VERSION 5.8 ;
BUSBITCHARS "[]" ;
DIVIDERCHAR "/" ;
UNITS
    DATABASE MICRONS 1000 ;
END UNITS

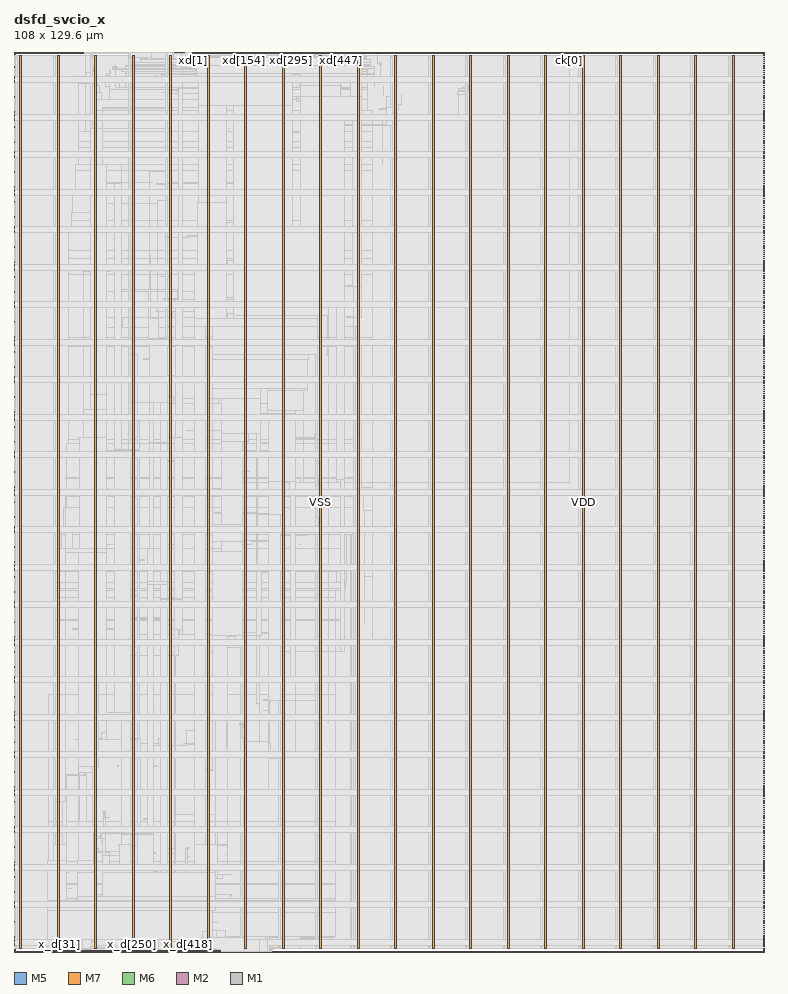
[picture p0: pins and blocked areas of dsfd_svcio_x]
MACRO dsfd_svcio_x
  FOREIGN dsfd_svcio_x 0 0 ;
  CLASS BLOCK ;
  SIZE 108 BY 129.6 ;
  PIN ck[0]
    DIRECTION INPUT ;
    USE SIGNAL ;
    PORT
      LAYER M5 ;
        RECT  79.968 129.408 79.992 129.6 ;
    END
  END ck[0]
  PIN rst[0]
    DIRECTION INPUT ;
    USE SIGNAL ;
    PORT
      LAYER M5 ;
        RECT  81.888 129.408 81.912 129.6 ;
    END
  END rst[0]
  PIN x_d[0]
    DIRECTION INPUT ;
    USE SIGNAL ;
    PORT
      LAYER M5 ;
        RECT  4.992 0 5.016 0.192 ;
    END
  END x_d[0]
  PIN x_d[100]
    DIRECTION INPUT ;
    USE SIGNAL ;
    PORT
      LAYER M5 ;
        RECT  9.792 0 9.816 0.192 ;
    END
  END x_d[100]
  PIN x_d[101]
    DIRECTION INPUT ;
    USE SIGNAL ;
    PORT
      LAYER M5 ;
        RECT  9.84 0 9.864 0.192 ;
    END
  END x_d[101]
  PIN x_d[102]
    DIRECTION INPUT ;
    USE SIGNAL ;
    PORT
      LAYER M5 ;
        RECT  9.888 0 9.912 0.192 ;
    END
  END x_d[102]
  PIN x_d[103]
    DIRECTION INPUT ;
    USE SIGNAL ;
    PORT
      LAYER M5 ;
        RECT  9.936 0 9.96 0.192 ;
    END
  END x_d[103]
  PIN x_d[104]
    DIRECTION INPUT ;
    USE SIGNAL ;
    PORT
      LAYER M5 ;
        RECT  9.984 0 10.008 0.192 ;
    END
  END x_d[104]
  PIN x_d[105]
    DIRECTION INPUT ;
    USE SIGNAL ;
    PORT
      LAYER M5 ;
        RECT  10.032 0 10.056 0.192 ;
    END
  END x_d[105]
  PIN x_d[106]
    DIRECTION INPUT ;
    USE SIGNAL ;
    PORT
      LAYER M5 ;
        RECT  10.08 0 10.104 0.192 ;
    END
  END x_d[106]
  PIN x_d[107]
    DIRECTION INPUT ;
    USE SIGNAL ;
    PORT
      LAYER M5 ;
        RECT  10.128 0 10.152 0.192 ;
    END
  END x_d[107]
  PIN x_d[108]
    DIRECTION INPUT ;
    USE SIGNAL ;
    PORT
      LAYER M5 ;
        RECT  10.176 0 10.2 0.192 ;
    END
  END x_d[108]
  PIN x_d[109]
    DIRECTION INPUT ;
    USE SIGNAL ;
    PORT
      LAYER M5 ;
        RECT  10.224 0 10.248 0.192 ;
    END
  END x_d[109]
  PIN x_d[10]
    DIRECTION INPUT ;
    USE SIGNAL ;
    PORT
      LAYER M5 ;
        RECT  5.472 0 5.496 0.192 ;
    END
  END x_d[10]
  PIN x_d[110]
    DIRECTION INPUT ;
    USE SIGNAL ;
    PORT
      LAYER M5 ;
        RECT  10.272 0 10.296 0.192 ;
    END
  END x_d[110]
  PIN x_d[111]
    DIRECTION INPUT ;
    USE SIGNAL ;
    PORT
      LAYER M5 ;
        RECT  10.32 0 10.344 0.192 ;
    END
  END x_d[111]
  PIN x_d[112]
    DIRECTION INPUT ;
    USE SIGNAL ;
    PORT
      LAYER M5 ;
        RECT  10.368 0 10.392 0.192 ;
    END
  END x_d[112]
  PIN x_d[113]
    DIRECTION INPUT ;
    USE SIGNAL ;
    PORT
      LAYER M5 ;
        RECT  10.416 0 10.44 0.192 ;
    END
  END x_d[113]
  PIN x_d[114]
    DIRECTION INPUT ;
    USE SIGNAL ;
    PORT
      LAYER M5 ;
        RECT  10.464 0 10.488 0.192 ;
    END
  END x_d[114]
  PIN x_d[115]
    DIRECTION INPUT ;
    USE SIGNAL ;
    PORT
      LAYER M5 ;
        RECT  10.512 0 10.536 0.192 ;
    END
  END x_d[115]
  PIN x_d[116]
    DIRECTION INPUT ;
    USE SIGNAL ;
    PORT
      LAYER M5 ;
        RECT  10.56 0 10.584 0.192 ;
    END
  END x_d[116]
  PIN x_d[117]
    DIRECTION INPUT ;
    USE SIGNAL ;
    PORT
      LAYER M5 ;
        RECT  10.608 0 10.632 0.192 ;
    END
  END x_d[117]
  PIN x_d[118]
    DIRECTION INPUT ;
    USE SIGNAL ;
    PORT
      LAYER M5 ;
        RECT  10.656 0 10.68 0.192 ;
    END
  END x_d[118]
  PIN x_d[119]
    DIRECTION INPUT ;
    USE SIGNAL ;
    PORT
      LAYER M5 ;
        RECT  10.704 0 10.728 0.192 ;
    END
  END x_d[119]
  PIN x_d[11]
    DIRECTION INPUT ;
    USE SIGNAL ;
    PORT
      LAYER M5 ;
        RECT  5.52 0 5.544 0.192 ;
    END
  END x_d[11]
  PIN x_d[120]
    DIRECTION INPUT ;
    USE SIGNAL ;
    PORT
      LAYER M5 ;
        RECT  10.752 0 10.776 0.192 ;
    END
  END x_d[120]
  PIN x_d[121]
    DIRECTION INPUT ;
    USE SIGNAL ;
    PORT
      LAYER M5 ;
        RECT  10.8 0 10.824 0.192 ;
    END
  END x_d[121]
  PIN x_d[122]
    DIRECTION INPUT ;
    USE SIGNAL ;
    PORT
      LAYER M5 ;
        RECT  10.848 0 10.872 0.192 ;
    END
  END x_d[122]
  PIN x_d[123]
    DIRECTION INPUT ;
    USE SIGNAL ;
    PORT
      LAYER M5 ;
        RECT  10.896 0 10.92 0.192 ;
    END
  END x_d[123]
  PIN x_d[124]
    DIRECTION INPUT ;
    USE SIGNAL ;
    PORT
      LAYER M5 ;
        RECT  10.944 0 10.968 0.192 ;
    END
  END x_d[124]
  PIN x_d[125]
    DIRECTION INPUT ;
    USE SIGNAL ;
    PORT
      LAYER M5 ;
        RECT  10.992 0 11.016 0.192 ;
    END
  END x_d[125]
  PIN x_d[126]
    DIRECTION INPUT ;
    USE SIGNAL ;
    PORT
      LAYER M5 ;
        RECT  11.04 0 11.064 0.192 ;
    END
  END x_d[126]
  PIN x_d[127]
    DIRECTION INPUT ;
    USE SIGNAL ;
    PORT
      LAYER M5 ;
        RECT  11.088 0 11.112 0.192 ;
    END
  END x_d[127]
  PIN x_d[128]
    DIRECTION INPUT ;
    USE SIGNAL ;
    PORT
      LAYER M5 ;
        RECT  11.136 0 11.16 0.192 ;
    END
  END x_d[128]
  PIN x_d[129]
    DIRECTION INPUT ;
    USE SIGNAL ;
    PORT
      LAYER M5 ;
        RECT  11.184 0 11.208 0.192 ;
    END
  END x_d[129]
  PIN x_d[12]
    DIRECTION INPUT ;
    USE SIGNAL ;
    PORT
      LAYER M5 ;
        RECT  5.568 0 5.592 0.192 ;
    END
  END x_d[12]
  PIN x_d[130]
    DIRECTION INPUT ;
    USE SIGNAL ;
    PORT
      LAYER M5 ;
        RECT  11.232 0 11.256 0.192 ;
    END
  END x_d[130]
  PIN x_d[131]
    DIRECTION INPUT ;
    USE SIGNAL ;
    PORT
      LAYER M5 ;
        RECT  11.28 0 11.304 0.192 ;
    END
  END x_d[131]
  PIN x_d[132]
    DIRECTION INPUT ;
    USE SIGNAL ;
    PORT
      LAYER M5 ;
        RECT  11.328 0 11.352 0.192 ;
    END
  END x_d[132]
  PIN x_d[133]
    DIRECTION INPUT ;
    USE SIGNAL ;
    PORT
      LAYER M5 ;
        RECT  11.376 0 11.4 0.192 ;
    END
  END x_d[133]
  PIN x_d[134]
    DIRECTION INPUT ;
    USE SIGNAL ;
    PORT
      LAYER M5 ;
        RECT  11.424 0 11.448 0.192 ;
    END
  END x_d[134]
  PIN x_d[135]
    DIRECTION INPUT ;
    USE SIGNAL ;
    PORT
      LAYER M5 ;
        RECT  11.472 0 11.496 0.192 ;
    END
  END x_d[135]
  PIN x_d[136]
    DIRECTION INPUT ;
    USE SIGNAL ;
    PORT
      LAYER M5 ;
        RECT  11.52 0 11.544 0.192 ;
    END
  END x_d[136]
  PIN x_d[137]
    DIRECTION INPUT ;
    USE SIGNAL ;
    PORT
      LAYER M5 ;
        RECT  11.568 0 11.592 0.192 ;
    END
  END x_d[137]
  PIN x_d[138]
    DIRECTION INPUT ;
    USE SIGNAL ;
    PORT
      LAYER M5 ;
        RECT  11.616 0 11.64 0.192 ;
    END
  END x_d[138]
  PIN x_d[139]
    DIRECTION INPUT ;
    USE SIGNAL ;
    PORT
      LAYER M5 ;
        RECT  11.664 0 11.688 0.192 ;
    END
  END x_d[139]
  PIN x_d[13]
    DIRECTION INPUT ;
    USE SIGNAL ;
    PORT
      LAYER M5 ;
        RECT  5.616 0 5.64 0.192 ;
    END
  END x_d[13]
  PIN x_d[140]
    DIRECTION INPUT ;
    USE SIGNAL ;
    PORT
      LAYER M5 ;
        RECT  11.712 0 11.736 0.192 ;
    END
  END x_d[140]
  PIN x_d[141]
    DIRECTION INPUT ;
    USE SIGNAL ;
    PORT
      LAYER M5 ;
        RECT  11.76 0 11.784 0.192 ;
    END
  END x_d[141]
  PIN x_d[142]
    DIRECTION INPUT ;
    USE SIGNAL ;
    PORT
      LAYER M5 ;
        RECT  11.808 0 11.832 0.192 ;
    END
  END x_d[142]
  PIN x_d[143]
    DIRECTION INPUT ;
    USE SIGNAL ;
    PORT
      LAYER M5 ;
        RECT  11.856 0 11.88 0.192 ;
    END
  END x_d[143]
  PIN x_d[144]
    DIRECTION INPUT ;
    USE SIGNAL ;
    PORT
      LAYER M5 ;
        RECT  11.904 0 11.928 0.192 ;
    END
  END x_d[144]
  PIN x_d[145]
    DIRECTION INPUT ;
    USE SIGNAL ;
    PORT
      LAYER M5 ;
        RECT  11.952 0 11.976 0.192 ;
    END
  END x_d[145]
  PIN x_d[146]
    DIRECTION INPUT ;
    USE SIGNAL ;
    PORT
      LAYER M5 ;
        RECT  12 0 12.024 0.192 ;
    END
  END x_d[146]
  PIN x_d[147]
    DIRECTION INPUT ;
    USE SIGNAL ;
    PORT
      LAYER M5 ;
        RECT  12.048 0 12.072 0.192 ;
    END
  END x_d[147]
  PIN x_d[148]
    DIRECTION INPUT ;
    USE SIGNAL ;
    PORT
      LAYER M5 ;
        RECT  12.096 0 12.12 0.192 ;
    END
  END x_d[148]
  PIN x_d[149]
    DIRECTION INPUT ;
    USE SIGNAL ;
    PORT
      LAYER M5 ;
        RECT  12.144 0 12.168 0.192 ;
    END
  END x_d[149]
  PIN x_d[14]
    DIRECTION INPUT ;
    USE SIGNAL ;
    PORT
      LAYER M5 ;
        RECT  5.664 0 5.688 0.192 ;
    END
  END x_d[14]
  PIN x_d[150]
    DIRECTION INPUT ;
    USE SIGNAL ;
    PORT
      LAYER M5 ;
        RECT  12.192 0 12.216 0.192 ;
    END
  END x_d[150]
  PIN x_d[151]
    DIRECTION INPUT ;
    USE SIGNAL ;
    PORT
      LAYER M5 ;
        RECT  12.24 0 12.264 0.192 ;
    END
  END x_d[151]
  PIN x_d[152]
    DIRECTION INPUT ;
    USE SIGNAL ;
    PORT
      LAYER M5 ;
        RECT  12.288 0 12.312 0.192 ;
    END
  END x_d[152]
  PIN x_d[153]
    DIRECTION INPUT ;
    USE SIGNAL ;
    PORT
      LAYER M5 ;
        RECT  12.336 0 12.36 0.192 ;
    END
  END x_d[153]
  PIN x_d[154]
    DIRECTION INPUT ;
    USE SIGNAL ;
    PORT
      LAYER M5 ;
        RECT  12.384 0 12.408 0.192 ;
    END
  END x_d[154]
  PIN x_d[155]
    DIRECTION INPUT ;
    USE SIGNAL ;
    PORT
      LAYER M5 ;
        RECT  12.432 0 12.456 0.192 ;
    END
  END x_d[155]
  PIN x_d[156]
    DIRECTION INPUT ;
    USE SIGNAL ;
    PORT
      LAYER M5 ;
        RECT  12.48 0 12.504 0.192 ;
    END
  END x_d[156]
  PIN x_d[157]
    DIRECTION INPUT ;
    USE SIGNAL ;
    PORT
      LAYER M5 ;
        RECT  12.528 0 12.552 0.192 ;
    END
  END x_d[157]
  PIN x_d[158]
    DIRECTION INPUT ;
    USE SIGNAL ;
    PORT
      LAYER M5 ;
        RECT  12.576 0 12.6 0.192 ;
    END
  END x_d[158]
  PIN x_d[159]
    DIRECTION INPUT ;
    USE SIGNAL ;
    PORT
      LAYER M5 ;
        RECT  12.624 0 12.648 0.192 ;
    END
  END x_d[159]
  PIN x_d[15]
    DIRECTION INPUT ;
    USE SIGNAL ;
    PORT
      LAYER M5 ;
        RECT  5.712 0 5.736 0.192 ;
    END
  END x_d[15]
  PIN x_d[160]
    DIRECTION INPUT ;
    USE SIGNAL ;
    PORT
      LAYER M5 ;
        RECT  12.672 0 12.696 0.192 ;
    END
  END x_d[160]
  PIN x_d[161]
    DIRECTION INPUT ;
    USE SIGNAL ;
    PORT
      LAYER M5 ;
        RECT  12.72 0 12.744 0.192 ;
    END
  END x_d[161]
  PIN x_d[162]
    DIRECTION INPUT ;
    USE SIGNAL ;
    PORT
      LAYER M5 ;
        RECT  12.768 0 12.792 0.192 ;
    END
  END x_d[162]
  PIN x_d[163]
    DIRECTION INPUT ;
    USE SIGNAL ;
    PORT
      LAYER M5 ;
        RECT  12.816 0 12.84 0.192 ;
    END
  END x_d[163]
  PIN x_d[164]
    DIRECTION INPUT ;
    USE SIGNAL ;
    PORT
      LAYER M5 ;
        RECT  12.864 0 12.888 0.192 ;
    END
  END x_d[164]
  PIN x_d[165]
    DIRECTION INPUT ;
    USE SIGNAL ;
    PORT
      LAYER M5 ;
        RECT  12.912 0 12.936 0.192 ;
    END
  END x_d[165]
  PIN x_d[166]
    DIRECTION INPUT ;
    USE SIGNAL ;
    PORT
      LAYER M5 ;
        RECT  12.96 0 12.984 0.192 ;
    END
  END x_d[166]
  PIN x_d[167]
    DIRECTION INPUT ;
    USE SIGNAL ;
    PORT
      LAYER M5 ;
        RECT  13.008 0 13.032 0.192 ;
    END
  END x_d[167]
  PIN x_d[168]
    DIRECTION INPUT ;
    USE SIGNAL ;
    PORT
      LAYER M5 ;
        RECT  13.056 0 13.08 0.192 ;
    END
  END x_d[168]
  PIN x_d[169]
    DIRECTION INPUT ;
    USE SIGNAL ;
    PORT
      LAYER M5 ;
        RECT  13.104 0 13.128 0.192 ;
    END
  END x_d[169]
  PIN x_d[16]
    DIRECTION INPUT ;
    USE SIGNAL ;
    PORT
      LAYER M5 ;
        RECT  5.76 0 5.784 0.192 ;
    END
  END x_d[16]
  PIN x_d[170]
    DIRECTION INPUT ;
    USE SIGNAL ;
    PORT
      LAYER M5 ;
        RECT  13.152 0 13.176 0.192 ;
    END
  END x_d[170]
  PIN x_d[171]
    DIRECTION INPUT ;
    USE SIGNAL ;
    PORT
      LAYER M5 ;
        RECT  13.2 0 13.224 0.192 ;
    END
  END x_d[171]
  PIN x_d[172]
    DIRECTION INPUT ;
    USE SIGNAL ;
    PORT
      LAYER M5 ;
        RECT  13.248 0 13.272 0.192 ;
    END
  END x_d[172]
  PIN x_d[173]
    DIRECTION INPUT ;
    USE SIGNAL ;
    PORT
      LAYER M5 ;
        RECT  13.296 0 13.32 0.192 ;
    END
  END x_d[173]
  PIN x_d[174]
    DIRECTION INPUT ;
    USE SIGNAL ;
    PORT
      LAYER M5 ;
        RECT  13.344 0 13.368 0.192 ;
    END
  END x_d[174]
  PIN x_d[175]
    DIRECTION INPUT ;
    USE SIGNAL ;
    PORT
      LAYER M5 ;
        RECT  13.392 0 13.416 0.192 ;
    END
  END x_d[175]
  PIN x_d[176]
    DIRECTION INPUT ;
    USE SIGNAL ;
    PORT
      LAYER M5 ;
        RECT  13.44 0 13.464 0.192 ;
    END
  END x_d[176]
  PIN x_d[177]
    DIRECTION INPUT ;
    USE SIGNAL ;
    PORT
      LAYER M5 ;
        RECT  13.488 0 13.512 0.192 ;
    END
  END x_d[177]
  PIN x_d[178]
    DIRECTION INPUT ;
    USE SIGNAL ;
    PORT
      LAYER M5 ;
        RECT  13.536 0 13.56 0.192 ;
    END
  END x_d[178]
  PIN x_d[179]
    DIRECTION INPUT ;
    USE SIGNAL ;
    PORT
      LAYER M5 ;
        RECT  13.584 0 13.608 0.192 ;
    END
  END x_d[179]
  PIN x_d[17]
    DIRECTION INPUT ;
    USE SIGNAL ;
    PORT
      LAYER M5 ;
        RECT  5.808 0 5.832 0.192 ;
    END
  END x_d[17]
  PIN x_d[180]
    DIRECTION INPUT ;
    USE SIGNAL ;
    PORT
      LAYER M5 ;
        RECT  13.632 0 13.656 0.192 ;
    END
  END x_d[180]
  PIN x_d[181]
    DIRECTION INPUT ;
    USE SIGNAL ;
    PORT
      LAYER M5 ;
        RECT  13.68 0 13.704 0.192 ;
    END
  END x_d[181]
  PIN x_d[182]
    DIRECTION INPUT ;
    USE SIGNAL ;
    PORT
      LAYER M5 ;
        RECT  13.728 0 13.752 0.192 ;
    END
  END x_d[182]
  PIN x_d[183]
    DIRECTION INPUT ;
    USE SIGNAL ;
    PORT
      LAYER M5 ;
        RECT  13.776 0 13.8 0.192 ;
    END
  END x_d[183]
  PIN x_d[184]
    DIRECTION INPUT ;
    USE SIGNAL ;
    PORT
      LAYER M5 ;
        RECT  13.824 0 13.848 0.192 ;
    END
  END x_d[184]
  PIN x_d[185]
    DIRECTION INPUT ;
    USE SIGNAL ;
    PORT
      LAYER M5 ;
        RECT  13.872 0 13.896 0.192 ;
    END
  END x_d[185]
  PIN x_d[186]
    DIRECTION INPUT ;
    USE SIGNAL ;
    PORT
      LAYER M5 ;
        RECT  13.92 0 13.944 0.192 ;
    END
  END x_d[186]
  PIN x_d[187]
    DIRECTION INPUT ;
    USE SIGNAL ;
    PORT
      LAYER M5 ;
        RECT  13.968 0 13.992 0.192 ;
    END
  END x_d[187]
  PIN x_d[188]
    DIRECTION INPUT ;
    USE SIGNAL ;
    PORT
      LAYER M5 ;
        RECT  14.016 0 14.04 0.192 ;
    END
  END x_d[188]
  PIN x_d[189]
    DIRECTION INPUT ;
    USE SIGNAL ;
    PORT
      LAYER M5 ;
        RECT  14.064 0 14.088 0.192 ;
    END
  END x_d[189]
  PIN x_d[18]
    DIRECTION INPUT ;
    USE SIGNAL ;
    PORT
      LAYER M5 ;
        RECT  5.856 0 5.88 0.192 ;
    END
  END x_d[18]
  PIN x_d[190]
    DIRECTION INPUT ;
    USE SIGNAL ;
    PORT
      LAYER M5 ;
        RECT  14.112 0 14.136 0.192 ;
    END
  END x_d[190]
  PIN x_d[191]
    DIRECTION INPUT ;
    USE SIGNAL ;
    PORT
      LAYER M5 ;
        RECT  14.16 0 14.184 0.192 ;
    END
  END x_d[191]
  PIN x_d[192]
    DIRECTION INPUT ;
    USE SIGNAL ;
    PORT
      LAYER M5 ;
        RECT  14.208 0 14.232 0.192 ;
    END
  END x_d[192]
  PIN x_d[193]
    DIRECTION INPUT ;
    USE SIGNAL ;
    PORT
      LAYER M5 ;
        RECT  14.256 0 14.28 0.192 ;
    END
  END x_d[193]
  PIN x_d[194]
    DIRECTION INPUT ;
    USE SIGNAL ;
    PORT
      LAYER M5 ;
        RECT  14.304 0 14.328 0.192 ;
    END
  END x_d[194]
  PIN x_d[195]
    DIRECTION INPUT ;
    USE SIGNAL ;
    PORT
      LAYER M5 ;
        RECT  14.352 0 14.376 0.192 ;
    END
  END x_d[195]
  PIN x_d[196]
    DIRECTION INPUT ;
    USE SIGNAL ;
    PORT
      LAYER M5 ;
        RECT  14.4 0 14.424 0.192 ;
    END
  END x_d[196]
  PIN x_d[197]
    DIRECTION INPUT ;
    USE SIGNAL ;
    PORT
      LAYER M5 ;
        RECT  14.448 0 14.472 0.192 ;
    END
  END x_d[197]
  PIN x_d[198]
    DIRECTION INPUT ;
    USE SIGNAL ;
    PORT
      LAYER M5 ;
        RECT  14.496 0 14.52 0.192 ;
    END
  END x_d[198]
  PIN x_d[199]
    DIRECTION INPUT ;
    USE SIGNAL ;
    PORT
      LAYER M5 ;
        RECT  14.544 0 14.568 0.192 ;
    END
  END x_d[199]
  PIN x_d[19]
    DIRECTION INPUT ;
    USE SIGNAL ;
    PORT
      LAYER M5 ;
        RECT  5.904 0 5.928 0.192 ;
    END
  END x_d[19]
  PIN x_d[1]
    DIRECTION INPUT ;
    USE SIGNAL ;
    PORT
      LAYER M5 ;
        RECT  5.04 0 5.064 0.192 ;
    END
  END x_d[1]
  PIN x_d[200]
    DIRECTION INPUT ;
    USE SIGNAL ;
    PORT
      LAYER M5 ;
        RECT  14.592 0 14.616 0.192 ;
    END
  END x_d[200]
  PIN x_d[201]
    DIRECTION INPUT ;
    USE SIGNAL ;
    PORT
      LAYER M5 ;
        RECT  14.64 0 14.664 0.192 ;
    END
  END x_d[201]
  PIN x_d[202]
    DIRECTION INPUT ;
    USE SIGNAL ;
    PORT
      LAYER M5 ;
        RECT  14.688 0 14.712 0.192 ;
    END
  END x_d[202]
  PIN x_d[203]
    DIRECTION INPUT ;
    USE SIGNAL ;
    PORT
      LAYER M5 ;
        RECT  14.736 0 14.76 0.192 ;
    END
  END x_d[203]
  PIN x_d[204]
    DIRECTION INPUT ;
    USE SIGNAL ;
    PORT
      LAYER M5 ;
        RECT  14.784 0 14.808 0.192 ;
    END
  END x_d[204]
  PIN x_d[205]
    DIRECTION INPUT ;
    USE SIGNAL ;
    PORT
      LAYER M5 ;
        RECT  14.832 0 14.856 0.192 ;
    END
  END x_d[205]
  PIN x_d[206]
    DIRECTION INPUT ;
    USE SIGNAL ;
    PORT
      LAYER M5 ;
        RECT  14.88 0 14.904 0.192 ;
    END
  END x_d[206]
  PIN x_d[207]
    DIRECTION INPUT ;
    USE SIGNAL ;
    PORT
      LAYER M5 ;
        RECT  14.928 0 14.952 0.192 ;
    END
  END x_d[207]
  PIN x_d[208]
    DIRECTION INPUT ;
    USE SIGNAL ;
    PORT
      LAYER M5 ;
        RECT  14.976 0 15 0.192 ;
    END
  END x_d[208]
  PIN x_d[209]
    DIRECTION INPUT ;
    USE SIGNAL ;
    PORT
      LAYER M5 ;
        RECT  15.024 0 15.048 0.192 ;
    END
  END x_d[209]
  PIN x_d[20]
    DIRECTION INPUT ;
    USE SIGNAL ;
    PORT
      LAYER M5 ;
        RECT  5.952 0 5.976 0.192 ;
    END
  END x_d[20]
  PIN x_d[210]
    DIRECTION INPUT ;
    USE SIGNAL ;
    PORT
      LAYER M5 ;
        RECT  15.072 0 15.096 0.192 ;
    END
  END x_d[210]
  PIN x_d[211]
    DIRECTION INPUT ;
    USE SIGNAL ;
    PORT
      LAYER M5 ;
        RECT  15.12 0 15.144 0.192 ;
    END
  END x_d[211]
  PIN x_d[212]
    DIRECTION INPUT ;
    USE SIGNAL ;
    PORT
      LAYER M5 ;
        RECT  15.168 0 15.192 0.192 ;
    END
  END x_d[212]
  PIN x_d[213]
    DIRECTION INPUT ;
    USE SIGNAL ;
    PORT
      LAYER M5 ;
        RECT  15.216 0 15.24 0.192 ;
    END
  END x_d[213]
  PIN x_d[214]
    DIRECTION INPUT ;
    USE SIGNAL ;
    PORT
      LAYER M5 ;
        RECT  15.264 0 15.288 0.192 ;
    END
  END x_d[214]
  PIN x_d[215]
    DIRECTION INPUT ;
    USE SIGNAL ;
    PORT
      LAYER M5 ;
        RECT  15.312 0 15.336 0.192 ;
    END
  END x_d[215]
  PIN x_d[216]
    DIRECTION INPUT ;
    USE SIGNAL ;
    PORT
      LAYER M5 ;
        RECT  15.36 0 15.384 0.192 ;
    END
  END x_d[216]
  PIN x_d[217]
    DIRECTION INPUT ;
    USE SIGNAL ;
    PORT
      LAYER M5 ;
        RECT  15.408 0 15.432 0.192 ;
    END
  END x_d[217]
  PIN x_d[218]
    DIRECTION INPUT ;
    USE SIGNAL ;
    PORT
      LAYER M5 ;
        RECT  15.456 0 15.48 0.192 ;
    END
  END x_d[218]
  PIN x_d[219]
    DIRECTION INPUT ;
    USE SIGNAL ;
    PORT
      LAYER M5 ;
        RECT  15.504 0 15.528 0.192 ;
    END
  END x_d[219]
  PIN x_d[21]
    DIRECTION INPUT ;
    USE SIGNAL ;
    PORT
      LAYER M5 ;
        RECT  6 0 6.024 0.192 ;
    END
  END x_d[21]
  PIN x_d[220]
    DIRECTION INPUT ;
    USE SIGNAL ;
    PORT
      LAYER M5 ;
        RECT  15.552 0 15.576 0.192 ;
    END
  END x_d[220]
  PIN x_d[221]
    DIRECTION INPUT ;
    USE SIGNAL ;
    PORT
      LAYER M5 ;
        RECT  15.6 0 15.624 0.192 ;
    END
  END x_d[221]
  PIN x_d[222]
    DIRECTION INPUT ;
    USE SIGNAL ;
    PORT
      LAYER M5 ;
        RECT  15.648 0 15.672 0.192 ;
    END
  END x_d[222]
  PIN x_d[223]
    DIRECTION INPUT ;
    USE SIGNAL ;
    PORT
      LAYER M5 ;
        RECT  15.696 0 15.72 0.192 ;
    END
  END x_d[223]
  PIN x_d[224]
    DIRECTION INPUT ;
    USE SIGNAL ;
    PORT
      LAYER M5 ;
        RECT  15.744 0 15.768 0.192 ;
    END
  END x_d[224]
  PIN x_d[225]
    DIRECTION INPUT ;
    USE SIGNAL ;
    PORT
      LAYER M5 ;
        RECT  15.792 0 15.816 0.192 ;
    END
  END x_d[225]
  PIN x_d[226]
    DIRECTION INPUT ;
    USE SIGNAL ;
    PORT
      LAYER M5 ;
        RECT  15.84 0 15.864 0.192 ;
    END
  END x_d[226]
  PIN x_d[227]
    DIRECTION INPUT ;
    USE SIGNAL ;
    PORT
      LAYER M5 ;
        RECT  15.888 0 15.912 0.192 ;
    END
  END x_d[227]
  PIN x_d[228]
    DIRECTION INPUT ;
    USE SIGNAL ;
    PORT
      LAYER M5 ;
        RECT  15.936 0 15.96 0.192 ;
    END
  END x_d[228]
  PIN x_d[229]
    DIRECTION INPUT ;
    USE SIGNAL ;
    PORT
      LAYER M5 ;
        RECT  15.984 0 16.008 0.192 ;
    END
  END x_d[229]
  PIN x_d[22]
    DIRECTION INPUT ;
    USE SIGNAL ;
    PORT
      LAYER M5 ;
        RECT  6.048 0 6.072 0.192 ;
    END
  END x_d[22]
  PIN x_d[230]
    DIRECTION INPUT ;
    USE SIGNAL ;
    PORT
      LAYER M5 ;
        RECT  16.032 0 16.056 0.192 ;
    END
  END x_d[230]
  PIN x_d[231]
    DIRECTION INPUT ;
    USE SIGNAL ;
    PORT
      LAYER M5 ;
        RECT  16.08 0 16.104 0.192 ;
    END
  END x_d[231]
  PIN x_d[232]
    DIRECTION INPUT ;
    USE SIGNAL ;
    PORT
      LAYER M5 ;
        RECT  16.128 0 16.152 0.192 ;
    END
  END x_d[232]
  PIN x_d[233]
    DIRECTION INPUT ;
    USE SIGNAL ;
    PORT
      LAYER M5 ;
        RECT  16.176 0 16.2 0.192 ;
    END
  END x_d[233]
  PIN x_d[234]
    DIRECTION INPUT ;
    USE SIGNAL ;
    PORT
      LAYER M5 ;
        RECT  16.224 0 16.248 0.192 ;
    END
  END x_d[234]
  PIN x_d[235]
    DIRECTION INPUT ;
    USE SIGNAL ;
    PORT
      LAYER M5 ;
        RECT  16.272 0 16.296 0.192 ;
    END
  END x_d[235]
  PIN x_d[236]
    DIRECTION INPUT ;
    USE SIGNAL ;
    PORT
      LAYER M5 ;
        RECT  16.32 0 16.344 0.192 ;
    END
  END x_d[236]
  PIN x_d[237]
    DIRECTION INPUT ;
    USE SIGNAL ;
    PORT
      LAYER M5 ;
        RECT  16.368 0 16.392 0.192 ;
    END
  END x_d[237]
  PIN x_d[238]
    DIRECTION INPUT ;
    USE SIGNAL ;
    PORT
      LAYER M5 ;
        RECT  16.416 0 16.44 0.192 ;
    END
  END x_d[238]
  PIN x_d[239]
    DIRECTION INPUT ;
    USE SIGNAL ;
    PORT
      LAYER M5 ;
        RECT  16.464 0 16.488 0.192 ;
    END
  END x_d[239]
  PIN x_d[23]
    DIRECTION INPUT ;
    USE SIGNAL ;
    PORT
      LAYER M5 ;
        RECT  6.096 0 6.12 0.192 ;
    END
  END x_d[23]
  PIN x_d[240]
    DIRECTION INPUT ;
    USE SIGNAL ;
    PORT
      LAYER M5 ;
        RECT  16.512 0 16.536 0.192 ;
    END
  END x_d[240]
  PIN x_d[241]
    DIRECTION INPUT ;
    USE SIGNAL ;
    PORT
      LAYER M5 ;
        RECT  16.56 0 16.584 0.192 ;
    END
  END x_d[241]
  PIN x_d[242]
    DIRECTION INPUT ;
    USE SIGNAL ;
    PORT
      LAYER M5 ;
        RECT  16.608 0 16.632 0.192 ;
    END
  END x_d[242]
  PIN x_d[243]
    DIRECTION INPUT ;
    USE SIGNAL ;
    PORT
      LAYER M5 ;
        RECT  16.656 0 16.68 0.192 ;
    END
  END x_d[243]
  PIN x_d[244]
    DIRECTION INPUT ;
    USE SIGNAL ;
    PORT
      LAYER M5 ;
        RECT  16.704 0 16.728 0.192 ;
    END
  END x_d[244]
  PIN x_d[245]
    DIRECTION INPUT ;
    USE SIGNAL ;
    PORT
      LAYER M5 ;
        RECT  16.752 0 16.776 0.192 ;
    END
  END x_d[245]
  PIN x_d[246]
    DIRECTION INPUT ;
    USE SIGNAL ;
    PORT
      LAYER M5 ;
        RECT  16.8 0 16.824 0.192 ;
    END
  END x_d[246]
  PIN x_d[247]
    DIRECTION INPUT ;
    USE SIGNAL ;
    PORT
      LAYER M5 ;
        RECT  16.848 0 16.872 0.192 ;
    END
  END x_d[247]
  PIN x_d[248]
    DIRECTION INPUT ;
    USE SIGNAL ;
    PORT
      LAYER M5 ;
        RECT  16.896 0 16.92 0.192 ;
    END
  END x_d[248]
  PIN x_d[249]
    DIRECTION INPUT ;
    USE SIGNAL ;
    PORT
      LAYER M5 ;
        RECT  16.944 0 16.968 0.192 ;
    END
  END x_d[249]
  PIN x_d[24]
    DIRECTION INPUT ;
    USE SIGNAL ;
    PORT
      LAYER M5 ;
        RECT  6.144 0 6.168 0.192 ;
    END
  END x_d[24]
  PIN x_d[250]
    DIRECTION INPUT ;
    USE SIGNAL ;
    PORT
      LAYER M5 ;
        RECT  16.992 0 17.016 0.192 ;
    END
  END x_d[250]
  PIN x_d[251]
    DIRECTION INPUT ;
    USE SIGNAL ;
    PORT
      LAYER M5 ;
        RECT  17.04 0 17.064 0.192 ;
    END
  END x_d[251]
  PIN x_d[252]
    DIRECTION INPUT ;
    USE SIGNAL ;
    PORT
      LAYER M5 ;
        RECT  17.088 0 17.112 0.192 ;
    END
  END x_d[252]
  PIN x_d[253]
    DIRECTION INPUT ;
    USE SIGNAL ;
    PORT
      LAYER M5 ;
        RECT  17.136 0 17.16 0.192 ;
    END
  END x_d[253]
  PIN x_d[254]
    DIRECTION INPUT ;
    USE SIGNAL ;
    PORT
      LAYER M5 ;
        RECT  17.184 0 17.208 0.192 ;
    END
  END x_d[254]
  PIN x_d[255]
    DIRECTION INPUT ;
    USE SIGNAL ;
    PORT
      LAYER M5 ;
        RECT  17.232 0 17.256 0.192 ;
    END
  END x_d[255]
  PIN x_d[256]
    DIRECTION INPUT ;
    USE SIGNAL ;
    PORT
      LAYER M5 ;
        RECT  17.28 0 17.304 0.192 ;
    END
  END x_d[256]
  PIN x_d[257]
    DIRECTION INPUT ;
    USE SIGNAL ;
    PORT
      LAYER M5 ;
        RECT  17.328 0 17.352 0.192 ;
    END
  END x_d[257]
  PIN x_d[258]
    DIRECTION INPUT ;
    USE SIGNAL ;
    PORT
      LAYER M5 ;
        RECT  17.376 0 17.4 0.192 ;
    END
  END x_d[258]
  PIN x_d[259]
    DIRECTION INPUT ;
    USE SIGNAL ;
    PORT
      LAYER M5 ;
        RECT  17.424 0 17.448 0.192 ;
    END
  END x_d[259]
  PIN x_d[25]
    DIRECTION INPUT ;
    USE SIGNAL ;
    PORT
      LAYER M5 ;
        RECT  6.192 0 6.216 0.192 ;
    END
  END x_d[25]
  PIN x_d[260]
    DIRECTION INPUT ;
    USE SIGNAL ;
    PORT
      LAYER M5 ;
        RECT  17.472 0 17.496 0.192 ;
    END
  END x_d[260]
  PIN x_d[261]
    DIRECTION INPUT ;
    USE SIGNAL ;
    PORT
      LAYER M5 ;
        RECT  17.52 0 17.544 0.192 ;
    END
  END x_d[261]
  PIN x_d[262]
    DIRECTION INPUT ;
    USE SIGNAL ;
    PORT
      LAYER M5 ;
        RECT  17.568 0 17.592 0.192 ;
    END
  END x_d[262]
  PIN x_d[263]
    DIRECTION INPUT ;
    USE SIGNAL ;
    PORT
      LAYER M5 ;
        RECT  17.616 0 17.64 0.192 ;
    END
  END x_d[263]
  PIN x_d[264]
    DIRECTION INPUT ;
    USE SIGNAL ;
    PORT
      LAYER M5 ;
        RECT  17.664 0 17.688 0.192 ;
    END
  END x_d[264]
  PIN x_d[265]
    DIRECTION INPUT ;
    USE SIGNAL ;
    PORT
      LAYER M5 ;
        RECT  17.712 0 17.736 0.192 ;
    END
  END x_d[265]
  PIN x_d[266]
    DIRECTION INPUT ;
    USE SIGNAL ;
    PORT
      LAYER M5 ;
        RECT  17.76 0 17.784 0.192 ;
    END
  END x_d[266]
  PIN x_d[267]
    DIRECTION INPUT ;
    USE SIGNAL ;
    PORT
      LAYER M5 ;
        RECT  17.808 0 17.832 0.192 ;
    END
  END x_d[267]
  PIN x_d[268]
    DIRECTION INPUT ;
    USE SIGNAL ;
    PORT
      LAYER M5 ;
        RECT  17.856 0 17.88 0.192 ;
    END
  END x_d[268]
  PIN x_d[269]
    DIRECTION INPUT ;
    USE SIGNAL ;
    PORT
      LAYER M5 ;
        RECT  17.904 0 17.928 0.192 ;
    END
  END x_d[269]
  PIN x_d[26]
    DIRECTION INPUT ;
    USE SIGNAL ;
    PORT
      LAYER M5 ;
        RECT  6.24 0 6.264 0.192 ;
    END
  END x_d[26]
  PIN x_d[270]
    DIRECTION INPUT ;
    USE SIGNAL ;
    PORT
      LAYER M5 ;
        RECT  17.952 0 17.976 0.192 ;
    END
  END x_d[270]
  PIN x_d[271]
    DIRECTION INPUT ;
    USE SIGNAL ;
    PORT
      LAYER M5 ;
        RECT  18 0 18.024 0.192 ;
    END
  END x_d[271]
  PIN x_d[272]
    DIRECTION INPUT ;
    USE SIGNAL ;
    PORT
      LAYER M5 ;
        RECT  18.048 0 18.072 0.192 ;
    END
  END x_d[272]
  PIN x_d[273]
    DIRECTION INPUT ;
    USE SIGNAL ;
    PORT
      LAYER M5 ;
        RECT  18.096 0 18.12 0.192 ;
    END
  END x_d[273]
  PIN x_d[274]
    DIRECTION INPUT ;
    USE SIGNAL ;
    PORT
      LAYER M5 ;
        RECT  18.144 0 18.168 0.192 ;
    END
  END x_d[274]
  PIN x_d[275]
    DIRECTION INPUT ;
    USE SIGNAL ;
    PORT
      LAYER M5 ;
        RECT  18.192 0 18.216 0.192 ;
    END
  END x_d[275]
  PIN x_d[276]
    DIRECTION INPUT ;
    USE SIGNAL ;
    PORT
      LAYER M5 ;
        RECT  18.24 0 18.264 0.192 ;
    END
  END x_d[276]
  PIN x_d[277]
    DIRECTION INPUT ;
    USE SIGNAL ;
    PORT
      LAYER M5 ;
        RECT  18.288 0 18.312 0.192 ;
    END
  END x_d[277]
  PIN x_d[278]
    DIRECTION INPUT ;
    USE SIGNAL ;
    PORT
      LAYER M5 ;
        RECT  18.336 0 18.36 0.192 ;
    END
  END x_d[278]
  PIN x_d[279]
    DIRECTION INPUT ;
    USE SIGNAL ;
    PORT
      LAYER M5 ;
        RECT  18.384 0 18.408 0.192 ;
    END
  END x_d[279]
  PIN x_d[27]
    DIRECTION INPUT ;
    USE SIGNAL ;
    PORT
      LAYER M5 ;
        RECT  6.288 0 6.312 0.192 ;
    END
  END x_d[27]
  PIN x_d[280]
    DIRECTION INPUT ;
    USE SIGNAL ;
    PORT
      LAYER M5 ;
        RECT  18.432 0 18.456 0.192 ;
    END
  END x_d[280]
  PIN x_d[281]
    DIRECTION INPUT ;
    USE SIGNAL ;
    PORT
      LAYER M5 ;
        RECT  18.48 0 18.504 0.192 ;
    END
  END x_d[281]
  PIN x_d[282]
    DIRECTION INPUT ;
    USE SIGNAL ;
    PORT
      LAYER M5 ;
        RECT  18.528 0 18.552 0.192 ;
    END
  END x_d[282]
  PIN x_d[283]
    DIRECTION INPUT ;
    USE SIGNAL ;
    PORT
      LAYER M5 ;
        RECT  18.576 0 18.6 0.192 ;
    END
  END x_d[283]
  PIN x_d[284]
    DIRECTION INPUT ;
    USE SIGNAL ;
    PORT
      LAYER M5 ;
        RECT  18.624 0 18.648 0.192 ;
    END
  END x_d[284]
  PIN x_d[285]
    DIRECTION INPUT ;
    USE SIGNAL ;
    PORT
      LAYER M5 ;
        RECT  18.672 0 18.696 0.192 ;
    END
  END x_d[285]
  PIN x_d[286]
    DIRECTION INPUT ;
    USE SIGNAL ;
    PORT
      LAYER M5 ;
        RECT  18.72 0 18.744 0.192 ;
    END
  END x_d[286]
  PIN x_d[287]
    DIRECTION INPUT ;
    USE SIGNAL ;
    PORT
      LAYER M5 ;
        RECT  18.768 0 18.792 0.192 ;
    END
  END x_d[287]
  PIN x_d[288]
    DIRECTION INPUT ;
    USE SIGNAL ;
    PORT
      LAYER M5 ;
        RECT  18.816 0 18.84 0.192 ;
    END
  END x_d[288]
  PIN x_d[289]
    DIRECTION INPUT ;
    USE SIGNAL ;
    PORT
      LAYER M5 ;
        RECT  18.864 0 18.888 0.192 ;
    END
  END x_d[289]
  PIN x_d[28]
    DIRECTION INPUT ;
    USE SIGNAL ;
    PORT
      LAYER M5 ;
        RECT  6.336 0 6.36 0.192 ;
    END
  END x_d[28]
  PIN x_d[290]
    DIRECTION INPUT ;
    USE SIGNAL ;
    PORT
      LAYER M5 ;
        RECT  18.912 0 18.936 0.192 ;
    END
  END x_d[290]
  PIN x_d[291]
    DIRECTION INPUT ;
    USE SIGNAL ;
    PORT
      LAYER M5 ;
        RECT  18.96 0 18.984 0.192 ;
    END
  END x_d[291]
  PIN x_d[292]
    DIRECTION INPUT ;
    USE SIGNAL ;
    PORT
      LAYER M5 ;
        RECT  19.008 0 19.032 0.192 ;
    END
  END x_d[292]
  PIN x_d[293]
    DIRECTION INPUT ;
    USE SIGNAL ;
    PORT
      LAYER M5 ;
        RECT  19.056 0 19.08 0.192 ;
    END
  END x_d[293]
  PIN x_d[294]
    DIRECTION INPUT ;
    USE SIGNAL ;
    PORT
      LAYER M5 ;
        RECT  19.104 0 19.128 0.192 ;
    END
  END x_d[294]
  PIN x_d[295]
    DIRECTION INPUT ;
    USE SIGNAL ;
    PORT
      LAYER M5 ;
        RECT  19.152 0 19.176 0.192 ;
    END
  END x_d[295]
  PIN x_d[296]
    DIRECTION INPUT ;
    USE SIGNAL ;
    PORT
      LAYER M5 ;
        RECT  19.2 0 19.224 0.192 ;
    END
  END x_d[296]
  PIN x_d[297]
    DIRECTION INPUT ;
    USE SIGNAL ;
    PORT
      LAYER M5 ;
        RECT  19.248 0 19.272 0.192 ;
    END
  END x_d[297]
  PIN x_d[298]
    DIRECTION INPUT ;
    USE SIGNAL ;
    PORT
      LAYER M5 ;
        RECT  19.296 0 19.32 0.192 ;
    END
  END x_d[298]
  PIN x_d[299]
    DIRECTION INPUT ;
    USE SIGNAL ;
    PORT
      LAYER M5 ;
        RECT  19.344 0 19.368 0.192 ;
    END
  END x_d[299]
  PIN x_d[29]
    DIRECTION INPUT ;
    USE SIGNAL ;
    PORT
      LAYER M5 ;
        RECT  6.384 0 6.408 0.192 ;
    END
  END x_d[29]
  PIN x_d[2]
    DIRECTION INPUT ;
    USE SIGNAL ;
    PORT
      LAYER M5 ;
        RECT  5.088 0 5.112 0.192 ;
    END
  END x_d[2]
  PIN x_d[300]
    DIRECTION INPUT ;
    USE SIGNAL ;
    PORT
      LAYER M5 ;
        RECT  19.392 0 19.416 0.192 ;
    END
  END x_d[300]
  PIN x_d[301]
    DIRECTION INPUT ;
    USE SIGNAL ;
    PORT
      LAYER M5 ;
        RECT  19.44 0 19.464 0.192 ;
    END
  END x_d[301]
  PIN x_d[302]
    DIRECTION INPUT ;
    USE SIGNAL ;
    PORT
      LAYER M5 ;
        RECT  19.488 0 19.512 0.192 ;
    END
  END x_d[302]
  PIN x_d[303]
    DIRECTION INPUT ;
    USE SIGNAL ;
    PORT
      LAYER M5 ;
        RECT  19.536 0 19.56 0.192 ;
    END
  END x_d[303]
  PIN x_d[304]
    DIRECTION INPUT ;
    USE SIGNAL ;
    PORT
      LAYER M5 ;
        RECT  19.584 0 19.608 0.192 ;
    END
  END x_d[304]
  PIN x_d[305]
    DIRECTION INPUT ;
    USE SIGNAL ;
    PORT
      LAYER M5 ;
        RECT  19.632 0 19.656 0.192 ;
    END
  END x_d[305]
  PIN x_d[306]
    DIRECTION INPUT ;
    USE SIGNAL ;
    PORT
      LAYER M5 ;
        RECT  19.68 0 19.704 0.192 ;
    END
  END x_d[306]
  PIN x_d[307]
    DIRECTION INPUT ;
    USE SIGNAL ;
    PORT
      LAYER M5 ;
        RECT  19.728 0 19.752 0.192 ;
    END
  END x_d[307]
  PIN x_d[308]
    DIRECTION INPUT ;
    USE SIGNAL ;
    PORT
      LAYER M5 ;
        RECT  19.776 0 19.8 0.192 ;
    END
  END x_d[308]
  PIN x_d[309]
    DIRECTION INPUT ;
    USE SIGNAL ;
    PORT
      LAYER M5 ;
        RECT  19.824 0 19.848 0.192 ;
    END
  END x_d[309]
  PIN x_d[30]
    DIRECTION INPUT ;
    USE SIGNAL ;
    PORT
      LAYER M5 ;
        RECT  6.432 0 6.456 0.192 ;
    END
  END x_d[30]
  PIN x_d[310]
    DIRECTION INPUT ;
    USE SIGNAL ;
    PORT
      LAYER M5 ;
        RECT  19.872 0 19.896 0.192 ;
    END
  END x_d[310]
  PIN x_d[311]
    DIRECTION INPUT ;
    USE SIGNAL ;
    PORT
      LAYER M5 ;
        RECT  19.92 0 19.944 0.192 ;
    END
  END x_d[311]
  PIN x_d[312]
    DIRECTION INPUT ;
    USE SIGNAL ;
    PORT
      LAYER M5 ;
        RECT  19.968 0 19.992 0.192 ;
    END
  END x_d[312]
  PIN x_d[313]
    DIRECTION INPUT ;
    USE SIGNAL ;
    PORT
      LAYER M5 ;
        RECT  20.016 0 20.04 0.192 ;
    END
  END x_d[313]
  PIN x_d[314]
    DIRECTION INPUT ;
    USE SIGNAL ;
    PORT
      LAYER M5 ;
        RECT  20.064 0 20.088 0.192 ;
    END
  END x_d[314]
  PIN x_d[315]
    DIRECTION INPUT ;
    USE SIGNAL ;
    PORT
      LAYER M5 ;
        RECT  20.112 0 20.136 0.192 ;
    END
  END x_d[315]
  PIN x_d[316]
    DIRECTION INPUT ;
    USE SIGNAL ;
    PORT
      LAYER M5 ;
        RECT  20.16 0 20.184 0.192 ;
    END
  END x_d[316]
  PIN x_d[317]
    DIRECTION INPUT ;
    USE SIGNAL ;
    PORT
      LAYER M5 ;
        RECT  20.208 0 20.232 0.192 ;
    END
  END x_d[317]
  PIN x_d[318]
    DIRECTION INPUT ;
    USE SIGNAL ;
    PORT
      LAYER M5 ;
        RECT  20.256 0 20.28 0.192 ;
    END
  END x_d[318]
  PIN x_d[319]
    DIRECTION INPUT ;
    USE SIGNAL ;
    PORT
      LAYER M5 ;
        RECT  20.304 0 20.328 0.192 ;
    END
  END x_d[319]
  PIN x_d[31]
    DIRECTION INPUT ;
    USE SIGNAL ;
    PORT
      LAYER M5 ;
        RECT  6.48 0 6.504 0.192 ;
    END
  END x_d[31]
  PIN x_d[320]
    DIRECTION INPUT ;
    USE SIGNAL ;
    PORT
      LAYER M5 ;
        RECT  20.352 0 20.376 0.192 ;
    END
  END x_d[320]
  PIN x_d[321]
    DIRECTION INPUT ;
    USE SIGNAL ;
    PORT
      LAYER M5 ;
        RECT  20.4 0 20.424 0.192 ;
    END
  END x_d[321]
  PIN x_d[322]
    DIRECTION INPUT ;
    USE SIGNAL ;
    PORT
      LAYER M5 ;
        RECT  20.448 0 20.472 0.192 ;
    END
  END x_d[322]
  PIN x_d[323]
    DIRECTION INPUT ;
    USE SIGNAL ;
    PORT
      LAYER M5 ;
        RECT  20.496 0 20.52 0.192 ;
    END
  END x_d[323]
  PIN x_d[324]
    DIRECTION INPUT ;
    USE SIGNAL ;
    PORT
      LAYER M5 ;
        RECT  20.544 0 20.568 0.192 ;
    END
  END x_d[324]
  PIN x_d[325]
    DIRECTION INPUT ;
    USE SIGNAL ;
    PORT
      LAYER M5 ;
        RECT  20.592 0 20.616 0.192 ;
    END
  END x_d[325]
  PIN x_d[326]
    DIRECTION INPUT ;
    USE SIGNAL ;
    PORT
      LAYER M5 ;
        RECT  20.64 0 20.664 0.192 ;
    END
  END x_d[326]
  PIN x_d[327]
    DIRECTION INPUT ;
    USE SIGNAL ;
    PORT
      LAYER M5 ;
        RECT  20.688 0 20.712 0.192 ;
    END
  END x_d[327]
  PIN x_d[328]
    DIRECTION INPUT ;
    USE SIGNAL ;
    PORT
      LAYER M5 ;
        RECT  20.736 0 20.76 0.192 ;
    END
  END x_d[328]
  PIN x_d[329]
    DIRECTION INPUT ;
    USE SIGNAL ;
    PORT
      LAYER M5 ;
        RECT  20.784 0 20.808 0.192 ;
    END
  END x_d[329]
  PIN x_d[32]
    DIRECTION INPUT ;
    USE SIGNAL ;
    PORT
      LAYER M5 ;
        RECT  6.528 0 6.552 0.192 ;
    END
  END x_d[32]
  PIN x_d[330]
    DIRECTION INPUT ;
    USE SIGNAL ;
    PORT
      LAYER M5 ;
        RECT  20.832 0 20.856 0.192 ;
    END
  END x_d[330]
  PIN x_d[331]
    DIRECTION INPUT ;
    USE SIGNAL ;
    PORT
      LAYER M5 ;
        RECT  20.88 0 20.904 0.192 ;
    END
  END x_d[331]
  PIN x_d[332]
    DIRECTION INPUT ;
    USE SIGNAL ;
    PORT
      LAYER M5 ;
        RECT  20.928 0 20.952 0.192 ;
    END
  END x_d[332]
  PIN x_d[333]
    DIRECTION INPUT ;
    USE SIGNAL ;
    PORT
      LAYER M5 ;
        RECT  20.976 0 21 0.192 ;
    END
  END x_d[333]
  PIN x_d[334]
    DIRECTION INPUT ;
    USE SIGNAL ;
    PORT
      LAYER M5 ;
        RECT  21.024 0 21.048 0.192 ;
    END
  END x_d[334]
  PIN x_d[335]
    DIRECTION INPUT ;
    USE SIGNAL ;
    PORT
      LAYER M5 ;
        RECT  21.072 0 21.096 0.192 ;
    END
  END x_d[335]
  PIN x_d[336]
    DIRECTION INPUT ;
    USE SIGNAL ;
    PORT
      LAYER M5 ;
        RECT  21.12 0 21.144 0.192 ;
    END
  END x_d[336]
  PIN x_d[337]
    DIRECTION INPUT ;
    USE SIGNAL ;
    PORT
      LAYER M5 ;
        RECT  21.168 0 21.192 0.192 ;
    END
  END x_d[337]
  PIN x_d[338]
    DIRECTION INPUT ;
    USE SIGNAL ;
    PORT
      LAYER M5 ;
        RECT  21.216 0 21.24 0.192 ;
    END
  END x_d[338]
  PIN x_d[339]
    DIRECTION INPUT ;
    USE SIGNAL ;
    PORT
      LAYER M5 ;
        RECT  21.264 0 21.288 0.192 ;
    END
  END x_d[339]
  PIN x_d[33]
    DIRECTION INPUT ;
    USE SIGNAL ;
    PORT
      LAYER M5 ;
        RECT  6.576 0 6.6 0.192 ;
    END
  END x_d[33]
  PIN x_d[340]
    DIRECTION INPUT ;
    USE SIGNAL ;
    PORT
      LAYER M5 ;
        RECT  21.312 0 21.336 0.192 ;
    END
  END x_d[340]
  PIN x_d[341]
    DIRECTION INPUT ;
    USE SIGNAL ;
    PORT
      LAYER M5 ;
        RECT  21.36 0 21.384 0.192 ;
    END
  END x_d[341]
  PIN x_d[342]
    DIRECTION INPUT ;
    USE SIGNAL ;
    PORT
      LAYER M5 ;
        RECT  21.408 0 21.432 0.192 ;
    END
  END x_d[342]
  PIN x_d[343]
    DIRECTION INPUT ;
    USE SIGNAL ;
    PORT
      LAYER M5 ;
        RECT  21.456 0 21.48 0.192 ;
    END
  END x_d[343]
  PIN x_d[344]
    DIRECTION INPUT ;
    USE SIGNAL ;
    PORT
      LAYER M5 ;
        RECT  21.504 0 21.528 0.192 ;
    END
  END x_d[344]
  PIN x_d[345]
    DIRECTION INPUT ;
    USE SIGNAL ;
    PORT
      LAYER M5 ;
        RECT  21.552 0 21.576 0.192 ;
    END
  END x_d[345]
  PIN x_d[346]
    DIRECTION INPUT ;
    USE SIGNAL ;
    PORT
      LAYER M5 ;
        RECT  21.6 0 21.624 0.192 ;
    END
  END x_d[346]
  PIN x_d[347]
    DIRECTION INPUT ;
    USE SIGNAL ;
    PORT
      LAYER M5 ;
        RECT  21.648 0 21.672 0.192 ;
    END
  END x_d[347]
  PIN x_d[348]
    DIRECTION INPUT ;
    USE SIGNAL ;
    PORT
      LAYER M5 ;
        RECT  21.696 0 21.72 0.192 ;
    END
  END x_d[348]
  PIN x_d[349]
    DIRECTION INPUT ;
    USE SIGNAL ;
    PORT
      LAYER M5 ;
        RECT  21.744 0 21.768 0.192 ;
    END
  END x_d[349]
  PIN x_d[34]
    DIRECTION INPUT ;
    USE SIGNAL ;
    PORT
      LAYER M5 ;
        RECT  6.624 0 6.648 0.192 ;
    END
  END x_d[34]
  PIN x_d[350]
    DIRECTION INPUT ;
    USE SIGNAL ;
    PORT
      LAYER M5 ;
        RECT  21.792 0 21.816 0.192 ;
    END
  END x_d[350]
  PIN x_d[351]
    DIRECTION INPUT ;
    USE SIGNAL ;
    PORT
      LAYER M5 ;
        RECT  21.84 0 21.864 0.192 ;
    END
  END x_d[351]
  PIN x_d[352]
    DIRECTION INPUT ;
    USE SIGNAL ;
    PORT
      LAYER M5 ;
        RECT  21.888 0 21.912 0.192 ;
    END
  END x_d[352]
  PIN x_d[353]
    DIRECTION INPUT ;
    USE SIGNAL ;
    PORT
      LAYER M5 ;
        RECT  21.936 0 21.96 0.192 ;
    END
  END x_d[353]
  PIN x_d[354]
    DIRECTION INPUT ;
    USE SIGNAL ;
    PORT
      LAYER M5 ;
        RECT  21.984 0 22.008 0.192 ;
    END
  END x_d[354]
  PIN x_d[355]
    DIRECTION INPUT ;
    USE SIGNAL ;
    PORT
      LAYER M5 ;
        RECT  22.032 0 22.056 0.192 ;
    END
  END x_d[355]
  PIN x_d[356]
    DIRECTION INPUT ;
    USE SIGNAL ;
    PORT
      LAYER M5 ;
        RECT  22.08 0 22.104 0.192 ;
    END
  END x_d[356]
  PIN x_d[357]
    DIRECTION INPUT ;
    USE SIGNAL ;
    PORT
      LAYER M5 ;
        RECT  22.128 0 22.152 0.192 ;
    END
  END x_d[357]
  PIN x_d[358]
    DIRECTION INPUT ;
    USE SIGNAL ;
    PORT
      LAYER M5 ;
        RECT  22.176 0 22.2 0.192 ;
    END
  END x_d[358]
  PIN x_d[359]
    DIRECTION INPUT ;
    USE SIGNAL ;
    PORT
      LAYER M5 ;
        RECT  22.224 0 22.248 0.192 ;
    END
  END x_d[359]
  PIN x_d[35]
    DIRECTION INPUT ;
    USE SIGNAL ;
    PORT
      LAYER M5 ;
        RECT  6.672 0 6.696 0.192 ;
    END
  END x_d[35]
  PIN x_d[360]
    DIRECTION INPUT ;
    USE SIGNAL ;
    PORT
      LAYER M5 ;
        RECT  22.272 0 22.296 0.192 ;
    END
  END x_d[360]
  PIN x_d[361]
    DIRECTION INPUT ;
    USE SIGNAL ;
    PORT
      LAYER M5 ;
        RECT  22.32 0 22.344 0.192 ;
    END
  END x_d[361]
  PIN x_d[362]
    DIRECTION INPUT ;
    USE SIGNAL ;
    PORT
      LAYER M5 ;
        RECT  22.368 0 22.392 0.192 ;
    END
  END x_d[362]
  PIN x_d[363]
    DIRECTION INPUT ;
    USE SIGNAL ;
    PORT
      LAYER M5 ;
        RECT  22.416 0 22.44 0.192 ;
    END
  END x_d[363]
  PIN x_d[364]
    DIRECTION INPUT ;
    USE SIGNAL ;
    PORT
      LAYER M5 ;
        RECT  22.464 0 22.488 0.192 ;
    END
  END x_d[364]
  PIN x_d[365]
    DIRECTION INPUT ;
    USE SIGNAL ;
    PORT
      LAYER M5 ;
        RECT  22.512 0 22.536 0.192 ;
    END
  END x_d[365]
  PIN x_d[366]
    DIRECTION INPUT ;
    USE SIGNAL ;
    PORT
      LAYER M5 ;
        RECT  22.56 0 22.584 0.192 ;
    END
  END x_d[366]
  PIN x_d[367]
    DIRECTION INPUT ;
    USE SIGNAL ;
    PORT
      LAYER M5 ;
        RECT  22.608 0 22.632 0.192 ;
    END
  END x_d[367]
  PIN x_d[368]
    DIRECTION INPUT ;
    USE SIGNAL ;
    PORT
      LAYER M5 ;
        RECT  22.656 0 22.68 0.192 ;
    END
  END x_d[368]
  PIN x_d[369]
    DIRECTION INPUT ;
    USE SIGNAL ;
    PORT
      LAYER M5 ;
        RECT  22.704 0 22.728 0.192 ;
    END
  END x_d[369]
  PIN x_d[36]
    DIRECTION INPUT ;
    USE SIGNAL ;
    PORT
      LAYER M5 ;
        RECT  6.72 0 6.744 0.192 ;
    END
  END x_d[36]
  PIN x_d[370]
    DIRECTION INPUT ;
    USE SIGNAL ;
    PORT
      LAYER M5 ;
        RECT  22.752 0 22.776 0.192 ;
    END
  END x_d[370]
  PIN x_d[371]
    DIRECTION INPUT ;
    USE SIGNAL ;
    PORT
      LAYER M5 ;
        RECT  22.8 0 22.824 0.192 ;
    END
  END x_d[371]
  PIN x_d[372]
    DIRECTION INPUT ;
    USE SIGNAL ;
    PORT
      LAYER M5 ;
        RECT  22.848 0 22.872 0.192 ;
    END
  END x_d[372]
  PIN x_d[373]
    DIRECTION INPUT ;
    USE SIGNAL ;
    PORT
      LAYER M5 ;
        RECT  22.896 0 22.92 0.192 ;
    END
  END x_d[373]
  PIN x_d[374]
    DIRECTION INPUT ;
    USE SIGNAL ;
    PORT
      LAYER M5 ;
        RECT  22.944 0 22.968 0.192 ;
    END
  END x_d[374]
  PIN x_d[375]
    DIRECTION INPUT ;
    USE SIGNAL ;
    PORT
      LAYER M5 ;
        RECT  22.992 0 23.016 0.192 ;
    END
  END x_d[375]
  PIN x_d[376]
    DIRECTION INPUT ;
    USE SIGNAL ;
    PORT
      LAYER M5 ;
        RECT  23.04 0 23.064 0.192 ;
    END
  END x_d[376]
  PIN x_d[377]
    DIRECTION INPUT ;
    USE SIGNAL ;
    PORT
      LAYER M5 ;
        RECT  23.088 0 23.112 0.192 ;
    END
  END x_d[377]
  PIN x_d[378]
    DIRECTION INPUT ;
    USE SIGNAL ;
    PORT
      LAYER M5 ;
        RECT  23.136 0 23.16 0.192 ;
    END
  END x_d[378]
  PIN x_d[379]
    DIRECTION INPUT ;
    USE SIGNAL ;
    PORT
      LAYER M5 ;
        RECT  23.184 0 23.208 0.192 ;
    END
  END x_d[379]
  PIN x_d[37]
    DIRECTION INPUT ;
    USE SIGNAL ;
    PORT
      LAYER M5 ;
        RECT  6.768 0 6.792 0.192 ;
    END
  END x_d[37]
  PIN x_d[380]
    DIRECTION INPUT ;
    USE SIGNAL ;
    PORT
      LAYER M5 ;
        RECT  23.232 0 23.256 0.192 ;
    END
  END x_d[380]
  PIN x_d[381]
    DIRECTION INPUT ;
    USE SIGNAL ;
    PORT
      LAYER M5 ;
        RECT  23.28 0 23.304 0.192 ;
    END
  END x_d[381]
  PIN x_d[382]
    DIRECTION INPUT ;
    USE SIGNAL ;
    PORT
      LAYER M5 ;
        RECT  23.328 0 23.352 0.192 ;
    END
  END x_d[382]
  PIN x_d[383]
    DIRECTION INPUT ;
    USE SIGNAL ;
    PORT
      LAYER M5 ;
        RECT  23.376 0 23.4 0.192 ;
    END
  END x_d[383]
  PIN x_d[384]
    DIRECTION INPUT ;
    USE SIGNAL ;
    PORT
      LAYER M5 ;
        RECT  23.424 0 23.448 0.192 ;
    END
  END x_d[384]
  PIN x_d[385]
    DIRECTION INPUT ;
    USE SIGNAL ;
    PORT
      LAYER M5 ;
        RECT  23.472 0 23.496 0.192 ;
    END
  END x_d[385]
  PIN x_d[386]
    DIRECTION INPUT ;
    USE SIGNAL ;
    PORT
      LAYER M5 ;
        RECT  23.52 0 23.544 0.192 ;
    END
  END x_d[386]
  PIN x_d[387]
    DIRECTION INPUT ;
    USE SIGNAL ;
    PORT
      LAYER M5 ;
        RECT  23.568 0 23.592 0.192 ;
    END
  END x_d[387]
  PIN x_d[388]
    DIRECTION INPUT ;
    USE SIGNAL ;
    PORT
      LAYER M5 ;
        RECT  23.616 0 23.64 0.192 ;
    END
  END x_d[388]
  PIN x_d[389]
    DIRECTION INPUT ;
    USE SIGNAL ;
    PORT
      LAYER M5 ;
        RECT  23.664 0 23.688 0.192 ;
    END
  END x_d[389]
  PIN x_d[38]
    DIRECTION INPUT ;
    USE SIGNAL ;
    PORT
      LAYER M5 ;
        RECT  6.816 0 6.84 0.192 ;
    END
  END x_d[38]
  PIN x_d[390]
    DIRECTION INPUT ;
    USE SIGNAL ;
    PORT
      LAYER M5 ;
        RECT  23.712 0 23.736 0.192 ;
    END
  END x_d[390]
  PIN x_d[391]
    DIRECTION INPUT ;
    USE SIGNAL ;
    PORT
      LAYER M5 ;
        RECT  23.76 0 23.784 0.192 ;
    END
  END x_d[391]
  PIN x_d[392]
    DIRECTION INPUT ;
    USE SIGNAL ;
    PORT
      LAYER M5 ;
        RECT  23.808 0 23.832 0.192 ;
    END
  END x_d[392]
  PIN x_d[393]
    DIRECTION INPUT ;
    USE SIGNAL ;
    PORT
      LAYER M5 ;
        RECT  23.856 0 23.88 0.192 ;
    END
  END x_d[393]
  PIN x_d[394]
    DIRECTION INPUT ;
    USE SIGNAL ;
    PORT
      LAYER M5 ;
        RECT  23.904 0 23.928 0.192 ;
    END
  END x_d[394]
  PIN x_d[395]
    DIRECTION INPUT ;
    USE SIGNAL ;
    PORT
      LAYER M5 ;
        RECT  23.952 0 23.976 0.192 ;
    END
  END x_d[395]
  PIN x_d[396]
    DIRECTION INPUT ;
    USE SIGNAL ;
    PORT
      LAYER M5 ;
        RECT  24 0 24.024 0.192 ;
    END
  END x_d[396]
  PIN x_d[397]
    DIRECTION INPUT ;
    USE SIGNAL ;
    PORT
      LAYER M5 ;
        RECT  24.048 0 24.072 0.192 ;
    END
  END x_d[397]
  PIN x_d[398]
    DIRECTION INPUT ;
    USE SIGNAL ;
    PORT
      LAYER M5 ;
        RECT  24.096 0 24.12 0.192 ;
    END
  END x_d[398]
  PIN x_d[399]
    DIRECTION INPUT ;
    USE SIGNAL ;
    PORT
      LAYER M5 ;
        RECT  24.144 0 24.168 0.192 ;
    END
  END x_d[399]
  PIN x_d[39]
    DIRECTION INPUT ;
    USE SIGNAL ;
    PORT
      LAYER M5 ;
        RECT  6.864 0 6.888 0.192 ;
    END
  END x_d[39]
  PIN x_d[3]
    DIRECTION INPUT ;
    USE SIGNAL ;
    PORT
      LAYER M5 ;
        RECT  5.136 0 5.16 0.192 ;
    END
  END x_d[3]
  PIN x_d[400]
    DIRECTION INPUT ;
    USE SIGNAL ;
    PORT
      LAYER M5 ;
        RECT  24.192 0 24.216 0.192 ;
    END
  END x_d[400]
  PIN x_d[401]
    DIRECTION INPUT ;
    USE SIGNAL ;
    PORT
      LAYER M5 ;
        RECT  24.24 0 24.264 0.192 ;
    END
  END x_d[401]
  PIN x_d[402]
    DIRECTION INPUT ;
    USE SIGNAL ;
    PORT
      LAYER M5 ;
        RECT  24.288 0 24.312 0.192 ;
    END
  END x_d[402]
  PIN x_d[403]
    DIRECTION INPUT ;
    USE SIGNAL ;
    PORT
      LAYER M5 ;
        RECT  24.336 0 24.36 0.192 ;
    END
  END x_d[403]
  PIN x_d[404]
    DIRECTION INPUT ;
    USE SIGNAL ;
    PORT
      LAYER M5 ;
        RECT  24.384 0 24.408 0.192 ;
    END
  END x_d[404]
  PIN x_d[405]
    DIRECTION INPUT ;
    USE SIGNAL ;
    PORT
      LAYER M5 ;
        RECT  24.432 0 24.456 0.192 ;
    END
  END x_d[405]
  PIN x_d[406]
    DIRECTION INPUT ;
    USE SIGNAL ;
    PORT
      LAYER M5 ;
        RECT  24.48 0 24.504 0.192 ;
    END
  END x_d[406]
  PIN x_d[407]
    DIRECTION INPUT ;
    USE SIGNAL ;
    PORT
      LAYER M5 ;
        RECT  24.528 0 24.552 0.192 ;
    END
  END x_d[407]
  PIN x_d[408]
    DIRECTION INPUT ;
    USE SIGNAL ;
    PORT
      LAYER M5 ;
        RECT  24.576 0 24.6 0.192 ;
    END
  END x_d[408]
  PIN x_d[409]
    DIRECTION INPUT ;
    USE SIGNAL ;
    PORT
      LAYER M5 ;
        RECT  24.624 0 24.648 0.192 ;
    END
  END x_d[409]
  PIN x_d[40]
    DIRECTION INPUT ;
    USE SIGNAL ;
    PORT
      LAYER M5 ;
        RECT  6.912 0 6.936 0.192 ;
    END
  END x_d[40]
  PIN x_d[410]
    DIRECTION INPUT ;
    USE SIGNAL ;
    PORT
      LAYER M5 ;
        RECT  24.672 0 24.696 0.192 ;
    END
  END x_d[410]
  PIN x_d[411]
    DIRECTION INPUT ;
    USE SIGNAL ;
    PORT
      LAYER M5 ;
        RECT  24.72 0 24.744 0.192 ;
    END
  END x_d[411]
  PIN x_d[412]
    DIRECTION INPUT ;
    USE SIGNAL ;
    PORT
      LAYER M5 ;
        RECT  24.768 0 24.792 0.192 ;
    END
  END x_d[412]
  PIN x_d[413]
    DIRECTION INPUT ;
    USE SIGNAL ;
    PORT
      LAYER M5 ;
        RECT  24.816 0 24.84 0.192 ;
    END
  END x_d[413]
  PIN x_d[414]
    DIRECTION INPUT ;
    USE SIGNAL ;
    PORT
      LAYER M5 ;
        RECT  24.864 0 24.888 0.192 ;
    END
  END x_d[414]
  PIN x_d[415]
    DIRECTION INPUT ;
    USE SIGNAL ;
    PORT
      LAYER M5 ;
        RECT  24.912 0 24.936 0.192 ;
    END
  END x_d[415]
  PIN x_d[416]
    DIRECTION INPUT ;
    USE SIGNAL ;
    PORT
      LAYER M5 ;
        RECT  24.96 0 24.984 0.192 ;
    END
  END x_d[416]
  PIN x_d[417]
    DIRECTION INPUT ;
    USE SIGNAL ;
    PORT
      LAYER M5 ;
        RECT  25.008 0 25.032 0.192 ;
    END
  END x_d[417]
  PIN x_d[418]
    DIRECTION INPUT ;
    USE SIGNAL ;
    PORT
      LAYER M5 ;
        RECT  25.056 0 25.08 0.192 ;
    END
  END x_d[418]
  PIN x_d[419]
    DIRECTION INPUT ;
    USE SIGNAL ;
    PORT
      LAYER M5 ;
        RECT  25.104 0 25.128 0.192 ;
    END
  END x_d[419]
  PIN x_d[41]
    DIRECTION INPUT ;
    USE SIGNAL ;
    PORT
      LAYER M5 ;
        RECT  6.96 0 6.984 0.192 ;
    END
  END x_d[41]
  PIN x_d[420]
    DIRECTION INPUT ;
    USE SIGNAL ;
    PORT
      LAYER M5 ;
        RECT  25.152 0 25.176 0.192 ;
    END
  END x_d[420]
  PIN x_d[421]
    DIRECTION INPUT ;
    USE SIGNAL ;
    PORT
      LAYER M5 ;
        RECT  25.2 0 25.224 0.192 ;
    END
  END x_d[421]
  PIN x_d[422]
    DIRECTION INPUT ;
    USE SIGNAL ;
    PORT
      LAYER M5 ;
        RECT  25.248 0 25.272 0.192 ;
    END
  END x_d[422]
  PIN x_d[423]
    DIRECTION INPUT ;
    USE SIGNAL ;
    PORT
      LAYER M5 ;
        RECT  25.296 0 25.32 0.192 ;
    END
  END x_d[423]
  PIN x_d[424]
    DIRECTION INPUT ;
    USE SIGNAL ;
    PORT
      LAYER M5 ;
        RECT  25.344 0 25.368 0.192 ;
    END
  END x_d[424]
  PIN x_d[425]
    DIRECTION INPUT ;
    USE SIGNAL ;
    PORT
      LAYER M5 ;
        RECT  25.392 0 25.416 0.192 ;
    END
  END x_d[425]
  PIN x_d[426]
    DIRECTION INPUT ;
    USE SIGNAL ;
    PORT
      LAYER M5 ;
        RECT  25.44 0 25.464 0.192 ;
    END
  END x_d[426]
  PIN x_d[427]
    DIRECTION INPUT ;
    USE SIGNAL ;
    PORT
      LAYER M5 ;
        RECT  25.488 0 25.512 0.192 ;
    END
  END x_d[427]
  PIN x_d[428]
    DIRECTION INPUT ;
    USE SIGNAL ;
    PORT
      LAYER M5 ;
        RECT  25.536 0 25.56 0.192 ;
    END
  END x_d[428]
  PIN x_d[429]
    DIRECTION INPUT ;
    USE SIGNAL ;
    PORT
      LAYER M5 ;
        RECT  25.584 0 25.608 0.192 ;
    END
  END x_d[429]
  PIN x_d[42]
    DIRECTION INPUT ;
    USE SIGNAL ;
    PORT
      LAYER M5 ;
        RECT  7.008 0 7.032 0.192 ;
    END
  END x_d[42]
  PIN x_d[430]
    DIRECTION INPUT ;
    USE SIGNAL ;
    PORT
      LAYER M5 ;
        RECT  25.632 0 25.656 0.192 ;
    END
  END x_d[430]
  PIN x_d[431]
    DIRECTION INPUT ;
    USE SIGNAL ;
    PORT
      LAYER M5 ;
        RECT  25.68 0 25.704 0.192 ;
    END
  END x_d[431]
  PIN x_d[432]
    DIRECTION INPUT ;
    USE SIGNAL ;
    PORT
      LAYER M5 ;
        RECT  25.728 0 25.752 0.192 ;
    END
  END x_d[432]
  PIN x_d[433]
    DIRECTION INPUT ;
    USE SIGNAL ;
    PORT
      LAYER M5 ;
        RECT  25.776 0 25.8 0.192 ;
    END
  END x_d[433]
  PIN x_d[434]
    DIRECTION INPUT ;
    USE SIGNAL ;
    PORT
      LAYER M5 ;
        RECT  25.824 0 25.848 0.192 ;
    END
  END x_d[434]
  PIN x_d[435]
    DIRECTION INPUT ;
    USE SIGNAL ;
    PORT
      LAYER M5 ;
        RECT  25.872 0 25.896 0.192 ;
    END
  END x_d[435]
  PIN x_d[436]
    DIRECTION INPUT ;
    USE SIGNAL ;
    PORT
      LAYER M5 ;
        RECT  25.92 0 25.944 0.192 ;
    END
  END x_d[436]
  PIN x_d[437]
    DIRECTION INPUT ;
    USE SIGNAL ;
    PORT
      LAYER M5 ;
        RECT  25.968 0 25.992 0.192 ;
    END
  END x_d[437]
  PIN x_d[438]
    DIRECTION INPUT ;
    USE SIGNAL ;
    PORT
      LAYER M5 ;
        RECT  26.016 0 26.04 0.192 ;
    END
  END x_d[438]
  PIN x_d[439]
    DIRECTION INPUT ;
    USE SIGNAL ;
    PORT
      LAYER M5 ;
        RECT  26.064 0 26.088 0.192 ;
    END
  END x_d[439]
  PIN x_d[43]
    DIRECTION INPUT ;
    USE SIGNAL ;
    PORT
      LAYER M5 ;
        RECT  7.056 0 7.08 0.192 ;
    END
  END x_d[43]
  PIN x_d[440]
    DIRECTION INPUT ;
    USE SIGNAL ;
    PORT
      LAYER M5 ;
        RECT  26.112 0 26.136 0.192 ;
    END
  END x_d[440]
  PIN x_d[441]
    DIRECTION INPUT ;
    USE SIGNAL ;
    PORT
      LAYER M5 ;
        RECT  26.16 0 26.184 0.192 ;
    END
  END x_d[441]
  PIN x_d[442]
    DIRECTION INPUT ;
    USE SIGNAL ;
    PORT
      LAYER M5 ;
        RECT  26.208 0 26.232 0.192 ;
    END
  END x_d[442]
  PIN x_d[443]
    DIRECTION INPUT ;
    USE SIGNAL ;
    PORT
      LAYER M5 ;
        RECT  26.256 0 26.28 0.192 ;
    END
  END x_d[443]
  PIN x_d[444]
    DIRECTION INPUT ;
    USE SIGNAL ;
    PORT
      LAYER M5 ;
        RECT  26.304 0 26.328 0.192 ;
    END
  END x_d[444]
  PIN x_d[445]
    DIRECTION INPUT ;
    USE SIGNAL ;
    PORT
      LAYER M5 ;
        RECT  26.352 0 26.376 0.192 ;
    END
  END x_d[445]
  PIN x_d[446]
    DIRECTION INPUT ;
    USE SIGNAL ;
    PORT
      LAYER M5 ;
        RECT  26.4 0 26.424 0.192 ;
    END
  END x_d[446]
  PIN x_d[447]
    DIRECTION INPUT ;
    USE SIGNAL ;
    PORT
      LAYER M5 ;
        RECT  26.448 0 26.472 0.192 ;
    END
  END x_d[447]
  PIN x_d[448]
    DIRECTION INPUT ;
    USE SIGNAL ;
    PORT
      LAYER M5 ;
        RECT  26.496 0 26.52 0.192 ;
    END
  END x_d[448]
  PIN x_d[449]
    DIRECTION INPUT ;
    USE SIGNAL ;
    PORT
      LAYER M5 ;
        RECT  26.544 0 26.568 0.192 ;
    END
  END x_d[449]
  PIN x_d[44]
    DIRECTION INPUT ;
    USE SIGNAL ;
    PORT
      LAYER M5 ;
        RECT  7.104 0 7.128 0.192 ;
    END
  END x_d[44]
  PIN x_d[450]
    DIRECTION INPUT ;
    USE SIGNAL ;
    PORT
      LAYER M5 ;
        RECT  26.592 0 26.616 0.192 ;
    END
  END x_d[450]
  PIN x_d[451]
    DIRECTION INPUT ;
    USE SIGNAL ;
    PORT
      LAYER M5 ;
        RECT  26.64 0 26.664 0.192 ;
    END
  END x_d[451]
  PIN x_d[452]
    DIRECTION INPUT ;
    USE SIGNAL ;
    PORT
      LAYER M5 ;
        RECT  26.688 0 26.712 0.192 ;
    END
  END x_d[452]
  PIN x_d[453]
    DIRECTION INPUT ;
    USE SIGNAL ;
    PORT
      LAYER M5 ;
        RECT  26.736 0 26.76 0.192 ;
    END
  END x_d[453]
  PIN x_d[454]
    DIRECTION INPUT ;
    USE SIGNAL ;
    PORT
      LAYER M5 ;
        RECT  26.784 0 26.808 0.192 ;
    END
  END x_d[454]
  PIN x_d[455]
    DIRECTION INPUT ;
    USE SIGNAL ;
    PORT
      LAYER M5 ;
        RECT  26.832 0 26.856 0.192 ;
    END
  END x_d[455]
  PIN x_d[456]
    DIRECTION INPUT ;
    USE SIGNAL ;
    PORT
      LAYER M5 ;
        RECT  26.88 0 26.904 0.192 ;
    END
  END x_d[456]
  PIN x_d[457]
    DIRECTION INPUT ;
    USE SIGNAL ;
    PORT
      LAYER M5 ;
        RECT  26.928 0 26.952 0.192 ;
    END
  END x_d[457]
  PIN x_d[458]
    DIRECTION INPUT ;
    USE SIGNAL ;
    PORT
      LAYER M5 ;
        RECT  26.976 0 27 0.192 ;
    END
  END x_d[458]
  PIN x_d[459]
    DIRECTION INPUT ;
    USE SIGNAL ;
    PORT
      LAYER M5 ;
        RECT  27.024 0 27.048 0.192 ;
    END
  END x_d[459]
  PIN x_d[45]
    DIRECTION INPUT ;
    USE SIGNAL ;
    PORT
      LAYER M5 ;
        RECT  7.152 0 7.176 0.192 ;
    END
  END x_d[45]
  PIN x_d[460]
    DIRECTION INPUT ;
    USE SIGNAL ;
    PORT
      LAYER M5 ;
        RECT  27.072 0 27.096 0.192 ;
    END
  END x_d[460]
  PIN x_d[461]
    DIRECTION INPUT ;
    USE SIGNAL ;
    PORT
      LAYER M5 ;
        RECT  27.12 0 27.144 0.192 ;
    END
  END x_d[461]
  PIN x_d[462]
    DIRECTION INPUT ;
    USE SIGNAL ;
    PORT
      LAYER M5 ;
        RECT  27.168 0 27.192 0.192 ;
    END
  END x_d[462]
  PIN x_d[463]
    DIRECTION INPUT ;
    USE SIGNAL ;
    PORT
      LAYER M5 ;
        RECT  27.216 0 27.24 0.192 ;
    END
  END x_d[463]
  PIN x_d[464]
    DIRECTION INPUT ;
    USE SIGNAL ;
    PORT
      LAYER M5 ;
        RECT  27.264 0 27.288 0.192 ;
    END
  END x_d[464]
  PIN x_d[465]
    DIRECTION INPUT ;
    USE SIGNAL ;
    PORT
      LAYER M5 ;
        RECT  27.312 0 27.336 0.192 ;
    END
  END x_d[465]
  PIN x_d[466]
    DIRECTION INPUT ;
    USE SIGNAL ;
    PORT
      LAYER M5 ;
        RECT  27.36 0 27.384 0.192 ;
    END
  END x_d[466]
  PIN x_d[467]
    DIRECTION INPUT ;
    USE SIGNAL ;
    PORT
      LAYER M5 ;
        RECT  27.408 0 27.432 0.192 ;
    END
  END x_d[467]
  PIN x_d[468]
    DIRECTION INPUT ;
    USE SIGNAL ;
    PORT
      LAYER M5 ;
        RECT  27.456 0 27.48 0.192 ;
    END
  END x_d[468]
  PIN x_d[469]
    DIRECTION INPUT ;
    USE SIGNAL ;
    PORT
      LAYER M5 ;
        RECT  27.504 0 27.528 0.192 ;
    END
  END x_d[469]
  PIN x_d[46]
    DIRECTION INPUT ;
    USE SIGNAL ;
    PORT
      LAYER M5 ;
        RECT  7.2 0 7.224 0.192 ;
    END
  END x_d[46]
  PIN x_d[470]
    DIRECTION INPUT ;
    USE SIGNAL ;
    PORT
      LAYER M5 ;
        RECT  27.552 0 27.576 0.192 ;
    END
  END x_d[470]
  PIN x_d[471]
    DIRECTION INPUT ;
    USE SIGNAL ;
    PORT
      LAYER M5 ;
        RECT  27.6 0 27.624 0.192 ;
    END
  END x_d[471]
  PIN x_d[472]
    DIRECTION INPUT ;
    USE SIGNAL ;
    PORT
      LAYER M5 ;
        RECT  27.648 0 27.672 0.192 ;
    END
  END x_d[472]
  PIN x_d[473]
    DIRECTION INPUT ;
    USE SIGNAL ;
    PORT
      LAYER M5 ;
        RECT  27.696 0 27.72 0.192 ;
    END
  END x_d[473]
  PIN x_d[474]
    DIRECTION INPUT ;
    USE SIGNAL ;
    PORT
      LAYER M5 ;
        RECT  27.744 0 27.768 0.192 ;
    END
  END x_d[474]
  PIN x_d[475]
    DIRECTION INPUT ;
    USE SIGNAL ;
    PORT
      LAYER M5 ;
        RECT  27.792 0 27.816 0.192 ;
    END
  END x_d[475]
  PIN x_d[476]
    DIRECTION INPUT ;
    USE SIGNAL ;
    PORT
      LAYER M5 ;
        RECT  27.84 0 27.864 0.192 ;
    END
  END x_d[476]
  PIN x_d[477]
    DIRECTION INPUT ;
    USE SIGNAL ;
    PORT
      LAYER M5 ;
        RECT  27.888 0 27.912 0.192 ;
    END
  END x_d[477]
  PIN x_d[478]
    DIRECTION INPUT ;
    USE SIGNAL ;
    PORT
      LAYER M5 ;
        RECT  27.936 0 27.96 0.192 ;
    END
  END x_d[478]
  PIN x_d[479]
    DIRECTION INPUT ;
    USE SIGNAL ;
    PORT
      LAYER M5 ;
        RECT  27.984 0 28.008 0.192 ;
    END
  END x_d[479]
  PIN x_d[47]
    DIRECTION INPUT ;
    USE SIGNAL ;
    PORT
      LAYER M5 ;
        RECT  7.248 0 7.272 0.192 ;
    END
  END x_d[47]
  PIN x_d[480]
    DIRECTION INPUT ;
    USE SIGNAL ;
    PORT
      LAYER M5 ;
        RECT  28.032 0 28.056 0.192 ;
    END
  END x_d[480]
  PIN x_d[481]
    DIRECTION INPUT ;
    USE SIGNAL ;
    PORT
      LAYER M5 ;
        RECT  28.08 0 28.104 0.192 ;
    END
  END x_d[481]
  PIN x_d[482]
    DIRECTION INPUT ;
    USE SIGNAL ;
    PORT
      LAYER M5 ;
        RECT  28.128 0 28.152 0.192 ;
    END
  END x_d[482]
  PIN x_d[483]
    DIRECTION INPUT ;
    USE SIGNAL ;
    PORT
      LAYER M5 ;
        RECT  28.176 0 28.2 0.192 ;
    END
  END x_d[483]
  PIN x_d[484]
    DIRECTION INPUT ;
    USE SIGNAL ;
    PORT
      LAYER M5 ;
        RECT  28.224 0 28.248 0.192 ;
    END
  END x_d[484]
  PIN x_d[485]
    DIRECTION INPUT ;
    USE SIGNAL ;
    PORT
      LAYER M5 ;
        RECT  28.272 0 28.296 0.192 ;
    END
  END x_d[485]
  PIN x_d[486]
    DIRECTION INPUT ;
    USE SIGNAL ;
    PORT
      LAYER M5 ;
        RECT  28.32 0 28.344 0.192 ;
    END
  END x_d[486]
  PIN x_d[487]
    DIRECTION INPUT ;
    USE SIGNAL ;
    PORT
      LAYER M5 ;
        RECT  28.368 0 28.392 0.192 ;
    END
  END x_d[487]
  PIN x_d[488]
    DIRECTION INPUT ;
    USE SIGNAL ;
    PORT
      LAYER M5 ;
        RECT  28.416 0 28.44 0.192 ;
    END
  END x_d[488]
  PIN x_d[489]
    DIRECTION INPUT ;
    USE SIGNAL ;
    PORT
      LAYER M5 ;
        RECT  28.464 0 28.488 0.192 ;
    END
  END x_d[489]
  PIN x_d[48]
    DIRECTION INPUT ;
    USE SIGNAL ;
    PORT
      LAYER M5 ;
        RECT  7.296 0 7.32 0.192 ;
    END
  END x_d[48]
  PIN x_d[490]
    DIRECTION INPUT ;
    USE SIGNAL ;
    PORT
      LAYER M5 ;
        RECT  28.512 0 28.536 0.192 ;
    END
  END x_d[490]
  PIN x_d[491]
    DIRECTION INPUT ;
    USE SIGNAL ;
    PORT
      LAYER M5 ;
        RECT  28.56 0 28.584 0.192 ;
    END
  END x_d[491]
  PIN x_d[492]
    DIRECTION INPUT ;
    USE SIGNAL ;
    PORT
      LAYER M5 ;
        RECT  28.608 0 28.632 0.192 ;
    END
  END x_d[492]
  PIN x_d[493]
    DIRECTION INPUT ;
    USE SIGNAL ;
    PORT
      LAYER M5 ;
        RECT  28.656 0 28.68 0.192 ;
    END
  END x_d[493]
  PIN x_d[494]
    DIRECTION INPUT ;
    USE SIGNAL ;
    PORT
      LAYER M5 ;
        RECT  28.704 0 28.728 0.192 ;
    END
  END x_d[494]
  PIN x_d[495]
    DIRECTION INPUT ;
    USE SIGNAL ;
    PORT
      LAYER M5 ;
        RECT  28.752 0 28.776 0.192 ;
    END
  END x_d[495]
  PIN x_d[496]
    DIRECTION INPUT ;
    USE SIGNAL ;
    PORT
      LAYER M5 ;
        RECT  28.8 0 28.824 0.192 ;
    END
  END x_d[496]
  PIN x_d[497]
    DIRECTION INPUT ;
    USE SIGNAL ;
    PORT
      LAYER M5 ;
        RECT  28.848 0 28.872 0.192 ;
    END
  END x_d[497]
  PIN x_d[498]
    DIRECTION INPUT ;
    USE SIGNAL ;
    PORT
      LAYER M5 ;
        RECT  28.896 0 28.92 0.192 ;
    END
  END x_d[498]
  PIN x_d[499]
    DIRECTION INPUT ;
    USE SIGNAL ;
    PORT
      LAYER M5 ;
        RECT  28.944 0 28.968 0.192 ;
    END
  END x_d[499]
  PIN x_d[49]
    DIRECTION INPUT ;
    USE SIGNAL ;
    PORT
      LAYER M5 ;
        RECT  7.344 0 7.368 0.192 ;
    END
  END x_d[49]
  PIN x_d[4]
    DIRECTION INPUT ;
    USE SIGNAL ;
    PORT
      LAYER M5 ;
        RECT  5.184 0 5.208 0.192 ;
    END
  END x_d[4]
  PIN x_d[500]
    DIRECTION INPUT ;
    USE SIGNAL ;
    PORT
      LAYER M5 ;
        RECT  28.992 0 29.016 0.192 ;
    END
  END x_d[500]
  PIN x_d[501]
    DIRECTION INPUT ;
    USE SIGNAL ;
    PORT
      LAYER M5 ;
        RECT  29.04 0 29.064 0.192 ;
    END
  END x_d[501]
  PIN x_d[502]
    DIRECTION INPUT ;
    USE SIGNAL ;
    PORT
      LAYER M5 ;
        RECT  29.088 0 29.112 0.192 ;
    END
  END x_d[502]
  PIN x_d[503]
    DIRECTION INPUT ;
    USE SIGNAL ;
    PORT
      LAYER M5 ;
        RECT  29.136 0 29.16 0.192 ;
    END
  END x_d[503]
  PIN x_d[504]
    DIRECTION INPUT ;
    USE SIGNAL ;
    PORT
      LAYER M5 ;
        RECT  29.184 0 29.208 0.192 ;
    END
  END x_d[504]
  PIN x_d[505]
    DIRECTION INPUT ;
    USE SIGNAL ;
    PORT
      LAYER M5 ;
        RECT  29.232 0 29.256 0.192 ;
    END
  END x_d[505]
  PIN x_d[506]
    DIRECTION INPUT ;
    USE SIGNAL ;
    PORT
      LAYER M5 ;
        RECT  29.28 0 29.304 0.192 ;
    END
  END x_d[506]
  PIN x_d[507]
    DIRECTION INPUT ;
    USE SIGNAL ;
    PORT
      LAYER M5 ;
        RECT  29.328 0 29.352 0.192 ;
    END
  END x_d[507]
  PIN x_d[508]
    DIRECTION INPUT ;
    USE SIGNAL ;
    PORT
      LAYER M5 ;
        RECT  29.376 0 29.4 0.192 ;
    END
  END x_d[508]
  PIN x_d[509]
    DIRECTION INPUT ;
    USE SIGNAL ;
    PORT
      LAYER M5 ;
        RECT  29.424 0 29.448 0.192 ;
    END
  END x_d[509]
  PIN x_d[50]
    DIRECTION INPUT ;
    USE SIGNAL ;
    PORT
      LAYER M5 ;
        RECT  7.392 0 7.416 0.192 ;
    END
  END x_d[50]
  PIN x_d[510]
    DIRECTION INPUT ;
    USE SIGNAL ;
    PORT
      LAYER M5 ;
        RECT  29.472 0 29.496 0.192 ;
    END
  END x_d[510]
  PIN x_d[511]
    DIRECTION INPUT ;
    USE SIGNAL ;
    PORT
      LAYER M5 ;
        RECT  29.52 0 29.544 0.192 ;
    END
  END x_d[511]
  PIN x_d[51]
    DIRECTION INPUT ;
    USE SIGNAL ;
    PORT
      LAYER M5 ;
        RECT  7.44 0 7.464 0.192 ;
    END
  END x_d[51]
  PIN x_d[52]
    DIRECTION INPUT ;
    USE SIGNAL ;
    PORT
      LAYER M5 ;
        RECT  7.488 0 7.512 0.192 ;
    END
  END x_d[52]
  PIN x_d[53]
    DIRECTION INPUT ;
    USE SIGNAL ;
    PORT
      LAYER M5 ;
        RECT  7.536 0 7.56 0.192 ;
    END
  END x_d[53]
  PIN x_d[54]
    DIRECTION INPUT ;
    USE SIGNAL ;
    PORT
      LAYER M5 ;
        RECT  7.584 0 7.608 0.192 ;
    END
  END x_d[54]
  PIN x_d[55]
    DIRECTION INPUT ;
    USE SIGNAL ;
    PORT
      LAYER M5 ;
        RECT  7.632 0 7.656 0.192 ;
    END
  END x_d[55]
  PIN x_d[56]
    DIRECTION INPUT ;
    USE SIGNAL ;
    PORT
      LAYER M5 ;
        RECT  7.68 0 7.704 0.192 ;
    END
  END x_d[56]
  PIN x_d[57]
    DIRECTION INPUT ;
    USE SIGNAL ;
    PORT
      LAYER M5 ;
        RECT  7.728 0 7.752 0.192 ;
    END
  END x_d[57]
  PIN x_d[58]
    DIRECTION INPUT ;
    USE SIGNAL ;
    PORT
      LAYER M5 ;
        RECT  7.776 0 7.8 0.192 ;
    END
  END x_d[58]
  PIN x_d[59]
    DIRECTION INPUT ;
    USE SIGNAL ;
    PORT
      LAYER M5 ;
        RECT  7.824 0 7.848 0.192 ;
    END
  END x_d[59]
  PIN x_d[5]
    DIRECTION INPUT ;
    USE SIGNAL ;
    PORT
      LAYER M5 ;
        RECT  5.232 0 5.256 0.192 ;
    END
  END x_d[5]
  PIN x_d[60]
    DIRECTION INPUT ;
    USE SIGNAL ;
    PORT
      LAYER M5 ;
        RECT  7.872 0 7.896 0.192 ;
    END
  END x_d[60]
  PIN x_d[61]
    DIRECTION INPUT ;
    USE SIGNAL ;
    PORT
      LAYER M5 ;
        RECT  7.92 0 7.944 0.192 ;
    END
  END x_d[61]
  PIN x_d[62]
    DIRECTION INPUT ;
    USE SIGNAL ;
    PORT
      LAYER M5 ;
        RECT  7.968 0 7.992 0.192 ;
    END
  END x_d[62]
  PIN x_d[63]
    DIRECTION INPUT ;
    USE SIGNAL ;
    PORT
      LAYER M5 ;
        RECT  8.016 0 8.04 0.192 ;
    END
  END x_d[63]
  PIN x_d[64]
    DIRECTION INPUT ;
    USE SIGNAL ;
    PORT
      LAYER M5 ;
        RECT  8.064 0 8.088 0.192 ;
    END
  END x_d[64]
  PIN x_d[65]
    DIRECTION INPUT ;
    USE SIGNAL ;
    PORT
      LAYER M5 ;
        RECT  8.112 0 8.136 0.192 ;
    END
  END x_d[65]
  PIN x_d[66]
    DIRECTION INPUT ;
    USE SIGNAL ;
    PORT
      LAYER M5 ;
        RECT  8.16 0 8.184 0.192 ;
    END
  END x_d[66]
  PIN x_d[67]
    DIRECTION INPUT ;
    USE SIGNAL ;
    PORT
      LAYER M5 ;
        RECT  8.208 0 8.232 0.192 ;
    END
  END x_d[67]
  PIN x_d[68]
    DIRECTION INPUT ;
    USE SIGNAL ;
    PORT
      LAYER M5 ;
        RECT  8.256 0 8.28 0.192 ;
    END
  END x_d[68]
  PIN x_d[69]
    DIRECTION INPUT ;
    USE SIGNAL ;
    PORT
      LAYER M5 ;
        RECT  8.304 0 8.328 0.192 ;
    END
  END x_d[69]
  PIN x_d[6]
    DIRECTION INPUT ;
    USE SIGNAL ;
    PORT
      LAYER M5 ;
        RECT  5.28 0 5.304 0.192 ;
    END
  END x_d[6]
  PIN x_d[70]
    DIRECTION INPUT ;
    USE SIGNAL ;
    PORT
      LAYER M5 ;
        RECT  8.352 0 8.376 0.192 ;
    END
  END x_d[70]
  PIN x_d[71]
    DIRECTION INPUT ;
    USE SIGNAL ;
    PORT
      LAYER M5 ;
        RECT  8.4 0 8.424 0.192 ;
    END
  END x_d[71]
  PIN x_d[72]
    DIRECTION INPUT ;
    USE SIGNAL ;
    PORT
      LAYER M5 ;
        RECT  8.448 0 8.472 0.192 ;
    END
  END x_d[72]
  PIN x_d[73]
    DIRECTION INPUT ;
    USE SIGNAL ;
    PORT
      LAYER M5 ;
        RECT  8.496 0 8.52 0.192 ;
    END
  END x_d[73]
  PIN x_d[74]
    DIRECTION INPUT ;
    USE SIGNAL ;
    PORT
      LAYER M5 ;
        RECT  8.544 0 8.568 0.192 ;
    END
  END x_d[74]
  PIN x_d[75]
    DIRECTION INPUT ;
    USE SIGNAL ;
    PORT
      LAYER M5 ;
        RECT  8.592 0 8.616 0.192 ;
    END
  END x_d[75]
  PIN x_d[76]
    DIRECTION INPUT ;
    USE SIGNAL ;
    PORT
      LAYER M5 ;
        RECT  8.64 0 8.664 0.192 ;
    END
  END x_d[76]
  PIN x_d[77]
    DIRECTION INPUT ;
    USE SIGNAL ;
    PORT
      LAYER M5 ;
        RECT  8.688 0 8.712 0.192 ;
    END
  END x_d[77]
  PIN x_d[78]
    DIRECTION INPUT ;
    USE SIGNAL ;
    PORT
      LAYER M5 ;
        RECT  8.736 0 8.76 0.192 ;
    END
  END x_d[78]
  PIN x_d[79]
    DIRECTION INPUT ;
    USE SIGNAL ;
    PORT
      LAYER M5 ;
        RECT  8.784 0 8.808 0.192 ;
    END
  END x_d[79]
  PIN x_d[7]
    DIRECTION INPUT ;
    USE SIGNAL ;
    PORT
      LAYER M5 ;
        RECT  5.328 0 5.352 0.192 ;
    END
  END x_d[7]
  PIN x_d[80]
    DIRECTION INPUT ;
    USE SIGNAL ;
    PORT
      LAYER M5 ;
        RECT  8.832 0 8.856 0.192 ;
    END
  END x_d[80]
  PIN x_d[81]
    DIRECTION INPUT ;
    USE SIGNAL ;
    PORT
      LAYER M5 ;
        RECT  8.88 0 8.904 0.192 ;
    END
  END x_d[81]
  PIN x_d[82]
    DIRECTION INPUT ;
    USE SIGNAL ;
    PORT
      LAYER M5 ;
        RECT  8.928 0 8.952 0.192 ;
    END
  END x_d[82]
  PIN x_d[83]
    DIRECTION INPUT ;
    USE SIGNAL ;
    PORT
      LAYER M5 ;
        RECT  8.976 0 9 0.192 ;
    END
  END x_d[83]
  PIN x_d[84]
    DIRECTION INPUT ;
    USE SIGNAL ;
    PORT
      LAYER M5 ;
        RECT  9.024 0 9.048 0.192 ;
    END
  END x_d[84]
  PIN x_d[85]
    DIRECTION INPUT ;
    USE SIGNAL ;
    PORT
      LAYER M5 ;
        RECT  9.072 0 9.096 0.192 ;
    END
  END x_d[85]
  PIN x_d[86]
    DIRECTION INPUT ;
    USE SIGNAL ;
    PORT
      LAYER M5 ;
        RECT  9.12 0 9.144 0.192 ;
    END
  END x_d[86]
  PIN x_d[87]
    DIRECTION INPUT ;
    USE SIGNAL ;
    PORT
      LAYER M5 ;
        RECT  9.168 0 9.192 0.192 ;
    END
  END x_d[87]
  PIN x_d[88]
    DIRECTION INPUT ;
    USE SIGNAL ;
    PORT
      LAYER M5 ;
        RECT  9.216 0 9.24 0.192 ;
    END
  END x_d[88]
  PIN x_d[89]
    DIRECTION INPUT ;
    USE SIGNAL ;
    PORT
      LAYER M5 ;
        RECT  9.264 0 9.288 0.192 ;
    END
  END x_d[89]
  PIN x_d[8]
    DIRECTION INPUT ;
    USE SIGNAL ;
    PORT
      LAYER M5 ;
        RECT  5.376 0 5.4 0.192 ;
    END
  END x_d[8]
  PIN x_d[90]
    DIRECTION INPUT ;
    USE SIGNAL ;
    PORT
      LAYER M5 ;
        RECT  9.312 0 9.336 0.192 ;
    END
  END x_d[90]
  PIN x_d[91]
    DIRECTION INPUT ;
    USE SIGNAL ;
    PORT
      LAYER M5 ;
        RECT  9.36 0 9.384 0.192 ;
    END
  END x_d[91]
  PIN x_d[92]
    DIRECTION INPUT ;
    USE SIGNAL ;
    PORT
      LAYER M5 ;
        RECT  9.408 0 9.432 0.192 ;
    END
  END x_d[92]
  PIN x_d[93]
    DIRECTION INPUT ;
    USE SIGNAL ;
    PORT
      LAYER M5 ;
        RECT  9.456 0 9.48 0.192 ;
    END
  END x_d[93]
  PIN x_d[94]
    DIRECTION INPUT ;
    USE SIGNAL ;
    PORT
      LAYER M5 ;
        RECT  9.504 0 9.528 0.192 ;
    END
  END x_d[94]
  PIN x_d[95]
    DIRECTION INPUT ;
    USE SIGNAL ;
    PORT
      LAYER M5 ;
        RECT  9.552 0 9.576 0.192 ;
    END
  END x_d[95]
  PIN x_d[96]
    DIRECTION INPUT ;
    USE SIGNAL ;
    PORT
      LAYER M5 ;
        RECT  9.6 0 9.624 0.192 ;
    END
  END x_d[96]
  PIN x_d[97]
    DIRECTION INPUT ;
    USE SIGNAL ;
    PORT
      LAYER M5 ;
        RECT  9.648 0 9.672 0.192 ;
    END
  END x_d[97]
  PIN x_d[98]
    DIRECTION INPUT ;
    USE SIGNAL ;
    PORT
      LAYER M5 ;
        RECT  9.696 0 9.72 0.192 ;
    END
  END x_d[98]
  PIN x_d[99]
    DIRECTION INPUT ;
    USE SIGNAL ;
    PORT
      LAYER M5 ;
        RECT  9.744 0 9.768 0.192 ;
    END
  END x_d[99]
  PIN x_d[9]
    DIRECTION INPUT ;
    USE SIGNAL ;
    PORT
      LAYER M5 ;
        RECT  5.424 0 5.448 0.192 ;
    END
  END x_d[9]
  PIN x_r[0]
    DIRECTION OUTPUT ;
    USE SIGNAL ;
    PORT
      LAYER M5 ;
        RECT  29.664 0 29.688 0.192 ;
    END
  END x_r[0]
  PIN x_v[0]
    DIRECTION INPUT ;
    USE SIGNAL ;
    PORT
      LAYER M5 ;
        RECT  4.8 0 4.824 0.192 ;
    END
  END x_v[0]
  PIN xd[0]
    DIRECTION OUTPUT ;
    USE SIGNAL ;
    PORT
      LAYER M5 ;
        RECT  25.68 129.408 25.704 129.6 ;
    END
  END xd[0]
  PIN xd[100]
    DIRECTION OUTPUT ;
    USE SIGNAL ;
    PORT
      LAYER M5 ;
        RECT  30.48 129.408 30.504 129.6 ;
    END
  END xd[100]
  PIN xd[101]
    DIRECTION OUTPUT ;
    USE SIGNAL ;
    PORT
      LAYER M5 ;
        RECT  30.528 129.408 30.552 129.6 ;
    END
  END xd[101]
  PIN xd[102]
    DIRECTION OUTPUT ;
    USE SIGNAL ;
    PORT
      LAYER M5 ;
        RECT  30.576 129.408 30.6 129.6 ;
    END
  END xd[102]
  PIN xd[103]
    DIRECTION OUTPUT ;
    USE SIGNAL ;
    PORT
      LAYER M5 ;
        RECT  30.624 129.408 30.648 129.6 ;
    END
  END xd[103]
  PIN xd[104]
    DIRECTION OUTPUT ;
    USE SIGNAL ;
    PORT
      LAYER M5 ;
        RECT  30.672 129.408 30.696 129.6 ;
    END
  END xd[104]
  PIN xd[105]
    DIRECTION OUTPUT ;
    USE SIGNAL ;
    PORT
      LAYER M5 ;
        RECT  30.72 129.408 30.744 129.6 ;
    END
  END xd[105]
  PIN xd[106]
    DIRECTION OUTPUT ;
    USE SIGNAL ;
    PORT
      LAYER M5 ;
        RECT  30.768 129.408 30.792 129.6 ;
    END
  END xd[106]
  PIN xd[107]
    DIRECTION OUTPUT ;
    USE SIGNAL ;
    PORT
      LAYER M5 ;
        RECT  30.816 129.408 30.84 129.6 ;
    END
  END xd[107]
  PIN xd[108]
    DIRECTION OUTPUT ;
    USE SIGNAL ;
    PORT
      LAYER M5 ;
        RECT  30.864 129.408 30.888 129.6 ;
    END
  END xd[108]
  PIN xd[109]
    DIRECTION OUTPUT ;
    USE SIGNAL ;
    PORT
      LAYER M5 ;
        RECT  30.912 129.408 30.936 129.6 ;
    END
  END xd[109]
  PIN xd[10]
    DIRECTION OUTPUT ;
    USE SIGNAL ;
    PORT
      LAYER M5 ;
        RECT  26.16 129.408 26.184 129.6 ;
    END
  END xd[10]
  PIN xd[110]
    DIRECTION OUTPUT ;
    USE SIGNAL ;
    PORT
      LAYER M5 ;
        RECT  30.96 129.408 30.984 129.6 ;
    END
  END xd[110]
  PIN xd[111]
    DIRECTION OUTPUT ;
    USE SIGNAL ;
    PORT
      LAYER M5 ;
        RECT  31.008 129.408 31.032 129.6 ;
    END
  END xd[111]
  PIN xd[112]
    DIRECTION OUTPUT ;
    USE SIGNAL ;
    PORT
      LAYER M5 ;
        RECT  31.056 129.408 31.08 129.6 ;
    END
  END xd[112]
  PIN xd[113]
    DIRECTION OUTPUT ;
    USE SIGNAL ;
    PORT
      LAYER M5 ;
        RECT  31.104 129.408 31.128 129.6 ;
    END
  END xd[113]
  PIN xd[114]
    DIRECTION OUTPUT ;
    USE SIGNAL ;
    PORT
      LAYER M5 ;
        RECT  31.152 129.408 31.176 129.6 ;
    END
  END xd[114]
  PIN xd[115]
    DIRECTION OUTPUT ;
    USE SIGNAL ;
    PORT
      LAYER M5 ;
        RECT  31.2 129.408 31.224 129.6 ;
    END
  END xd[115]
  PIN xd[116]
    DIRECTION OUTPUT ;
    USE SIGNAL ;
    PORT
      LAYER M5 ;
        RECT  31.248 129.408 31.272 129.6 ;
    END
  END xd[116]
  PIN xd[117]
    DIRECTION OUTPUT ;
    USE SIGNAL ;
    PORT
      LAYER M5 ;
        RECT  31.296 129.408 31.32 129.6 ;
    END
  END xd[117]
  PIN xd[118]
    DIRECTION OUTPUT ;
    USE SIGNAL ;
    PORT
      LAYER M5 ;
        RECT  31.344 129.408 31.368 129.6 ;
    END
  END xd[118]
  PIN xd[119]
    DIRECTION OUTPUT ;
    USE SIGNAL ;
    PORT
      LAYER M5 ;
        RECT  31.392 129.408 31.416 129.6 ;
    END
  END xd[119]
  PIN xd[11]
    DIRECTION OUTPUT ;
    USE SIGNAL ;
    PORT
      LAYER M5 ;
        RECT  26.208 129.408 26.232 129.6 ;
    END
  END xd[11]
  PIN xd[120]
    DIRECTION OUTPUT ;
    USE SIGNAL ;
    PORT
      LAYER M5 ;
        RECT  31.44 129.408 31.464 129.6 ;
    END
  END xd[120]
  PIN xd[121]
    DIRECTION OUTPUT ;
    USE SIGNAL ;
    PORT
      LAYER M5 ;
        RECT  31.488 129.408 31.512 129.6 ;
    END
  END xd[121]
  PIN xd[122]
    DIRECTION OUTPUT ;
    USE SIGNAL ;
    PORT
      LAYER M5 ;
        RECT  31.536 129.408 31.56 129.6 ;
    END
  END xd[122]
  PIN xd[123]
    DIRECTION OUTPUT ;
    USE SIGNAL ;
    PORT
      LAYER M5 ;
        RECT  31.584 129.408 31.608 129.6 ;
    END
  END xd[123]
  PIN xd[124]
    DIRECTION OUTPUT ;
    USE SIGNAL ;
    PORT
      LAYER M5 ;
        RECT  31.632 129.408 31.656 129.6 ;
    END
  END xd[124]
  PIN xd[125]
    DIRECTION OUTPUT ;
    USE SIGNAL ;
    PORT
      LAYER M5 ;
        RECT  31.68 129.408 31.704 129.6 ;
    END
  END xd[125]
  PIN xd[126]
    DIRECTION OUTPUT ;
    USE SIGNAL ;
    PORT
      LAYER M5 ;
        RECT  31.728 129.408 31.752 129.6 ;
    END
  END xd[126]
  PIN xd[127]
    DIRECTION OUTPUT ;
    USE SIGNAL ;
    PORT
      LAYER M5 ;
        RECT  31.776 129.408 31.8 129.6 ;
    END
  END xd[127]
  PIN xd[128]
    DIRECTION OUTPUT ;
    USE SIGNAL ;
    PORT
      LAYER M5 ;
        RECT  31.824 129.408 31.848 129.6 ;
    END
  END xd[128]
  PIN xd[129]
    DIRECTION OUTPUT ;
    USE SIGNAL ;
    PORT
      LAYER M5 ;
        RECT  31.872 129.408 31.896 129.6 ;
    END
  END xd[129]
  PIN xd[12]
    DIRECTION OUTPUT ;
    USE SIGNAL ;
    PORT
      LAYER M5 ;
        RECT  26.256 129.408 26.28 129.6 ;
    END
  END xd[12]
  PIN xd[130]
    DIRECTION OUTPUT ;
    USE SIGNAL ;
    PORT
      LAYER M5 ;
        RECT  31.92 129.408 31.944 129.6 ;
    END
  END xd[130]
  PIN xd[131]
    DIRECTION OUTPUT ;
    USE SIGNAL ;
    PORT
      LAYER M5 ;
        RECT  31.968 129.408 31.992 129.6 ;
    END
  END xd[131]
  PIN xd[132]
    DIRECTION OUTPUT ;
    USE SIGNAL ;
    PORT
      LAYER M5 ;
        RECT  32.016 129.408 32.04 129.6 ;
    END
  END xd[132]
  PIN xd[133]
    DIRECTION OUTPUT ;
    USE SIGNAL ;
    PORT
      LAYER M5 ;
        RECT  32.064 129.408 32.088 129.6 ;
    END
  END xd[133]
  PIN xd[134]
    DIRECTION OUTPUT ;
    USE SIGNAL ;
    PORT
      LAYER M5 ;
        RECT  32.112 129.408 32.136 129.6 ;
    END
  END xd[134]
  PIN xd[135]
    DIRECTION OUTPUT ;
    USE SIGNAL ;
    PORT
      LAYER M5 ;
        RECT  32.16 129.408 32.184 129.6 ;
    END
  END xd[135]
  PIN xd[136]
    DIRECTION OUTPUT ;
    USE SIGNAL ;
    PORT
      LAYER M5 ;
        RECT  32.208 129.408 32.232 129.6 ;
    END
  END xd[136]
  PIN xd[137]
    DIRECTION OUTPUT ;
    USE SIGNAL ;
    PORT
      LAYER M5 ;
        RECT  32.256 129.408 32.28 129.6 ;
    END
  END xd[137]
  PIN xd[138]
    DIRECTION OUTPUT ;
    USE SIGNAL ;
    PORT
      LAYER M5 ;
        RECT  32.304 129.408 32.328 129.6 ;
    END
  END xd[138]
  PIN xd[139]
    DIRECTION OUTPUT ;
    USE SIGNAL ;
    PORT
      LAYER M5 ;
        RECT  32.352 129.408 32.376 129.6 ;
    END
  END xd[139]
  PIN xd[13]
    DIRECTION OUTPUT ;
    USE SIGNAL ;
    PORT
      LAYER M5 ;
        RECT  26.304 129.408 26.328 129.6 ;
    END
  END xd[13]
  PIN xd[140]
    DIRECTION OUTPUT ;
    USE SIGNAL ;
    PORT
      LAYER M5 ;
        RECT  32.4 129.408 32.424 129.6 ;
    END
  END xd[140]
  PIN xd[141]
    DIRECTION OUTPUT ;
    USE SIGNAL ;
    PORT
      LAYER M5 ;
        RECT  32.448 129.408 32.472 129.6 ;
    END
  END xd[141]
  PIN xd[142]
    DIRECTION OUTPUT ;
    USE SIGNAL ;
    PORT
      LAYER M5 ;
        RECT  32.496 129.408 32.52 129.6 ;
    END
  END xd[142]
  PIN xd[143]
    DIRECTION OUTPUT ;
    USE SIGNAL ;
    PORT
      LAYER M5 ;
        RECT  32.544 129.408 32.568 129.6 ;
    END
  END xd[143]
  PIN xd[144]
    DIRECTION OUTPUT ;
    USE SIGNAL ;
    PORT
      LAYER M5 ;
        RECT  32.592 129.408 32.616 129.6 ;
    END
  END xd[144]
  PIN xd[145]
    DIRECTION OUTPUT ;
    USE SIGNAL ;
    PORT
      LAYER M5 ;
        RECT  32.64 129.408 32.664 129.6 ;
    END
  END xd[145]
  PIN xd[146]
    DIRECTION OUTPUT ;
    USE SIGNAL ;
    PORT
      LAYER M5 ;
        RECT  32.688 129.408 32.712 129.6 ;
    END
  END xd[146]
  PIN xd[147]
    DIRECTION OUTPUT ;
    USE SIGNAL ;
    PORT
      LAYER M5 ;
        RECT  32.736 129.408 32.76 129.6 ;
    END
  END xd[147]
  PIN xd[148]
    DIRECTION OUTPUT ;
    USE SIGNAL ;
    PORT
      LAYER M5 ;
        RECT  32.784 129.408 32.808 129.6 ;
    END
  END xd[148]
  PIN xd[149]
    DIRECTION OUTPUT ;
    USE SIGNAL ;
    PORT
      LAYER M5 ;
        RECT  32.832 129.408 32.856 129.6 ;
    END
  END xd[149]
  PIN xd[14]
    DIRECTION OUTPUT ;
    USE SIGNAL ;
    PORT
      LAYER M5 ;
        RECT  26.352 129.408 26.376 129.6 ;
    END
  END xd[14]
  PIN xd[150]
    DIRECTION OUTPUT ;
    USE SIGNAL ;
    PORT
      LAYER M5 ;
        RECT  32.88 129.408 32.904 129.6 ;
    END
  END xd[150]
  PIN xd[151]
    DIRECTION OUTPUT ;
    USE SIGNAL ;
    PORT
      LAYER M5 ;
        RECT  32.928 129.408 32.952 129.6 ;
    END
  END xd[151]
  PIN xd[152]
    DIRECTION OUTPUT ;
    USE SIGNAL ;
    PORT
      LAYER M5 ;
        RECT  32.976 129.408 33 129.6 ;
    END
  END xd[152]
  PIN xd[153]
    DIRECTION OUTPUT ;
    USE SIGNAL ;
    PORT
      LAYER M5 ;
        RECT  33.024 129.408 33.048 129.6 ;
    END
  END xd[153]
  PIN xd[154]
    DIRECTION OUTPUT ;
    USE SIGNAL ;
    PORT
      LAYER M5 ;
        RECT  33.072 129.408 33.096 129.6 ;
    END
  END xd[154]
  PIN xd[155]
    DIRECTION OUTPUT ;
    USE SIGNAL ;
    PORT
      LAYER M5 ;
        RECT  33.12 129.408 33.144 129.6 ;
    END
  END xd[155]
  PIN xd[156]
    DIRECTION OUTPUT ;
    USE SIGNAL ;
    PORT
      LAYER M5 ;
        RECT  33.168 129.408 33.192 129.6 ;
    END
  END xd[156]
  PIN xd[157]
    DIRECTION OUTPUT ;
    USE SIGNAL ;
    PORT
      LAYER M5 ;
        RECT  33.216 129.408 33.24 129.6 ;
    END
  END xd[157]
  PIN xd[158]
    DIRECTION OUTPUT ;
    USE SIGNAL ;
    PORT
      LAYER M5 ;
        RECT  33.264 129.408 33.288 129.6 ;
    END
  END xd[158]
  PIN xd[159]
    DIRECTION OUTPUT ;
    USE SIGNAL ;
    PORT
      LAYER M5 ;
        RECT  33.312 129.408 33.336 129.6 ;
    END
  END xd[159]
  PIN xd[15]
    DIRECTION OUTPUT ;
    USE SIGNAL ;
    PORT
      LAYER M5 ;
        RECT  26.4 129.408 26.424 129.6 ;
    END
  END xd[15]
  PIN xd[160]
    DIRECTION OUTPUT ;
    USE SIGNAL ;
    PORT
      LAYER M5 ;
        RECT  33.36 129.408 33.384 129.6 ;
    END
  END xd[160]
  PIN xd[161]
    DIRECTION OUTPUT ;
    USE SIGNAL ;
    PORT
      LAYER M5 ;
        RECT  33.408 129.408 33.432 129.6 ;
    END
  END xd[161]
  PIN xd[162]
    DIRECTION OUTPUT ;
    USE SIGNAL ;
    PORT
      LAYER M5 ;
        RECT  33.456 129.408 33.48 129.6 ;
    END
  END xd[162]
  PIN xd[163]
    DIRECTION OUTPUT ;
    USE SIGNAL ;
    PORT
      LAYER M5 ;
        RECT  33.504 129.408 33.528 129.6 ;
    END
  END xd[163]
  PIN xd[164]
    DIRECTION OUTPUT ;
    USE SIGNAL ;
    PORT
      LAYER M5 ;
        RECT  33.552 129.408 33.576 129.6 ;
    END
  END xd[164]
  PIN xd[165]
    DIRECTION OUTPUT ;
    USE SIGNAL ;
    PORT
      LAYER M5 ;
        RECT  33.6 129.408 33.624 129.6 ;
    END
  END xd[165]
  PIN xd[166]
    DIRECTION OUTPUT ;
    USE SIGNAL ;
    PORT
      LAYER M5 ;
        RECT  33.648 129.408 33.672 129.6 ;
    END
  END xd[166]
  PIN xd[167]
    DIRECTION OUTPUT ;
    USE SIGNAL ;
    PORT
      LAYER M5 ;
        RECT  33.696 129.408 33.72 129.6 ;
    END
  END xd[167]
  PIN xd[168]
    DIRECTION OUTPUT ;
    USE SIGNAL ;
    PORT
      LAYER M5 ;
        RECT  33.744 129.408 33.768 129.6 ;
    END
  END xd[168]
  PIN xd[169]
    DIRECTION OUTPUT ;
    USE SIGNAL ;
    PORT
      LAYER M5 ;
        RECT  33.792 129.408 33.816 129.6 ;
    END
  END xd[169]
  PIN xd[16]
    DIRECTION OUTPUT ;
    USE SIGNAL ;
    PORT
      LAYER M5 ;
        RECT  26.448 129.408 26.472 129.6 ;
    END
  END xd[16]
  PIN xd[170]
    DIRECTION OUTPUT ;
    USE SIGNAL ;
    PORT
      LAYER M5 ;
        RECT  33.84 129.408 33.864 129.6 ;
    END
  END xd[170]
  PIN xd[171]
    DIRECTION OUTPUT ;
    USE SIGNAL ;
    PORT
      LAYER M5 ;
        RECT  33.888 129.408 33.912 129.6 ;
    END
  END xd[171]
  PIN xd[172]
    DIRECTION OUTPUT ;
    USE SIGNAL ;
    PORT
      LAYER M5 ;
        RECT  33.936 129.408 33.96 129.6 ;
    END
  END xd[172]
  PIN xd[173]
    DIRECTION OUTPUT ;
    USE SIGNAL ;
    PORT
      LAYER M5 ;
        RECT  33.984 129.408 34.008 129.6 ;
    END
  END xd[173]
  PIN xd[174]
    DIRECTION OUTPUT ;
    USE SIGNAL ;
    PORT
      LAYER M5 ;
        RECT  34.032 129.408 34.056 129.6 ;
    END
  END xd[174]
  PIN xd[175]
    DIRECTION OUTPUT ;
    USE SIGNAL ;
    PORT
      LAYER M5 ;
        RECT  34.08 129.408 34.104 129.6 ;
    END
  END xd[175]
  PIN xd[176]
    DIRECTION OUTPUT ;
    USE SIGNAL ;
    PORT
      LAYER M5 ;
        RECT  34.128 129.408 34.152 129.6 ;
    END
  END xd[176]
  PIN xd[177]
    DIRECTION OUTPUT ;
    USE SIGNAL ;
    PORT
      LAYER M5 ;
        RECT  34.176 129.408 34.2 129.6 ;
    END
  END xd[177]
  PIN xd[178]
    DIRECTION OUTPUT ;
    USE SIGNAL ;
    PORT
      LAYER M5 ;
        RECT  34.224 129.408 34.248 129.6 ;
    END
  END xd[178]
  PIN xd[179]
    DIRECTION OUTPUT ;
    USE SIGNAL ;
    PORT
      LAYER M5 ;
        RECT  34.272 129.408 34.296 129.6 ;
    END
  END xd[179]
  PIN xd[17]
    DIRECTION OUTPUT ;
    USE SIGNAL ;
    PORT
      LAYER M5 ;
        RECT  26.496 129.408 26.52 129.6 ;
    END
  END xd[17]
  PIN xd[180]
    DIRECTION OUTPUT ;
    USE SIGNAL ;
    PORT
      LAYER M5 ;
        RECT  34.32 129.408 34.344 129.6 ;
    END
  END xd[180]
  PIN xd[181]
    DIRECTION OUTPUT ;
    USE SIGNAL ;
    PORT
      LAYER M5 ;
        RECT  34.368 129.408 34.392 129.6 ;
    END
  END xd[181]
  PIN xd[182]
    DIRECTION OUTPUT ;
    USE SIGNAL ;
    PORT
      LAYER M5 ;
        RECT  34.416 129.408 34.44 129.6 ;
    END
  END xd[182]
  PIN xd[183]
    DIRECTION OUTPUT ;
    USE SIGNAL ;
    PORT
      LAYER M5 ;
        RECT  34.464 129.408 34.488 129.6 ;
    END
  END xd[183]
  PIN xd[184]
    DIRECTION OUTPUT ;
    USE SIGNAL ;
    PORT
      LAYER M5 ;
        RECT  34.512 129.408 34.536 129.6 ;
    END
  END xd[184]
  PIN xd[185]
    DIRECTION OUTPUT ;
    USE SIGNAL ;
    PORT
      LAYER M5 ;
        RECT  34.56 129.408 34.584 129.6 ;
    END
  END xd[185]
  PIN xd[186]
    DIRECTION OUTPUT ;
    USE SIGNAL ;
    PORT
      LAYER M5 ;
        RECT  34.608 129.408 34.632 129.6 ;
    END
  END xd[186]
  PIN xd[187]
    DIRECTION OUTPUT ;
    USE SIGNAL ;
    PORT
      LAYER M5 ;
        RECT  34.656 129.408 34.68 129.6 ;
    END
  END xd[187]
  PIN xd[188]
    DIRECTION OUTPUT ;
    USE SIGNAL ;
    PORT
      LAYER M5 ;
        RECT  34.704 129.408 34.728 129.6 ;
    END
  END xd[188]
  PIN xd[189]
    DIRECTION OUTPUT ;
    USE SIGNAL ;
    PORT
      LAYER M5 ;
        RECT  34.752 129.408 34.776 129.6 ;
    END
  END xd[189]
  PIN xd[18]
    DIRECTION OUTPUT ;
    USE SIGNAL ;
    PORT
      LAYER M5 ;
        RECT  26.544 129.408 26.568 129.6 ;
    END
  END xd[18]
  PIN xd[190]
    DIRECTION OUTPUT ;
    USE SIGNAL ;
    PORT
      LAYER M5 ;
        RECT  34.8 129.408 34.824 129.6 ;
    END
  END xd[190]
  PIN xd[191]
    DIRECTION OUTPUT ;
    USE SIGNAL ;
    PORT
      LAYER M5 ;
        RECT  34.848 129.408 34.872 129.6 ;
    END
  END xd[191]
  PIN xd[192]
    DIRECTION OUTPUT ;
    USE SIGNAL ;
    PORT
      LAYER M5 ;
        RECT  34.896 129.408 34.92 129.6 ;
    END
  END xd[192]
  PIN xd[193]
    DIRECTION OUTPUT ;
    USE SIGNAL ;
    PORT
      LAYER M5 ;
        RECT  34.944 129.408 34.968 129.6 ;
    END
  END xd[193]
  PIN xd[194]
    DIRECTION OUTPUT ;
    USE SIGNAL ;
    PORT
      LAYER M5 ;
        RECT  34.992 129.408 35.016 129.6 ;
    END
  END xd[194]
  PIN xd[195]
    DIRECTION OUTPUT ;
    USE SIGNAL ;
    PORT
      LAYER M5 ;
        RECT  35.04 129.408 35.064 129.6 ;
    END
  END xd[195]
  PIN xd[196]
    DIRECTION OUTPUT ;
    USE SIGNAL ;
    PORT
      LAYER M5 ;
        RECT  35.088 129.408 35.112 129.6 ;
    END
  END xd[196]
  PIN xd[197]
    DIRECTION OUTPUT ;
    USE SIGNAL ;
    PORT
      LAYER M5 ;
        RECT  35.136 129.408 35.16 129.6 ;
    END
  END xd[197]
  PIN xd[198]
    DIRECTION OUTPUT ;
    USE SIGNAL ;
    PORT
      LAYER M5 ;
        RECT  35.184 129.408 35.208 129.6 ;
    END
  END xd[198]
  PIN xd[199]
    DIRECTION OUTPUT ;
    USE SIGNAL ;
    PORT
      LAYER M5 ;
        RECT  35.232 129.408 35.256 129.6 ;
    END
  END xd[199]
  PIN xd[19]
    DIRECTION OUTPUT ;
    USE SIGNAL ;
    PORT
      LAYER M5 ;
        RECT  26.592 129.408 26.616 129.6 ;
    END
  END xd[19]
  PIN xd[1]
    DIRECTION OUTPUT ;
    USE SIGNAL ;
    PORT
      LAYER M5 ;
        RECT  25.728 129.408 25.752 129.6 ;
    END
  END xd[1]
  PIN xd[200]
    DIRECTION OUTPUT ;
    USE SIGNAL ;
    PORT
      LAYER M5 ;
        RECT  35.28 129.408 35.304 129.6 ;
    END
  END xd[200]
  PIN xd[201]
    DIRECTION OUTPUT ;
    USE SIGNAL ;
    PORT
      LAYER M5 ;
        RECT  35.328 129.408 35.352 129.6 ;
    END
  END xd[201]
  PIN xd[202]
    DIRECTION OUTPUT ;
    USE SIGNAL ;
    PORT
      LAYER M5 ;
        RECT  35.376 129.408 35.4 129.6 ;
    END
  END xd[202]
  PIN xd[203]
    DIRECTION OUTPUT ;
    USE SIGNAL ;
    PORT
      LAYER M5 ;
        RECT  35.424 129.408 35.448 129.6 ;
    END
  END xd[203]
  PIN xd[204]
    DIRECTION OUTPUT ;
    USE SIGNAL ;
    PORT
      LAYER M5 ;
        RECT  35.472 129.408 35.496 129.6 ;
    END
  END xd[204]
  PIN xd[205]
    DIRECTION OUTPUT ;
    USE SIGNAL ;
    PORT
      LAYER M5 ;
        RECT  35.52 129.408 35.544 129.6 ;
    END
  END xd[205]
  PIN xd[206]
    DIRECTION OUTPUT ;
    USE SIGNAL ;
    PORT
      LAYER M5 ;
        RECT  35.568 129.408 35.592 129.6 ;
    END
  END xd[206]
  PIN xd[207]
    DIRECTION OUTPUT ;
    USE SIGNAL ;
    PORT
      LAYER M5 ;
        RECT  35.616 129.408 35.64 129.6 ;
    END
  END xd[207]
  PIN xd[208]
    DIRECTION OUTPUT ;
    USE SIGNAL ;
    PORT
      LAYER M5 ;
        RECT  35.664 129.408 35.688 129.6 ;
    END
  END xd[208]
  PIN xd[209]
    DIRECTION OUTPUT ;
    USE SIGNAL ;
    PORT
      LAYER M5 ;
        RECT  35.712 129.408 35.736 129.6 ;
    END
  END xd[209]
  PIN xd[20]
    DIRECTION OUTPUT ;
    USE SIGNAL ;
    PORT
      LAYER M5 ;
        RECT  26.64 129.408 26.664 129.6 ;
    END
  END xd[20]
  PIN xd[210]
    DIRECTION OUTPUT ;
    USE SIGNAL ;
    PORT
      LAYER M5 ;
        RECT  35.76 129.408 35.784 129.6 ;
    END
  END xd[210]
  PIN xd[211]
    DIRECTION OUTPUT ;
    USE SIGNAL ;
    PORT
      LAYER M5 ;
        RECT  35.808 129.408 35.832 129.6 ;
    END
  END xd[211]
  PIN xd[212]
    DIRECTION OUTPUT ;
    USE SIGNAL ;
    PORT
      LAYER M5 ;
        RECT  35.856 129.408 35.88 129.6 ;
    END
  END xd[212]
  PIN xd[213]
    DIRECTION OUTPUT ;
    USE SIGNAL ;
    PORT
      LAYER M5 ;
        RECT  35.904 129.408 35.928 129.6 ;
    END
  END xd[213]
  PIN xd[214]
    DIRECTION OUTPUT ;
    USE SIGNAL ;
    PORT
      LAYER M5 ;
        RECT  35.952 129.408 35.976 129.6 ;
    END
  END xd[214]
  PIN xd[215]
    DIRECTION OUTPUT ;
    USE SIGNAL ;
    PORT
      LAYER M5 ;
        RECT  36 129.408 36.024 129.6 ;
    END
  END xd[215]
  PIN xd[216]
    DIRECTION OUTPUT ;
    USE SIGNAL ;
    PORT
      LAYER M5 ;
        RECT  36.048 129.408 36.072 129.6 ;
    END
  END xd[216]
  PIN xd[217]
    DIRECTION OUTPUT ;
    USE SIGNAL ;
    PORT
      LAYER M5 ;
        RECT  36.096 129.408 36.12 129.6 ;
    END
  END xd[217]
  PIN xd[218]
    DIRECTION OUTPUT ;
    USE SIGNAL ;
    PORT
      LAYER M5 ;
        RECT  36.144 129.408 36.168 129.6 ;
    END
  END xd[218]
  PIN xd[219]
    DIRECTION OUTPUT ;
    USE SIGNAL ;
    PORT
      LAYER M5 ;
        RECT  36.192 129.408 36.216 129.6 ;
    END
  END xd[219]
  PIN xd[21]
    DIRECTION OUTPUT ;
    USE SIGNAL ;
    PORT
      LAYER M5 ;
        RECT  26.688 129.408 26.712 129.6 ;
    END
  END xd[21]
  PIN xd[220]
    DIRECTION OUTPUT ;
    USE SIGNAL ;
    PORT
      LAYER M5 ;
        RECT  36.24 129.408 36.264 129.6 ;
    END
  END xd[220]
  PIN xd[221]
    DIRECTION OUTPUT ;
    USE SIGNAL ;
    PORT
      LAYER M5 ;
        RECT  36.288 129.408 36.312 129.6 ;
    END
  END xd[221]
  PIN xd[222]
    DIRECTION OUTPUT ;
    USE SIGNAL ;
    PORT
      LAYER M5 ;
        RECT  36.336 129.408 36.36 129.6 ;
    END
  END xd[222]
  PIN xd[223]
    DIRECTION OUTPUT ;
    USE SIGNAL ;
    PORT
      LAYER M5 ;
        RECT  36.384 129.408 36.408 129.6 ;
    END
  END xd[223]
  PIN xd[224]
    DIRECTION OUTPUT ;
    USE SIGNAL ;
    PORT
      LAYER M5 ;
        RECT  36.432 129.408 36.456 129.6 ;
    END
  END xd[224]
  PIN xd[225]
    DIRECTION OUTPUT ;
    USE SIGNAL ;
    PORT
      LAYER M5 ;
        RECT  36.48 129.408 36.504 129.6 ;
    END
  END xd[225]
  PIN xd[226]
    DIRECTION OUTPUT ;
    USE SIGNAL ;
    PORT
      LAYER M5 ;
        RECT  36.528 129.408 36.552 129.6 ;
    END
  END xd[226]
  PIN xd[227]
    DIRECTION OUTPUT ;
    USE SIGNAL ;
    PORT
      LAYER M5 ;
        RECT  36.576 129.408 36.6 129.6 ;
    END
  END xd[227]
  PIN xd[228]
    DIRECTION OUTPUT ;
    USE SIGNAL ;
    PORT
      LAYER M5 ;
        RECT  36.624 129.408 36.648 129.6 ;
    END
  END xd[228]
  PIN xd[229]
    DIRECTION OUTPUT ;
    USE SIGNAL ;
    PORT
      LAYER M5 ;
        RECT  36.672 129.408 36.696 129.6 ;
    END
  END xd[229]
  PIN xd[22]
    DIRECTION OUTPUT ;
    USE SIGNAL ;
    PORT
      LAYER M5 ;
        RECT  26.736 129.408 26.76 129.6 ;
    END
  END xd[22]
  PIN xd[230]
    DIRECTION OUTPUT ;
    USE SIGNAL ;
    PORT
      LAYER M5 ;
        RECT  36.72 129.408 36.744 129.6 ;
    END
  END xd[230]
  PIN xd[231]
    DIRECTION OUTPUT ;
    USE SIGNAL ;
    PORT
      LAYER M5 ;
        RECT  36.768 129.408 36.792 129.6 ;
    END
  END xd[231]
  PIN xd[232]
    DIRECTION OUTPUT ;
    USE SIGNAL ;
    PORT
      LAYER M5 ;
        RECT  36.816 129.408 36.84 129.6 ;
    END
  END xd[232]
  PIN xd[233]
    DIRECTION OUTPUT ;
    USE SIGNAL ;
    PORT
      LAYER M5 ;
        RECT  36.864 129.408 36.888 129.6 ;
    END
  END xd[233]
  PIN xd[234]
    DIRECTION OUTPUT ;
    USE SIGNAL ;
    PORT
      LAYER M5 ;
        RECT  36.912 129.408 36.936 129.6 ;
    END
  END xd[234]
  PIN xd[235]
    DIRECTION OUTPUT ;
    USE SIGNAL ;
    PORT
      LAYER M5 ;
        RECT  36.96 129.408 36.984 129.6 ;
    END
  END xd[235]
  PIN xd[236]
    DIRECTION OUTPUT ;
    USE SIGNAL ;
    PORT
      LAYER M5 ;
        RECT  37.008 129.408 37.032 129.6 ;
    END
  END xd[236]
  PIN xd[237]
    DIRECTION OUTPUT ;
    USE SIGNAL ;
    PORT
      LAYER M5 ;
        RECT  37.056 129.408 37.08 129.6 ;
    END
  END xd[237]
  PIN xd[238]
    DIRECTION OUTPUT ;
    USE SIGNAL ;
    PORT
      LAYER M5 ;
        RECT  37.104 129.408 37.128 129.6 ;
    END
  END xd[238]
  PIN xd[239]
    DIRECTION OUTPUT ;
    USE SIGNAL ;
    PORT
      LAYER M5 ;
        RECT  37.152 129.408 37.176 129.6 ;
    END
  END xd[239]
  PIN xd[23]
    DIRECTION OUTPUT ;
    USE SIGNAL ;
    PORT
      LAYER M5 ;
        RECT  26.784 129.408 26.808 129.6 ;
    END
  END xd[23]
  PIN xd[240]
    DIRECTION OUTPUT ;
    USE SIGNAL ;
    PORT
      LAYER M5 ;
        RECT  37.2 129.408 37.224 129.6 ;
    END
  END xd[240]
  PIN xd[241]
    DIRECTION OUTPUT ;
    USE SIGNAL ;
    PORT
      LAYER M5 ;
        RECT  37.248 129.408 37.272 129.6 ;
    END
  END xd[241]
  PIN xd[242]
    DIRECTION OUTPUT ;
    USE SIGNAL ;
    PORT
      LAYER M5 ;
        RECT  37.296 129.408 37.32 129.6 ;
    END
  END xd[242]
  PIN xd[243]
    DIRECTION OUTPUT ;
    USE SIGNAL ;
    PORT
      LAYER M5 ;
        RECT  37.344 129.408 37.368 129.6 ;
    END
  END xd[243]
  PIN xd[244]
    DIRECTION OUTPUT ;
    USE SIGNAL ;
    PORT
      LAYER M5 ;
        RECT  37.392 129.408 37.416 129.6 ;
    END
  END xd[244]
  PIN xd[245]
    DIRECTION OUTPUT ;
    USE SIGNAL ;
    PORT
      LAYER M5 ;
        RECT  37.44 129.408 37.464 129.6 ;
    END
  END xd[245]
  PIN xd[246]
    DIRECTION OUTPUT ;
    USE SIGNAL ;
    PORT
      LAYER M5 ;
        RECT  37.488 129.408 37.512 129.6 ;
    END
  END xd[246]
  PIN xd[247]
    DIRECTION OUTPUT ;
    USE SIGNAL ;
    PORT
      LAYER M5 ;
        RECT  37.536 129.408 37.56 129.6 ;
    END
  END xd[247]
  PIN xd[248]
    DIRECTION OUTPUT ;
    USE SIGNAL ;
    PORT
      LAYER M5 ;
        RECT  37.584 129.408 37.608 129.6 ;
    END
  END xd[248]
  PIN xd[249]
    DIRECTION OUTPUT ;
    USE SIGNAL ;
    PORT
      LAYER M5 ;
        RECT  37.632 129.408 37.656 129.6 ;
    END
  END xd[249]
  PIN xd[24]
    DIRECTION OUTPUT ;
    USE SIGNAL ;
    PORT
      LAYER M5 ;
        RECT  26.832 129.408 26.856 129.6 ;
    END
  END xd[24]
  PIN xd[250]
    DIRECTION OUTPUT ;
    USE SIGNAL ;
    PORT
      LAYER M5 ;
        RECT  37.68 129.408 37.704 129.6 ;
    END
  END xd[250]
  PIN xd[251]
    DIRECTION OUTPUT ;
    USE SIGNAL ;
    PORT
      LAYER M5 ;
        RECT  37.728 129.408 37.752 129.6 ;
    END
  END xd[251]
  PIN xd[252]
    DIRECTION OUTPUT ;
    USE SIGNAL ;
    PORT
      LAYER M5 ;
        RECT  37.776 129.408 37.8 129.6 ;
    END
  END xd[252]
  PIN xd[253]
    DIRECTION OUTPUT ;
    USE SIGNAL ;
    PORT
      LAYER M5 ;
        RECT  37.824 129.408 37.848 129.6 ;
    END
  END xd[253]
  PIN xd[254]
    DIRECTION OUTPUT ;
    USE SIGNAL ;
    PORT
      LAYER M5 ;
        RECT  37.872 129.408 37.896 129.6 ;
    END
  END xd[254]
  PIN xd[255]
    DIRECTION OUTPUT ;
    USE SIGNAL ;
    PORT
      LAYER M5 ;
        RECT  37.92 129.408 37.944 129.6 ;
    END
  END xd[255]
  PIN xd[256]
    DIRECTION OUTPUT ;
    USE SIGNAL ;
    PORT
      LAYER M5 ;
        RECT  37.968 129.408 37.992 129.6 ;
    END
  END xd[256]
  PIN xd[257]
    DIRECTION OUTPUT ;
    USE SIGNAL ;
    PORT
      LAYER M5 ;
        RECT  38.016 129.408 38.04 129.6 ;
    END
  END xd[257]
  PIN xd[258]
    DIRECTION OUTPUT ;
    USE SIGNAL ;
    PORT
      LAYER M5 ;
        RECT  38.064 129.408 38.088 129.6 ;
    END
  END xd[258]
  PIN xd[259]
    DIRECTION OUTPUT ;
    USE SIGNAL ;
    PORT
      LAYER M5 ;
        RECT  38.112 129.408 38.136 129.6 ;
    END
  END xd[259]
  PIN xd[25]
    DIRECTION OUTPUT ;
    USE SIGNAL ;
    PORT
      LAYER M5 ;
        RECT  26.88 129.408 26.904 129.6 ;
    END
  END xd[25]
  PIN xd[260]
    DIRECTION OUTPUT ;
    USE SIGNAL ;
    PORT
      LAYER M5 ;
        RECT  38.16 129.408 38.184 129.6 ;
    END
  END xd[260]
  PIN xd[261]
    DIRECTION OUTPUT ;
    USE SIGNAL ;
    PORT
      LAYER M5 ;
        RECT  38.208 129.408 38.232 129.6 ;
    END
  END xd[261]
  PIN xd[262]
    DIRECTION OUTPUT ;
    USE SIGNAL ;
    PORT
      LAYER M5 ;
        RECT  38.256 129.408 38.28 129.6 ;
    END
  END xd[262]
  PIN xd[263]
    DIRECTION OUTPUT ;
    USE SIGNAL ;
    PORT
      LAYER M5 ;
        RECT  38.304 129.408 38.328 129.6 ;
    END
  END xd[263]
  PIN xd[264]
    DIRECTION OUTPUT ;
    USE SIGNAL ;
    PORT
      LAYER M5 ;
        RECT  38.352 129.408 38.376 129.6 ;
    END
  END xd[264]
  PIN xd[265]
    DIRECTION OUTPUT ;
    USE SIGNAL ;
    PORT
      LAYER M5 ;
        RECT  38.4 129.408 38.424 129.6 ;
    END
  END xd[265]
  PIN xd[266]
    DIRECTION OUTPUT ;
    USE SIGNAL ;
    PORT
      LAYER M5 ;
        RECT  38.448 129.408 38.472 129.6 ;
    END
  END xd[266]
  PIN xd[267]
    DIRECTION OUTPUT ;
    USE SIGNAL ;
    PORT
      LAYER M5 ;
        RECT  38.496 129.408 38.52 129.6 ;
    END
  END xd[267]
  PIN xd[268]
    DIRECTION OUTPUT ;
    USE SIGNAL ;
    PORT
      LAYER M5 ;
        RECT  38.544 129.408 38.568 129.6 ;
    END
  END xd[268]
  PIN xd[269]
    DIRECTION OUTPUT ;
    USE SIGNAL ;
    PORT
      LAYER M5 ;
        RECT  38.592 129.408 38.616 129.6 ;
    END
  END xd[269]
  PIN xd[26]
    DIRECTION OUTPUT ;
    USE SIGNAL ;
    PORT
      LAYER M5 ;
        RECT  26.928 129.408 26.952 129.6 ;
    END
  END xd[26]
  PIN xd[270]
    DIRECTION OUTPUT ;
    USE SIGNAL ;
    PORT
      LAYER M5 ;
        RECT  38.64 129.408 38.664 129.6 ;
    END
  END xd[270]
  PIN xd[271]
    DIRECTION OUTPUT ;
    USE SIGNAL ;
    PORT
      LAYER M5 ;
        RECT  38.688 129.408 38.712 129.6 ;
    END
  END xd[271]
  PIN xd[272]
    DIRECTION OUTPUT ;
    USE SIGNAL ;
    PORT
      LAYER M5 ;
        RECT  38.736 129.408 38.76 129.6 ;
    END
  END xd[272]
  PIN xd[273]
    DIRECTION OUTPUT ;
    USE SIGNAL ;
    PORT
      LAYER M5 ;
        RECT  38.784 129.408 38.808 129.6 ;
    END
  END xd[273]
  PIN xd[274]
    DIRECTION OUTPUT ;
    USE SIGNAL ;
    PORT
      LAYER M5 ;
        RECT  38.832 129.408 38.856 129.6 ;
    END
  END xd[274]
  PIN xd[275]
    DIRECTION OUTPUT ;
    USE SIGNAL ;
    PORT
      LAYER M5 ;
        RECT  38.88 129.408 38.904 129.6 ;
    END
  END xd[275]
  PIN xd[276]
    DIRECTION OUTPUT ;
    USE SIGNAL ;
    PORT
      LAYER M5 ;
        RECT  38.928 129.408 38.952 129.6 ;
    END
  END xd[276]
  PIN xd[277]
    DIRECTION OUTPUT ;
    USE SIGNAL ;
    PORT
      LAYER M5 ;
        RECT  38.976 129.408 39 129.6 ;
    END
  END xd[277]
  PIN xd[278]
    DIRECTION OUTPUT ;
    USE SIGNAL ;
    PORT
      LAYER M5 ;
        RECT  39.024 129.408 39.048 129.6 ;
    END
  END xd[278]
  PIN xd[279]
    DIRECTION OUTPUT ;
    USE SIGNAL ;
    PORT
      LAYER M5 ;
        RECT  39.072 129.408 39.096 129.6 ;
    END
  END xd[279]
  PIN xd[27]
    DIRECTION OUTPUT ;
    USE SIGNAL ;
    PORT
      LAYER M5 ;
        RECT  26.976 129.408 27 129.6 ;
    END
  END xd[27]
  PIN xd[280]
    DIRECTION OUTPUT ;
    USE SIGNAL ;
    PORT
      LAYER M5 ;
        RECT  39.12 129.408 39.144 129.6 ;
    END
  END xd[280]
  PIN xd[281]
    DIRECTION OUTPUT ;
    USE SIGNAL ;
    PORT
      LAYER M5 ;
        RECT  39.168 129.408 39.192 129.6 ;
    END
  END xd[281]
  PIN xd[282]
    DIRECTION OUTPUT ;
    USE SIGNAL ;
    PORT
      LAYER M5 ;
        RECT  39.216 129.408 39.24 129.6 ;
    END
  END xd[282]
  PIN xd[283]
    DIRECTION OUTPUT ;
    USE SIGNAL ;
    PORT
      LAYER M5 ;
        RECT  39.264 129.408 39.288 129.6 ;
    END
  END xd[283]
  PIN xd[284]
    DIRECTION OUTPUT ;
    USE SIGNAL ;
    PORT
      LAYER M5 ;
        RECT  39.312 129.408 39.336 129.6 ;
    END
  END xd[284]
  PIN xd[285]
    DIRECTION OUTPUT ;
    USE SIGNAL ;
    PORT
      LAYER M5 ;
        RECT  39.36 129.408 39.384 129.6 ;
    END
  END xd[285]
  PIN xd[286]
    DIRECTION OUTPUT ;
    USE SIGNAL ;
    PORT
      LAYER M5 ;
        RECT  39.408 129.408 39.432 129.6 ;
    END
  END xd[286]
  PIN xd[287]
    DIRECTION OUTPUT ;
    USE SIGNAL ;
    PORT
      LAYER M5 ;
        RECT  39.456 129.408 39.48 129.6 ;
    END
  END xd[287]
  PIN xd[288]
    DIRECTION OUTPUT ;
    USE SIGNAL ;
    PORT
      LAYER M5 ;
        RECT  39.504 129.408 39.528 129.6 ;
    END
  END xd[288]
  PIN xd[289]
    DIRECTION OUTPUT ;
    USE SIGNAL ;
    PORT
      LAYER M5 ;
        RECT  39.552 129.408 39.576 129.6 ;
    END
  END xd[289]
  PIN xd[28]
    DIRECTION OUTPUT ;
    USE SIGNAL ;
    PORT
      LAYER M5 ;
        RECT  27.024 129.408 27.048 129.6 ;
    END
  END xd[28]
  PIN xd[290]
    DIRECTION OUTPUT ;
    USE SIGNAL ;
    PORT
      LAYER M5 ;
        RECT  39.6 129.408 39.624 129.6 ;
    END
  END xd[290]
  PIN xd[291]
    DIRECTION OUTPUT ;
    USE SIGNAL ;
    PORT
      LAYER M5 ;
        RECT  39.648 129.408 39.672 129.6 ;
    END
  END xd[291]
  PIN xd[292]
    DIRECTION OUTPUT ;
    USE SIGNAL ;
    PORT
      LAYER M5 ;
        RECT  39.696 129.408 39.72 129.6 ;
    END
  END xd[292]
  PIN xd[293]
    DIRECTION OUTPUT ;
    USE SIGNAL ;
    PORT
      LAYER M5 ;
        RECT  39.744 129.408 39.768 129.6 ;
    END
  END xd[293]
  PIN xd[294]
    DIRECTION OUTPUT ;
    USE SIGNAL ;
    PORT
      LAYER M5 ;
        RECT  39.792 129.408 39.816 129.6 ;
    END
  END xd[294]
  PIN xd[295]
    DIRECTION OUTPUT ;
    USE SIGNAL ;
    PORT
      LAYER M5 ;
        RECT  39.84 129.408 39.864 129.6 ;
    END
  END xd[295]
  PIN xd[296]
    DIRECTION OUTPUT ;
    USE SIGNAL ;
    PORT
      LAYER M5 ;
        RECT  39.888 129.408 39.912 129.6 ;
    END
  END xd[296]
  PIN xd[297]
    DIRECTION OUTPUT ;
    USE SIGNAL ;
    PORT
      LAYER M5 ;
        RECT  39.936 129.408 39.96 129.6 ;
    END
  END xd[297]
  PIN xd[298]
    DIRECTION OUTPUT ;
    USE SIGNAL ;
    PORT
      LAYER M5 ;
        RECT  39.984 129.408 40.008 129.6 ;
    END
  END xd[298]
  PIN xd[299]
    DIRECTION OUTPUT ;
    USE SIGNAL ;
    PORT
      LAYER M5 ;
        RECT  40.032 129.408 40.056 129.6 ;
    END
  END xd[299]
  PIN xd[29]
    DIRECTION OUTPUT ;
    USE SIGNAL ;
    PORT
      LAYER M5 ;
        RECT  27.072 129.408 27.096 129.6 ;
    END
  END xd[29]
  PIN xd[2]
    DIRECTION OUTPUT ;
    USE SIGNAL ;
    PORT
      LAYER M5 ;
        RECT  25.776 129.408 25.8 129.6 ;
    END
  END xd[2]
  PIN xd[300]
    DIRECTION OUTPUT ;
    USE SIGNAL ;
    PORT
      LAYER M5 ;
        RECT  40.08 129.408 40.104 129.6 ;
    END
  END xd[300]
  PIN xd[301]
    DIRECTION OUTPUT ;
    USE SIGNAL ;
    PORT
      LAYER M5 ;
        RECT  40.128 129.408 40.152 129.6 ;
    END
  END xd[301]
  PIN xd[302]
    DIRECTION OUTPUT ;
    USE SIGNAL ;
    PORT
      LAYER M5 ;
        RECT  40.176 129.408 40.2 129.6 ;
    END
  END xd[302]
  PIN xd[303]
    DIRECTION OUTPUT ;
    USE SIGNAL ;
    PORT
      LAYER M5 ;
        RECT  40.224 129.408 40.248 129.6 ;
    END
  END xd[303]
  PIN xd[304]
    DIRECTION OUTPUT ;
    USE SIGNAL ;
    PORT
      LAYER M5 ;
        RECT  40.272 129.408 40.296 129.6 ;
    END
  END xd[304]
  PIN xd[305]
    DIRECTION OUTPUT ;
    USE SIGNAL ;
    PORT
      LAYER M5 ;
        RECT  40.32 129.408 40.344 129.6 ;
    END
  END xd[305]
  PIN xd[306]
    DIRECTION OUTPUT ;
    USE SIGNAL ;
    PORT
      LAYER M5 ;
        RECT  40.368 129.408 40.392 129.6 ;
    END
  END xd[306]
  PIN xd[307]
    DIRECTION OUTPUT ;
    USE SIGNAL ;
    PORT
      LAYER M5 ;
        RECT  40.416 129.408 40.44 129.6 ;
    END
  END xd[307]
  PIN xd[308]
    DIRECTION OUTPUT ;
    USE SIGNAL ;
    PORT
      LAYER M5 ;
        RECT  40.464 129.408 40.488 129.6 ;
    END
  END xd[308]
  PIN xd[309]
    DIRECTION OUTPUT ;
    USE SIGNAL ;
    PORT
      LAYER M5 ;
        RECT  40.512 129.408 40.536 129.6 ;
    END
  END xd[309]
  PIN xd[30]
    DIRECTION OUTPUT ;
    USE SIGNAL ;
    PORT
      LAYER M5 ;
        RECT  27.12 129.408 27.144 129.6 ;
    END
  END xd[30]
  PIN xd[310]
    DIRECTION OUTPUT ;
    USE SIGNAL ;
    PORT
      LAYER M5 ;
        RECT  40.56 129.408 40.584 129.6 ;
    END
  END xd[310]
  PIN xd[311]
    DIRECTION OUTPUT ;
    USE SIGNAL ;
    PORT
      LAYER M5 ;
        RECT  40.608 129.408 40.632 129.6 ;
    END
  END xd[311]
  PIN xd[312]
    DIRECTION OUTPUT ;
    USE SIGNAL ;
    PORT
      LAYER M5 ;
        RECT  40.656 129.408 40.68 129.6 ;
    END
  END xd[312]
  PIN xd[313]
    DIRECTION OUTPUT ;
    USE SIGNAL ;
    PORT
      LAYER M5 ;
        RECT  40.704 129.408 40.728 129.6 ;
    END
  END xd[313]
  PIN xd[314]
    DIRECTION OUTPUT ;
    USE SIGNAL ;
    PORT
      LAYER M5 ;
        RECT  40.752 129.408 40.776 129.6 ;
    END
  END xd[314]
  PIN xd[315]
    DIRECTION OUTPUT ;
    USE SIGNAL ;
    PORT
      LAYER M5 ;
        RECT  40.8 129.408 40.824 129.6 ;
    END
  END xd[315]
  PIN xd[316]
    DIRECTION OUTPUT ;
    USE SIGNAL ;
    PORT
      LAYER M5 ;
        RECT  40.848 129.408 40.872 129.6 ;
    END
  END xd[316]
  PIN xd[317]
    DIRECTION OUTPUT ;
    USE SIGNAL ;
    PORT
      LAYER M5 ;
        RECT  40.896 129.408 40.92 129.6 ;
    END
  END xd[317]
  PIN xd[318]
    DIRECTION OUTPUT ;
    USE SIGNAL ;
    PORT
      LAYER M5 ;
        RECT  40.944 129.408 40.968 129.6 ;
    END
  END xd[318]
  PIN xd[319]
    DIRECTION OUTPUT ;
    USE SIGNAL ;
    PORT
      LAYER M5 ;
        RECT  40.992 129.408 41.016 129.6 ;
    END
  END xd[319]
  PIN xd[31]
    DIRECTION OUTPUT ;
    USE SIGNAL ;
    PORT
      LAYER M5 ;
        RECT  27.168 129.408 27.192 129.6 ;
    END
  END xd[31]
  PIN xd[320]
    DIRECTION OUTPUT ;
    USE SIGNAL ;
    PORT
      LAYER M5 ;
        RECT  41.04 129.408 41.064 129.6 ;
    END
  END xd[320]
  PIN xd[321]
    DIRECTION OUTPUT ;
    USE SIGNAL ;
    PORT
      LAYER M5 ;
        RECT  41.088 129.408 41.112 129.6 ;
    END
  END xd[321]
  PIN xd[322]
    DIRECTION OUTPUT ;
    USE SIGNAL ;
    PORT
      LAYER M5 ;
        RECT  41.136 129.408 41.16 129.6 ;
    END
  END xd[322]
  PIN xd[323]
    DIRECTION OUTPUT ;
    USE SIGNAL ;
    PORT
      LAYER M5 ;
        RECT  41.184 129.408 41.208 129.6 ;
    END
  END xd[323]
  PIN xd[324]
    DIRECTION OUTPUT ;
    USE SIGNAL ;
    PORT
      LAYER M5 ;
        RECT  41.232 129.408 41.256 129.6 ;
    END
  END xd[324]
  PIN xd[325]
    DIRECTION OUTPUT ;
    USE SIGNAL ;
    PORT
      LAYER M5 ;
        RECT  41.28 129.408 41.304 129.6 ;
    END
  END xd[325]
  PIN xd[326]
    DIRECTION OUTPUT ;
    USE SIGNAL ;
    PORT
      LAYER M5 ;
        RECT  41.328 129.408 41.352 129.6 ;
    END
  END xd[326]
  PIN xd[327]
    DIRECTION OUTPUT ;
    USE SIGNAL ;
    PORT
      LAYER M5 ;
        RECT  41.376 129.408 41.4 129.6 ;
    END
  END xd[327]
  PIN xd[328]
    DIRECTION OUTPUT ;
    USE SIGNAL ;
    PORT
      LAYER M5 ;
        RECT  41.424 129.408 41.448 129.6 ;
    END
  END xd[328]
  PIN xd[329]
    DIRECTION OUTPUT ;
    USE SIGNAL ;
    PORT
      LAYER M5 ;
        RECT  41.472 129.408 41.496 129.6 ;
    END
  END xd[329]
  PIN xd[32]
    DIRECTION OUTPUT ;
    USE SIGNAL ;
    PORT
      LAYER M5 ;
        RECT  27.216 129.408 27.24 129.6 ;
    END
  END xd[32]
  PIN xd[330]
    DIRECTION OUTPUT ;
    USE SIGNAL ;
    PORT
      LAYER M5 ;
        RECT  41.52 129.408 41.544 129.6 ;
    END
  END xd[330]
  PIN xd[331]
    DIRECTION OUTPUT ;
    USE SIGNAL ;
    PORT
      LAYER M5 ;
        RECT  41.568 129.408 41.592 129.6 ;
    END
  END xd[331]
  PIN xd[332]
    DIRECTION OUTPUT ;
    USE SIGNAL ;
    PORT
      LAYER M5 ;
        RECT  41.616 129.408 41.64 129.6 ;
    END
  END xd[332]
  PIN xd[333]
    DIRECTION OUTPUT ;
    USE SIGNAL ;
    PORT
      LAYER M5 ;
        RECT  41.664 129.408 41.688 129.6 ;
    END
  END xd[333]
  PIN xd[334]
    DIRECTION OUTPUT ;
    USE SIGNAL ;
    PORT
      LAYER M5 ;
        RECT  41.712 129.408 41.736 129.6 ;
    END
  END xd[334]
  PIN xd[335]
    DIRECTION OUTPUT ;
    USE SIGNAL ;
    PORT
      LAYER M5 ;
        RECT  41.76 129.408 41.784 129.6 ;
    END
  END xd[335]
  PIN xd[336]
    DIRECTION OUTPUT ;
    USE SIGNAL ;
    PORT
      LAYER M5 ;
        RECT  41.808 129.408 41.832 129.6 ;
    END
  END xd[336]
  PIN xd[337]
    DIRECTION OUTPUT ;
    USE SIGNAL ;
    PORT
      LAYER M5 ;
        RECT  41.856 129.408 41.88 129.6 ;
    END
  END xd[337]
  PIN xd[338]
    DIRECTION OUTPUT ;
    USE SIGNAL ;
    PORT
      LAYER M5 ;
        RECT  41.904 129.408 41.928 129.6 ;
    END
  END xd[338]
  PIN xd[339]
    DIRECTION OUTPUT ;
    USE SIGNAL ;
    PORT
      LAYER M5 ;
        RECT  41.952 129.408 41.976 129.6 ;
    END
  END xd[339]
  PIN xd[33]
    DIRECTION OUTPUT ;
    USE SIGNAL ;
    PORT
      LAYER M5 ;
        RECT  27.264 129.408 27.288 129.6 ;
    END
  END xd[33]
  PIN xd[340]
    DIRECTION OUTPUT ;
    USE SIGNAL ;
    PORT
      LAYER M5 ;
        RECT  42 129.408 42.024 129.6 ;
    END
  END xd[340]
  PIN xd[341]
    DIRECTION OUTPUT ;
    USE SIGNAL ;
    PORT
      LAYER M5 ;
        RECT  42.048 129.408 42.072 129.6 ;
    END
  END xd[341]
  PIN xd[342]
    DIRECTION OUTPUT ;
    USE SIGNAL ;
    PORT
      LAYER M5 ;
        RECT  42.096 129.408 42.12 129.6 ;
    END
  END xd[342]
  PIN xd[343]
    DIRECTION OUTPUT ;
    USE SIGNAL ;
    PORT
      LAYER M5 ;
        RECT  42.144 129.408 42.168 129.6 ;
    END
  END xd[343]
  PIN xd[344]
    DIRECTION OUTPUT ;
    USE SIGNAL ;
    PORT
      LAYER M5 ;
        RECT  42.192 129.408 42.216 129.6 ;
    END
  END xd[344]
  PIN xd[345]
    DIRECTION OUTPUT ;
    USE SIGNAL ;
    PORT
      LAYER M5 ;
        RECT  42.24 129.408 42.264 129.6 ;
    END
  END xd[345]
  PIN xd[346]
    DIRECTION OUTPUT ;
    USE SIGNAL ;
    PORT
      LAYER M5 ;
        RECT  42.288 129.408 42.312 129.6 ;
    END
  END xd[346]
  PIN xd[347]
    DIRECTION OUTPUT ;
    USE SIGNAL ;
    PORT
      LAYER M5 ;
        RECT  42.336 129.408 42.36 129.6 ;
    END
  END xd[347]
  PIN xd[348]
    DIRECTION OUTPUT ;
    USE SIGNAL ;
    PORT
      LAYER M5 ;
        RECT  42.384 129.408 42.408 129.6 ;
    END
  END xd[348]
  PIN xd[349]
    DIRECTION OUTPUT ;
    USE SIGNAL ;
    PORT
      LAYER M5 ;
        RECT  42.432 129.408 42.456 129.6 ;
    END
  END xd[349]
  PIN xd[34]
    DIRECTION OUTPUT ;
    USE SIGNAL ;
    PORT
      LAYER M5 ;
        RECT  27.312 129.408 27.336 129.6 ;
    END
  END xd[34]
  PIN xd[350]
    DIRECTION OUTPUT ;
    USE SIGNAL ;
    PORT
      LAYER M5 ;
        RECT  42.48 129.408 42.504 129.6 ;
    END
  END xd[350]
  PIN xd[351]
    DIRECTION OUTPUT ;
    USE SIGNAL ;
    PORT
      LAYER M5 ;
        RECT  42.528 129.408 42.552 129.6 ;
    END
  END xd[351]
  PIN xd[352]
    DIRECTION OUTPUT ;
    USE SIGNAL ;
    PORT
      LAYER M5 ;
        RECT  42.576 129.408 42.6 129.6 ;
    END
  END xd[352]
  PIN xd[353]
    DIRECTION OUTPUT ;
    USE SIGNAL ;
    PORT
      LAYER M5 ;
        RECT  42.624 129.408 42.648 129.6 ;
    END
  END xd[353]
  PIN xd[354]
    DIRECTION OUTPUT ;
    USE SIGNAL ;
    PORT
      LAYER M5 ;
        RECT  42.672 129.408 42.696 129.6 ;
    END
  END xd[354]
  PIN xd[355]
    DIRECTION OUTPUT ;
    USE SIGNAL ;
    PORT
      LAYER M5 ;
        RECT  42.72 129.408 42.744 129.6 ;
    END
  END xd[355]
  PIN xd[356]
    DIRECTION OUTPUT ;
    USE SIGNAL ;
    PORT
      LAYER M5 ;
        RECT  42.768 129.408 42.792 129.6 ;
    END
  END xd[356]
  PIN xd[357]
    DIRECTION OUTPUT ;
    USE SIGNAL ;
    PORT
      LAYER M5 ;
        RECT  42.816 129.408 42.84 129.6 ;
    END
  END xd[357]
  PIN xd[358]
    DIRECTION OUTPUT ;
    USE SIGNAL ;
    PORT
      LAYER M5 ;
        RECT  42.864 129.408 42.888 129.6 ;
    END
  END xd[358]
  PIN xd[359]
    DIRECTION OUTPUT ;
    USE SIGNAL ;
    PORT
      LAYER M5 ;
        RECT  42.912 129.408 42.936 129.6 ;
    END
  END xd[359]
  PIN xd[35]
    DIRECTION OUTPUT ;
    USE SIGNAL ;
    PORT
      LAYER M5 ;
        RECT  27.36 129.408 27.384 129.6 ;
    END
  END xd[35]
  PIN xd[360]
    DIRECTION OUTPUT ;
    USE SIGNAL ;
    PORT
      LAYER M5 ;
        RECT  42.96 129.408 42.984 129.6 ;
    END
  END xd[360]
  PIN xd[361]
    DIRECTION OUTPUT ;
    USE SIGNAL ;
    PORT
      LAYER M5 ;
        RECT  43.008 129.408 43.032 129.6 ;
    END
  END xd[361]
  PIN xd[362]
    DIRECTION OUTPUT ;
    USE SIGNAL ;
    PORT
      LAYER M5 ;
        RECT  43.056 129.408 43.08 129.6 ;
    END
  END xd[362]
  PIN xd[363]
    DIRECTION OUTPUT ;
    USE SIGNAL ;
    PORT
      LAYER M5 ;
        RECT  43.104 129.408 43.128 129.6 ;
    END
  END xd[363]
  PIN xd[364]
    DIRECTION OUTPUT ;
    USE SIGNAL ;
    PORT
      LAYER M5 ;
        RECT  43.152 129.408 43.176 129.6 ;
    END
  END xd[364]
  PIN xd[365]
    DIRECTION OUTPUT ;
    USE SIGNAL ;
    PORT
      LAYER M5 ;
        RECT  43.2 129.408 43.224 129.6 ;
    END
  END xd[365]
  PIN xd[366]
    DIRECTION OUTPUT ;
    USE SIGNAL ;
    PORT
      LAYER M5 ;
        RECT  43.248 129.408 43.272 129.6 ;
    END
  END xd[366]
  PIN xd[367]
    DIRECTION OUTPUT ;
    USE SIGNAL ;
    PORT
      LAYER M5 ;
        RECT  43.296 129.408 43.32 129.6 ;
    END
  END xd[367]
  PIN xd[368]
    DIRECTION OUTPUT ;
    USE SIGNAL ;
    PORT
      LAYER M5 ;
        RECT  43.344 129.408 43.368 129.6 ;
    END
  END xd[368]
  PIN xd[369]
    DIRECTION OUTPUT ;
    USE SIGNAL ;
    PORT
      LAYER M5 ;
        RECT  43.392 129.408 43.416 129.6 ;
    END
  END xd[369]
  PIN xd[36]
    DIRECTION OUTPUT ;
    USE SIGNAL ;
    PORT
      LAYER M5 ;
        RECT  27.408 129.408 27.432 129.6 ;
    END
  END xd[36]
  PIN xd[370]
    DIRECTION OUTPUT ;
    USE SIGNAL ;
    PORT
      LAYER M5 ;
        RECT  43.44 129.408 43.464 129.6 ;
    END
  END xd[370]
  PIN xd[371]
    DIRECTION OUTPUT ;
    USE SIGNAL ;
    PORT
      LAYER M5 ;
        RECT  43.488 129.408 43.512 129.6 ;
    END
  END xd[371]
  PIN xd[372]
    DIRECTION OUTPUT ;
    USE SIGNAL ;
    PORT
      LAYER M5 ;
        RECT  43.536 129.408 43.56 129.6 ;
    END
  END xd[372]
  PIN xd[373]
    DIRECTION OUTPUT ;
    USE SIGNAL ;
    PORT
      LAYER M5 ;
        RECT  43.584 129.408 43.608 129.6 ;
    END
  END xd[373]
  PIN xd[374]
    DIRECTION OUTPUT ;
    USE SIGNAL ;
    PORT
      LAYER M5 ;
        RECT  43.632 129.408 43.656 129.6 ;
    END
  END xd[374]
  PIN xd[375]
    DIRECTION OUTPUT ;
    USE SIGNAL ;
    PORT
      LAYER M5 ;
        RECT  43.68 129.408 43.704 129.6 ;
    END
  END xd[375]
  PIN xd[376]
    DIRECTION OUTPUT ;
    USE SIGNAL ;
    PORT
      LAYER M5 ;
        RECT  43.728 129.408 43.752 129.6 ;
    END
  END xd[376]
  PIN xd[377]
    DIRECTION OUTPUT ;
    USE SIGNAL ;
    PORT
      LAYER M5 ;
        RECT  43.776 129.408 43.8 129.6 ;
    END
  END xd[377]
  PIN xd[378]
    DIRECTION OUTPUT ;
    USE SIGNAL ;
    PORT
      LAYER M5 ;
        RECT  43.824 129.408 43.848 129.6 ;
    END
  END xd[378]
  PIN xd[379]
    DIRECTION OUTPUT ;
    USE SIGNAL ;
    PORT
      LAYER M5 ;
        RECT  43.872 129.408 43.896 129.6 ;
    END
  END xd[379]
  PIN xd[37]
    DIRECTION OUTPUT ;
    USE SIGNAL ;
    PORT
      LAYER M5 ;
        RECT  27.456 129.408 27.48 129.6 ;
    END
  END xd[37]
  PIN xd[380]
    DIRECTION OUTPUT ;
    USE SIGNAL ;
    PORT
      LAYER M5 ;
        RECT  43.92 129.408 43.944 129.6 ;
    END
  END xd[380]
  PIN xd[381]
    DIRECTION OUTPUT ;
    USE SIGNAL ;
    PORT
      LAYER M5 ;
        RECT  43.968 129.408 43.992 129.6 ;
    END
  END xd[381]
  PIN xd[382]
    DIRECTION OUTPUT ;
    USE SIGNAL ;
    PORT
      LAYER M5 ;
        RECT  44.016 129.408 44.04 129.6 ;
    END
  END xd[382]
  PIN xd[383]
    DIRECTION OUTPUT ;
    USE SIGNAL ;
    PORT
      LAYER M5 ;
        RECT  44.064 129.408 44.088 129.6 ;
    END
  END xd[383]
  PIN xd[384]
    DIRECTION OUTPUT ;
    USE SIGNAL ;
    PORT
      LAYER M5 ;
        RECT  44.112 129.408 44.136 129.6 ;
    END
  END xd[384]
  PIN xd[385]
    DIRECTION OUTPUT ;
    USE SIGNAL ;
    PORT
      LAYER M5 ;
        RECT  44.16 129.408 44.184 129.6 ;
    END
  END xd[385]
  PIN xd[386]
    DIRECTION OUTPUT ;
    USE SIGNAL ;
    PORT
      LAYER M5 ;
        RECT  44.208 129.408 44.232 129.6 ;
    END
  END xd[386]
  PIN xd[387]
    DIRECTION OUTPUT ;
    USE SIGNAL ;
    PORT
      LAYER M5 ;
        RECT  44.256 129.408 44.28 129.6 ;
    END
  END xd[387]
  PIN xd[388]
    DIRECTION OUTPUT ;
    USE SIGNAL ;
    PORT
      LAYER M5 ;
        RECT  44.304 129.408 44.328 129.6 ;
    END
  END xd[388]
  PIN xd[389]
    DIRECTION OUTPUT ;
    USE SIGNAL ;
    PORT
      LAYER M5 ;
        RECT  44.352 129.408 44.376 129.6 ;
    END
  END xd[389]
  PIN xd[38]
    DIRECTION OUTPUT ;
    USE SIGNAL ;
    PORT
      LAYER M5 ;
        RECT  27.504 129.408 27.528 129.6 ;
    END
  END xd[38]
  PIN xd[390]
    DIRECTION OUTPUT ;
    USE SIGNAL ;
    PORT
      LAYER M5 ;
        RECT  44.4 129.408 44.424 129.6 ;
    END
  END xd[390]
  PIN xd[391]
    DIRECTION OUTPUT ;
    USE SIGNAL ;
    PORT
      LAYER M5 ;
        RECT  44.448 129.408 44.472 129.6 ;
    END
  END xd[391]
  PIN xd[392]
    DIRECTION OUTPUT ;
    USE SIGNAL ;
    PORT
      LAYER M5 ;
        RECT  44.496 129.408 44.52 129.6 ;
    END
  END xd[392]
  PIN xd[393]
    DIRECTION OUTPUT ;
    USE SIGNAL ;
    PORT
      LAYER M5 ;
        RECT  44.544 129.408 44.568 129.6 ;
    END
  END xd[393]
  PIN xd[394]
    DIRECTION OUTPUT ;
    USE SIGNAL ;
    PORT
      LAYER M5 ;
        RECT  44.592 129.408 44.616 129.6 ;
    END
  END xd[394]
  PIN xd[395]
    DIRECTION OUTPUT ;
    USE SIGNAL ;
    PORT
      LAYER M5 ;
        RECT  44.64 129.408 44.664 129.6 ;
    END
  END xd[395]
  PIN xd[396]
    DIRECTION OUTPUT ;
    USE SIGNAL ;
    PORT
      LAYER M5 ;
        RECT  44.688 129.408 44.712 129.6 ;
    END
  END xd[396]
  PIN xd[397]
    DIRECTION OUTPUT ;
    USE SIGNAL ;
    PORT
      LAYER M5 ;
        RECT  44.736 129.408 44.76 129.6 ;
    END
  END xd[397]
  PIN xd[398]
    DIRECTION OUTPUT ;
    USE SIGNAL ;
    PORT
      LAYER M5 ;
        RECT  44.784 129.408 44.808 129.6 ;
    END
  END xd[398]
  PIN xd[399]
    DIRECTION OUTPUT ;
    USE SIGNAL ;
    PORT
      LAYER M5 ;
        RECT  44.832 129.408 44.856 129.6 ;
    END
  END xd[399]
  PIN xd[39]
    DIRECTION OUTPUT ;
    USE SIGNAL ;
    PORT
      LAYER M5 ;
        RECT  27.552 129.408 27.576 129.6 ;
    END
  END xd[39]
  PIN xd[3]
    DIRECTION OUTPUT ;
    USE SIGNAL ;
    PORT
      LAYER M5 ;
        RECT  25.824 129.408 25.848 129.6 ;
    END
  END xd[3]
  PIN xd[400]
    DIRECTION OUTPUT ;
    USE SIGNAL ;
    PORT
      LAYER M5 ;
        RECT  44.88 129.408 44.904 129.6 ;
    END
  END xd[400]
  PIN xd[401]
    DIRECTION OUTPUT ;
    USE SIGNAL ;
    PORT
      LAYER M5 ;
        RECT  44.928 129.408 44.952 129.6 ;
    END
  END xd[401]
  PIN xd[402]
    DIRECTION OUTPUT ;
    USE SIGNAL ;
    PORT
      LAYER M5 ;
        RECT  44.976 129.408 45 129.6 ;
    END
  END xd[402]
  PIN xd[403]
    DIRECTION OUTPUT ;
    USE SIGNAL ;
    PORT
      LAYER M5 ;
        RECT  45.024 129.408 45.048 129.6 ;
    END
  END xd[403]
  PIN xd[404]
    DIRECTION OUTPUT ;
    USE SIGNAL ;
    PORT
      LAYER M5 ;
        RECT  45.072 129.408 45.096 129.6 ;
    END
  END xd[404]
  PIN xd[405]
    DIRECTION OUTPUT ;
    USE SIGNAL ;
    PORT
      LAYER M5 ;
        RECT  45.12 129.408 45.144 129.6 ;
    END
  END xd[405]
  PIN xd[406]
    DIRECTION OUTPUT ;
    USE SIGNAL ;
    PORT
      LAYER M5 ;
        RECT  45.168 129.408 45.192 129.6 ;
    END
  END xd[406]
  PIN xd[407]
    DIRECTION OUTPUT ;
    USE SIGNAL ;
    PORT
      LAYER M5 ;
        RECT  45.216 129.408 45.24 129.6 ;
    END
  END xd[407]
  PIN xd[408]
    DIRECTION OUTPUT ;
    USE SIGNAL ;
    PORT
      LAYER M5 ;
        RECT  45.264 129.408 45.288 129.6 ;
    END
  END xd[408]
  PIN xd[409]
    DIRECTION OUTPUT ;
    USE SIGNAL ;
    PORT
      LAYER M5 ;
        RECT  45.312 129.408 45.336 129.6 ;
    END
  END xd[409]
  PIN xd[40]
    DIRECTION OUTPUT ;
    USE SIGNAL ;
    PORT
      LAYER M5 ;
        RECT  27.6 129.408 27.624 129.6 ;
    END
  END xd[40]
  PIN xd[410]
    DIRECTION OUTPUT ;
    USE SIGNAL ;
    PORT
      LAYER M5 ;
        RECT  45.36 129.408 45.384 129.6 ;
    END
  END xd[410]
  PIN xd[411]
    DIRECTION OUTPUT ;
    USE SIGNAL ;
    PORT
      LAYER M5 ;
        RECT  45.408 129.408 45.432 129.6 ;
    END
  END xd[411]
  PIN xd[412]
    DIRECTION OUTPUT ;
    USE SIGNAL ;
    PORT
      LAYER M5 ;
        RECT  45.456 129.408 45.48 129.6 ;
    END
  END xd[412]
  PIN xd[413]
    DIRECTION OUTPUT ;
    USE SIGNAL ;
    PORT
      LAYER M5 ;
        RECT  45.504 129.408 45.528 129.6 ;
    END
  END xd[413]
  PIN xd[414]
    DIRECTION OUTPUT ;
    USE SIGNAL ;
    PORT
      LAYER M5 ;
        RECT  45.552 129.408 45.576 129.6 ;
    END
  END xd[414]
  PIN xd[415]
    DIRECTION OUTPUT ;
    USE SIGNAL ;
    PORT
      LAYER M5 ;
        RECT  45.6 129.408 45.624 129.6 ;
    END
  END xd[415]
  PIN xd[416]
    DIRECTION OUTPUT ;
    USE SIGNAL ;
    PORT
      LAYER M5 ;
        RECT  45.648 129.408 45.672 129.6 ;
    END
  END xd[416]
  PIN xd[417]
    DIRECTION OUTPUT ;
    USE SIGNAL ;
    PORT
      LAYER M5 ;
        RECT  45.696 129.408 45.72 129.6 ;
    END
  END xd[417]
  PIN xd[418]
    DIRECTION OUTPUT ;
    USE SIGNAL ;
    PORT
      LAYER M5 ;
        RECT  45.744 129.408 45.768 129.6 ;
    END
  END xd[418]
  PIN xd[419]
    DIRECTION OUTPUT ;
    USE SIGNAL ;
    PORT
      LAYER M5 ;
        RECT  45.792 129.408 45.816 129.6 ;
    END
  END xd[419]
  PIN xd[41]
    DIRECTION OUTPUT ;
    USE SIGNAL ;
    PORT
      LAYER M5 ;
        RECT  27.648 129.408 27.672 129.6 ;
    END
  END xd[41]
  PIN xd[420]
    DIRECTION OUTPUT ;
    USE SIGNAL ;
    PORT
      LAYER M5 ;
        RECT  45.84 129.408 45.864 129.6 ;
    END
  END xd[420]
  PIN xd[421]
    DIRECTION OUTPUT ;
    USE SIGNAL ;
    PORT
      LAYER M5 ;
        RECT  45.888 129.408 45.912 129.6 ;
    END
  END xd[421]
  PIN xd[422]
    DIRECTION OUTPUT ;
    USE SIGNAL ;
    PORT
      LAYER M5 ;
        RECT  45.936 129.408 45.96 129.6 ;
    END
  END xd[422]
  PIN xd[423]
    DIRECTION OUTPUT ;
    USE SIGNAL ;
    PORT
      LAYER M5 ;
        RECT  45.984 129.408 46.008 129.6 ;
    END
  END xd[423]
  PIN xd[424]
    DIRECTION OUTPUT ;
    USE SIGNAL ;
    PORT
      LAYER M5 ;
        RECT  46.032 129.408 46.056 129.6 ;
    END
  END xd[424]
  PIN xd[425]
    DIRECTION OUTPUT ;
    USE SIGNAL ;
    PORT
      LAYER M5 ;
        RECT  46.08 129.408 46.104 129.6 ;
    END
  END xd[425]
  PIN xd[426]
    DIRECTION OUTPUT ;
    USE SIGNAL ;
    PORT
      LAYER M5 ;
        RECT  46.128 129.408 46.152 129.6 ;
    END
  END xd[426]
  PIN xd[427]
    DIRECTION OUTPUT ;
    USE SIGNAL ;
    PORT
      LAYER M5 ;
        RECT  46.176 129.408 46.2 129.6 ;
    END
  END xd[427]
  PIN xd[428]
    DIRECTION OUTPUT ;
    USE SIGNAL ;
    PORT
      LAYER M5 ;
        RECT  46.224 129.408 46.248 129.6 ;
    END
  END xd[428]
  PIN xd[429]
    DIRECTION OUTPUT ;
    USE SIGNAL ;
    PORT
      LAYER M5 ;
        RECT  46.272 129.408 46.296 129.6 ;
    END
  END xd[429]
  PIN xd[42]
    DIRECTION OUTPUT ;
    USE SIGNAL ;
    PORT
      LAYER M5 ;
        RECT  27.696 129.408 27.72 129.6 ;
    END
  END xd[42]
  PIN xd[430]
    DIRECTION OUTPUT ;
    USE SIGNAL ;
    PORT
      LAYER M5 ;
        RECT  46.32 129.408 46.344 129.6 ;
    END
  END xd[430]
  PIN xd[431]
    DIRECTION OUTPUT ;
    USE SIGNAL ;
    PORT
      LAYER M5 ;
        RECT  46.368 129.408 46.392 129.6 ;
    END
  END xd[431]
  PIN xd[432]
    DIRECTION OUTPUT ;
    USE SIGNAL ;
    PORT
      LAYER M5 ;
        RECT  46.416 129.408 46.44 129.6 ;
    END
  END xd[432]
  PIN xd[433]
    DIRECTION OUTPUT ;
    USE SIGNAL ;
    PORT
      LAYER M5 ;
        RECT  46.464 129.408 46.488 129.6 ;
    END
  END xd[433]
  PIN xd[434]
    DIRECTION OUTPUT ;
    USE SIGNAL ;
    PORT
      LAYER M5 ;
        RECT  46.512 129.408 46.536 129.6 ;
    END
  END xd[434]
  PIN xd[435]
    DIRECTION OUTPUT ;
    USE SIGNAL ;
    PORT
      LAYER M5 ;
        RECT  46.56 129.408 46.584 129.6 ;
    END
  END xd[435]
  PIN xd[436]
    DIRECTION OUTPUT ;
    USE SIGNAL ;
    PORT
      LAYER M5 ;
        RECT  46.608 129.408 46.632 129.6 ;
    END
  END xd[436]
  PIN xd[437]
    DIRECTION OUTPUT ;
    USE SIGNAL ;
    PORT
      LAYER M5 ;
        RECT  46.656 129.408 46.68 129.6 ;
    END
  END xd[437]
  PIN xd[438]
    DIRECTION OUTPUT ;
    USE SIGNAL ;
    PORT
      LAYER M5 ;
        RECT  46.704 129.408 46.728 129.6 ;
    END
  END xd[438]
  PIN xd[439]
    DIRECTION OUTPUT ;
    USE SIGNAL ;
    PORT
      LAYER M5 ;
        RECT  46.752 129.408 46.776 129.6 ;
    END
  END xd[439]
  PIN xd[43]
    DIRECTION OUTPUT ;
    USE SIGNAL ;
    PORT
      LAYER M5 ;
        RECT  27.744 129.408 27.768 129.6 ;
    END
  END xd[43]
  PIN xd[440]
    DIRECTION OUTPUT ;
    USE SIGNAL ;
    PORT
      LAYER M5 ;
        RECT  46.8 129.408 46.824 129.6 ;
    END
  END xd[440]
  PIN xd[441]
    DIRECTION OUTPUT ;
    USE SIGNAL ;
    PORT
      LAYER M5 ;
        RECT  46.848 129.408 46.872 129.6 ;
    END
  END xd[441]
  PIN xd[442]
    DIRECTION OUTPUT ;
    USE SIGNAL ;
    PORT
      LAYER M5 ;
        RECT  46.896 129.408 46.92 129.6 ;
    END
  END xd[442]
  PIN xd[443]
    DIRECTION OUTPUT ;
    USE SIGNAL ;
    PORT
      LAYER M5 ;
        RECT  46.944 129.408 46.968 129.6 ;
    END
  END xd[443]
  PIN xd[444]
    DIRECTION OUTPUT ;
    USE SIGNAL ;
    PORT
      LAYER M5 ;
        RECT  46.992 129.408 47.016 129.6 ;
    END
  END xd[444]
  PIN xd[445]
    DIRECTION OUTPUT ;
    USE SIGNAL ;
    PORT
      LAYER M5 ;
        RECT  47.04 129.408 47.064 129.6 ;
    END
  END xd[445]
  PIN xd[446]
    DIRECTION OUTPUT ;
    USE SIGNAL ;
    PORT
      LAYER M5 ;
        RECT  47.088 129.408 47.112 129.6 ;
    END
  END xd[446]
  PIN xd[447]
    DIRECTION OUTPUT ;
    USE SIGNAL ;
    PORT
      LAYER M5 ;
        RECT  47.136 129.408 47.16 129.6 ;
    END
  END xd[447]
  PIN xd[448]
    DIRECTION OUTPUT ;
    USE SIGNAL ;
    PORT
      LAYER M5 ;
        RECT  47.184 129.408 47.208 129.6 ;
    END
  END xd[448]
  PIN xd[449]
    DIRECTION OUTPUT ;
    USE SIGNAL ;
    PORT
      LAYER M5 ;
        RECT  47.232 129.408 47.256 129.6 ;
    END
  END xd[449]
  PIN xd[44]
    DIRECTION OUTPUT ;
    USE SIGNAL ;
    PORT
      LAYER M5 ;
        RECT  27.792 129.408 27.816 129.6 ;
    END
  END xd[44]
  PIN xd[450]
    DIRECTION OUTPUT ;
    USE SIGNAL ;
    PORT
      LAYER M5 ;
        RECT  47.28 129.408 47.304 129.6 ;
    END
  END xd[450]
  PIN xd[451]
    DIRECTION OUTPUT ;
    USE SIGNAL ;
    PORT
      LAYER M5 ;
        RECT  47.328 129.408 47.352 129.6 ;
    END
  END xd[451]
  PIN xd[452]
    DIRECTION OUTPUT ;
    USE SIGNAL ;
    PORT
      LAYER M5 ;
        RECT  47.376 129.408 47.4 129.6 ;
    END
  END xd[452]
  PIN xd[453]
    DIRECTION OUTPUT ;
    USE SIGNAL ;
    PORT
      LAYER M5 ;
        RECT  47.424 129.408 47.448 129.6 ;
    END
  END xd[453]
  PIN xd[454]
    DIRECTION OUTPUT ;
    USE SIGNAL ;
    PORT
      LAYER M5 ;
        RECT  47.472 129.408 47.496 129.6 ;
    END
  END xd[454]
  PIN xd[455]
    DIRECTION OUTPUT ;
    USE SIGNAL ;
    PORT
      LAYER M5 ;
        RECT  47.52 129.408 47.544 129.6 ;
    END
  END xd[455]
  PIN xd[456]
    DIRECTION OUTPUT ;
    USE SIGNAL ;
    PORT
      LAYER M5 ;
        RECT  47.568 129.408 47.592 129.6 ;
    END
  END xd[456]
  PIN xd[457]
    DIRECTION OUTPUT ;
    USE SIGNAL ;
    PORT
      LAYER M5 ;
        RECT  47.616 129.408 47.64 129.6 ;
    END
  END xd[457]
  PIN xd[458]
    DIRECTION OUTPUT ;
    USE SIGNAL ;
    PORT
      LAYER M5 ;
        RECT  47.664 129.408 47.688 129.6 ;
    END
  END xd[458]
  PIN xd[459]
    DIRECTION OUTPUT ;
    USE SIGNAL ;
    PORT
      LAYER M5 ;
        RECT  47.712 129.408 47.736 129.6 ;
    END
  END xd[459]
  PIN xd[45]
    DIRECTION OUTPUT ;
    USE SIGNAL ;
    PORT
      LAYER M5 ;
        RECT  27.84 129.408 27.864 129.6 ;
    END
  END xd[45]
  PIN xd[460]
    DIRECTION OUTPUT ;
    USE SIGNAL ;
    PORT
      LAYER M5 ;
        RECT  47.76 129.408 47.784 129.6 ;
    END
  END xd[460]
  PIN xd[461]
    DIRECTION OUTPUT ;
    USE SIGNAL ;
    PORT
      LAYER M5 ;
        RECT  47.808 129.408 47.832 129.6 ;
    END
  END xd[461]
  PIN xd[462]
    DIRECTION OUTPUT ;
    USE SIGNAL ;
    PORT
      LAYER M5 ;
        RECT  47.856 129.408 47.88 129.6 ;
    END
  END xd[462]
  PIN xd[463]
    DIRECTION OUTPUT ;
    USE SIGNAL ;
    PORT
      LAYER M5 ;
        RECT  47.904 129.408 47.928 129.6 ;
    END
  END xd[463]
  PIN xd[464]
    DIRECTION OUTPUT ;
    USE SIGNAL ;
    PORT
      LAYER M5 ;
        RECT  47.952 129.408 47.976 129.6 ;
    END
  END xd[464]
  PIN xd[465]
    DIRECTION OUTPUT ;
    USE SIGNAL ;
    PORT
      LAYER M5 ;
        RECT  48 129.408 48.024 129.6 ;
    END
  END xd[465]
  PIN xd[466]
    DIRECTION OUTPUT ;
    USE SIGNAL ;
    PORT
      LAYER M5 ;
        RECT  48.048 129.408 48.072 129.6 ;
    END
  END xd[466]
  PIN xd[467]
    DIRECTION OUTPUT ;
    USE SIGNAL ;
    PORT
      LAYER M5 ;
        RECT  48.096 129.408 48.12 129.6 ;
    END
  END xd[467]
  PIN xd[468]
    DIRECTION OUTPUT ;
    USE SIGNAL ;
    PORT
      LAYER M5 ;
        RECT  48.144 129.408 48.168 129.6 ;
    END
  END xd[468]
  PIN xd[469]
    DIRECTION OUTPUT ;
    USE SIGNAL ;
    PORT
      LAYER M5 ;
        RECT  48.192 129.408 48.216 129.6 ;
    END
  END xd[469]
  PIN xd[46]
    DIRECTION OUTPUT ;
    USE SIGNAL ;
    PORT
      LAYER M5 ;
        RECT  27.888 129.408 27.912 129.6 ;
    END
  END xd[46]
  PIN xd[470]
    DIRECTION OUTPUT ;
    USE SIGNAL ;
    PORT
      LAYER M5 ;
        RECT  48.24 129.408 48.264 129.6 ;
    END
  END xd[470]
  PIN xd[471]
    DIRECTION OUTPUT ;
    USE SIGNAL ;
    PORT
      LAYER M5 ;
        RECT  48.288 129.408 48.312 129.6 ;
    END
  END xd[471]
  PIN xd[472]
    DIRECTION OUTPUT ;
    USE SIGNAL ;
    PORT
      LAYER M5 ;
        RECT  48.336 129.408 48.36 129.6 ;
    END
  END xd[472]
  PIN xd[473]
    DIRECTION OUTPUT ;
    USE SIGNAL ;
    PORT
      LAYER M5 ;
        RECT  48.384 129.408 48.408 129.6 ;
    END
  END xd[473]
  PIN xd[474]
    DIRECTION OUTPUT ;
    USE SIGNAL ;
    PORT
      LAYER M5 ;
        RECT  48.432 129.408 48.456 129.6 ;
    END
  END xd[474]
  PIN xd[475]
    DIRECTION OUTPUT ;
    USE SIGNAL ;
    PORT
      LAYER M5 ;
        RECT  48.48 129.408 48.504 129.6 ;
    END
  END xd[475]
  PIN xd[476]
    DIRECTION OUTPUT ;
    USE SIGNAL ;
    PORT
      LAYER M5 ;
        RECT  48.528 129.408 48.552 129.6 ;
    END
  END xd[476]
  PIN xd[477]
    DIRECTION OUTPUT ;
    USE SIGNAL ;
    PORT
      LAYER M5 ;
        RECT  48.576 129.408 48.6 129.6 ;
    END
  END xd[477]
  PIN xd[478]
    DIRECTION OUTPUT ;
    USE SIGNAL ;
    PORT
      LAYER M5 ;
        RECT  48.624 129.408 48.648 129.6 ;
    END
  END xd[478]
  PIN xd[479]
    DIRECTION OUTPUT ;
    USE SIGNAL ;
    PORT
      LAYER M5 ;
        RECT  48.672 129.408 48.696 129.6 ;
    END
  END xd[479]
  PIN xd[47]
    DIRECTION OUTPUT ;
    USE SIGNAL ;
    PORT
      LAYER M5 ;
        RECT  27.936 129.408 27.96 129.6 ;
    END
  END xd[47]
  PIN xd[480]
    DIRECTION OUTPUT ;
    USE SIGNAL ;
    PORT
      LAYER M5 ;
        RECT  48.72 129.408 48.744 129.6 ;
    END
  END xd[480]
  PIN xd[481]
    DIRECTION OUTPUT ;
    USE SIGNAL ;
    PORT
      LAYER M5 ;
        RECT  48.768 129.408 48.792 129.6 ;
    END
  END xd[481]
  PIN xd[482]
    DIRECTION OUTPUT ;
    USE SIGNAL ;
    PORT
      LAYER M5 ;
        RECT  48.816 129.408 48.84 129.6 ;
    END
  END xd[482]
  PIN xd[483]
    DIRECTION OUTPUT ;
    USE SIGNAL ;
    PORT
      LAYER M5 ;
        RECT  48.864 129.408 48.888 129.6 ;
    END
  END xd[483]
  PIN xd[484]
    DIRECTION OUTPUT ;
    USE SIGNAL ;
    PORT
      LAYER M5 ;
        RECT  48.912 129.408 48.936 129.6 ;
    END
  END xd[484]
  PIN xd[485]
    DIRECTION OUTPUT ;
    USE SIGNAL ;
    PORT
      LAYER M5 ;
        RECT  48.96 129.408 48.984 129.6 ;
    END
  END xd[485]
  PIN xd[486]
    DIRECTION OUTPUT ;
    USE SIGNAL ;
    PORT
      LAYER M5 ;
        RECT  49.008 129.408 49.032 129.6 ;
    END
  END xd[486]
  PIN xd[487]
    DIRECTION OUTPUT ;
    USE SIGNAL ;
    PORT
      LAYER M5 ;
        RECT  49.056 129.408 49.08 129.6 ;
    END
  END xd[487]
  PIN xd[488]
    DIRECTION OUTPUT ;
    USE SIGNAL ;
    PORT
      LAYER M5 ;
        RECT  49.104 129.408 49.128 129.6 ;
    END
  END xd[488]
  PIN xd[489]
    DIRECTION OUTPUT ;
    USE SIGNAL ;
    PORT
      LAYER M5 ;
        RECT  49.152 129.408 49.176 129.6 ;
    END
  END xd[489]
  PIN xd[48]
    DIRECTION OUTPUT ;
    USE SIGNAL ;
    PORT
      LAYER M5 ;
        RECT  27.984 129.408 28.008 129.6 ;
    END
  END xd[48]
  PIN xd[490]
    DIRECTION OUTPUT ;
    USE SIGNAL ;
    PORT
      LAYER M5 ;
        RECT  49.2 129.408 49.224 129.6 ;
    END
  END xd[490]
  PIN xd[491]
    DIRECTION OUTPUT ;
    USE SIGNAL ;
    PORT
      LAYER M5 ;
        RECT  49.248 129.408 49.272 129.6 ;
    END
  END xd[491]
  PIN xd[492]
    DIRECTION OUTPUT ;
    USE SIGNAL ;
    PORT
      LAYER M5 ;
        RECT  49.296 129.408 49.32 129.6 ;
    END
  END xd[492]
  PIN xd[493]
    DIRECTION OUTPUT ;
    USE SIGNAL ;
    PORT
      LAYER M5 ;
        RECT  49.344 129.408 49.368 129.6 ;
    END
  END xd[493]
  PIN xd[494]
    DIRECTION OUTPUT ;
    USE SIGNAL ;
    PORT
      LAYER M5 ;
        RECT  49.392 129.408 49.416 129.6 ;
    END
  END xd[494]
  PIN xd[495]
    DIRECTION OUTPUT ;
    USE SIGNAL ;
    PORT
      LAYER M5 ;
        RECT  49.44 129.408 49.464 129.6 ;
    END
  END xd[495]
  PIN xd[496]
    DIRECTION OUTPUT ;
    USE SIGNAL ;
    PORT
      LAYER M5 ;
        RECT  49.488 129.408 49.512 129.6 ;
    END
  END xd[496]
  PIN xd[497]
    DIRECTION OUTPUT ;
    USE SIGNAL ;
    PORT
      LAYER M5 ;
        RECT  49.536 129.408 49.56 129.6 ;
    END
  END xd[497]
  PIN xd[498]
    DIRECTION OUTPUT ;
    USE SIGNAL ;
    PORT
      LAYER M5 ;
        RECT  49.584 129.408 49.608 129.6 ;
    END
  END xd[498]
  PIN xd[499]
    DIRECTION OUTPUT ;
    USE SIGNAL ;
    PORT
      LAYER M5 ;
        RECT  49.632 129.408 49.656 129.6 ;
    END
  END xd[499]
  PIN xd[49]
    DIRECTION OUTPUT ;
    USE SIGNAL ;
    PORT
      LAYER M5 ;
        RECT  28.032 129.408 28.056 129.6 ;
    END
  END xd[49]
  PIN xd[4]
    DIRECTION OUTPUT ;
    USE SIGNAL ;
    PORT
      LAYER M5 ;
        RECT  25.872 129.408 25.896 129.6 ;
    END
  END xd[4]
  PIN xd[500]
    DIRECTION OUTPUT ;
    USE SIGNAL ;
    PORT
      LAYER M5 ;
        RECT  49.68 129.408 49.704 129.6 ;
    END
  END xd[500]
  PIN xd[501]
    DIRECTION OUTPUT ;
    USE SIGNAL ;
    PORT
      LAYER M5 ;
        RECT  49.728 129.408 49.752 129.6 ;
    END
  END xd[501]
  PIN xd[502]
    DIRECTION OUTPUT ;
    USE SIGNAL ;
    PORT
      LAYER M5 ;
        RECT  49.776 129.408 49.8 129.6 ;
    END
  END xd[502]
  PIN xd[503]
    DIRECTION OUTPUT ;
    USE SIGNAL ;
    PORT
      LAYER M5 ;
        RECT  49.824 129.408 49.848 129.6 ;
    END
  END xd[503]
  PIN xd[504]
    DIRECTION OUTPUT ;
    USE SIGNAL ;
    PORT
      LAYER M5 ;
        RECT  49.872 129.408 49.896 129.6 ;
    END
  END xd[504]
  PIN xd[505]
    DIRECTION OUTPUT ;
    USE SIGNAL ;
    PORT
      LAYER M5 ;
        RECT  49.92 129.408 49.944 129.6 ;
    END
  END xd[505]
  PIN xd[506]
    DIRECTION OUTPUT ;
    USE SIGNAL ;
    PORT
      LAYER M5 ;
        RECT  49.968 129.408 49.992 129.6 ;
    END
  END xd[506]
  PIN xd[507]
    DIRECTION OUTPUT ;
    USE SIGNAL ;
    PORT
      LAYER M5 ;
        RECT  50.016 129.408 50.04 129.6 ;
    END
  END xd[507]
  PIN xd[508]
    DIRECTION OUTPUT ;
    USE SIGNAL ;
    PORT
      LAYER M5 ;
        RECT  50.064 129.408 50.088 129.6 ;
    END
  END xd[508]
  PIN xd[509]
    DIRECTION OUTPUT ;
    USE SIGNAL ;
    PORT
      LAYER M5 ;
        RECT  50.112 129.408 50.136 129.6 ;
    END
  END xd[509]
  PIN xd[50]
    DIRECTION OUTPUT ;
    USE SIGNAL ;
    PORT
      LAYER M5 ;
        RECT  28.08 129.408 28.104 129.6 ;
    END
  END xd[50]
  PIN xd[510]
    DIRECTION OUTPUT ;
    USE SIGNAL ;
    PORT
      LAYER M5 ;
        RECT  50.16 129.408 50.184 129.6 ;
    END
  END xd[510]
  PIN xd[511]
    DIRECTION OUTPUT ;
    USE SIGNAL ;
    PORT
      LAYER M5 ;
        RECT  50.208 129.408 50.232 129.6 ;
    END
  END xd[511]
  PIN xd[512]
    DIRECTION OUTPUT ;
    USE SIGNAL ;
    PORT
      LAYER M5 ;
        RECT  50.256 129.408 50.28 129.6 ;
    END
  END xd[512]
  PIN xd[513]
    DIRECTION OUTPUT ;
    USE SIGNAL ;
    PORT
      LAYER M5 ;
        RECT  50.304 129.408 50.328 129.6 ;
    END
  END xd[513]
  PIN xd[51]
    DIRECTION OUTPUT ;
    USE SIGNAL ;
    PORT
      LAYER M5 ;
        RECT  28.128 129.408 28.152 129.6 ;
    END
  END xd[51]
  PIN xd[52]
    DIRECTION OUTPUT ;
    USE SIGNAL ;
    PORT
      LAYER M5 ;
        RECT  28.176 129.408 28.2 129.6 ;
    END
  END xd[52]
  PIN xd[53]
    DIRECTION OUTPUT ;
    USE SIGNAL ;
    PORT
      LAYER M5 ;
        RECT  28.224 129.408 28.248 129.6 ;
    END
  END xd[53]
  PIN xd[54]
    DIRECTION OUTPUT ;
    USE SIGNAL ;
    PORT
      LAYER M5 ;
        RECT  28.272 129.408 28.296 129.6 ;
    END
  END xd[54]
  PIN xd[55]
    DIRECTION OUTPUT ;
    USE SIGNAL ;
    PORT
      LAYER M5 ;
        RECT  28.32 129.408 28.344 129.6 ;
    END
  END xd[55]
  PIN xd[56]
    DIRECTION OUTPUT ;
    USE SIGNAL ;
    PORT
      LAYER M5 ;
        RECT  28.368 129.408 28.392 129.6 ;
    END
  END xd[56]
  PIN xd[57]
    DIRECTION OUTPUT ;
    USE SIGNAL ;
    PORT
      LAYER M5 ;
        RECT  28.416 129.408 28.44 129.6 ;
    END
  END xd[57]
  PIN xd[58]
    DIRECTION OUTPUT ;
    USE SIGNAL ;
    PORT
      LAYER M5 ;
        RECT  28.464 129.408 28.488 129.6 ;
    END
  END xd[58]
  PIN xd[59]
    DIRECTION OUTPUT ;
    USE SIGNAL ;
    PORT
      LAYER M5 ;
        RECT  28.512 129.408 28.536 129.6 ;
    END
  END xd[59]
  PIN xd[5]
    DIRECTION OUTPUT ;
    USE SIGNAL ;
    PORT
      LAYER M5 ;
        RECT  25.92 129.408 25.944 129.6 ;
    END
  END xd[5]
  PIN xd[60]
    DIRECTION OUTPUT ;
    USE SIGNAL ;
    PORT
      LAYER M5 ;
        RECT  28.56 129.408 28.584 129.6 ;
    END
  END xd[60]
  PIN xd[61]
    DIRECTION OUTPUT ;
    USE SIGNAL ;
    PORT
      LAYER M5 ;
        RECT  28.608 129.408 28.632 129.6 ;
    END
  END xd[61]
  PIN xd[62]
    DIRECTION OUTPUT ;
    USE SIGNAL ;
    PORT
      LAYER M5 ;
        RECT  28.656 129.408 28.68 129.6 ;
    END
  END xd[62]
  PIN xd[63]
    DIRECTION OUTPUT ;
    USE SIGNAL ;
    PORT
      LAYER M5 ;
        RECT  28.704 129.408 28.728 129.6 ;
    END
  END xd[63]
  PIN xd[64]
    DIRECTION OUTPUT ;
    USE SIGNAL ;
    PORT
      LAYER M5 ;
        RECT  28.752 129.408 28.776 129.6 ;
    END
  END xd[64]
  PIN xd[65]
    DIRECTION OUTPUT ;
    USE SIGNAL ;
    PORT
      LAYER M5 ;
        RECT  28.8 129.408 28.824 129.6 ;
    END
  END xd[65]
  PIN xd[66]
    DIRECTION OUTPUT ;
    USE SIGNAL ;
    PORT
      LAYER M5 ;
        RECT  28.848 129.408 28.872 129.6 ;
    END
  END xd[66]
  PIN xd[67]
    DIRECTION OUTPUT ;
    USE SIGNAL ;
    PORT
      LAYER M5 ;
        RECT  28.896 129.408 28.92 129.6 ;
    END
  END xd[67]
  PIN xd[68]
    DIRECTION OUTPUT ;
    USE SIGNAL ;
    PORT
      LAYER M5 ;
        RECT  28.944 129.408 28.968 129.6 ;
    END
  END xd[68]
  PIN xd[69]
    DIRECTION OUTPUT ;
    USE SIGNAL ;
    PORT
      LAYER M5 ;
        RECT  28.992 129.408 29.016 129.6 ;
    END
  END xd[69]
  PIN xd[6]
    DIRECTION OUTPUT ;
    USE SIGNAL ;
    PORT
      LAYER M5 ;
        RECT  25.968 129.408 25.992 129.6 ;
    END
  END xd[6]
  PIN xd[70]
    DIRECTION OUTPUT ;
    USE SIGNAL ;
    PORT
      LAYER M5 ;
        RECT  29.04 129.408 29.064 129.6 ;
    END
  END xd[70]
  PIN xd[71]
    DIRECTION OUTPUT ;
    USE SIGNAL ;
    PORT
      LAYER M5 ;
        RECT  29.088 129.408 29.112 129.6 ;
    END
  END xd[71]
  PIN xd[72]
    DIRECTION OUTPUT ;
    USE SIGNAL ;
    PORT
      LAYER M5 ;
        RECT  29.136 129.408 29.16 129.6 ;
    END
  END xd[72]
  PIN xd[73]
    DIRECTION OUTPUT ;
    USE SIGNAL ;
    PORT
      LAYER M5 ;
        RECT  29.184 129.408 29.208 129.6 ;
    END
  END xd[73]
  PIN xd[74]
    DIRECTION OUTPUT ;
    USE SIGNAL ;
    PORT
      LAYER M5 ;
        RECT  29.232 129.408 29.256 129.6 ;
    END
  END xd[74]
  PIN xd[75]
    DIRECTION OUTPUT ;
    USE SIGNAL ;
    PORT
      LAYER M5 ;
        RECT  29.28 129.408 29.304 129.6 ;
    END
  END xd[75]
  PIN xd[76]
    DIRECTION OUTPUT ;
    USE SIGNAL ;
    PORT
      LAYER M5 ;
        RECT  29.328 129.408 29.352 129.6 ;
    END
  END xd[76]
  PIN xd[77]
    DIRECTION OUTPUT ;
    USE SIGNAL ;
    PORT
      LAYER M5 ;
        RECT  29.376 129.408 29.4 129.6 ;
    END
  END xd[77]
  PIN xd[78]
    DIRECTION OUTPUT ;
    USE SIGNAL ;
    PORT
      LAYER M5 ;
        RECT  29.424 129.408 29.448 129.6 ;
    END
  END xd[78]
  PIN xd[79]
    DIRECTION OUTPUT ;
    USE SIGNAL ;
    PORT
      LAYER M5 ;
        RECT  29.472 129.408 29.496 129.6 ;
    END
  END xd[79]
  PIN xd[7]
    DIRECTION OUTPUT ;
    USE SIGNAL ;
    PORT
      LAYER M5 ;
        RECT  26.016 129.408 26.04 129.6 ;
    END
  END xd[7]
  PIN xd[80]
    DIRECTION OUTPUT ;
    USE SIGNAL ;
    PORT
      LAYER M5 ;
        RECT  29.52 129.408 29.544 129.6 ;
    END
  END xd[80]
  PIN xd[81]
    DIRECTION OUTPUT ;
    USE SIGNAL ;
    PORT
      LAYER M5 ;
        RECT  29.568 129.408 29.592 129.6 ;
    END
  END xd[81]
  PIN xd[82]
    DIRECTION OUTPUT ;
    USE SIGNAL ;
    PORT
      LAYER M5 ;
        RECT  29.616 129.408 29.64 129.6 ;
    END
  END xd[82]
  PIN xd[83]
    DIRECTION OUTPUT ;
    USE SIGNAL ;
    PORT
      LAYER M5 ;
        RECT  29.664 129.408 29.688 129.6 ;
    END
  END xd[83]
  PIN xd[84]
    DIRECTION OUTPUT ;
    USE SIGNAL ;
    PORT
      LAYER M5 ;
        RECT  29.712 129.408 29.736 129.6 ;
    END
  END xd[84]
  PIN xd[85]
    DIRECTION OUTPUT ;
    USE SIGNAL ;
    PORT
      LAYER M5 ;
        RECT  29.76 129.408 29.784 129.6 ;
    END
  END xd[85]
  PIN xd[86]
    DIRECTION OUTPUT ;
    USE SIGNAL ;
    PORT
      LAYER M5 ;
        RECT  29.808 129.408 29.832 129.6 ;
    END
  END xd[86]
  PIN xd[87]
    DIRECTION OUTPUT ;
    USE SIGNAL ;
    PORT
      LAYER M5 ;
        RECT  29.856 129.408 29.88 129.6 ;
    END
  END xd[87]
  PIN xd[88]
    DIRECTION OUTPUT ;
    USE SIGNAL ;
    PORT
      LAYER M5 ;
        RECT  29.904 129.408 29.928 129.6 ;
    END
  END xd[88]
  PIN xd[89]
    DIRECTION OUTPUT ;
    USE SIGNAL ;
    PORT
      LAYER M5 ;
        RECT  29.952 129.408 29.976 129.6 ;
    END
  END xd[89]
  PIN xd[8]
    DIRECTION OUTPUT ;
    USE SIGNAL ;
    PORT
      LAYER M5 ;
        RECT  26.064 129.408 26.088 129.6 ;
    END
  END xd[8]
  PIN xd[90]
    DIRECTION OUTPUT ;
    USE SIGNAL ;
    PORT
      LAYER M5 ;
        RECT  30 129.408 30.024 129.6 ;
    END
  END xd[90]
  PIN xd[91]
    DIRECTION OUTPUT ;
    USE SIGNAL ;
    PORT
      LAYER M5 ;
        RECT  30.048 129.408 30.072 129.6 ;
    END
  END xd[91]
  PIN xd[92]
    DIRECTION OUTPUT ;
    USE SIGNAL ;
    PORT
      LAYER M5 ;
        RECT  30.096 129.408 30.12 129.6 ;
    END
  END xd[92]
  PIN xd[93]
    DIRECTION OUTPUT ;
    USE SIGNAL ;
    PORT
      LAYER M5 ;
        RECT  30.144 129.408 30.168 129.6 ;
    END
  END xd[93]
  PIN xd[94]
    DIRECTION OUTPUT ;
    USE SIGNAL ;
    PORT
      LAYER M5 ;
        RECT  30.192 129.408 30.216 129.6 ;
    END
  END xd[94]
  PIN xd[95]
    DIRECTION OUTPUT ;
    USE SIGNAL ;
    PORT
      LAYER M5 ;
        RECT  30.24 129.408 30.264 129.6 ;
    END
  END xd[95]
  PIN xd[96]
    DIRECTION OUTPUT ;
    USE SIGNAL ;
    PORT
      LAYER M5 ;
        RECT  30.288 129.408 30.312 129.6 ;
    END
  END xd[96]
  PIN xd[97]
    DIRECTION OUTPUT ;
    USE SIGNAL ;
    PORT
      LAYER M5 ;
        RECT  30.336 129.408 30.36 129.6 ;
    END
  END xd[97]
  PIN xd[98]
    DIRECTION OUTPUT ;
    USE SIGNAL ;
    PORT
      LAYER M5 ;
        RECT  30.384 129.408 30.408 129.6 ;
    END
  END xd[98]
  PIN xd[99]
    DIRECTION OUTPUT ;
    USE SIGNAL ;
    PORT
      LAYER M5 ;
        RECT  30.432 129.408 30.456 129.6 ;
    END
  END xd[99]
  PIN xd[9]
    DIRECTION OUTPUT ;
    USE SIGNAL ;
    PORT
      LAYER M5 ;
        RECT  26.112 129.408 26.136 129.6 ;
    END
  END xd[9]
  PIN xf[0]
    DIRECTION OUTPUT ;
    USE SIGNAL ;
    PORT
      LAYER M5 ;
        RECT  52.368 129.408 52.392 129.6 ;
    END
  END xf[0]
  PIN VDD
    DIRECTION INOUT ;
    USE POWER ;
    PORT
      LAYER M7 ;
        RECT  103.456 0.531 103.744 129.069 ;
        RECT  92.656 0.531 92.944 129.069 ;
        RECT  81.856 0.531 82.144 129.069 ;
        RECT  71.056 0.531 71.344 129.069 ;
        RECT  60.256 0.531 60.544 129.069 ;
        RECT  49.456 0.531 49.744 129.069 ;
        RECT  38.656 0.531 38.944 129.069 ;
        RECT  27.856 0.531 28.144 129.069 ;
        RECT  17.056 0.531 17.344 129.069 ;
        RECT  6.256 0.531 6.544 129.069 ;
      LAYER M6 ;
        RECT  107.968 125.772 108 126.06 ;
        RECT  0 125.772 0.032 126.06 ;
        RECT  107.968 120.372 108 120.66 ;
        RECT  0 120.372 0.032 120.66 ;
        RECT  107.968 114.972 108 115.26 ;
        RECT  0 114.972 0.032 115.26 ;
        RECT  107.968 109.572 108 109.86 ;
        RECT  0 109.572 0.032 109.86 ;
        RECT  107.968 104.172 108 104.46 ;
        RECT  0 104.172 0.032 104.46 ;
        RECT  107.968 98.772 108 99.06 ;
        RECT  0 98.772 0.032 99.06 ;
        RECT  107.968 93.372 108 93.66 ;
        RECT  0 93.372 0.032 93.66 ;
        RECT  107.968 87.972 108 88.26 ;
        RECT  0 87.972 0.032 88.26 ;
        RECT  107.968 82.572 108 82.86 ;
        RECT  0 82.572 0.032 82.86 ;
        RECT  107.968 77.172 108 77.46 ;
        RECT  0 77.172 0.032 77.46 ;
        RECT  107.968 71.772 108 72.06 ;
        RECT  0 71.772 0.032 72.06 ;
        RECT  107.968 66.372 108 66.66 ;
        RECT  0 66.372 0.032 66.66 ;
        RECT  107.968 60.972 108 61.26 ;
        RECT  0 60.972 0.032 61.26 ;
        RECT  107.968 55.572 108 55.86 ;
        RECT  0 55.572 0.032 55.86 ;
        RECT  107.968 50.172 108 50.46 ;
        RECT  0 50.172 0.032 50.46 ;
        RECT  107.968 44.772 108 45.06 ;
        RECT  0 44.772 0.032 45.06 ;
        RECT  107.968 39.372 108 39.66 ;
        RECT  0 39.372 0.032 39.66 ;
        RECT  107.968 33.972 108 34.26 ;
        RECT  0 33.972 0.032 34.26 ;
        RECT  107.968 28.572 108 28.86 ;
        RECT  0 28.572 0.032 28.86 ;
        RECT  107.968 23.172 108 23.46 ;
        RECT  0 23.172 0.032 23.46 ;
        RECT  107.968 17.772 108 18.06 ;
        RECT  0 17.772 0.032 18.06 ;
        RECT  107.968 12.372 108 12.66 ;
        RECT  0 12.372 0.032 12.66 ;
        RECT  107.968 6.972 108 7.26 ;
        RECT  0 6.972 0.032 7.26 ;
        RECT  107.968 1.572 108 1.86 ;
        RECT  0 1.572 0.032 1.86 ;
      LAYER M2 ;
        RECT  107.982 128.781 108 128.799 ;
        RECT  0 128.781 0.018 128.799 ;
        RECT  107.982 128.241 108 128.259 ;
        RECT  0 128.241 0.018 128.259 ;
        RECT  107.982 127.701 108 127.719 ;
        RECT  0 127.701 0.018 127.719 ;
        RECT  107.982 127.161 108 127.179 ;
        RECT  0 127.161 0.018 127.179 ;
        RECT  107.982 126.621 108 126.639 ;
        RECT  0 126.621 0.018 126.639 ;
        RECT  107.982 126.081 108 126.099 ;
        RECT  0 126.081 0.018 126.099 ;
        RECT  107.982 125.541 108 125.559 ;
        RECT  0 125.541 0.018 125.559 ;
        RECT  107.982 125.001 108 125.019 ;
        RECT  0 125.001 0.018 125.019 ;
        RECT  107.982 124.461 108 124.479 ;
        RECT  0 124.461 0.018 124.479 ;
        RECT  107.982 123.921 108 123.939 ;
        RECT  0 123.921 0.018 123.939 ;
        RECT  107.982 123.381 108 123.399 ;
        RECT  0 123.381 0.018 123.399 ;
        RECT  107.982 122.841 108 122.859 ;
        RECT  0 122.841 0.018 122.859 ;
        RECT  107.982 122.301 108 122.319 ;
        RECT  0 122.301 0.018 122.319 ;
        RECT  107.982 121.761 108 121.779 ;
        RECT  0 121.761 0.018 121.779 ;
        RECT  107.982 121.221 108 121.239 ;
        RECT  0 121.221 0.018 121.239 ;
        RECT  107.982 120.681 108 120.699 ;
        RECT  0 120.681 0.018 120.699 ;
        RECT  107.982 120.141 108 120.159 ;
        RECT  0 120.141 0.018 120.159 ;
        RECT  107.982 119.601 108 119.619 ;
        RECT  0 119.601 0.018 119.619 ;
        RECT  107.982 119.061 108 119.079 ;
        RECT  0 119.061 0.018 119.079 ;
        RECT  107.982 118.521 108 118.539 ;
        RECT  0 118.521 0.018 118.539 ;
        RECT  107.982 117.981 108 117.999 ;
        RECT  0 117.981 0.018 117.999 ;
        RECT  107.982 117.441 108 117.459 ;
        RECT  0 117.441 0.018 117.459 ;
        RECT  107.982 116.901 108 116.919 ;
        RECT  0 116.901 0.018 116.919 ;
        RECT  107.982 116.361 108 116.379 ;
        RECT  0 116.361 0.018 116.379 ;
        RECT  107.982 115.821 108 115.839 ;
        RECT  0 115.821 0.018 115.839 ;
        RECT  107.982 115.281 108 115.299 ;
        RECT  0 115.281 0.018 115.299 ;
        RECT  107.982 114.741 108 114.759 ;
        RECT  0 114.741 0.018 114.759 ;
        RECT  107.982 114.201 108 114.219 ;
        RECT  0 114.201 0.018 114.219 ;
        RECT  107.982 113.661 108 113.679 ;
        RECT  0 113.661 0.018 113.679 ;
        RECT  107.982 113.121 108 113.139 ;
        RECT  0 113.121 0.018 113.139 ;
        RECT  107.982 112.581 108 112.599 ;
        RECT  0 112.581 0.018 112.599 ;
        RECT  107.982 112.041 108 112.059 ;
        RECT  0 112.041 0.018 112.059 ;
        RECT  107.982 111.501 108 111.519 ;
        RECT  0 111.501 0.018 111.519 ;
        RECT  107.982 110.961 108 110.979 ;
        RECT  0 110.961 0.018 110.979 ;
        RECT  107.982 110.421 108 110.439 ;
        RECT  0 110.421 0.018 110.439 ;
        RECT  107.982 109.881 108 109.899 ;
        RECT  0 109.881 0.018 109.899 ;
        RECT  107.982 109.341 108 109.359 ;
        RECT  0 109.341 0.018 109.359 ;
        RECT  107.982 108.801 108 108.819 ;
        RECT  0 108.801 0.018 108.819 ;
        RECT  107.982 108.261 108 108.279 ;
        RECT  0 108.261 0.018 108.279 ;
        RECT  107.982 107.721 108 107.739 ;
        RECT  0 107.721 0.018 107.739 ;
        RECT  107.982 107.181 108 107.199 ;
        RECT  0 107.181 0.018 107.199 ;
        RECT  107.982 106.641 108 106.659 ;
        RECT  0 106.641 0.018 106.659 ;
        RECT  107.982 106.101 108 106.119 ;
        RECT  0 106.101 0.018 106.119 ;
        RECT  107.982 105.561 108 105.579 ;
        RECT  0 105.561 0.018 105.579 ;
        RECT  107.982 105.021 108 105.039 ;
        RECT  0 105.021 0.018 105.039 ;
        RECT  107.982 104.481 108 104.499 ;
        RECT  0 104.481 0.018 104.499 ;
        RECT  107.982 103.941 108 103.959 ;
        RECT  0 103.941 0.018 103.959 ;
        RECT  107.982 103.401 108 103.419 ;
        RECT  0 103.401 0.018 103.419 ;
        RECT  107.982 102.861 108 102.879 ;
        RECT  0 102.861 0.018 102.879 ;
        RECT  107.982 102.321 108 102.339 ;
        RECT  0 102.321 0.018 102.339 ;
        RECT  107.982 101.781 108 101.799 ;
        RECT  0 101.781 0.018 101.799 ;
        RECT  107.982 101.241 108 101.259 ;
        RECT  0 101.241 0.018 101.259 ;
        RECT  107.982 100.701 108 100.719 ;
        RECT  0 100.701 0.018 100.719 ;
        RECT  107.982 100.161 108 100.179 ;
        RECT  0 100.161 0.018 100.179 ;
        RECT  107.982 99.621 108 99.639 ;
        RECT  0 99.621 0.018 99.639 ;
        RECT  107.982 99.081 108 99.099 ;
        RECT  0 99.081 0.018 99.099 ;
        RECT  107.982 98.541 108 98.559 ;
        RECT  0 98.541 0.018 98.559 ;
        RECT  107.982 98.001 108 98.019 ;
        RECT  0 98.001 0.018 98.019 ;
        RECT  107.982 97.461 108 97.479 ;
        RECT  0 97.461 0.018 97.479 ;
        RECT  107.982 96.921 108 96.939 ;
        RECT  0 96.921 0.018 96.939 ;
        RECT  107.982 96.381 108 96.399 ;
        RECT  0 96.381 0.018 96.399 ;
        RECT  107.982 95.841 108 95.859 ;
        RECT  0 95.841 0.018 95.859 ;
        RECT  107.982 95.301 108 95.319 ;
        RECT  0 95.301 0.018 95.319 ;
        RECT  107.982 94.761 108 94.779 ;
        RECT  0 94.761 0.018 94.779 ;
        RECT  107.982 94.221 108 94.239 ;
        RECT  0 94.221 0.018 94.239 ;
        RECT  107.982 93.681 108 93.699 ;
        RECT  0 93.681 0.018 93.699 ;
        RECT  107.982 93.141 108 93.159 ;
        RECT  0 93.141 0.018 93.159 ;
        RECT  107.982 92.601 108 92.619 ;
        RECT  0 92.601 0.018 92.619 ;
        RECT  107.982 92.061 108 92.079 ;
        RECT  0 92.061 0.018 92.079 ;
        RECT  107.982 91.521 108 91.539 ;
        RECT  0 91.521 0.018 91.539 ;
        RECT  107.982 90.981 108 90.999 ;
        RECT  0 90.981 0.018 90.999 ;
        RECT  107.982 90.441 108 90.459 ;
        RECT  0 90.441 0.018 90.459 ;
        RECT  107.982 89.901 108 89.919 ;
        RECT  0 89.901 0.018 89.919 ;
        RECT  107.982 89.361 108 89.379 ;
        RECT  0 89.361 0.018 89.379 ;
        RECT  107.982 88.821 108 88.839 ;
        RECT  0 88.821 0.018 88.839 ;
        RECT  107.982 88.281 108 88.299 ;
        RECT  0 88.281 0.018 88.299 ;
        RECT  107.982 87.741 108 87.759 ;
        RECT  0 87.741 0.018 87.759 ;
        RECT  107.982 87.201 108 87.219 ;
        RECT  0 87.201 0.018 87.219 ;
        RECT  107.982 86.661 108 86.679 ;
        RECT  0 86.661 0.018 86.679 ;
        RECT  107.982 86.121 108 86.139 ;
        RECT  0 86.121 0.018 86.139 ;
        RECT  107.982 85.581 108 85.599 ;
        RECT  0 85.581 0.018 85.599 ;
        RECT  107.982 85.041 108 85.059 ;
        RECT  0 85.041 0.018 85.059 ;
        RECT  107.982 84.501 108 84.519 ;
        RECT  0 84.501 0.018 84.519 ;
        RECT  107.982 83.961 108 83.979 ;
        RECT  0 83.961 0.018 83.979 ;
        RECT  107.982 83.421 108 83.439 ;
        RECT  0 83.421 0.018 83.439 ;
        RECT  107.982 82.881 108 82.899 ;
        RECT  0 82.881 0.018 82.899 ;
        RECT  107.982 82.341 108 82.359 ;
        RECT  0 82.341 0.018 82.359 ;
        RECT  107.982 81.801 108 81.819 ;
        RECT  0 81.801 0.018 81.819 ;
        RECT  107.982 81.261 108 81.279 ;
        RECT  0 81.261 0.018 81.279 ;
        RECT  107.982 80.721 108 80.739 ;
        RECT  0 80.721 0.018 80.739 ;
        RECT  107.982 80.181 108 80.199 ;
        RECT  0 80.181 0.018 80.199 ;
        RECT  107.982 79.641 108 79.659 ;
        RECT  0 79.641 0.018 79.659 ;
        RECT  107.982 79.101 108 79.119 ;
        RECT  0 79.101 0.018 79.119 ;
        RECT  107.982 78.561 108 78.579 ;
        RECT  0 78.561 0.018 78.579 ;
        RECT  107.982 78.021 108 78.039 ;
        RECT  0 78.021 0.018 78.039 ;
        RECT  107.982 77.481 108 77.499 ;
        RECT  0 77.481 0.018 77.499 ;
        RECT  107.982 76.941 108 76.959 ;
        RECT  0 76.941 0.018 76.959 ;
        RECT  107.982 76.401 108 76.419 ;
        RECT  0 76.401 0.018 76.419 ;
        RECT  107.982 75.861 108 75.879 ;
        RECT  0 75.861 0.018 75.879 ;
        RECT  107.982 75.321 108 75.339 ;
        RECT  0 75.321 0.018 75.339 ;
        RECT  107.982 74.781 108 74.799 ;
        RECT  0 74.781 0.018 74.799 ;
        RECT  107.982 74.241 108 74.259 ;
        RECT  0 74.241 0.018 74.259 ;
        RECT  107.982 73.701 108 73.719 ;
        RECT  0 73.701 0.018 73.719 ;
        RECT  107.982 73.161 108 73.179 ;
        RECT  0 73.161 0.018 73.179 ;
        RECT  107.982 72.621 108 72.639 ;
        RECT  0 72.621 0.018 72.639 ;
        RECT  107.982 72.081 108 72.099 ;
        RECT  0 72.081 0.018 72.099 ;
        RECT  107.982 71.541 108 71.559 ;
        RECT  0 71.541 0.018 71.559 ;
        RECT  107.982 71.001 108 71.019 ;
        RECT  0 71.001 0.018 71.019 ;
        RECT  107.982 70.461 108 70.479 ;
        RECT  0 70.461 0.018 70.479 ;
        RECT  107.982 69.921 108 69.939 ;
        RECT  0 69.921 0.018 69.939 ;
        RECT  107.982 69.381 108 69.399 ;
        RECT  0 69.381 0.018 69.399 ;
        RECT  107.982 68.841 108 68.859 ;
        RECT  0 68.841 0.018 68.859 ;
        RECT  107.982 68.301 108 68.319 ;
        RECT  0 68.301 0.018 68.319 ;
        RECT  107.982 67.761 108 67.779 ;
        RECT  0 67.761 0.018 67.779 ;
        RECT  107.982 67.221 108 67.239 ;
        RECT  0 67.221 0.018 67.239 ;
        RECT  107.982 66.681 108 66.699 ;
        RECT  0 66.681 0.018 66.699 ;
        RECT  107.982 66.141 108 66.159 ;
        RECT  0 66.141 0.018 66.159 ;
        RECT  107.982 65.601 108 65.619 ;
        RECT  0 65.601 0.018 65.619 ;
        RECT  107.982 65.061 108 65.079 ;
        RECT  0 65.061 0.018 65.079 ;
        RECT  107.982 64.521 108 64.539 ;
        RECT  0 64.521 0.018 64.539 ;
        RECT  107.982 63.981 108 63.999 ;
        RECT  0 63.981 0.018 63.999 ;
        RECT  107.982 63.441 108 63.459 ;
        RECT  0 63.441 0.018 63.459 ;
        RECT  107.982 62.901 108 62.919 ;
        RECT  0 62.901 0.018 62.919 ;
        RECT  107.982 62.361 108 62.379 ;
        RECT  0 62.361 0.018 62.379 ;
        RECT  107.982 61.821 108 61.839 ;
        RECT  0 61.821 0.018 61.839 ;
        RECT  107.982 61.281 108 61.299 ;
        RECT  0 61.281 0.018 61.299 ;
        RECT  107.982 60.741 108 60.759 ;
        RECT  0 60.741 0.018 60.759 ;
        RECT  107.982 60.201 108 60.219 ;
        RECT  0 60.201 0.018 60.219 ;
        RECT  107.982 59.661 108 59.679 ;
        RECT  0 59.661 0.018 59.679 ;
        RECT  107.982 59.121 108 59.139 ;
        RECT  0 59.121 0.018 59.139 ;
        RECT  107.982 58.581 108 58.599 ;
        RECT  0 58.581 0.018 58.599 ;
        RECT  107.982 58.041 108 58.059 ;
        RECT  0 58.041 0.018 58.059 ;
        RECT  107.982 57.501 108 57.519 ;
        RECT  0 57.501 0.018 57.519 ;
        RECT  107.982 56.961 108 56.979 ;
        RECT  0 56.961 0.018 56.979 ;
        RECT  107.982 56.421 108 56.439 ;
        RECT  0 56.421 0.018 56.439 ;
        RECT  107.982 55.881 108 55.899 ;
        RECT  0 55.881 0.018 55.899 ;
        RECT  107.982 55.341 108 55.359 ;
        RECT  0 55.341 0.018 55.359 ;
        RECT  107.982 54.801 108 54.819 ;
        RECT  0 54.801 0.018 54.819 ;
        RECT  107.982 54.261 108 54.279 ;
        RECT  0 54.261 0.018 54.279 ;
        RECT  107.982 53.721 108 53.739 ;
        RECT  0 53.721 0.018 53.739 ;
        RECT  107.982 53.181 108 53.199 ;
        RECT  0 53.181 0.018 53.199 ;
        RECT  107.982 52.641 108 52.659 ;
        RECT  0 52.641 0.018 52.659 ;
        RECT  107.982 52.101 108 52.119 ;
        RECT  0 52.101 0.018 52.119 ;
        RECT  107.982 51.561 108 51.579 ;
        RECT  0 51.561 0.018 51.579 ;
        RECT  107.982 51.021 108 51.039 ;
        RECT  0 51.021 0.018 51.039 ;
        RECT  107.982 50.481 108 50.499 ;
        RECT  0 50.481 0.018 50.499 ;
        RECT  107.982 49.941 108 49.959 ;
        RECT  0 49.941 0.018 49.959 ;
        RECT  107.982 49.401 108 49.419 ;
        RECT  0 49.401 0.018 49.419 ;
        RECT  107.982 48.861 108 48.879 ;
        RECT  0 48.861 0.018 48.879 ;
        RECT  107.982 48.321 108 48.339 ;
        RECT  0 48.321 0.018 48.339 ;
        RECT  107.982 47.781 108 47.799 ;
        RECT  0 47.781 0.018 47.799 ;
        RECT  107.982 47.241 108 47.259 ;
        RECT  0 47.241 0.018 47.259 ;
        RECT  107.982 46.701 108 46.719 ;
        RECT  0 46.701 0.018 46.719 ;
        RECT  107.982 46.161 108 46.179 ;
        RECT  0 46.161 0.018 46.179 ;
        RECT  107.982 45.621 108 45.639 ;
        RECT  0 45.621 0.018 45.639 ;
        RECT  107.982 45.081 108 45.099 ;
        RECT  0 45.081 0.018 45.099 ;
        RECT  107.982 44.541 108 44.559 ;
        RECT  0 44.541 0.018 44.559 ;
        RECT  107.982 44.001 108 44.019 ;
        RECT  0 44.001 0.018 44.019 ;
        RECT  107.982 43.461 108 43.479 ;
        RECT  0 43.461 0.018 43.479 ;
        RECT  107.982 42.921 108 42.939 ;
        RECT  0 42.921 0.018 42.939 ;
        RECT  107.982 42.381 108 42.399 ;
        RECT  0 42.381 0.018 42.399 ;
        RECT  107.982 41.841 108 41.859 ;
        RECT  0 41.841 0.018 41.859 ;
        RECT  107.982 41.301 108 41.319 ;
        RECT  0 41.301 0.018 41.319 ;
        RECT  107.982 40.761 108 40.779 ;
        RECT  0 40.761 0.018 40.779 ;
        RECT  107.982 40.221 108 40.239 ;
        RECT  0 40.221 0.018 40.239 ;
        RECT  107.982 39.681 108 39.699 ;
        RECT  0 39.681 0.018 39.699 ;
        RECT  107.982 39.141 108 39.159 ;
        RECT  0 39.141 0.018 39.159 ;
        RECT  107.982 38.601 108 38.619 ;
        RECT  0 38.601 0.018 38.619 ;
        RECT  107.982 38.061 108 38.079 ;
        RECT  0 38.061 0.018 38.079 ;
        RECT  107.982 37.521 108 37.539 ;
        RECT  0 37.521 0.018 37.539 ;
        RECT  107.982 36.981 108 36.999 ;
        RECT  0 36.981 0.018 36.999 ;
        RECT  107.982 36.441 108 36.459 ;
        RECT  0 36.441 0.018 36.459 ;
        RECT  107.982 35.901 108 35.919 ;
        RECT  0 35.901 0.018 35.919 ;
        RECT  107.982 35.361 108 35.379 ;
        RECT  0 35.361 0.018 35.379 ;
        RECT  107.982 34.821 108 34.839 ;
        RECT  0 34.821 0.018 34.839 ;
        RECT  107.982 34.281 108 34.299 ;
        RECT  0 34.281 0.018 34.299 ;
        RECT  107.982 33.741 108 33.759 ;
        RECT  0 33.741 0.018 33.759 ;
        RECT  107.982 33.201 108 33.219 ;
        RECT  0 33.201 0.018 33.219 ;
        RECT  107.982 32.661 108 32.679 ;
        RECT  0 32.661 0.018 32.679 ;
        RECT  107.982 32.121 108 32.139 ;
        RECT  0 32.121 0.018 32.139 ;
        RECT  107.982 31.581 108 31.599 ;
        RECT  0 31.581 0.018 31.599 ;
        RECT  107.982 31.041 108 31.059 ;
        RECT  0 31.041 0.018 31.059 ;
        RECT  107.982 30.501 108 30.519 ;
        RECT  0 30.501 0.018 30.519 ;
        RECT  107.982 29.961 108 29.979 ;
        RECT  0 29.961 0.018 29.979 ;
        RECT  107.982 29.421 108 29.439 ;
        RECT  0 29.421 0.018 29.439 ;
        RECT  107.982 28.881 108 28.899 ;
        RECT  0 28.881 0.018 28.899 ;
        RECT  107.982 28.341 108 28.359 ;
        RECT  0 28.341 0.018 28.359 ;
        RECT  107.982 27.801 108 27.819 ;
        RECT  0 27.801 0.018 27.819 ;
        RECT  107.982 27.261 108 27.279 ;
        RECT  0 27.261 0.018 27.279 ;
        RECT  107.982 26.721 108 26.739 ;
        RECT  0 26.721 0.018 26.739 ;
        RECT  107.982 26.181 108 26.199 ;
        RECT  0 26.181 0.018 26.199 ;
        RECT  107.982 25.641 108 25.659 ;
        RECT  0 25.641 0.018 25.659 ;
        RECT  107.982 25.101 108 25.119 ;
        RECT  0 25.101 0.018 25.119 ;
        RECT  107.982 24.561 108 24.579 ;
        RECT  0 24.561 0.018 24.579 ;
        RECT  107.982 24.021 108 24.039 ;
        RECT  0 24.021 0.018 24.039 ;
        RECT  107.982 23.481 108 23.499 ;
        RECT  0 23.481 0.018 23.499 ;
        RECT  107.982 22.941 108 22.959 ;
        RECT  0 22.941 0.018 22.959 ;
        RECT  107.982 22.401 108 22.419 ;
        RECT  0 22.401 0.018 22.419 ;
        RECT  107.982 21.861 108 21.879 ;
        RECT  0 21.861 0.018 21.879 ;
        RECT  107.982 21.321 108 21.339 ;
        RECT  0 21.321 0.018 21.339 ;
        RECT  107.982 20.781 108 20.799 ;
        RECT  0 20.781 0.018 20.799 ;
        RECT  107.982 20.241 108 20.259 ;
        RECT  0 20.241 0.018 20.259 ;
        RECT  107.982 19.701 108 19.719 ;
        RECT  0 19.701 0.018 19.719 ;
        RECT  107.982 19.161 108 19.179 ;
        RECT  0 19.161 0.018 19.179 ;
        RECT  107.982 18.621 108 18.639 ;
        RECT  0 18.621 0.018 18.639 ;
        RECT  107.982 18.081 108 18.099 ;
        RECT  0 18.081 0.018 18.099 ;
        RECT  107.982 17.541 108 17.559 ;
        RECT  0 17.541 0.018 17.559 ;
        RECT  107.982 17.001 108 17.019 ;
        RECT  0 17.001 0.018 17.019 ;
        RECT  107.982 16.461 108 16.479 ;
        RECT  0 16.461 0.018 16.479 ;
        RECT  107.982 15.921 108 15.939 ;
        RECT  0 15.921 0.018 15.939 ;
        RECT  107.982 15.381 108 15.399 ;
        RECT  0 15.381 0.018 15.399 ;
        RECT  107.982 14.841 108 14.859 ;
        RECT  0 14.841 0.018 14.859 ;
        RECT  107.982 14.301 108 14.319 ;
        RECT  0 14.301 0.018 14.319 ;
        RECT  107.982 13.761 108 13.779 ;
        RECT  0 13.761 0.018 13.779 ;
        RECT  107.982 13.221 108 13.239 ;
        RECT  0 13.221 0.018 13.239 ;
        RECT  107.982 12.681 108 12.699 ;
        RECT  0 12.681 0.018 12.699 ;
        RECT  107.982 12.141 108 12.159 ;
        RECT  0 12.141 0.018 12.159 ;
        RECT  107.982 11.601 108 11.619 ;
        RECT  0 11.601 0.018 11.619 ;
        RECT  107.982 11.061 108 11.079 ;
        RECT  0 11.061 0.018 11.079 ;
        RECT  107.982 10.521 108 10.539 ;
        RECT  0 10.521 0.018 10.539 ;
        RECT  107.982 9.981 108 9.999 ;
        RECT  0 9.981 0.018 9.999 ;
        RECT  107.982 9.441 108 9.459 ;
        RECT  0 9.441 0.018 9.459 ;
        RECT  107.982 8.901 108 8.919 ;
        RECT  0 8.901 0.018 8.919 ;
        RECT  107.982 8.361 108 8.379 ;
        RECT  0 8.361 0.018 8.379 ;
        RECT  107.982 7.821 108 7.839 ;
        RECT  0 7.821 0.018 7.839 ;
        RECT  107.982 7.281 108 7.299 ;
        RECT  0 7.281 0.018 7.299 ;
        RECT  107.982 6.741 108 6.759 ;
        RECT  0 6.741 0.018 6.759 ;
        RECT  107.982 6.201 108 6.219 ;
        RECT  0 6.201 0.018 6.219 ;
        RECT  107.982 5.661 108 5.679 ;
        RECT  0 5.661 0.018 5.679 ;
        RECT  107.982 5.121 108 5.139 ;
        RECT  0 5.121 0.018 5.139 ;
        RECT  107.982 4.581 108 4.599 ;
        RECT  0 4.581 0.018 4.599 ;
        RECT  107.982 4.041 108 4.059 ;
        RECT  0 4.041 0.018 4.059 ;
        RECT  107.982 3.501 108 3.519 ;
        RECT  0 3.501 0.018 3.519 ;
        RECT  107.982 2.961 108 2.979 ;
        RECT  0 2.961 0.018 2.979 ;
        RECT  107.982 2.421 108 2.439 ;
        RECT  0 2.421 0.018 2.439 ;
        RECT  107.982 1.881 108 1.899 ;
        RECT  0 1.881 0.018 1.899 ;
        RECT  107.982 1.341 108 1.359 ;
        RECT  0 1.341 0.018 1.359 ;
        RECT  107.982 0.801 108 0.819 ;
        RECT  0 0.801 0.018 0.819 ;
      LAYER M1 ;
        RECT  107.982 128.781 108 128.799 ;
        RECT  0 128.781 0.018 128.799 ;
        RECT  107.982 128.241 108 128.259 ;
        RECT  0 128.241 0.018 128.259 ;
        RECT  107.982 127.701 108 127.719 ;
        RECT  0 127.701 0.018 127.719 ;
        RECT  107.982 127.161 108 127.179 ;
        RECT  0 127.161 0.018 127.179 ;
        RECT  107.982 126.621 108 126.639 ;
        RECT  0 126.621 0.018 126.639 ;
        RECT  107.982 126.081 108 126.099 ;
        RECT  0 126.081 0.018 126.099 ;
        RECT  107.982 125.541 108 125.559 ;
        RECT  0 125.541 0.018 125.559 ;
        RECT  107.982 125.001 108 125.019 ;
        RECT  0 125.001 0.018 125.019 ;
        RECT  107.982 124.461 108 124.479 ;
        RECT  0 124.461 0.018 124.479 ;
        RECT  107.982 123.921 108 123.939 ;
        RECT  0 123.921 0.018 123.939 ;
        RECT  107.982 123.381 108 123.399 ;
        RECT  0 123.381 0.018 123.399 ;
        RECT  107.982 122.841 108 122.859 ;
        RECT  0 122.841 0.018 122.859 ;
        RECT  107.982 122.301 108 122.319 ;
        RECT  0 122.301 0.018 122.319 ;
        RECT  107.982 121.761 108 121.779 ;
        RECT  0 121.761 0.018 121.779 ;
        RECT  107.982 121.221 108 121.239 ;
        RECT  0 121.221 0.018 121.239 ;
        RECT  107.982 120.681 108 120.699 ;
        RECT  0 120.681 0.018 120.699 ;
        RECT  107.982 120.141 108 120.159 ;
        RECT  0 120.141 0.018 120.159 ;
        RECT  107.982 119.601 108 119.619 ;
        RECT  0 119.601 0.018 119.619 ;
        RECT  107.982 119.061 108 119.079 ;
        RECT  0 119.061 0.018 119.079 ;
        RECT  107.982 118.521 108 118.539 ;
        RECT  0 118.521 0.018 118.539 ;
        RECT  107.982 117.981 108 117.999 ;
        RECT  0 117.981 0.018 117.999 ;
        RECT  107.982 117.441 108 117.459 ;
        RECT  0 117.441 0.018 117.459 ;
        RECT  107.982 116.901 108 116.919 ;
        RECT  0 116.901 0.018 116.919 ;
        RECT  107.982 116.361 108 116.379 ;
        RECT  0 116.361 0.018 116.379 ;
        RECT  107.982 115.821 108 115.839 ;
        RECT  0 115.821 0.018 115.839 ;
        RECT  107.982 115.281 108 115.299 ;
        RECT  0 115.281 0.018 115.299 ;
        RECT  107.982 114.741 108 114.759 ;
        RECT  0 114.741 0.018 114.759 ;
        RECT  107.982 114.201 108 114.219 ;
        RECT  0 114.201 0.018 114.219 ;
        RECT  107.982 113.661 108 113.679 ;
        RECT  0 113.661 0.018 113.679 ;
        RECT  107.982 113.121 108 113.139 ;
        RECT  0 113.121 0.018 113.139 ;
        RECT  107.982 112.581 108 112.599 ;
        RECT  0 112.581 0.018 112.599 ;
        RECT  107.982 112.041 108 112.059 ;
        RECT  0 112.041 0.018 112.059 ;
        RECT  107.982 111.501 108 111.519 ;
        RECT  0 111.501 0.018 111.519 ;
        RECT  107.982 110.961 108 110.979 ;
        RECT  0 110.961 0.018 110.979 ;
        RECT  107.982 110.421 108 110.439 ;
        RECT  0 110.421 0.018 110.439 ;
        RECT  107.982 109.881 108 109.899 ;
        RECT  0 109.881 0.018 109.899 ;
        RECT  107.982 109.341 108 109.359 ;
        RECT  0 109.341 0.018 109.359 ;
        RECT  107.982 108.801 108 108.819 ;
        RECT  0 108.801 0.018 108.819 ;
        RECT  107.982 108.261 108 108.279 ;
        RECT  0 108.261 0.018 108.279 ;
        RECT  107.982 107.721 108 107.739 ;
        RECT  0 107.721 0.018 107.739 ;
        RECT  107.982 107.181 108 107.199 ;
        RECT  0 107.181 0.018 107.199 ;
        RECT  107.982 106.641 108 106.659 ;
        RECT  0 106.641 0.018 106.659 ;
        RECT  107.982 106.101 108 106.119 ;
        RECT  0 106.101 0.018 106.119 ;
        RECT  107.982 105.561 108 105.579 ;
        RECT  0 105.561 0.018 105.579 ;
        RECT  107.982 105.021 108 105.039 ;
        RECT  0 105.021 0.018 105.039 ;
        RECT  107.982 104.481 108 104.499 ;
        RECT  0 104.481 0.018 104.499 ;
        RECT  107.982 103.941 108 103.959 ;
        RECT  0 103.941 0.018 103.959 ;
        RECT  107.982 103.401 108 103.419 ;
        RECT  0 103.401 0.018 103.419 ;
        RECT  107.982 102.861 108 102.879 ;
        RECT  0 102.861 0.018 102.879 ;
        RECT  107.982 102.321 108 102.339 ;
        RECT  0 102.321 0.018 102.339 ;
        RECT  107.982 101.781 108 101.799 ;
        RECT  0 101.781 0.018 101.799 ;
        RECT  107.982 101.241 108 101.259 ;
        RECT  0 101.241 0.018 101.259 ;
        RECT  107.982 100.701 108 100.719 ;
        RECT  0 100.701 0.018 100.719 ;
        RECT  107.982 100.161 108 100.179 ;
        RECT  0 100.161 0.018 100.179 ;
        RECT  107.982 99.621 108 99.639 ;
        RECT  0 99.621 0.018 99.639 ;
        RECT  107.982 99.081 108 99.099 ;
        RECT  0 99.081 0.018 99.099 ;
        RECT  107.982 98.541 108 98.559 ;
        RECT  0 98.541 0.018 98.559 ;
        RECT  107.982 98.001 108 98.019 ;
        RECT  0 98.001 0.018 98.019 ;
        RECT  107.982 97.461 108 97.479 ;
        RECT  0 97.461 0.018 97.479 ;
        RECT  107.982 96.921 108 96.939 ;
        RECT  0 96.921 0.018 96.939 ;
        RECT  107.982 96.381 108 96.399 ;
        RECT  0 96.381 0.018 96.399 ;
        RECT  107.982 95.841 108 95.859 ;
        RECT  0 95.841 0.018 95.859 ;
        RECT  107.982 95.301 108 95.319 ;
        RECT  0 95.301 0.018 95.319 ;
        RECT  107.982 94.761 108 94.779 ;
        RECT  0 94.761 0.018 94.779 ;
        RECT  107.982 94.221 108 94.239 ;
        RECT  0 94.221 0.018 94.239 ;
        RECT  107.982 93.681 108 93.699 ;
        RECT  0 93.681 0.018 93.699 ;
        RECT  107.982 93.141 108 93.159 ;
        RECT  0 93.141 0.018 93.159 ;
        RECT  107.982 92.601 108 92.619 ;
        RECT  0 92.601 0.018 92.619 ;
        RECT  107.982 92.061 108 92.079 ;
        RECT  0 92.061 0.018 92.079 ;
        RECT  107.982 91.521 108 91.539 ;
        RECT  0 91.521 0.018 91.539 ;
        RECT  107.982 90.981 108 90.999 ;
        RECT  0 90.981 0.018 90.999 ;
        RECT  107.982 90.441 108 90.459 ;
        RECT  0 90.441 0.018 90.459 ;
        RECT  107.982 89.901 108 89.919 ;
        RECT  0 89.901 0.018 89.919 ;
        RECT  107.982 89.361 108 89.379 ;
        RECT  0 89.361 0.018 89.379 ;
        RECT  107.982 88.821 108 88.839 ;
        RECT  0 88.821 0.018 88.839 ;
        RECT  107.982 88.281 108 88.299 ;
        RECT  0 88.281 0.018 88.299 ;
        RECT  107.982 87.741 108 87.759 ;
        RECT  0 87.741 0.018 87.759 ;
        RECT  107.982 87.201 108 87.219 ;
        RECT  0 87.201 0.018 87.219 ;
        RECT  107.982 86.661 108 86.679 ;
        RECT  0 86.661 0.018 86.679 ;
        RECT  107.982 86.121 108 86.139 ;
        RECT  0 86.121 0.018 86.139 ;
        RECT  107.982 85.581 108 85.599 ;
        RECT  0 85.581 0.018 85.599 ;
        RECT  107.982 85.041 108 85.059 ;
        RECT  0 85.041 0.018 85.059 ;
        RECT  107.982 84.501 108 84.519 ;
        RECT  0 84.501 0.018 84.519 ;
        RECT  107.982 83.961 108 83.979 ;
        RECT  0 83.961 0.018 83.979 ;
        RECT  107.982 83.421 108 83.439 ;
        RECT  0 83.421 0.018 83.439 ;
        RECT  107.982 82.881 108 82.899 ;
        RECT  0 82.881 0.018 82.899 ;
        RECT  107.982 82.341 108 82.359 ;
        RECT  0 82.341 0.018 82.359 ;
        RECT  107.982 81.801 108 81.819 ;
        RECT  0 81.801 0.018 81.819 ;
        RECT  107.982 81.261 108 81.279 ;
        RECT  0 81.261 0.018 81.279 ;
        RECT  107.982 80.721 108 80.739 ;
        RECT  0 80.721 0.018 80.739 ;
        RECT  107.982 80.181 108 80.199 ;
        RECT  0 80.181 0.018 80.199 ;
        RECT  107.982 79.641 108 79.659 ;
        RECT  0 79.641 0.018 79.659 ;
        RECT  107.982 79.101 108 79.119 ;
        RECT  0 79.101 0.018 79.119 ;
        RECT  107.982 78.561 108 78.579 ;
        RECT  0 78.561 0.018 78.579 ;
        RECT  107.982 78.021 108 78.039 ;
        RECT  0 78.021 0.018 78.039 ;
        RECT  107.982 77.481 108 77.499 ;
        RECT  0 77.481 0.018 77.499 ;
        RECT  107.982 76.941 108 76.959 ;
        RECT  0 76.941 0.018 76.959 ;
        RECT  107.982 76.401 108 76.419 ;
        RECT  0 76.401 0.018 76.419 ;
        RECT  107.982 75.861 108 75.879 ;
        RECT  0 75.861 0.018 75.879 ;
        RECT  107.982 75.321 108 75.339 ;
        RECT  0 75.321 0.018 75.339 ;
        RECT  107.982 74.781 108 74.799 ;
        RECT  0 74.781 0.018 74.799 ;
        RECT  107.982 74.241 108 74.259 ;
        RECT  0 74.241 0.018 74.259 ;
        RECT  107.982 73.701 108 73.719 ;
        RECT  0 73.701 0.018 73.719 ;
        RECT  107.982 73.161 108 73.179 ;
        RECT  0 73.161 0.018 73.179 ;
        RECT  107.982 72.621 108 72.639 ;
        RECT  0 72.621 0.018 72.639 ;
        RECT  107.982 72.081 108 72.099 ;
        RECT  0 72.081 0.018 72.099 ;
        RECT  107.982 71.541 108 71.559 ;
        RECT  0 71.541 0.018 71.559 ;
        RECT  107.982 71.001 108 71.019 ;
        RECT  0 71.001 0.018 71.019 ;
        RECT  107.982 70.461 108 70.479 ;
        RECT  0 70.461 0.018 70.479 ;
        RECT  107.982 69.921 108 69.939 ;
        RECT  0 69.921 0.018 69.939 ;
        RECT  107.982 69.381 108 69.399 ;
        RECT  0 69.381 0.018 69.399 ;
        RECT  107.982 68.841 108 68.859 ;
        RECT  0 68.841 0.018 68.859 ;
        RECT  107.982 68.301 108 68.319 ;
        RECT  0 68.301 0.018 68.319 ;
        RECT  107.982 67.761 108 67.779 ;
        RECT  0 67.761 0.018 67.779 ;
        RECT  107.982 67.221 108 67.239 ;
        RECT  0 67.221 0.018 67.239 ;
        RECT  107.982 66.681 108 66.699 ;
        RECT  0 66.681 0.018 66.699 ;
        RECT  107.982 66.141 108 66.159 ;
        RECT  0 66.141 0.018 66.159 ;
        RECT  107.982 65.601 108 65.619 ;
        RECT  0 65.601 0.018 65.619 ;
        RECT  107.982 65.061 108 65.079 ;
        RECT  0 65.061 0.018 65.079 ;
        RECT  107.982 64.521 108 64.539 ;
        RECT  0 64.521 0.018 64.539 ;
        RECT  107.982 63.981 108 63.999 ;
        RECT  0 63.981 0.018 63.999 ;
        RECT  107.982 63.441 108 63.459 ;
        RECT  0 63.441 0.018 63.459 ;
        RECT  107.982 62.901 108 62.919 ;
        RECT  0 62.901 0.018 62.919 ;
        RECT  107.982 62.361 108 62.379 ;
        RECT  0 62.361 0.018 62.379 ;
        RECT  107.982 61.821 108 61.839 ;
        RECT  0 61.821 0.018 61.839 ;
        RECT  107.982 61.281 108 61.299 ;
        RECT  0 61.281 0.018 61.299 ;
        RECT  107.982 60.741 108 60.759 ;
        RECT  0 60.741 0.018 60.759 ;
        RECT  107.982 60.201 108 60.219 ;
        RECT  0 60.201 0.018 60.219 ;
        RECT  107.982 59.661 108 59.679 ;
        RECT  0 59.661 0.018 59.679 ;
        RECT  107.982 59.121 108 59.139 ;
        RECT  0 59.121 0.018 59.139 ;
        RECT  107.982 58.581 108 58.599 ;
        RECT  0 58.581 0.018 58.599 ;
        RECT  107.982 58.041 108 58.059 ;
        RECT  0 58.041 0.018 58.059 ;
        RECT  107.982 57.501 108 57.519 ;
        RECT  0 57.501 0.018 57.519 ;
        RECT  107.982 56.961 108 56.979 ;
        RECT  0 56.961 0.018 56.979 ;
        RECT  107.982 56.421 108 56.439 ;
        RECT  0 56.421 0.018 56.439 ;
        RECT  107.982 55.881 108 55.899 ;
        RECT  0 55.881 0.018 55.899 ;
        RECT  107.982 55.341 108 55.359 ;
        RECT  0 55.341 0.018 55.359 ;
        RECT  107.982 54.801 108 54.819 ;
        RECT  0 54.801 0.018 54.819 ;
        RECT  107.982 54.261 108 54.279 ;
        RECT  0 54.261 0.018 54.279 ;
        RECT  107.982 53.721 108 53.739 ;
        RECT  0 53.721 0.018 53.739 ;
        RECT  107.982 53.181 108 53.199 ;
        RECT  0 53.181 0.018 53.199 ;
        RECT  107.982 52.641 108 52.659 ;
        RECT  0 52.641 0.018 52.659 ;
        RECT  107.982 52.101 108 52.119 ;
        RECT  0 52.101 0.018 52.119 ;
        RECT  107.982 51.561 108 51.579 ;
        RECT  0 51.561 0.018 51.579 ;
        RECT  107.982 51.021 108 51.039 ;
        RECT  0 51.021 0.018 51.039 ;
        RECT  107.982 50.481 108 50.499 ;
        RECT  0 50.481 0.018 50.499 ;
        RECT  107.982 49.941 108 49.959 ;
        RECT  0 49.941 0.018 49.959 ;
        RECT  107.982 49.401 108 49.419 ;
        RECT  0 49.401 0.018 49.419 ;
        RECT  107.982 48.861 108 48.879 ;
        RECT  0 48.861 0.018 48.879 ;
        RECT  107.982 48.321 108 48.339 ;
        RECT  0 48.321 0.018 48.339 ;
        RECT  107.982 47.781 108 47.799 ;
        RECT  0 47.781 0.018 47.799 ;
        RECT  107.982 47.241 108 47.259 ;
        RECT  0 47.241 0.018 47.259 ;
        RECT  107.982 46.701 108 46.719 ;
        RECT  0 46.701 0.018 46.719 ;
        RECT  107.982 46.161 108 46.179 ;
        RECT  0 46.161 0.018 46.179 ;
        RECT  107.982 45.621 108 45.639 ;
        RECT  0 45.621 0.018 45.639 ;
        RECT  107.982 45.081 108 45.099 ;
        RECT  0 45.081 0.018 45.099 ;
        RECT  107.982 44.541 108 44.559 ;
        RECT  0 44.541 0.018 44.559 ;
        RECT  107.982 44.001 108 44.019 ;
        RECT  0 44.001 0.018 44.019 ;
        RECT  107.982 43.461 108 43.479 ;
        RECT  0 43.461 0.018 43.479 ;
        RECT  107.982 42.921 108 42.939 ;
        RECT  0 42.921 0.018 42.939 ;
        RECT  107.982 42.381 108 42.399 ;
        RECT  0 42.381 0.018 42.399 ;
        RECT  107.982 41.841 108 41.859 ;
        RECT  0 41.841 0.018 41.859 ;
        RECT  107.982 41.301 108 41.319 ;
        RECT  0 41.301 0.018 41.319 ;
        RECT  107.982 40.761 108 40.779 ;
        RECT  0 40.761 0.018 40.779 ;
        RECT  107.982 40.221 108 40.239 ;
        RECT  0 40.221 0.018 40.239 ;
        RECT  107.982 39.681 108 39.699 ;
        RECT  0 39.681 0.018 39.699 ;
        RECT  107.982 39.141 108 39.159 ;
        RECT  0 39.141 0.018 39.159 ;
        RECT  107.982 38.601 108 38.619 ;
        RECT  0 38.601 0.018 38.619 ;
        RECT  107.982 38.061 108 38.079 ;
        RECT  0 38.061 0.018 38.079 ;
        RECT  107.982 37.521 108 37.539 ;
        RECT  0 37.521 0.018 37.539 ;
        RECT  107.982 36.981 108 36.999 ;
        RECT  0 36.981 0.018 36.999 ;
        RECT  107.982 36.441 108 36.459 ;
        RECT  0 36.441 0.018 36.459 ;
        RECT  107.982 35.901 108 35.919 ;
        RECT  0 35.901 0.018 35.919 ;
        RECT  107.982 35.361 108 35.379 ;
        RECT  0 35.361 0.018 35.379 ;
        RECT  107.982 34.821 108 34.839 ;
        RECT  0 34.821 0.018 34.839 ;
        RECT  107.982 34.281 108 34.299 ;
        RECT  0 34.281 0.018 34.299 ;
        RECT  107.982 33.741 108 33.759 ;
        RECT  0 33.741 0.018 33.759 ;
        RECT  107.982 33.201 108 33.219 ;
        RECT  0 33.201 0.018 33.219 ;
        RECT  107.982 32.661 108 32.679 ;
        RECT  0 32.661 0.018 32.679 ;
        RECT  107.982 32.121 108 32.139 ;
        RECT  0 32.121 0.018 32.139 ;
        RECT  107.982 31.581 108 31.599 ;
        RECT  0 31.581 0.018 31.599 ;
        RECT  107.982 31.041 108 31.059 ;
        RECT  0 31.041 0.018 31.059 ;
        RECT  107.982 30.501 108 30.519 ;
        RECT  0 30.501 0.018 30.519 ;
        RECT  107.982 29.961 108 29.979 ;
        RECT  0 29.961 0.018 29.979 ;
        RECT  107.982 29.421 108 29.439 ;
        RECT  0 29.421 0.018 29.439 ;
        RECT  107.982 28.881 108 28.899 ;
        RECT  0 28.881 0.018 28.899 ;
        RECT  107.982 28.341 108 28.359 ;
        RECT  0 28.341 0.018 28.359 ;
        RECT  107.982 27.801 108 27.819 ;
        RECT  0 27.801 0.018 27.819 ;
        RECT  107.982 27.261 108 27.279 ;
        RECT  0 27.261 0.018 27.279 ;
        RECT  107.982 26.721 108 26.739 ;
        RECT  0 26.721 0.018 26.739 ;
        RECT  107.982 26.181 108 26.199 ;
        RECT  0 26.181 0.018 26.199 ;
        RECT  107.982 25.641 108 25.659 ;
        RECT  0 25.641 0.018 25.659 ;
        RECT  107.982 25.101 108 25.119 ;
        RECT  0 25.101 0.018 25.119 ;
        RECT  107.982 24.561 108 24.579 ;
        RECT  0 24.561 0.018 24.579 ;
        RECT  107.982 24.021 108 24.039 ;
        RECT  0 24.021 0.018 24.039 ;
        RECT  107.982 23.481 108 23.499 ;
        RECT  0 23.481 0.018 23.499 ;
        RECT  107.982 22.941 108 22.959 ;
        RECT  0 22.941 0.018 22.959 ;
        RECT  107.982 22.401 108 22.419 ;
        RECT  0 22.401 0.018 22.419 ;
        RECT  107.982 21.861 108 21.879 ;
        RECT  0 21.861 0.018 21.879 ;
        RECT  107.982 21.321 108 21.339 ;
        RECT  0 21.321 0.018 21.339 ;
        RECT  107.982 20.781 108 20.799 ;
        RECT  0 20.781 0.018 20.799 ;
        RECT  107.982 20.241 108 20.259 ;
        RECT  0 20.241 0.018 20.259 ;
        RECT  107.982 19.701 108 19.719 ;
        RECT  0 19.701 0.018 19.719 ;
        RECT  107.982 19.161 108 19.179 ;
        RECT  0 19.161 0.018 19.179 ;
        RECT  107.982 18.621 108 18.639 ;
        RECT  0 18.621 0.018 18.639 ;
        RECT  107.982 18.081 108 18.099 ;
        RECT  0 18.081 0.018 18.099 ;
        RECT  107.982 17.541 108 17.559 ;
        RECT  0 17.541 0.018 17.559 ;
        RECT  107.982 17.001 108 17.019 ;
        RECT  0 17.001 0.018 17.019 ;
        RECT  107.982 16.461 108 16.479 ;
        RECT  0 16.461 0.018 16.479 ;
        RECT  107.982 15.921 108 15.939 ;
        RECT  0 15.921 0.018 15.939 ;
        RECT  107.982 15.381 108 15.399 ;
        RECT  0 15.381 0.018 15.399 ;
        RECT  107.982 14.841 108 14.859 ;
        RECT  0 14.841 0.018 14.859 ;
        RECT  107.982 14.301 108 14.319 ;
        RECT  0 14.301 0.018 14.319 ;
        RECT  107.982 13.761 108 13.779 ;
        RECT  0 13.761 0.018 13.779 ;
        RECT  107.982 13.221 108 13.239 ;
        RECT  0 13.221 0.018 13.239 ;
        RECT  107.982 12.681 108 12.699 ;
        RECT  0 12.681 0.018 12.699 ;
        RECT  107.982 12.141 108 12.159 ;
        RECT  0 12.141 0.018 12.159 ;
        RECT  107.982 11.601 108 11.619 ;
        RECT  0 11.601 0.018 11.619 ;
        RECT  107.982 11.061 108 11.079 ;
        RECT  0 11.061 0.018 11.079 ;
        RECT  107.982 10.521 108 10.539 ;
        RECT  0 10.521 0.018 10.539 ;
        RECT  107.982 9.981 108 9.999 ;
        RECT  0 9.981 0.018 9.999 ;
        RECT  107.982 9.441 108 9.459 ;
        RECT  0 9.441 0.018 9.459 ;
        RECT  107.982 8.901 108 8.919 ;
        RECT  0 8.901 0.018 8.919 ;
        RECT  107.982 8.361 108 8.379 ;
        RECT  0 8.361 0.018 8.379 ;
        RECT  107.982 7.821 108 7.839 ;
        RECT  0 7.821 0.018 7.839 ;
        RECT  107.982 7.281 108 7.299 ;
        RECT  0 7.281 0.018 7.299 ;
        RECT  107.982 6.741 108 6.759 ;
        RECT  0 6.741 0.018 6.759 ;
        RECT  107.982 6.201 108 6.219 ;
        RECT  0 6.201 0.018 6.219 ;
        RECT  107.982 5.661 108 5.679 ;
        RECT  0 5.661 0.018 5.679 ;
        RECT  107.982 5.121 108 5.139 ;
        RECT  0 5.121 0.018 5.139 ;
        RECT  107.982 4.581 108 4.599 ;
        RECT  0 4.581 0.018 4.599 ;
        RECT  107.982 4.041 108 4.059 ;
        RECT  0 4.041 0.018 4.059 ;
        RECT  107.982 3.501 108 3.519 ;
        RECT  0 3.501 0.018 3.519 ;
        RECT  107.982 2.961 108 2.979 ;
        RECT  0 2.961 0.018 2.979 ;
        RECT  107.982 2.421 108 2.439 ;
        RECT  0 2.421 0.018 2.439 ;
        RECT  107.982 1.881 108 1.899 ;
        RECT  0 1.881 0.018 1.899 ;
        RECT  107.982 1.341 108 1.359 ;
        RECT  0 1.341 0.018 1.359 ;
        RECT  107.982 0.801 108 0.819 ;
        RECT  0 0.801 0.018 0.819 ;
    END
  END VDD
  PIN VSS
    DIRECTION INOUT ;
    USE GROUND ;
    PORT
      LAYER M7 ;
        RECT  98.056 0.531 98.344 129.069 ;
        RECT  87.256 0.531 87.544 129.069 ;
        RECT  76.456 0.531 76.744 129.069 ;
        RECT  65.656 0.531 65.944 129.069 ;
        RECT  54.856 0.531 55.144 129.069 ;
        RECT  44.056 0.531 44.344 129.069 ;
        RECT  33.256 0.531 33.544 129.069 ;
        RECT  22.456 0.531 22.744 129.069 ;
        RECT  11.656 0.531 11.944 129.069 ;
        RECT  0.856 0.531 1.144 129.069 ;
      LAYER M6 ;
        RECT  107.968 125.196 108 125.484 ;
        RECT  0 125.196 0.032 125.484 ;
        RECT  107.968 119.796 108 120.084 ;
        RECT  0 119.796 0.032 120.084 ;
        RECT  107.968 114.396 108 114.684 ;
        RECT  0 114.396 0.032 114.684 ;
        RECT  107.968 108.996 108 109.284 ;
        RECT  0 108.996 0.032 109.284 ;
        RECT  107.968 103.596 108 103.884 ;
        RECT  0 103.596 0.032 103.884 ;
        RECT  107.968 98.196 108 98.484 ;
        RECT  0 98.196 0.032 98.484 ;
        RECT  107.968 92.796 108 93.084 ;
        RECT  0 92.796 0.032 93.084 ;
        RECT  107.968 87.396 108 87.684 ;
        RECT  0 87.396 0.032 87.684 ;
        RECT  107.968 81.996 108 82.284 ;
        RECT  0 81.996 0.032 82.284 ;
        RECT  107.968 76.596 108 76.884 ;
        RECT  0 76.596 0.032 76.884 ;
        RECT  107.968 71.196 108 71.484 ;
        RECT  0 71.196 0.032 71.484 ;
        RECT  107.968 65.796 108 66.084 ;
        RECT  0 65.796 0.032 66.084 ;
        RECT  107.968 60.396 108 60.684 ;
        RECT  0 60.396 0.032 60.684 ;
        RECT  107.968 54.996 108 55.284 ;
        RECT  0 54.996 0.032 55.284 ;
        RECT  107.968 49.596 108 49.884 ;
        RECT  0 49.596 0.032 49.884 ;
        RECT  107.968 44.196 108 44.484 ;
        RECT  0 44.196 0.032 44.484 ;
        RECT  107.968 38.796 108 39.084 ;
        RECT  0 38.796 0.032 39.084 ;
        RECT  107.968 33.396 108 33.684 ;
        RECT  0 33.396 0.032 33.684 ;
        RECT  107.968 27.996 108 28.284 ;
        RECT  0 27.996 0.032 28.284 ;
        RECT  107.968 22.596 108 22.884 ;
        RECT  0 22.596 0.032 22.884 ;
        RECT  107.968 17.196 108 17.484 ;
        RECT  0 17.196 0.032 17.484 ;
        RECT  107.968 11.796 108 12.084 ;
        RECT  0 11.796 0.032 12.084 ;
        RECT  107.968 6.396 108 6.684 ;
        RECT  0 6.396 0.032 6.684 ;
        RECT  107.968 0.996 108 1.284 ;
        RECT  0 0.996 0.032 1.284 ;
      LAYER M2 ;
        RECT  107.982 129.051 108 129.069 ;
        RECT  0 129.051 0.018 129.069 ;
        RECT  107.982 128.511 108 128.529 ;
        RECT  0 128.511 0.018 128.529 ;
        RECT  107.982 127.971 108 127.989 ;
        RECT  0 127.971 0.018 127.989 ;
        RECT  107.982 127.431 108 127.449 ;
        RECT  0 127.431 0.018 127.449 ;
        RECT  107.982 126.891 108 126.909 ;
        RECT  0 126.891 0.018 126.909 ;
        RECT  107.982 126.351 108 126.369 ;
        RECT  0 126.351 0.018 126.369 ;
        RECT  107.982 125.811 108 125.829 ;
        RECT  0 125.811 0.018 125.829 ;
        RECT  107.982 125.271 108 125.289 ;
        RECT  0 125.271 0.018 125.289 ;
        RECT  107.982 124.731 108 124.749 ;
        RECT  0 124.731 0.018 124.749 ;
        RECT  107.982 124.191 108 124.209 ;
        RECT  0 124.191 0.018 124.209 ;
        RECT  107.982 123.651 108 123.669 ;
        RECT  0 123.651 0.018 123.669 ;
        RECT  107.982 123.111 108 123.129 ;
        RECT  0 123.111 0.018 123.129 ;
        RECT  107.982 122.571 108 122.589 ;
        RECT  0 122.571 0.018 122.589 ;
        RECT  107.982 122.031 108 122.049 ;
        RECT  0 122.031 0.018 122.049 ;
        RECT  107.982 121.491 108 121.509 ;
        RECT  0 121.491 0.018 121.509 ;
        RECT  107.982 120.951 108 120.969 ;
        RECT  0 120.951 0.018 120.969 ;
        RECT  107.982 120.411 108 120.429 ;
        RECT  0 120.411 0.018 120.429 ;
        RECT  107.982 119.871 108 119.889 ;
        RECT  0 119.871 0.018 119.889 ;
        RECT  107.982 119.331 108 119.349 ;
        RECT  0 119.331 0.018 119.349 ;
        RECT  107.982 118.791 108 118.809 ;
        RECT  0 118.791 0.018 118.809 ;
        RECT  107.982 118.251 108 118.269 ;
        RECT  0 118.251 0.018 118.269 ;
        RECT  107.982 117.711 108 117.729 ;
        RECT  0 117.711 0.018 117.729 ;
        RECT  107.982 117.171 108 117.189 ;
        RECT  0 117.171 0.018 117.189 ;
        RECT  107.982 116.631 108 116.649 ;
        RECT  0 116.631 0.018 116.649 ;
        RECT  107.982 116.091 108 116.109 ;
        RECT  0 116.091 0.018 116.109 ;
        RECT  107.982 115.551 108 115.569 ;
        RECT  0 115.551 0.018 115.569 ;
        RECT  107.982 115.011 108 115.029 ;
        RECT  0 115.011 0.018 115.029 ;
        RECT  107.982 114.471 108 114.489 ;
        RECT  0 114.471 0.018 114.489 ;
        RECT  107.982 113.931 108 113.949 ;
        RECT  0 113.931 0.018 113.949 ;
        RECT  107.982 113.391 108 113.409 ;
        RECT  0 113.391 0.018 113.409 ;
        RECT  107.982 112.851 108 112.869 ;
        RECT  0 112.851 0.018 112.869 ;
        RECT  107.982 112.311 108 112.329 ;
        RECT  0 112.311 0.018 112.329 ;
        RECT  107.982 111.771 108 111.789 ;
        RECT  0 111.771 0.018 111.789 ;
        RECT  107.982 111.231 108 111.249 ;
        RECT  0 111.231 0.018 111.249 ;
        RECT  107.982 110.691 108 110.709 ;
        RECT  0 110.691 0.018 110.709 ;
        RECT  107.982 110.151 108 110.169 ;
        RECT  0 110.151 0.018 110.169 ;
        RECT  107.982 109.611 108 109.629 ;
        RECT  0 109.611 0.018 109.629 ;
        RECT  107.982 109.071 108 109.089 ;
        RECT  0 109.071 0.018 109.089 ;
        RECT  107.982 108.531 108 108.549 ;
        RECT  0 108.531 0.018 108.549 ;
        RECT  107.982 107.991 108 108.009 ;
        RECT  0 107.991 0.018 108.009 ;
        RECT  107.982 107.451 108 107.469 ;
        RECT  0 107.451 0.018 107.469 ;
        RECT  107.982 106.911 108 106.929 ;
        RECT  0 106.911 0.018 106.929 ;
        RECT  107.982 106.371 108 106.389 ;
        RECT  0 106.371 0.018 106.389 ;
        RECT  107.982 105.831 108 105.849 ;
        RECT  0 105.831 0.018 105.849 ;
        RECT  107.982 105.291 108 105.309 ;
        RECT  0 105.291 0.018 105.309 ;
        RECT  107.982 104.751 108 104.769 ;
        RECT  0 104.751 0.018 104.769 ;
        RECT  107.982 104.211 108 104.229 ;
        RECT  0 104.211 0.018 104.229 ;
        RECT  107.982 103.671 108 103.689 ;
        RECT  0 103.671 0.018 103.689 ;
        RECT  107.982 103.131 108 103.149 ;
        RECT  0 103.131 0.018 103.149 ;
        RECT  107.982 102.591 108 102.609 ;
        RECT  0 102.591 0.018 102.609 ;
        RECT  107.982 102.051 108 102.069 ;
        RECT  0 102.051 0.018 102.069 ;
        RECT  107.982 101.511 108 101.529 ;
        RECT  0 101.511 0.018 101.529 ;
        RECT  107.982 100.971 108 100.989 ;
        RECT  0 100.971 0.018 100.989 ;
        RECT  107.982 100.431 108 100.449 ;
        RECT  0 100.431 0.018 100.449 ;
        RECT  107.982 99.891 108 99.909 ;
        RECT  0 99.891 0.018 99.909 ;
        RECT  107.982 99.351 108 99.369 ;
        RECT  0 99.351 0.018 99.369 ;
        RECT  107.982 98.811 108 98.829 ;
        RECT  0 98.811 0.018 98.829 ;
        RECT  107.982 98.271 108 98.289 ;
        RECT  0 98.271 0.018 98.289 ;
        RECT  107.982 97.731 108 97.749 ;
        RECT  0 97.731 0.018 97.749 ;
        RECT  107.982 97.191 108 97.209 ;
        RECT  0 97.191 0.018 97.209 ;
        RECT  107.982 96.651 108 96.669 ;
        RECT  0 96.651 0.018 96.669 ;
        RECT  107.982 96.111 108 96.129 ;
        RECT  0 96.111 0.018 96.129 ;
        RECT  107.982 95.571 108 95.589 ;
        RECT  0 95.571 0.018 95.589 ;
        RECT  107.982 95.031 108 95.049 ;
        RECT  0 95.031 0.018 95.049 ;
        RECT  107.982 94.491 108 94.509 ;
        RECT  0 94.491 0.018 94.509 ;
        RECT  107.982 93.951 108 93.969 ;
        RECT  0 93.951 0.018 93.969 ;
        RECT  107.982 93.411 108 93.429 ;
        RECT  0 93.411 0.018 93.429 ;
        RECT  107.982 92.871 108 92.889 ;
        RECT  0 92.871 0.018 92.889 ;
        RECT  107.982 92.331 108 92.349 ;
        RECT  0 92.331 0.018 92.349 ;
        RECT  107.982 91.791 108 91.809 ;
        RECT  0 91.791 0.018 91.809 ;
        RECT  107.982 91.251 108 91.269 ;
        RECT  0 91.251 0.018 91.269 ;
        RECT  107.982 90.711 108 90.729 ;
        RECT  0 90.711 0.018 90.729 ;
        RECT  107.982 90.171 108 90.189 ;
        RECT  0 90.171 0.018 90.189 ;
        RECT  107.982 89.631 108 89.649 ;
        RECT  0 89.631 0.018 89.649 ;
        RECT  107.982 89.091 108 89.109 ;
        RECT  0 89.091 0.018 89.109 ;
        RECT  107.982 88.551 108 88.569 ;
        RECT  0 88.551 0.018 88.569 ;
        RECT  107.982 88.011 108 88.029 ;
        RECT  0 88.011 0.018 88.029 ;
        RECT  107.982 87.471 108 87.489 ;
        RECT  0 87.471 0.018 87.489 ;
        RECT  107.982 86.931 108 86.949 ;
        RECT  0 86.931 0.018 86.949 ;
        RECT  107.982 86.391 108 86.409 ;
        RECT  0 86.391 0.018 86.409 ;
        RECT  107.982 85.851 108 85.869 ;
        RECT  0 85.851 0.018 85.869 ;
        RECT  107.982 85.311 108 85.329 ;
        RECT  0 85.311 0.018 85.329 ;
        RECT  107.982 84.771 108 84.789 ;
        RECT  0 84.771 0.018 84.789 ;
        RECT  107.982 84.231 108 84.249 ;
        RECT  0 84.231 0.018 84.249 ;
        RECT  107.982 83.691 108 83.709 ;
        RECT  0 83.691 0.018 83.709 ;
        RECT  107.982 83.151 108 83.169 ;
        RECT  0 83.151 0.018 83.169 ;
        RECT  107.982 82.611 108 82.629 ;
        RECT  0 82.611 0.018 82.629 ;
        RECT  107.982 82.071 108 82.089 ;
        RECT  0 82.071 0.018 82.089 ;
        RECT  107.982 81.531 108 81.549 ;
        RECT  0 81.531 0.018 81.549 ;
        RECT  107.982 80.991 108 81.009 ;
        RECT  0 80.991 0.018 81.009 ;
        RECT  107.982 80.451 108 80.469 ;
        RECT  0 80.451 0.018 80.469 ;
        RECT  107.982 79.911 108 79.929 ;
        RECT  0 79.911 0.018 79.929 ;
        RECT  107.982 79.371 108 79.389 ;
        RECT  0 79.371 0.018 79.389 ;
        RECT  107.982 78.831 108 78.849 ;
        RECT  0 78.831 0.018 78.849 ;
        RECT  107.982 78.291 108 78.309 ;
        RECT  0 78.291 0.018 78.309 ;
        RECT  107.982 77.751 108 77.769 ;
        RECT  0 77.751 0.018 77.769 ;
        RECT  107.982 77.211 108 77.229 ;
        RECT  0 77.211 0.018 77.229 ;
        RECT  107.982 76.671 108 76.689 ;
        RECT  0 76.671 0.018 76.689 ;
        RECT  107.982 76.131 108 76.149 ;
        RECT  0 76.131 0.018 76.149 ;
        RECT  107.982 75.591 108 75.609 ;
        RECT  0 75.591 0.018 75.609 ;
        RECT  107.982 75.051 108 75.069 ;
        RECT  0 75.051 0.018 75.069 ;
        RECT  107.982 74.511 108 74.529 ;
        RECT  0 74.511 0.018 74.529 ;
        RECT  107.982 73.971 108 73.989 ;
        RECT  0 73.971 0.018 73.989 ;
        RECT  107.982 73.431 108 73.449 ;
        RECT  0 73.431 0.018 73.449 ;
        RECT  107.982 72.891 108 72.909 ;
        RECT  0 72.891 0.018 72.909 ;
        RECT  107.982 72.351 108 72.369 ;
        RECT  0 72.351 0.018 72.369 ;
        RECT  107.982 71.811 108 71.829 ;
        RECT  0 71.811 0.018 71.829 ;
        RECT  107.982 71.271 108 71.289 ;
        RECT  0 71.271 0.018 71.289 ;
        RECT  107.982 70.731 108 70.749 ;
        RECT  0 70.731 0.018 70.749 ;
        RECT  107.982 70.191 108 70.209 ;
        RECT  0 70.191 0.018 70.209 ;
        RECT  107.982 69.651 108 69.669 ;
        RECT  0 69.651 0.018 69.669 ;
        RECT  107.982 69.111 108 69.129 ;
        RECT  0 69.111 0.018 69.129 ;
        RECT  107.982 68.571 108 68.589 ;
        RECT  0 68.571 0.018 68.589 ;
        RECT  107.982 68.031 108 68.049 ;
        RECT  0 68.031 0.018 68.049 ;
        RECT  107.982 67.491 108 67.509 ;
        RECT  0 67.491 0.018 67.509 ;
        RECT  107.982 66.951 108 66.969 ;
        RECT  0 66.951 0.018 66.969 ;
        RECT  107.982 66.411 108 66.429 ;
        RECT  0 66.411 0.018 66.429 ;
        RECT  107.982 65.871 108 65.889 ;
        RECT  0 65.871 0.018 65.889 ;
        RECT  107.982 65.331 108 65.349 ;
        RECT  0 65.331 0.018 65.349 ;
        RECT  107.982 64.791 108 64.809 ;
        RECT  0 64.791 0.018 64.809 ;
        RECT  107.982 64.251 108 64.269 ;
        RECT  0 64.251 0.018 64.269 ;
        RECT  107.982 63.711 108 63.729 ;
        RECT  0 63.711 0.018 63.729 ;
        RECT  107.982 63.171 108 63.189 ;
        RECT  0 63.171 0.018 63.189 ;
        RECT  107.982 62.631 108 62.649 ;
        RECT  0 62.631 0.018 62.649 ;
        RECT  107.982 62.091 108 62.109 ;
        RECT  0 62.091 0.018 62.109 ;
        RECT  107.982 61.551 108 61.569 ;
        RECT  0 61.551 0.018 61.569 ;
        RECT  107.982 61.011 108 61.029 ;
        RECT  0 61.011 0.018 61.029 ;
        RECT  107.982 60.471 108 60.489 ;
        RECT  0 60.471 0.018 60.489 ;
        RECT  107.982 59.931 108 59.949 ;
        RECT  0 59.931 0.018 59.949 ;
        RECT  107.982 59.391 108 59.409 ;
        RECT  0 59.391 0.018 59.409 ;
        RECT  107.982 58.851 108 58.869 ;
        RECT  0 58.851 0.018 58.869 ;
        RECT  107.982 58.311 108 58.329 ;
        RECT  0 58.311 0.018 58.329 ;
        RECT  107.982 57.771 108 57.789 ;
        RECT  0 57.771 0.018 57.789 ;
        RECT  107.982 57.231 108 57.249 ;
        RECT  0 57.231 0.018 57.249 ;
        RECT  107.982 56.691 108 56.709 ;
        RECT  0 56.691 0.018 56.709 ;
        RECT  107.982 56.151 108 56.169 ;
        RECT  0 56.151 0.018 56.169 ;
        RECT  107.982 55.611 108 55.629 ;
        RECT  0 55.611 0.018 55.629 ;
        RECT  107.982 55.071 108 55.089 ;
        RECT  0 55.071 0.018 55.089 ;
        RECT  107.982 54.531 108 54.549 ;
        RECT  0 54.531 0.018 54.549 ;
        RECT  107.982 53.991 108 54.009 ;
        RECT  0 53.991 0.018 54.009 ;
        RECT  107.982 53.451 108 53.469 ;
        RECT  0 53.451 0.018 53.469 ;
        RECT  107.982 52.911 108 52.929 ;
        RECT  0 52.911 0.018 52.929 ;
        RECT  107.982 52.371 108 52.389 ;
        RECT  0 52.371 0.018 52.389 ;
        RECT  107.982 51.831 108 51.849 ;
        RECT  0 51.831 0.018 51.849 ;
        RECT  107.982 51.291 108 51.309 ;
        RECT  0 51.291 0.018 51.309 ;
        RECT  107.982 50.751 108 50.769 ;
        RECT  0 50.751 0.018 50.769 ;
        RECT  107.982 50.211 108 50.229 ;
        RECT  0 50.211 0.018 50.229 ;
        RECT  107.982 49.671 108 49.689 ;
        RECT  0 49.671 0.018 49.689 ;
        RECT  107.982 49.131 108 49.149 ;
        RECT  0 49.131 0.018 49.149 ;
        RECT  107.982 48.591 108 48.609 ;
        RECT  0 48.591 0.018 48.609 ;
        RECT  107.982 48.051 108 48.069 ;
        RECT  0 48.051 0.018 48.069 ;
        RECT  107.982 47.511 108 47.529 ;
        RECT  0 47.511 0.018 47.529 ;
        RECT  107.982 46.971 108 46.989 ;
        RECT  0 46.971 0.018 46.989 ;
        RECT  107.982 46.431 108 46.449 ;
        RECT  0 46.431 0.018 46.449 ;
        RECT  107.982 45.891 108 45.909 ;
        RECT  0 45.891 0.018 45.909 ;
        RECT  107.982 45.351 108 45.369 ;
        RECT  0 45.351 0.018 45.369 ;
        RECT  107.982 44.811 108 44.829 ;
        RECT  0 44.811 0.018 44.829 ;
        RECT  107.982 44.271 108 44.289 ;
        RECT  0 44.271 0.018 44.289 ;
        RECT  107.982 43.731 108 43.749 ;
        RECT  0 43.731 0.018 43.749 ;
        RECT  107.982 43.191 108 43.209 ;
        RECT  0 43.191 0.018 43.209 ;
        RECT  107.982 42.651 108 42.669 ;
        RECT  0 42.651 0.018 42.669 ;
        RECT  107.982 42.111 108 42.129 ;
        RECT  0 42.111 0.018 42.129 ;
        RECT  107.982 41.571 108 41.589 ;
        RECT  0 41.571 0.018 41.589 ;
        RECT  107.982 41.031 108 41.049 ;
        RECT  0 41.031 0.018 41.049 ;
        RECT  107.982 40.491 108 40.509 ;
        RECT  0 40.491 0.018 40.509 ;
        RECT  107.982 39.951 108 39.969 ;
        RECT  0 39.951 0.018 39.969 ;
        RECT  107.982 39.411 108 39.429 ;
        RECT  0 39.411 0.018 39.429 ;
        RECT  107.982 38.871 108 38.889 ;
        RECT  0 38.871 0.018 38.889 ;
        RECT  107.982 38.331 108 38.349 ;
        RECT  0 38.331 0.018 38.349 ;
        RECT  107.982 37.791 108 37.809 ;
        RECT  0 37.791 0.018 37.809 ;
        RECT  107.982 37.251 108 37.269 ;
        RECT  0 37.251 0.018 37.269 ;
        RECT  107.982 36.711 108 36.729 ;
        RECT  0 36.711 0.018 36.729 ;
        RECT  107.982 36.171 108 36.189 ;
        RECT  0 36.171 0.018 36.189 ;
        RECT  107.982 35.631 108 35.649 ;
        RECT  0 35.631 0.018 35.649 ;
        RECT  107.982 35.091 108 35.109 ;
        RECT  0 35.091 0.018 35.109 ;
        RECT  107.982 34.551 108 34.569 ;
        RECT  0 34.551 0.018 34.569 ;
        RECT  107.982 34.011 108 34.029 ;
        RECT  0 34.011 0.018 34.029 ;
        RECT  107.982 33.471 108 33.489 ;
        RECT  0 33.471 0.018 33.489 ;
        RECT  107.982 32.931 108 32.949 ;
        RECT  0 32.931 0.018 32.949 ;
        RECT  107.982 32.391 108 32.409 ;
        RECT  0 32.391 0.018 32.409 ;
        RECT  107.982 31.851 108 31.869 ;
        RECT  0 31.851 0.018 31.869 ;
        RECT  107.982 31.311 108 31.329 ;
        RECT  0 31.311 0.018 31.329 ;
        RECT  107.982 30.771 108 30.789 ;
        RECT  0 30.771 0.018 30.789 ;
        RECT  107.982 30.231 108 30.249 ;
        RECT  0 30.231 0.018 30.249 ;
        RECT  107.982 29.691 108 29.709 ;
        RECT  0 29.691 0.018 29.709 ;
        RECT  107.982 29.151 108 29.169 ;
        RECT  0 29.151 0.018 29.169 ;
        RECT  107.982 28.611 108 28.629 ;
        RECT  0 28.611 0.018 28.629 ;
        RECT  107.982 28.071 108 28.089 ;
        RECT  0 28.071 0.018 28.089 ;
        RECT  107.982 27.531 108 27.549 ;
        RECT  0 27.531 0.018 27.549 ;
        RECT  107.982 26.991 108 27.009 ;
        RECT  0 26.991 0.018 27.009 ;
        RECT  107.982 26.451 108 26.469 ;
        RECT  0 26.451 0.018 26.469 ;
        RECT  107.982 25.911 108 25.929 ;
        RECT  0 25.911 0.018 25.929 ;
        RECT  107.982 25.371 108 25.389 ;
        RECT  0 25.371 0.018 25.389 ;
        RECT  107.982 24.831 108 24.849 ;
        RECT  0 24.831 0.018 24.849 ;
        RECT  107.982 24.291 108 24.309 ;
        RECT  0 24.291 0.018 24.309 ;
        RECT  107.982 23.751 108 23.769 ;
        RECT  0 23.751 0.018 23.769 ;
        RECT  107.982 23.211 108 23.229 ;
        RECT  0 23.211 0.018 23.229 ;
        RECT  107.982 22.671 108 22.689 ;
        RECT  0 22.671 0.018 22.689 ;
        RECT  107.982 22.131 108 22.149 ;
        RECT  0 22.131 0.018 22.149 ;
        RECT  107.982 21.591 108 21.609 ;
        RECT  0 21.591 0.018 21.609 ;
        RECT  107.982 21.051 108 21.069 ;
        RECT  0 21.051 0.018 21.069 ;
        RECT  107.982 20.511 108 20.529 ;
        RECT  0 20.511 0.018 20.529 ;
        RECT  107.982 19.971 108 19.989 ;
        RECT  0 19.971 0.018 19.989 ;
        RECT  107.982 19.431 108 19.449 ;
        RECT  0 19.431 0.018 19.449 ;
        RECT  107.982 18.891 108 18.909 ;
        RECT  0 18.891 0.018 18.909 ;
        RECT  107.982 18.351 108 18.369 ;
        RECT  0 18.351 0.018 18.369 ;
        RECT  107.982 17.811 108 17.829 ;
        RECT  0 17.811 0.018 17.829 ;
        RECT  107.982 17.271 108 17.289 ;
        RECT  0 17.271 0.018 17.289 ;
        RECT  107.982 16.731 108 16.749 ;
        RECT  0 16.731 0.018 16.749 ;
        RECT  107.982 16.191 108 16.209 ;
        RECT  0 16.191 0.018 16.209 ;
        RECT  107.982 15.651 108 15.669 ;
        RECT  0 15.651 0.018 15.669 ;
        RECT  107.982 15.111 108 15.129 ;
        RECT  0 15.111 0.018 15.129 ;
        RECT  107.982 14.571 108 14.589 ;
        RECT  0 14.571 0.018 14.589 ;
        RECT  107.982 14.031 108 14.049 ;
        RECT  0 14.031 0.018 14.049 ;
        RECT  107.982 13.491 108 13.509 ;
        RECT  0 13.491 0.018 13.509 ;
        RECT  107.982 12.951 108 12.969 ;
        RECT  0 12.951 0.018 12.969 ;
        RECT  107.982 12.411 108 12.429 ;
        RECT  0 12.411 0.018 12.429 ;
        RECT  107.982 11.871 108 11.889 ;
        RECT  0 11.871 0.018 11.889 ;
        RECT  107.982 11.331 108 11.349 ;
        RECT  0 11.331 0.018 11.349 ;
        RECT  107.982 10.791 108 10.809 ;
        RECT  0 10.791 0.018 10.809 ;
        RECT  107.982 10.251 108 10.269 ;
        RECT  0 10.251 0.018 10.269 ;
        RECT  107.982 9.711 108 9.729 ;
        RECT  0 9.711 0.018 9.729 ;
        RECT  107.982 9.171 108 9.189 ;
        RECT  0 9.171 0.018 9.189 ;
        RECT  107.982 8.631 108 8.649 ;
        RECT  0 8.631 0.018 8.649 ;
        RECT  107.982 8.091 108 8.109 ;
        RECT  0 8.091 0.018 8.109 ;
        RECT  107.982 7.551 108 7.569 ;
        RECT  0 7.551 0.018 7.569 ;
        RECT  107.982 7.011 108 7.029 ;
        RECT  0 7.011 0.018 7.029 ;
        RECT  107.982 6.471 108 6.489 ;
        RECT  0 6.471 0.018 6.489 ;
        RECT  107.982 5.931 108 5.949 ;
        RECT  0 5.931 0.018 5.949 ;
        RECT  107.982 5.391 108 5.409 ;
        RECT  0 5.391 0.018 5.409 ;
        RECT  107.982 4.851 108 4.869 ;
        RECT  0 4.851 0.018 4.869 ;
        RECT  107.982 4.311 108 4.329 ;
        RECT  0 4.311 0.018 4.329 ;
        RECT  107.982 3.771 108 3.789 ;
        RECT  0 3.771 0.018 3.789 ;
        RECT  107.982 3.231 108 3.249 ;
        RECT  0 3.231 0.018 3.249 ;
        RECT  107.982 2.691 108 2.709 ;
        RECT  0 2.691 0.018 2.709 ;
        RECT  107.982 2.151 108 2.169 ;
        RECT  0 2.151 0.018 2.169 ;
        RECT  107.982 1.611 108 1.629 ;
        RECT  0 1.611 0.018 1.629 ;
        RECT  107.982 1.071 108 1.089 ;
        RECT  0 1.071 0.018 1.089 ;
        RECT  107.982 0.531 108 0.549 ;
        RECT  0 0.531 0.018 0.549 ;
      LAYER M1 ;
        RECT  107.982 129.051 108 129.069 ;
        RECT  0 129.051 0.018 129.069 ;
        RECT  107.982 128.511 108 128.529 ;
        RECT  0 128.511 0.018 128.529 ;
        RECT  107.982 127.971 108 127.989 ;
        RECT  0 127.971 0.018 127.989 ;
        RECT  107.982 127.431 108 127.449 ;
        RECT  0 127.431 0.018 127.449 ;
        RECT  107.982 126.891 108 126.909 ;
        RECT  0 126.891 0.018 126.909 ;
        RECT  107.982 126.351 108 126.369 ;
        RECT  0 126.351 0.018 126.369 ;
        RECT  107.982 125.811 108 125.829 ;
        RECT  0 125.811 0.018 125.829 ;
        RECT  107.982 125.271 108 125.289 ;
        RECT  0 125.271 0.018 125.289 ;
        RECT  107.982 124.731 108 124.749 ;
        RECT  0 124.731 0.018 124.749 ;
        RECT  107.982 124.191 108 124.209 ;
        RECT  0 124.191 0.018 124.209 ;
        RECT  107.982 123.651 108 123.669 ;
        RECT  0 123.651 0.018 123.669 ;
        RECT  107.982 123.111 108 123.129 ;
        RECT  0 123.111 0.018 123.129 ;
        RECT  107.982 122.571 108 122.589 ;
        RECT  0 122.571 0.018 122.589 ;
        RECT  107.982 122.031 108 122.049 ;
        RECT  0 122.031 0.018 122.049 ;
        RECT  107.982 121.491 108 121.509 ;
        RECT  0 121.491 0.018 121.509 ;
        RECT  107.982 120.951 108 120.969 ;
        RECT  0 120.951 0.018 120.969 ;
        RECT  107.982 120.411 108 120.429 ;
        RECT  0 120.411 0.018 120.429 ;
        RECT  107.982 119.871 108 119.889 ;
        RECT  0 119.871 0.018 119.889 ;
        RECT  107.982 119.331 108 119.349 ;
        RECT  0 119.331 0.018 119.349 ;
        RECT  107.982 118.791 108 118.809 ;
        RECT  0 118.791 0.018 118.809 ;
        RECT  107.982 118.251 108 118.269 ;
        RECT  0 118.251 0.018 118.269 ;
        RECT  107.982 117.711 108 117.729 ;
        RECT  0 117.711 0.018 117.729 ;
        RECT  107.982 117.171 108 117.189 ;
        RECT  0 117.171 0.018 117.189 ;
        RECT  107.982 116.631 108 116.649 ;
        RECT  0 116.631 0.018 116.649 ;
        RECT  107.982 116.091 108 116.109 ;
        RECT  0 116.091 0.018 116.109 ;
        RECT  107.982 115.551 108 115.569 ;
        RECT  0 115.551 0.018 115.569 ;
        RECT  107.982 115.011 108 115.029 ;
        RECT  0 115.011 0.018 115.029 ;
        RECT  107.982 114.471 108 114.489 ;
        RECT  0 114.471 0.018 114.489 ;
        RECT  107.982 113.931 108 113.949 ;
        RECT  0 113.931 0.018 113.949 ;
        RECT  107.982 113.391 108 113.409 ;
        RECT  0 113.391 0.018 113.409 ;
        RECT  107.982 112.851 108 112.869 ;
        RECT  0 112.851 0.018 112.869 ;
        RECT  107.982 112.311 108 112.329 ;
        RECT  0 112.311 0.018 112.329 ;
        RECT  107.982 111.771 108 111.789 ;
        RECT  0 111.771 0.018 111.789 ;
        RECT  107.982 111.231 108 111.249 ;
        RECT  0 111.231 0.018 111.249 ;
        RECT  107.982 110.691 108 110.709 ;
        RECT  0 110.691 0.018 110.709 ;
        RECT  107.982 110.151 108 110.169 ;
        RECT  0 110.151 0.018 110.169 ;
        RECT  107.982 109.611 108 109.629 ;
        RECT  0 109.611 0.018 109.629 ;
        RECT  107.982 109.071 108 109.089 ;
        RECT  0 109.071 0.018 109.089 ;
        RECT  107.982 108.531 108 108.549 ;
        RECT  0 108.531 0.018 108.549 ;
        RECT  107.982 107.991 108 108.009 ;
        RECT  0 107.991 0.018 108.009 ;
        RECT  107.982 107.451 108 107.469 ;
        RECT  0 107.451 0.018 107.469 ;
        RECT  107.982 106.911 108 106.929 ;
        RECT  0 106.911 0.018 106.929 ;
        RECT  107.982 106.371 108 106.389 ;
        RECT  0 106.371 0.018 106.389 ;
        RECT  107.982 105.831 108 105.849 ;
        RECT  0 105.831 0.018 105.849 ;
        RECT  107.982 105.291 108 105.309 ;
        RECT  0 105.291 0.018 105.309 ;
        RECT  107.982 104.751 108 104.769 ;
        RECT  0 104.751 0.018 104.769 ;
        RECT  107.982 104.211 108 104.229 ;
        RECT  0 104.211 0.018 104.229 ;
        RECT  107.982 103.671 108 103.689 ;
        RECT  0 103.671 0.018 103.689 ;
        RECT  107.982 103.131 108 103.149 ;
        RECT  0 103.131 0.018 103.149 ;
        RECT  107.982 102.591 108 102.609 ;
        RECT  0 102.591 0.018 102.609 ;
        RECT  107.982 102.051 108 102.069 ;
        RECT  0 102.051 0.018 102.069 ;
        RECT  107.982 101.511 108 101.529 ;
        RECT  0 101.511 0.018 101.529 ;
        RECT  107.982 100.971 108 100.989 ;
        RECT  0 100.971 0.018 100.989 ;
        RECT  107.982 100.431 108 100.449 ;
        RECT  0 100.431 0.018 100.449 ;
        RECT  107.982 99.891 108 99.909 ;
        RECT  0 99.891 0.018 99.909 ;
        RECT  107.982 99.351 108 99.369 ;
        RECT  0 99.351 0.018 99.369 ;
        RECT  107.982 98.811 108 98.829 ;
        RECT  0 98.811 0.018 98.829 ;
        RECT  107.982 98.271 108 98.289 ;
        RECT  0 98.271 0.018 98.289 ;
        RECT  107.982 97.731 108 97.749 ;
        RECT  0 97.731 0.018 97.749 ;
        RECT  107.982 97.191 108 97.209 ;
        RECT  0 97.191 0.018 97.209 ;
        RECT  107.982 96.651 108 96.669 ;
        RECT  0 96.651 0.018 96.669 ;
        RECT  107.982 96.111 108 96.129 ;
        RECT  0 96.111 0.018 96.129 ;
        RECT  107.982 95.571 108 95.589 ;
        RECT  0 95.571 0.018 95.589 ;
        RECT  107.982 95.031 108 95.049 ;
        RECT  0 95.031 0.018 95.049 ;
        RECT  107.982 94.491 108 94.509 ;
        RECT  0 94.491 0.018 94.509 ;
        RECT  107.982 93.951 108 93.969 ;
        RECT  0 93.951 0.018 93.969 ;
        RECT  107.982 93.411 108 93.429 ;
        RECT  0 93.411 0.018 93.429 ;
        RECT  107.982 92.871 108 92.889 ;
        RECT  0 92.871 0.018 92.889 ;
        RECT  107.982 92.331 108 92.349 ;
        RECT  0 92.331 0.018 92.349 ;
        RECT  107.982 91.791 108 91.809 ;
        RECT  0 91.791 0.018 91.809 ;
        RECT  107.982 91.251 108 91.269 ;
        RECT  0 91.251 0.018 91.269 ;
        RECT  107.982 90.711 108 90.729 ;
        RECT  0 90.711 0.018 90.729 ;
        RECT  107.982 90.171 108 90.189 ;
        RECT  0 90.171 0.018 90.189 ;
        RECT  107.982 89.631 108 89.649 ;
        RECT  0 89.631 0.018 89.649 ;
        RECT  107.982 89.091 108 89.109 ;
        RECT  0 89.091 0.018 89.109 ;
        RECT  107.982 88.551 108 88.569 ;
        RECT  0 88.551 0.018 88.569 ;
        RECT  107.982 88.011 108 88.029 ;
        RECT  0 88.011 0.018 88.029 ;
        RECT  107.982 87.471 108 87.489 ;
        RECT  0 87.471 0.018 87.489 ;
        RECT  107.982 86.931 108 86.949 ;
        RECT  0 86.931 0.018 86.949 ;
        RECT  107.982 86.391 108 86.409 ;
        RECT  0 86.391 0.018 86.409 ;
        RECT  107.982 85.851 108 85.869 ;
        RECT  0 85.851 0.018 85.869 ;
        RECT  107.982 85.311 108 85.329 ;
        RECT  0 85.311 0.018 85.329 ;
        RECT  107.982 84.771 108 84.789 ;
        RECT  0 84.771 0.018 84.789 ;
        RECT  107.982 84.231 108 84.249 ;
        RECT  0 84.231 0.018 84.249 ;
        RECT  107.982 83.691 108 83.709 ;
        RECT  0 83.691 0.018 83.709 ;
        RECT  107.982 83.151 108 83.169 ;
        RECT  0 83.151 0.018 83.169 ;
        RECT  107.982 82.611 108 82.629 ;
        RECT  0 82.611 0.018 82.629 ;
        RECT  107.982 82.071 108 82.089 ;
        RECT  0 82.071 0.018 82.089 ;
        RECT  107.982 81.531 108 81.549 ;
        RECT  0 81.531 0.018 81.549 ;
        RECT  107.982 80.991 108 81.009 ;
        RECT  0 80.991 0.018 81.009 ;
        RECT  107.982 80.451 108 80.469 ;
        RECT  0 80.451 0.018 80.469 ;
        RECT  107.982 79.911 108 79.929 ;
        RECT  0 79.911 0.018 79.929 ;
        RECT  107.982 79.371 108 79.389 ;
        RECT  0 79.371 0.018 79.389 ;
        RECT  107.982 78.831 108 78.849 ;
        RECT  0 78.831 0.018 78.849 ;
        RECT  107.982 78.291 108 78.309 ;
        RECT  0 78.291 0.018 78.309 ;
        RECT  107.982 77.751 108 77.769 ;
        RECT  0 77.751 0.018 77.769 ;
        RECT  107.982 77.211 108 77.229 ;
        RECT  0 77.211 0.018 77.229 ;
        RECT  107.982 76.671 108 76.689 ;
        RECT  0 76.671 0.018 76.689 ;
        RECT  107.982 76.131 108 76.149 ;
        RECT  0 76.131 0.018 76.149 ;
        RECT  107.982 75.591 108 75.609 ;
        RECT  0 75.591 0.018 75.609 ;
        RECT  107.982 75.051 108 75.069 ;
        RECT  0 75.051 0.018 75.069 ;
        RECT  107.982 74.511 108 74.529 ;
        RECT  0 74.511 0.018 74.529 ;
        RECT  107.982 73.971 108 73.989 ;
        RECT  0 73.971 0.018 73.989 ;
        RECT  107.982 73.431 108 73.449 ;
        RECT  0 73.431 0.018 73.449 ;
        RECT  107.982 72.891 108 72.909 ;
        RECT  0 72.891 0.018 72.909 ;
        RECT  107.982 72.351 108 72.369 ;
        RECT  0 72.351 0.018 72.369 ;
        RECT  107.982 71.811 108 71.829 ;
        RECT  0 71.811 0.018 71.829 ;
        RECT  107.982 71.271 108 71.289 ;
        RECT  0 71.271 0.018 71.289 ;
        RECT  107.982 70.731 108 70.749 ;
        RECT  0 70.731 0.018 70.749 ;
        RECT  107.982 70.191 108 70.209 ;
        RECT  0 70.191 0.018 70.209 ;
        RECT  107.982 69.651 108 69.669 ;
        RECT  0 69.651 0.018 69.669 ;
        RECT  107.982 69.111 108 69.129 ;
        RECT  0 69.111 0.018 69.129 ;
        RECT  107.982 68.571 108 68.589 ;
        RECT  0 68.571 0.018 68.589 ;
        RECT  107.982 68.031 108 68.049 ;
        RECT  0 68.031 0.018 68.049 ;
        RECT  107.982 67.491 108 67.509 ;
        RECT  0 67.491 0.018 67.509 ;
        RECT  107.982 66.951 108 66.969 ;
        RECT  0 66.951 0.018 66.969 ;
        RECT  107.982 66.411 108 66.429 ;
        RECT  0 66.411 0.018 66.429 ;
        RECT  107.982 65.871 108 65.889 ;
        RECT  0 65.871 0.018 65.889 ;
        RECT  107.982 65.331 108 65.349 ;
        RECT  0 65.331 0.018 65.349 ;
        RECT  107.982 64.791 108 64.809 ;
        RECT  0 64.791 0.018 64.809 ;
        RECT  107.982 64.251 108 64.269 ;
        RECT  0 64.251 0.018 64.269 ;
        RECT  107.982 63.711 108 63.729 ;
        RECT  0 63.711 0.018 63.729 ;
        RECT  107.982 63.171 108 63.189 ;
        RECT  0 63.171 0.018 63.189 ;
        RECT  107.982 62.631 108 62.649 ;
        RECT  0 62.631 0.018 62.649 ;
        RECT  107.982 62.091 108 62.109 ;
        RECT  0 62.091 0.018 62.109 ;
        RECT  107.982 61.551 108 61.569 ;
        RECT  0 61.551 0.018 61.569 ;
        RECT  107.982 61.011 108 61.029 ;
        RECT  0 61.011 0.018 61.029 ;
        RECT  107.982 60.471 108 60.489 ;
        RECT  0 60.471 0.018 60.489 ;
        RECT  107.982 59.931 108 59.949 ;
        RECT  0 59.931 0.018 59.949 ;
        RECT  107.982 59.391 108 59.409 ;
        RECT  0 59.391 0.018 59.409 ;
        RECT  107.982 58.851 108 58.869 ;
        RECT  0 58.851 0.018 58.869 ;
        RECT  107.982 58.311 108 58.329 ;
        RECT  0 58.311 0.018 58.329 ;
        RECT  107.982 57.771 108 57.789 ;
        RECT  0 57.771 0.018 57.789 ;
        RECT  107.982 57.231 108 57.249 ;
        RECT  0 57.231 0.018 57.249 ;
        RECT  107.982 56.691 108 56.709 ;
        RECT  0 56.691 0.018 56.709 ;
        RECT  107.982 56.151 108 56.169 ;
        RECT  0 56.151 0.018 56.169 ;
        RECT  107.982 55.611 108 55.629 ;
        RECT  0 55.611 0.018 55.629 ;
        RECT  107.982 55.071 108 55.089 ;
        RECT  0 55.071 0.018 55.089 ;
        RECT  107.982 54.531 108 54.549 ;
        RECT  0 54.531 0.018 54.549 ;
        RECT  107.982 53.991 108 54.009 ;
        RECT  0 53.991 0.018 54.009 ;
        RECT  107.982 53.451 108 53.469 ;
        RECT  0 53.451 0.018 53.469 ;
        RECT  107.982 52.911 108 52.929 ;
        RECT  0 52.911 0.018 52.929 ;
        RECT  107.982 52.371 108 52.389 ;
        RECT  0 52.371 0.018 52.389 ;
        RECT  107.982 51.831 108 51.849 ;
        RECT  0 51.831 0.018 51.849 ;
        RECT  107.982 51.291 108 51.309 ;
        RECT  0 51.291 0.018 51.309 ;
        RECT  107.982 50.751 108 50.769 ;
        RECT  0 50.751 0.018 50.769 ;
        RECT  107.982 50.211 108 50.229 ;
        RECT  0 50.211 0.018 50.229 ;
        RECT  107.982 49.671 108 49.689 ;
        RECT  0 49.671 0.018 49.689 ;
        RECT  107.982 49.131 108 49.149 ;
        RECT  0 49.131 0.018 49.149 ;
        RECT  107.982 48.591 108 48.609 ;
        RECT  0 48.591 0.018 48.609 ;
        RECT  107.982 48.051 108 48.069 ;
        RECT  0 48.051 0.018 48.069 ;
        RECT  107.982 47.511 108 47.529 ;
        RECT  0 47.511 0.018 47.529 ;
        RECT  107.982 46.971 108 46.989 ;
        RECT  0 46.971 0.018 46.989 ;
        RECT  107.982 46.431 108 46.449 ;
        RECT  0 46.431 0.018 46.449 ;
        RECT  107.982 45.891 108 45.909 ;
        RECT  0 45.891 0.018 45.909 ;
        RECT  107.982 45.351 108 45.369 ;
        RECT  0 45.351 0.018 45.369 ;
        RECT  107.982 44.811 108 44.829 ;
        RECT  0 44.811 0.018 44.829 ;
        RECT  107.982 44.271 108 44.289 ;
        RECT  0 44.271 0.018 44.289 ;
        RECT  107.982 43.731 108 43.749 ;
        RECT  0 43.731 0.018 43.749 ;
        RECT  107.982 43.191 108 43.209 ;
        RECT  0 43.191 0.018 43.209 ;
        RECT  107.982 42.651 108 42.669 ;
        RECT  0 42.651 0.018 42.669 ;
        RECT  107.982 42.111 108 42.129 ;
        RECT  0 42.111 0.018 42.129 ;
        RECT  107.982 41.571 108 41.589 ;
        RECT  0 41.571 0.018 41.589 ;
        RECT  107.982 41.031 108 41.049 ;
        RECT  0 41.031 0.018 41.049 ;
        RECT  107.982 40.491 108 40.509 ;
        RECT  0 40.491 0.018 40.509 ;
        RECT  107.982 39.951 108 39.969 ;
        RECT  0 39.951 0.018 39.969 ;
        RECT  107.982 39.411 108 39.429 ;
        RECT  0 39.411 0.018 39.429 ;
        RECT  107.982 38.871 108 38.889 ;
        RECT  0 38.871 0.018 38.889 ;
        RECT  107.982 38.331 108 38.349 ;
        RECT  0 38.331 0.018 38.349 ;
        RECT  107.982 37.791 108 37.809 ;
        RECT  0 37.791 0.018 37.809 ;
        RECT  107.982 37.251 108 37.269 ;
        RECT  0 37.251 0.018 37.269 ;
        RECT  107.982 36.711 108 36.729 ;
        RECT  0 36.711 0.018 36.729 ;
        RECT  107.982 36.171 108 36.189 ;
        RECT  0 36.171 0.018 36.189 ;
        RECT  107.982 35.631 108 35.649 ;
        RECT  0 35.631 0.018 35.649 ;
        RECT  107.982 35.091 108 35.109 ;
        RECT  0 35.091 0.018 35.109 ;
        RECT  107.982 34.551 108 34.569 ;
        RECT  0 34.551 0.018 34.569 ;
        RECT  107.982 34.011 108 34.029 ;
        RECT  0 34.011 0.018 34.029 ;
        RECT  107.982 33.471 108 33.489 ;
        RECT  0 33.471 0.018 33.489 ;
        RECT  107.982 32.931 108 32.949 ;
        RECT  0 32.931 0.018 32.949 ;
        RECT  107.982 32.391 108 32.409 ;
        RECT  0 32.391 0.018 32.409 ;
        RECT  107.982 31.851 108 31.869 ;
        RECT  0 31.851 0.018 31.869 ;
        RECT  107.982 31.311 108 31.329 ;
        RECT  0 31.311 0.018 31.329 ;
        RECT  107.982 30.771 108 30.789 ;
        RECT  0 30.771 0.018 30.789 ;
        RECT  107.982 30.231 108 30.249 ;
        RECT  0 30.231 0.018 30.249 ;
        RECT  107.982 29.691 108 29.709 ;
        RECT  0 29.691 0.018 29.709 ;
        RECT  107.982 29.151 108 29.169 ;
        RECT  0 29.151 0.018 29.169 ;
        RECT  107.982 28.611 108 28.629 ;
        RECT  0 28.611 0.018 28.629 ;
        RECT  107.982 28.071 108 28.089 ;
        RECT  0 28.071 0.018 28.089 ;
        RECT  107.982 27.531 108 27.549 ;
        RECT  0 27.531 0.018 27.549 ;
        RECT  107.982 26.991 108 27.009 ;
        RECT  0 26.991 0.018 27.009 ;
        RECT  107.982 26.451 108 26.469 ;
        RECT  0 26.451 0.018 26.469 ;
        RECT  107.982 25.911 108 25.929 ;
        RECT  0 25.911 0.018 25.929 ;
        RECT  107.982 25.371 108 25.389 ;
        RECT  0 25.371 0.018 25.389 ;
        RECT  107.982 24.831 108 24.849 ;
        RECT  0 24.831 0.018 24.849 ;
        RECT  107.982 24.291 108 24.309 ;
        RECT  0 24.291 0.018 24.309 ;
        RECT  107.982 23.751 108 23.769 ;
        RECT  0 23.751 0.018 23.769 ;
        RECT  107.982 23.211 108 23.229 ;
        RECT  0 23.211 0.018 23.229 ;
        RECT  107.982 22.671 108 22.689 ;
        RECT  0 22.671 0.018 22.689 ;
        RECT  107.982 22.131 108 22.149 ;
        RECT  0 22.131 0.018 22.149 ;
        RECT  107.982 21.591 108 21.609 ;
        RECT  0 21.591 0.018 21.609 ;
        RECT  107.982 21.051 108 21.069 ;
        RECT  0 21.051 0.018 21.069 ;
        RECT  107.982 20.511 108 20.529 ;
        RECT  0 20.511 0.018 20.529 ;
        RECT  107.982 19.971 108 19.989 ;
        RECT  0 19.971 0.018 19.989 ;
        RECT  107.982 19.431 108 19.449 ;
        RECT  0 19.431 0.018 19.449 ;
        RECT  107.982 18.891 108 18.909 ;
        RECT  0 18.891 0.018 18.909 ;
        RECT  107.982 18.351 108 18.369 ;
        RECT  0 18.351 0.018 18.369 ;
        RECT  107.982 17.811 108 17.829 ;
        RECT  0 17.811 0.018 17.829 ;
        RECT  107.982 17.271 108 17.289 ;
        RECT  0 17.271 0.018 17.289 ;
        RECT  107.982 16.731 108 16.749 ;
        RECT  0 16.731 0.018 16.749 ;
        RECT  107.982 16.191 108 16.209 ;
        RECT  0 16.191 0.018 16.209 ;
        RECT  107.982 15.651 108 15.669 ;
        RECT  0 15.651 0.018 15.669 ;
        RECT  107.982 15.111 108 15.129 ;
        RECT  0 15.111 0.018 15.129 ;
        RECT  107.982 14.571 108 14.589 ;
        RECT  0 14.571 0.018 14.589 ;
        RECT  107.982 14.031 108 14.049 ;
        RECT  0 14.031 0.018 14.049 ;
        RECT  107.982 13.491 108 13.509 ;
        RECT  0 13.491 0.018 13.509 ;
        RECT  107.982 12.951 108 12.969 ;
        RECT  0 12.951 0.018 12.969 ;
        RECT  107.982 12.411 108 12.429 ;
        RECT  0 12.411 0.018 12.429 ;
        RECT  107.982 11.871 108 11.889 ;
        RECT  0 11.871 0.018 11.889 ;
        RECT  107.982 11.331 108 11.349 ;
        RECT  0 11.331 0.018 11.349 ;
        RECT  107.982 10.791 108 10.809 ;
        RECT  0 10.791 0.018 10.809 ;
        RECT  107.982 10.251 108 10.269 ;
        RECT  0 10.251 0.018 10.269 ;
        RECT  107.982 9.711 108 9.729 ;
        RECT  0 9.711 0.018 9.729 ;
        RECT  107.982 9.171 108 9.189 ;
        RECT  0 9.171 0.018 9.189 ;
        RECT  107.982 8.631 108 8.649 ;
        RECT  0 8.631 0.018 8.649 ;
        RECT  107.982 8.091 108 8.109 ;
        RECT  0 8.091 0.018 8.109 ;
        RECT  107.982 7.551 108 7.569 ;
        RECT  0 7.551 0.018 7.569 ;
        RECT  107.982 7.011 108 7.029 ;
        RECT  0 7.011 0.018 7.029 ;
        RECT  107.982 6.471 108 6.489 ;
        RECT  0 6.471 0.018 6.489 ;
        RECT  107.982 5.931 108 5.949 ;
        RECT  0 5.931 0.018 5.949 ;
        RECT  107.982 5.391 108 5.409 ;
        RECT  0 5.391 0.018 5.409 ;
        RECT  107.982 4.851 108 4.869 ;
        RECT  0 4.851 0.018 4.869 ;
        RECT  107.982 4.311 108 4.329 ;
        RECT  0 4.311 0.018 4.329 ;
        RECT  107.982 3.771 108 3.789 ;
        RECT  0 3.771 0.018 3.789 ;
        RECT  107.982 3.231 108 3.249 ;
        RECT  0 3.231 0.018 3.249 ;
        RECT  107.982 2.691 108 2.709 ;
        RECT  0 2.691 0.018 2.709 ;
        RECT  107.982 2.151 108 2.169 ;
        RECT  0 2.151 0.018 2.169 ;
        RECT  107.982 1.611 108 1.629 ;
        RECT  0 1.611 0.018 1.629 ;
        RECT  107.982 1.071 108 1.089 ;
        RECT  0 1.071 0.018 1.089 ;
        RECT  107.982 0.531 108 0.549 ;
        RECT  0 0.531 0.018 0.549 ;
    END
  END VSS
  OBS
    LAYER RVTN ;
     RECT  0 0.54 108 0.675 ;
     RECT  0 0.945 108 1.215 ;
     RECT  0 1.485 108 1.755 ;
     RECT  0 2.025 108 2.295 ;
     RECT  0 2.565 108 2.835 ;
     RECT  0 3.105 108 3.375 ;
     RECT  0 3.645 108 3.915 ;
     RECT  0 4.185 108 4.455 ;
     RECT  0 4.725 108 4.995 ;
     RECT  0 5.265 108 5.535 ;
     RECT  0 5.805 108 6.075 ;
     RECT  0 6.345 108 6.615 ;
     RECT  0 6.885 108 7.155 ;
     RECT  0 7.425 108 7.695 ;
     RECT  0 7.965 108 8.235 ;
     RECT  0 8.505 108 8.775 ;
     RECT  0 9.045 108 9.315 ;
     RECT  0 9.585 108 9.855 ;
     RECT  0 10.125 108 10.395 ;
     RECT  0 10.665 108 10.935 ;
     RECT  0 11.205 108 11.475 ;
     RECT  0 11.745 108 12.015 ;
     RECT  0 12.285 108 12.555 ;
     RECT  0 12.825 108 13.095 ;
     RECT  0 13.365 108 13.635 ;
     RECT  0 13.905 108 14.175 ;
     RECT  0 14.445 108 14.715 ;
     RECT  0 14.985 108 15.255 ;
     RECT  0 15.525 108 15.795 ;
     RECT  0 16.065 108 16.335 ;
     RECT  0 16.605 108 16.875 ;
     RECT  0 17.145 108 17.415 ;
     RECT  0 17.685 108 17.955 ;
     RECT  0 18.225 108 18.495 ;
     RECT  0 18.765 108 19.035 ;
     RECT  0 19.305 108 19.575 ;
     RECT  0 19.845 108 20.115 ;
     RECT  0 20.385 108 20.655 ;
     RECT  0 20.925 108 21.195 ;
     RECT  0 21.465 108 21.735 ;
     RECT  0 22.005 108 22.275 ;
     RECT  0 22.545 108 22.815 ;
     RECT  0 23.085 108 23.355 ;
     RECT  0 23.625 108 23.895 ;
     RECT  0 24.165 108 24.435 ;
     RECT  0 24.705 108 24.975 ;
     RECT  0 25.245 108 25.515 ;
     RECT  0 25.785 108 26.055 ;
     RECT  0 26.325 108 26.595 ;
     RECT  0 26.865 108 27.135 ;
     RECT  0 27.405 108 27.675 ;
     RECT  0 27.945 108 28.215 ;
     RECT  0 28.485 108 28.755 ;
     RECT  0 29.025 108 29.295 ;
     RECT  0 29.565 108 29.835 ;
     RECT  0 30.105 108 30.375 ;
     RECT  0 30.645 108 30.915 ;
     RECT  0 31.185 108 31.455 ;
     RECT  0 31.725 108 31.995 ;
     RECT  0 32.265 108 32.535 ;
     RECT  0 32.805 108 33.075 ;
     RECT  0 33.345 108 33.615 ;
     RECT  0 33.885 108 34.155 ;
     RECT  0 34.425 108 34.695 ;
     RECT  0 34.965 108 35.235 ;
     RECT  0 35.505 108 35.775 ;
     RECT  0 36.045 108 36.315 ;
     RECT  0 36.585 108 36.855 ;
     RECT  0 37.125 108 37.395 ;
     RECT  0 37.665 108 37.935 ;
     RECT  0 38.205 108 38.475 ;
     RECT  0 38.745 108 39.015 ;
     RECT  0 39.285 108 39.555 ;
     RECT  0 39.825 108 40.095 ;
     RECT  0 40.365 108 40.635 ;
     RECT  0 40.905 108 41.175 ;
     RECT  0 41.445 108 41.715 ;
     RECT  0 41.985 108 42.255 ;
     RECT  0 42.525 108 42.795 ;
     RECT  0 43.065 108 43.335 ;
     RECT  0 43.605 108 43.875 ;
     RECT  0 44.145 108 44.415 ;
     RECT  0 44.685 108 44.955 ;
     RECT  0 45.225 108 45.495 ;
     RECT  0 45.765 108 46.035 ;
     RECT  0 46.305 108 46.575 ;
     RECT  0 46.845 108 47.115 ;
     RECT  0 47.385 108 47.655 ;
     RECT  0 47.925 108 48.195 ;
     RECT  0 48.465 108 48.735 ;
     RECT  0 49.005 108 49.275 ;
     RECT  0 49.545 108 49.815 ;
     RECT  0 50.085 108 50.355 ;
     RECT  0 50.625 108 50.895 ;
     RECT  0 51.165 108 51.435 ;
     RECT  0 51.705 108 51.975 ;
     RECT  0 52.245 108 52.515 ;
     RECT  0 52.785 108 53.055 ;
     RECT  0 53.325 108 53.595 ;
     RECT  0 53.865 108 54.135 ;
     RECT  0 54.405 108 54.675 ;
     RECT  0 54.945 108 55.215 ;
     RECT  0 55.485 108 55.755 ;
     RECT  0 56.025 108 56.295 ;
     RECT  0 56.565 108 56.835 ;
     RECT  0 57.105 108 57.375 ;
     RECT  0 57.645 108 57.915 ;
     RECT  0 58.185 108 58.455 ;
     RECT  0 58.725 108 58.995 ;
     RECT  0 59.265 108 59.535 ;
     RECT  0 59.805 108 60.075 ;
     RECT  0 60.345 108 60.615 ;
     RECT  0 60.885 108 61.155 ;
     RECT  0 61.425 108 61.695 ;
     RECT  0 61.965 108 62.235 ;
     RECT  0 62.505 108 62.775 ;
     RECT  0 63.045 108 63.315 ;
     RECT  0 63.585 108 63.855 ;
     RECT  0 64.125 108 64.395 ;
     RECT  0 64.665 108 64.935 ;
     RECT  0 65.205 108 65.475 ;
     RECT  0 65.745 108 66.015 ;
     RECT  0 66.285 108 66.555 ;
     RECT  0 66.825 108 67.095 ;
     RECT  0 67.365 108 67.635 ;
     RECT  0 67.905 108 68.175 ;
     RECT  0 68.445 108 68.715 ;
     RECT  0 68.985 108 69.255 ;
     RECT  0 69.525 108 69.795 ;
     RECT  0 70.065 108 70.335 ;
     RECT  0 70.605 108 70.875 ;
     RECT  0 71.145 108 71.415 ;
     RECT  0 71.685 108 71.955 ;
     RECT  0 72.225 108 72.495 ;
     RECT  0 72.765 108 73.035 ;
     RECT  0 73.305 108 73.575 ;
     RECT  0 73.845 108 74.115 ;
     RECT  0 74.385 108 74.655 ;
     RECT  0 74.925 108 75.195 ;
     RECT  0 75.465 108 75.735 ;
     RECT  0 76.005 108 76.275 ;
     RECT  0 76.545 108 76.815 ;
     RECT  0 77.085 108 77.355 ;
     RECT  0 77.625 108 77.895 ;
     RECT  0 78.165 108 78.435 ;
     RECT  0 78.705 108 78.975 ;
     RECT  0 79.245 108 79.515 ;
     RECT  0 79.785 108 80.055 ;
     RECT  0 80.325 108 80.595 ;
     RECT  0 80.865 108 81.135 ;
     RECT  0 81.405 108 81.675 ;
     RECT  0 81.945 108 82.215 ;
     RECT  0 82.485 108 82.755 ;
     RECT  0 83.025 108 83.295 ;
     RECT  0 83.565 108 83.835 ;
     RECT  0 84.105 108 84.375 ;
     RECT  0 84.645 108 84.915 ;
     RECT  0 85.185 108 85.455 ;
     RECT  0 85.725 108 85.995 ;
     RECT  0 86.265 108 86.535 ;
     RECT  0 86.805 108 87.075 ;
     RECT  0 87.345 108 87.615 ;
     RECT  0 87.885 108 88.155 ;
     RECT  0 88.425 108 88.695 ;
     RECT  0 88.965 108 89.235 ;
     RECT  0 89.505 108 89.775 ;
     RECT  0 90.045 108 90.315 ;
     RECT  0 90.585 108 90.855 ;
     RECT  0 91.125 108 91.395 ;
     RECT  0 91.665 108 91.935 ;
     RECT  0 92.205 108 92.475 ;
     RECT  0 92.745 108 93.015 ;
     RECT  0 93.285 108 93.555 ;
     RECT  0 93.825 108 94.095 ;
     RECT  0 94.365 108 94.635 ;
     RECT  0 94.905 108 95.175 ;
     RECT  0 95.445 108 95.715 ;
     RECT  0 95.985 108 96.255 ;
     RECT  0 96.525 108 96.795 ;
     RECT  0 97.065 108 97.335 ;
     RECT  0 97.605 108 97.875 ;
     RECT  0 98.145 108 98.415 ;
     RECT  0 98.685 108 98.955 ;
     RECT  0 99.225 108 99.495 ;
     RECT  0 99.765 108 100.035 ;
     RECT  0 100.305 108 100.575 ;
     RECT  0 100.845 108 101.115 ;
     RECT  0 101.385 108 101.655 ;
     RECT  0 101.925 108 102.195 ;
     RECT  0 102.465 108 102.735 ;
     RECT  0 103.005 108 103.275 ;
     RECT  0 103.545 108 103.815 ;
     RECT  0 104.085 108 104.355 ;
     RECT  0 104.625 108 104.895 ;
     RECT  0 105.165 108 105.435 ;
     RECT  0 105.705 108 105.975 ;
     RECT  0 106.245 108 106.515 ;
     RECT  0 106.785 108 107.055 ;
     RECT  0 107.325 108 107.595 ;
     RECT  0 107.865 108 108.135 ;
     RECT  0 108.405 108 108.675 ;
     RECT  0 108.945 108 109.215 ;
     RECT  0 109.485 108 109.755 ;
     RECT  0 110.025 108 110.295 ;
     RECT  0 110.565 108 110.835 ;
     RECT  0 111.105 108 111.375 ;
     RECT  0 111.645 108 111.915 ;
     RECT  0 112.185 108 112.455 ;
     RECT  0 112.725 108 112.995 ;
     RECT  0 113.265 108 113.535 ;
     RECT  0 113.805 108 114.075 ;
     RECT  0 114.345 108 114.615 ;
     RECT  0 114.885 108 115.155 ;
     RECT  0 115.425 108 115.695 ;
     RECT  0 115.965 108 116.235 ;
     RECT  0 116.505 108 116.775 ;
     RECT  0 117.045 108 117.315 ;
     RECT  0 117.585 108 117.855 ;
     RECT  0 118.125 108 118.395 ;
     RECT  0 118.665 108 118.935 ;
     RECT  0 119.205 108 119.475 ;
     RECT  0 119.745 108 120.015 ;
     RECT  0 120.285 108 120.555 ;
     RECT  0 120.825 108 121.095 ;
     RECT  0 121.365 108 121.635 ;
     RECT  0 121.905 108 122.175 ;
     RECT  0 122.445 108 122.715 ;
     RECT  0 122.985 108 123.255 ;
     RECT  0 123.525 108 123.795 ;
     RECT  0 124.065 108 124.335 ;
     RECT  0 124.605 108 124.875 ;
     RECT  0 125.145 108 125.415 ;
     RECT  0 125.685 108 125.955 ;
     RECT  0 126.225 108 126.495 ;
     RECT  0 126.765 108 127.035 ;
     RECT  0 127.305 108 127.575 ;
     RECT  0 127.845 108 128.115 ;
     RECT  0 128.385 108 128.655 ;
     RECT  0 128.925 108 129.06 ;
    LAYER RVTP ;
     RECT  0 0.675 108 0.945 ;
     RECT  0 1.215 108 1.485 ;
     RECT  0 1.755 108 2.025 ;
     RECT  0 2.295 108 2.565 ;
     RECT  0 2.835 108 3.105 ;
     RECT  0 3.375 108 3.645 ;
     RECT  0 3.915 108 4.185 ;
     RECT  0 4.455 108 4.725 ;
     RECT  0 4.995 108 5.265 ;
     RECT  0 5.535 108 5.805 ;
     RECT  0 6.075 108 6.345 ;
     RECT  0 6.615 108 6.885 ;
     RECT  0 7.155 108 7.425 ;
     RECT  0 7.695 108 7.965 ;
     RECT  0 8.235 108 8.505 ;
     RECT  0 8.775 108 9.045 ;
     RECT  0 9.315 108 9.585 ;
     RECT  0 9.855 108 10.125 ;
     RECT  0 10.395 108 10.665 ;
     RECT  0 10.935 108 11.205 ;
     RECT  0 11.475 108 11.745 ;
     RECT  0 12.015 108 12.285 ;
     RECT  0 12.555 108 12.825 ;
     RECT  0 13.095 108 13.365 ;
     RECT  0 13.635 108 13.905 ;
     RECT  0 14.175 108 14.445 ;
     RECT  0 14.715 108 14.985 ;
     RECT  0 15.255 108 15.525 ;
     RECT  0 15.795 108 16.065 ;
     RECT  0 16.335 108 16.605 ;
     RECT  0 16.875 108 17.145 ;
     RECT  0 17.415 108 17.685 ;
     RECT  0 17.955 108 18.225 ;
     RECT  0 18.495 108 18.765 ;
     RECT  0 19.035 108 19.305 ;
     RECT  0 19.575 108 19.845 ;
     RECT  0 20.115 108 20.385 ;
     RECT  0 20.655 108 20.925 ;
     RECT  0 21.195 108 21.465 ;
     RECT  0 21.735 108 22.005 ;
     RECT  0 22.275 108 22.545 ;
     RECT  0 22.815 108 23.085 ;
     RECT  0 23.355 108 23.625 ;
     RECT  0 23.895 108 24.165 ;
     RECT  0 24.435 108 24.705 ;
     RECT  0 24.975 108 25.245 ;
     RECT  0 25.515 108 25.785 ;
     RECT  0 26.055 108 26.325 ;
     RECT  0 26.595 108 26.865 ;
     RECT  0 27.135 108 27.405 ;
     RECT  0 27.675 108 27.945 ;
     RECT  0 28.215 108 28.485 ;
     RECT  0 28.755 108 29.025 ;
     RECT  0 29.295 108 29.565 ;
     RECT  0 29.835 108 30.105 ;
     RECT  0 30.375 108 30.645 ;
     RECT  0 30.915 108 31.185 ;
     RECT  0 31.455 108 31.725 ;
     RECT  0 31.995 108 32.265 ;
     RECT  0 32.535 108 32.805 ;
     RECT  0 33.075 108 33.345 ;
     RECT  0 33.615 108 33.885 ;
     RECT  0 34.155 108 34.425 ;
     RECT  0 34.695 108 34.965 ;
     RECT  0 35.235 108 35.505 ;
     RECT  0 35.775 108 36.045 ;
     RECT  0 36.315 108 36.585 ;
     RECT  0 36.855 108 37.125 ;
     RECT  0 37.395 108 37.665 ;
     RECT  0 37.935 108 38.205 ;
     RECT  0 38.475 108 38.745 ;
     RECT  0 39.015 108 39.285 ;
     RECT  0 39.555 108 39.825 ;
     RECT  0 40.095 108 40.365 ;
     RECT  0 40.635 108 40.905 ;
     RECT  0 41.175 108 41.445 ;
     RECT  0 41.715 108 41.985 ;
     RECT  0 42.255 108 42.525 ;
     RECT  0 42.795 108 43.065 ;
     RECT  0 43.335 108 43.605 ;
     RECT  0 43.875 108 44.145 ;
     RECT  0 44.415 108 44.685 ;
     RECT  0 44.955 108 45.225 ;
     RECT  0 45.495 108 45.765 ;
     RECT  0 46.035 108 46.305 ;
     RECT  0 46.575 108 46.845 ;
     RECT  0 47.115 108 47.385 ;
     RECT  0 47.655 108 47.925 ;
     RECT  0 48.195 108 48.465 ;
     RECT  0 48.735 108 49.005 ;
     RECT  0 49.275 108 49.545 ;
     RECT  0 49.815 108 50.085 ;
     RECT  0 50.355 108 50.625 ;
     RECT  0 50.895 108 51.165 ;
     RECT  0 51.435 108 51.705 ;
     RECT  0 51.975 108 52.245 ;
     RECT  0 52.515 108 52.785 ;
     RECT  0 53.055 108 53.325 ;
     RECT  0 53.595 108 53.865 ;
     RECT  0 54.135 108 54.405 ;
     RECT  0 54.675 108 54.945 ;
     RECT  0 55.215 108 55.485 ;
     RECT  0 55.755 108 56.025 ;
     RECT  0 56.295 108 56.565 ;
     RECT  0 56.835 108 57.105 ;
     RECT  0 57.375 108 57.645 ;
     RECT  0 57.915 108 58.185 ;
     RECT  0 58.455 108 58.725 ;
     RECT  0 58.995 108 59.265 ;
     RECT  0 59.535 108 59.805 ;
     RECT  0 60.075 108 60.345 ;
     RECT  0 60.615 108 60.885 ;
     RECT  0 61.155 108 61.425 ;
     RECT  0 61.695 108 61.965 ;
     RECT  0 62.235 108 62.505 ;
     RECT  0 62.775 108 63.045 ;
     RECT  0 63.315 108 63.585 ;
     RECT  0 63.855 108 64.125 ;
     RECT  0 64.395 108 64.665 ;
     RECT  0 64.935 108 65.205 ;
     RECT  0 65.475 108 65.745 ;
     RECT  0 66.015 108 66.285 ;
     RECT  0 66.555 108 66.825 ;
     RECT  0 67.095 108 67.365 ;
     RECT  0 67.635 108 67.905 ;
     RECT  0 68.175 108 68.445 ;
     RECT  0 68.715 108 68.985 ;
     RECT  0 69.255 108 69.525 ;
     RECT  0 69.795 108 70.065 ;
     RECT  0 70.335 108 70.605 ;
     RECT  0 70.875 108 71.145 ;
     RECT  0 71.415 108 71.685 ;
     RECT  0 71.955 108 72.225 ;
     RECT  0 72.495 108 72.765 ;
     RECT  0 73.035 108 73.305 ;
     RECT  0 73.575 108 73.845 ;
     RECT  0 74.115 108 74.385 ;
     RECT  0 74.655 108 74.925 ;
     RECT  0 75.195 108 75.465 ;
     RECT  0 75.735 108 76.005 ;
     RECT  0 76.275 108 76.545 ;
     RECT  0 76.815 108 77.085 ;
     RECT  0 77.355 108 77.625 ;
     RECT  0 77.895 108 78.165 ;
     RECT  0 78.435 108 78.705 ;
     RECT  0 78.975 108 79.245 ;
     RECT  0 79.515 108 79.785 ;
     RECT  0 80.055 108 80.325 ;
     RECT  0 80.595 108 80.865 ;
     RECT  0 81.135 108 81.405 ;
     RECT  0 81.675 108 81.945 ;
     RECT  0 82.215 108 82.485 ;
     RECT  0 82.755 108 83.025 ;
     RECT  0 83.295 108 83.565 ;
     RECT  0 83.835 108 84.105 ;
     RECT  0 84.375 108 84.645 ;
     RECT  0 84.915 108 85.185 ;
     RECT  0 85.455 108 85.725 ;
     RECT  0 85.995 108 86.265 ;
     RECT  0 86.535 108 86.805 ;
     RECT  0 87.075 108 87.345 ;
     RECT  0 87.615 108 87.885 ;
     RECT  0 88.155 108 88.425 ;
     RECT  0 88.695 108 88.965 ;
     RECT  0 89.235 108 89.505 ;
     RECT  0 89.775 108 90.045 ;
     RECT  0 90.315 108 90.585 ;
     RECT  0 90.855 108 91.125 ;
     RECT  0 91.395 108 91.665 ;
     RECT  0 91.935 108 92.205 ;
     RECT  0 92.475 108 92.745 ;
     RECT  0 93.015 108 93.285 ;
     RECT  0 93.555 108 93.825 ;
     RECT  0 94.095 108 94.365 ;
     RECT  0 94.635 108 94.905 ;
     RECT  0 95.175 108 95.445 ;
     RECT  0 95.715 108 95.985 ;
     RECT  0 96.255 108 96.525 ;
     RECT  0 96.795 108 97.065 ;
     RECT  0 97.335 108 97.605 ;
     RECT  0 97.875 108 98.145 ;
     RECT  0 98.415 108 98.685 ;
     RECT  0 98.955 108 99.225 ;
     RECT  0 99.495 108 99.765 ;
     RECT  0 100.035 108 100.305 ;
     RECT  0 100.575 108 100.845 ;
     RECT  0 101.115 108 101.385 ;
     RECT  0 101.655 108 101.925 ;
     RECT  0 102.195 108 102.465 ;
     RECT  0 102.735 108 103.005 ;
     RECT  0 103.275 108 103.545 ;
     RECT  0 103.815 108 104.085 ;
     RECT  0 104.355 108 104.625 ;
     RECT  0 104.895 108 105.165 ;
     RECT  0 105.435 108 105.705 ;
     RECT  0 105.975 108 106.245 ;
     RECT  0 106.515 108 106.785 ;
     RECT  0 107.055 108 107.325 ;
     RECT  0 107.595 108 107.865 ;
     RECT  0 108.135 108 108.405 ;
     RECT  0 108.675 108 108.945 ;
     RECT  0 109.215 108 109.485 ;
     RECT  0 109.755 108 110.025 ;
     RECT  0 110.295 108 110.565 ;
     RECT  0 110.835 108 111.105 ;
     RECT  0 111.375 108 111.645 ;
     RECT  0 111.915 108 112.185 ;
     RECT  0 112.455 108 112.725 ;
     RECT  0 112.995 108 113.265 ;
     RECT  0 113.535 108 113.805 ;
     RECT  0 114.075 108 114.345 ;
     RECT  0 114.615 108 114.885 ;
     RECT  0 115.155 108 115.425 ;
     RECT  0 115.695 108 115.965 ;
     RECT  0 116.235 108 116.505 ;
     RECT  0 116.775 108 117.045 ;
     RECT  0 117.315 108 117.585 ;
     RECT  0 117.855 108 118.125 ;
     RECT  0 118.395 108 118.665 ;
     RECT  0 118.935 108 119.205 ;
     RECT  0 119.475 108 119.745 ;
     RECT  0 120.015 108 120.285 ;
     RECT  0 120.555 108 120.825 ;
     RECT  0 121.095 108 121.365 ;
     RECT  0 121.635 108 121.905 ;
     RECT  0 122.175 108 122.445 ;
     RECT  0 122.715 108 122.985 ;
     RECT  0 123.255 108 123.525 ;
     RECT  0 123.795 108 124.065 ;
     RECT  0 124.335 108 124.605 ;
     RECT  0 124.875 108 125.145 ;
     RECT  0 125.415 108 125.685 ;
     RECT  0 125.955 108 126.225 ;
     RECT  0 126.495 108 126.765 ;
     RECT  0 127.035 108 127.305 ;
     RECT  0 127.575 108 127.845 ;
     RECT  0 128.115 108 128.385 ;
     RECT  0 128.655 108 128.925 ;
    LAYER M1 ;
     RECT  0 0.531 108 129.069 ;
    LAYER M2 ;
     RECT  0 0.531 5.755 129.069 ;
     RECT  5.755 0.45 5.999 129.069 ;
     RECT  5.999 0.531 18.859 129.069 ;
     RECT  18.859 0.486 19.031 129.069 ;
     RECT  19.031 0.531 20.083 129.069 ;
     RECT  20.083 0.414 20.183 129.069 ;
     RECT  20.183 0.531 21.199 129.069 ;
     RECT  21.199 0.486 21.631 129.069 ;
     RECT  21.631 0.306 22.099 129.069 ;
     RECT  22.099 0.036 27.535 129.069 ;
     RECT  27.535 0.036 30.227 129.114 ;
     RECT  30.227 0.036 30.299 129.069 ;
     RECT  30.299 0.072 37.139 129.069 ;
     RECT  37.139 0.414 37.319 129.069 ;
     RECT  37.319 0.486 37.759 129.069 ;
     RECT  37.759 0.486 38.759 129.114 ;
     RECT  38.759 0.531 39.371 129.114 ;
     RECT  39.371 0.531 42.295 129.069 ;
     RECT  42.295 0.531 43.375 129.114 ;
     RECT  43.375 0.531 43.475 129.15 ;
     RECT  43.475 0.531 43.943 129.114 ;
     RECT  43.943 0.531 48.415 129.069 ;
     RECT  48.415 0.531 48.631 129.114 ;
     RECT  48.631 0.531 48.875 129.15 ;
     RECT  48.875 0.531 49.631 129.114 ;
     RECT  49.631 0.531 108 129.069 ;
    LAYER M3 ;
     RECT  27.972 0.043 27.99 0.067 ;
     RECT  29.232 0.043 29.25 0.067 ;
     RECT  23.94 0.067 23.958 0.091 ;
     RECT  26.1 0.043 26.118 0.091 ;
     RECT  27.648 0.067 27.99 0.091 ;
     RECT  28.944 0.067 29.25 0.091 ;
     RECT  36.216 0.043 36.234 0.091 ;
     RECT  30.276 0.031 30.294 0.103 ;
     RECT  18.972 0.091 18.99 0.139 ;
     RECT  22.104 0.031 22.122 0.139 ;
     RECT  23.292 0.091 23.958 0.139 ;
     RECT  27.648 0.091 29.43 0.139 ;
     RECT  30.276 0.103 30.726 0.139 ;
     RECT  35.712 0.091 36.234 0.139 ;
     RECT  37.116 0.067 37.134 0.139 ;
     RECT  27.144 0.139 29.43 0.175 ;
     RECT  30.276 0.139 31.302 0.175 ;
     RECT  15.624 0.139 15.642 0.187 ;
     RECT  34.308 0.139 34.326 0.187 ;
     RECT  35.712 0.139 37.134 0.187 ;
     RECT  21.6 0.139 22.122 0.211 ;
     RECT  27.144 0.175 31.302 0.211 ;
     RECT  11.016 0.187 11.034 0.235 ;
     RECT  15.624 0.187 15.966 0.235 ;
     RECT  17.244 0.187 17.262 0.235 ;
     RECT  18 0.187 18.018 0.235 ;
     RECT  23.292 0.139 24.282 0.235 ;
     RECT  25.92 0.091 26.118 0.235 ;
     RECT  26.928 0.211 31.302 0.235 ;
     RECT  5.796 0.187 6.282 0.283 ;
     RECT  11.016 0.235 11.214 0.283 ;
     RECT  15.624 0.235 17.262 0.283 ;
     RECT  18 0.235 18.09 0.283 ;
     RECT  5.508 0.283 6.642 0.331 ;
     RECT  7.38 0.283 8.046 0.331 ;
     RECT  8.964 0.283 9.558 0.331 ;
     RECT  10.512 0.283 11.214 0.331 ;
     RECT  11.988 0.283 13.158 0.331 ;
     RECT  14.544 0.283 18.09 0.331 ;
     RECT  18.9 0.139 18.99 0.331 ;
     RECT  21.6 0.211 22.302 0.331 ;
     RECT  23.076 0.235 24.282 0.331 ;
     RECT  23.076 0.331 24.534 0.373 ;
     RECT  25.452 0.235 31.302 0.373 ;
     RECT  5.508 0.331 18.09 0.379 ;
     RECT  20.304 0.331 20.502 0.379 ;
     RECT  21.564 0.331 22.302 0.379 ;
     RECT  23.076 0.373 31.302 0.379 ;
     RECT  21.564 0.379 31.302 0.409 ;
     RECT  34.308 0.187 37.134 0.409 ;
     RECT  18.9 0.331 19.314 0.427 ;
     RECT  5.364 0.379 18.09 0.475 ;
     RECT  18.864 0.427 19.314 0.475 ;
     RECT  20.088 0.379 20.502 0.475 ;
     RECT  5.364 0.475 20.502 0.481 ;
     RECT  21.564 0.409 31.626 0.481 ;
     RECT  5.364 0.481 31.626 0.523 ;
     RECT  33.12 0.331 33.138 0.523 ;
     RECT  38.736 0.481 38.754 0.523 ;
     RECT  32.655 0.523 33.138 0.571 ;
     RECT  34.308 0.409 37.314 0.571 ;
     RECT  38.055 0.523 38.754 0.571 ;
     RECT  43.455 0.523 43.545 0.571 ;
     RECT  38.055 0.571 38.79 0.607 ;
     RECT  32.508 0.571 37.314 0.619 ;
     RECT  5.292 0.523 31.626 0.679 ;
     RECT  32.472 0.619 37.314 0.679 ;
     RECT  42.264 0.643 42.282 0.679 ;
     RECT  0.255 0.523 0.345 0.793 ;
     RECT  43.344 0.571 43.545 0.793 ;
     RECT  48.855 0.523 48.945 0.793 ;
     RECT  54.255 0.523 54.345 0.793 ;
     RECT  59.655 0.523 59.745 0.793 ;
     RECT  65.055 0.523 65.145 0.793 ;
     RECT  70.455 0.523 70.545 0.793 ;
     RECT  75.855 0.523 75.945 0.793 ;
     RECT  81.255 0.523 81.345 0.793 ;
     RECT  86.655 0.523 86.745 0.793 ;
     RECT  92.055 0.523 92.145 0.793 ;
     RECT  97.455 0.523 97.545 0.793 ;
     RECT  102.855 0.523 102.945 0.793 ;
     RECT  5.292 0.679 37.314 0.811 ;
     RECT  38.055 0.607 39.366 0.811 ;
     RECT  42.264 0.679 42.534 0.841 ;
     RECT  43.344 0.793 43.737 0.841 ;
     RECT  40.86 0.751 40.878 0.913 ;
     RECT  42.264 0.841 43.737 0.955 ;
     RECT  42.264 0.955 43.794 0.985 ;
     RECT  40.248 0.913 40.878 1.003 ;
     RECT  40.248 1.003 40.914 1.183 ;
     RECT  5.292 0.811 39.366 1.291 ;
     RECT  40.104 1.183 40.914 1.291 ;
     RECT  5.292 1.291 40.914 1.723 ;
     RECT  41.652 0.985 43.794 1.723 ;
     RECT  44.568 1.489 44.586 1.723 ;
     RECT  45.828 0.907 45.846 1.723 ;
     RECT  5.292 1.723 43.794 1.759 ;
     RECT  44.568 1.723 45.846 1.759 ;
     RECT  5.292 1.759 45.846 2.101 ;
     RECT  5.292 2.101 46.026 2.191 ;
     RECT  5.292 2.191 46.314 5.707 ;
     RECT  5.22 5.707 46.314 6.859 ;
     RECT  5.004 6.859 46.314 7.385 ;
     RECT  5.22 7.385 46.314 7.655 ;
     RECT  5.364 7.655 46.314 9.691 ;
     RECT  5.076 9.691 46.314 9.815 ;
     RECT  5.364 9.815 46.314 13.099 ;
     RECT  4.896 13.099 46.314 18.725 ;
     RECT  5.004 18.725 46.314 37.085 ;
     RECT  47.196 43.681 47.214 43.835 ;
     RECT  47.304 43.951 47.358 44.069 ;
     RECT  47.304 44.069 47.322 47.281 ;
     RECT  5.655 37.085 46.314 47.731 ;
     RECT  47.232 47.281 47.322 47.731 ;
     RECT  5.655 47.731 47.322 47.885 ;
     RECT  47.124 47.885 47.322 48.119 ;
     RECT  47.232 48.119 47.322 48.271 ;
     RECT  5.655 47.885 46.314 51.089 ;
     RECT  47.232 48.271 47.358 51.241 ;
     RECT  5.655 51.089 46.278 52.051 ;
     RECT  47.124 51.241 47.358 52.051 ;
     RECT  5.655 52.051 47.358 52.411 ;
     RECT  5.655 52.411 47.682 53.249 ;
     RECT  47.232 53.249 47.682 53.401 ;
     RECT  50.472 47.461 50.49 54.103 ;
     RECT  51.552 45.229 51.57 54.103 ;
     RECT  5.655 53.249 46.494 54.751 ;
     RECT  47.232 53.401 47.862 54.751 ;
     RECT  5.655 54.751 47.862 58.109 ;
     RECT  6.84 58.109 47.862 60.151 ;
     RECT  48.855 0.793 49.137 60.151 ;
     RECT  6.84 60.151 49.137 60.809 ;
     RECT  50.472 54.103 51.57 63.553 ;
     RECT  7.056 60.809 49.137 64.049 ;
     RECT  7.488 64.049 49.137 65.563 ;
     RECT  7.416 65.563 49.137 65.939 ;
     RECT  50.292 63.553 51.57 66.829 ;
     RECT  7.488 65.939 49.137 68.251 ;
     RECT  7.344 68.251 49.137 68.369 ;
     RECT  7.524 68.369 49.137 73.229 ;
     RECT  7.848 73.229 49.137 73.805 ;
     RECT  7.884 73.805 49.137 87.151 ;
     RECT  7.884 87.151 49.23 88.501 ;
     RECT  49.968 66.829 51.57 88.501 ;
     RECT  7.884 88.501 51.57 97.529 ;
     RECT  7.884 97.529 11.337 99.841 ;
     RECT  12.06 97.529 51.57 99.841 ;
     RECT  7.884 99.841 51.57 101.075 ;
     RECT  7.884 101.075 11.337 103.739 ;
     RECT  8.208 103.739 11.337 104.161 ;
     RECT  12.06 101.075 51.57 104.161 ;
     RECT  8.208 104.161 51.57 105.395 ;
     RECT  8.208 105.395 11.337 106.475 ;
     RECT  8.388 106.475 11.337 109.049 ;
     RECT  8.892 109.049 11.337 112.531 ;
     RECT  12.06 105.395 51.57 112.531 ;
     RECT  8.892 112.531 51.57 113.459 ;
     RECT  9.288 113.459 51.57 115.889 ;
     RECT  9.288 115.889 11.337 116.671 ;
     RECT  12.06 115.889 51.57 116.671 ;
     RECT  9.288 116.671 51.57 118.193 ;
     RECT  52.992 113.503 53.01 119.939 ;
     RECT  54.255 0.793 54.537 119.947 ;
     RECT  54.255 119.947 54.738 120.047 ;
     RECT  11.055 118.193 51.57 121.199 ;
     RECT  52.74 121.171 52.758 121.261 ;
     RECT  52.56 121.261 53.082 121.369 ;
     RECT  54.255 120.047 54.537 121.369 ;
     RECT  52.56 121.369 54.537 121.397 ;
     RECT  55.296 121.261 55.314 122.071 ;
     RECT  55.296 122.071 55.818 122.099 ;
     RECT  11.055 121.199 50.922 122.819 ;
     RECT  53.568 121.397 54.537 123.251 ;
     RECT  65.055 0.793 65.337 123.295 ;
     RECT  63.972 119.947 63.99 123.421 ;
     RECT  55.8 122.099 55.818 123.449 ;
     RECT  63.792 123.421 63.99 123.457 ;
     RECT  64.98 123.295 65.337 123.457 ;
     RECT  63.792 123.457 65.337 123.521 ;
     RECT  11.055 122.819 12.618 123.719 ;
     RECT  63.864 123.521 65.337 123.863 ;
     RECT  64.008 123.863 65.337 124.069 ;
     RECT  13.68 122.819 50.922 124.259 ;
     RECT  64.008 124.069 65.502 124.295 ;
     RECT  14.616 124.259 50.922 124.529 ;
     RECT  64.548 124.295 65.502 124.529 ;
     RECT  53.136 123.331 53.154 124.565 ;
     RECT  13.68 124.259 13.698 124.681 ;
     RECT  11.055 123.719 12.33 124.709 ;
     RECT  65.055 124.529 65.502 124.799 ;
     RECT  81.255 0.793 81.537 124.807 ;
     RECT  9.288 118.193 10.242 125.041 ;
     RECT  11.055 124.709 12.078 125.041 ;
     RECT  9.288 125.041 12.078 125.213 ;
     RECT  13.14 124.681 13.698 125.221 ;
     RECT  14.616 124.529 15.138 125.221 ;
     RECT  13.14 125.221 15.138 125.339 ;
     RECT  16.056 124.529 50.922 125.383 ;
     RECT  14.616 125.339 15.138 125.411 ;
     RECT  11.055 125.213 12.078 125.609 ;
     RECT  15.984 125.383 50.922 125.681 ;
     RECT  9.288 125.213 10.242 125.915 ;
     RECT  10.224 125.915 10.242 126.031 ;
     RECT  11.055 125.609 11.337 126.031 ;
     RECT  13.14 125.339 13.698 126.185 ;
     RECT  9.288 125.915 9.306 126.257 ;
     RECT  21.312 125.681 50.922 126.301 ;
     RECT  51.912 124.681 51.93 126.301 ;
     RECT  13.356 126.185 13.698 126.455 ;
     RECT  21.312 126.301 51.93 126.455 ;
     RECT  13.68 126.455 13.698 126.499 ;
     RECT  15.984 125.681 20.574 126.535 ;
     RECT  21.312 126.455 50.922 126.535 ;
     RECT  10.224 126.031 11.337 126.689 ;
     RECT  11.055 126.689 11.337 126.841 ;
     RECT  15.984 126.535 50.922 126.841 ;
     RECT  13.68 126.499 13.878 126.959 ;
     RECT  14.616 125.411 14.634 127.111 ;
     RECT  15.408 126.841 50.922 127.111 ;
     RECT  11.055 126.841 11.502 127.201 ;
     RECT  14.22 127.111 50.922 127.201 ;
     RECT  51.876 126.455 51.93 127.201 ;
     RECT  14.22 127.201 51.93 127.265 ;
     RECT  11.055 127.201 11.682 127.301 ;
     RECT  14.22 127.265 14.886 127.409 ;
     RECT  14.22 127.409 14.778 127.499 ;
     RECT  15.984 127.265 51.93 127.499 ;
     RECT  14.22 127.499 14.634 127.535 ;
     RECT  15.984 127.499 51.354 127.535 ;
     RECT  52.74 125.221 52.758 127.651 ;
     RECT  15.984 127.535 51.318 127.679 ;
     RECT  14.616 127.535 14.634 127.805 ;
     RECT  16.416 127.679 51.318 127.805 ;
     RECT  52.74 127.651 52.938 127.813 ;
     RECT  52.56 127.813 52.938 128.039 ;
     RECT  16.455 127.805 51.318 128.075 ;
     RECT  52.92 128.039 52.938 128.111 ;
     RECT  18.252 128.075 51.318 128.489 ;
     RECT  18.252 128.489 18.99 128.615 ;
     RECT  19.872 128.489 50.814 128.615 ;
     RECT  19.872 128.615 20.574 128.669 ;
     RECT  23.94 128.615 50.814 128.687 ;
     RECT  20.556 128.669 20.574 128.717 ;
     RECT  23.94 128.687 50.742 128.723 ;
     RECT  0.255 0.793 0.537 128.807 ;
     RECT  5.655 58.109 5.937 128.807 ;
     RECT  11.055 127.301 11.337 128.807 ;
     RECT  54.255 123.251 54.537 128.807 ;
     RECT  59.655 0.793 59.937 128.807 ;
     RECT  65.055 124.799 65.337 128.807 ;
     RECT  70.455 0.793 70.737 128.807 ;
     RECT  75.855 0.793 76.137 128.807 ;
     RECT  81.216 124.807 81.537 128.807 ;
     RECT  86.655 0.793 86.937 128.807 ;
     RECT  92.055 0.793 92.337 128.807 ;
     RECT  97.455 0.793 97.737 128.807 ;
     RECT  102.855 0.793 103.137 128.807 ;
     RECT  16.455 128.075 17.406 128.849 ;
     RECT  23.94 128.723 50.706 128.861 ;
     RECT  17.388 128.849 17.406 128.909 ;
     RECT  81.216 128.807 81.345 128.909 ;
     RECT  21.564 128.615 23.022 128.921 ;
     RECT  23.94 128.861 31.05 128.957 ;
     RECT  31.788 128.861 50.706 128.957 ;
     RECT  18.684 128.615 18.99 128.993 ;
     RECT  24.624 128.957 31.05 129.005 ;
     RECT  31.788 128.957 50.598 129.053 ;
     RECT  0.255 128.807 0.345 129.077 ;
     RECT  5.655 128.807 5.745 129.077 ;
     RECT  11.055 128.807 11.145 129.077 ;
     RECT  16.455 128.849 16.545 129.077 ;
     RECT  21.855 128.921 23.022 129.077 ;
     RECT  54.255 128.807 54.345 129.077 ;
     RECT  59.655 128.807 59.745 129.077 ;
     RECT  65.055 128.807 65.145 129.077 ;
     RECT  70.455 128.807 70.545 129.077 ;
     RECT  75.855 128.807 75.945 129.077 ;
     RECT  81.255 128.909 81.345 129.077 ;
     RECT  86.655 128.807 86.745 129.077 ;
     RECT  92.055 128.807 92.145 129.077 ;
     RECT  97.455 128.807 97.545 129.077 ;
     RECT  102.855 128.807 102.945 129.077 ;
     RECT  22.464 129.077 23.022 129.101 ;
     RECT  31.788 129.053 35.478 129.101 ;
     RECT  37.476 129.053 45.342 129.101 ;
     RECT  46.152 129.053 46.458 129.101 ;
     RECT  32.616 129.101 35.298 129.149 ;
     RECT  37.476 129.101 40.482 129.149 ;
     RECT  41.364 129.101 44.658 129.149 ;
     RECT  46.152 129.101 46.17 129.149 ;
     RECT  47.232 129.053 50.454 129.149 ;
     RECT  24.732 129.005 29.394 129.197 ;
     RECT  37.872 129.149 38.826 129.197 ;
     RECT  43.164 129.149 44.658 129.197 ;
     RECT  47.52 129.149 50.274 129.197 ;
     RECT  26.028 129.197 26.046 129.245 ;
     RECT  26.784 129.197 27.738 129.245 ;
     RECT  28.512 129.197 28.638 129.245 ;
     RECT  41.364 129.149 41.994 129.245 ;
     RECT  43.236 129.197 44.658 129.245 ;
     RECT  47.52 129.197 49.554 129.245 ;
     RECT  22.464 129.101 22.914 129.293 ;
     RECT  30.204 129.005 30.978 129.293 ;
     RECT  39.816 129.149 39.834 129.293 ;
     RECT  43.236 129.245 43.47 129.293 ;
     RECT  44.28 129.245 44.298 129.293 ;
     RECT  48.024 129.245 49.554 129.293 ;
     RECT  24.732 129.197 25.218 129.341 ;
     RECT  28.512 129.245 28.53 129.341 ;
     RECT  32.796 129.149 34.326 129.341 ;
     RECT  41.364 129.245 41.382 129.341 ;
     RECT  18.684 128.993 18.702 129.389 ;
     RECT  26.784 129.245 27.63 129.389 ;
     RECT  31.788 129.101 31.806 129.389 ;
     RECT  33.732 129.341 34.326 129.389 ;
     RECT  37.944 129.197 38.286 129.389 ;
     RECT  43.236 129.293 43.254 129.389 ;
     RECT  48.024 129.293 49.338 129.389 ;
     RECT  22.824 129.293 22.914 129.437 ;
     RECT  30.96 129.293 30.978 129.437 ;
     RECT  48.168 129.389 49.086 129.437 ;
     RECT  10.224 126.689 10.242 129.485 ;
     RECT  22.896 129.437 22.914 129.485 ;
     RECT  24.732 129.341 24.75 129.485 ;
     RECT  26.784 129.389 27.594 129.485 ;
     RECT  29.376 129.197 29.394 129.485 ;
     RECT  32.94 129.341 32.958 129.485 ;
     RECT  34.308 129.389 34.326 129.485 ;
     RECT  38.268 129.389 38.286 129.485 ;
     RECT  48.168 129.437 48.186 129.485 ;
     RECT  49.068 129.437 49.086 129.485 ;
     RECT  26.784 129.485 26.802 129.533 ;
     RECT  27.576 129.485 27.594 129.533 ;
    LAYER M4 ;
     RECT  0.248 0.528 0.352 129.072 ;
     RECT  0.352 0.798 0.544 128.802 ;
     RECT  4.981 6.864 5.125 6.888 ;
     RECT  5.125 6.288 5.173 6.888 ;
     RECT  5.221 0.432 5.281 0.456 ;
     RECT  5.281 0.432 5.353 0.552 ;
     RECT  5.029 9.696 5.413 9.72 ;
     RECT  5.353 0.384 5.461 0.552 ;
     RECT  5.461 0.288 5.509 0.552 ;
     RECT  5.461 11.952 5.509 11.976 ;
     RECT  4.789 13.104 5.509 13.128 ;
     RECT  5.509 0.288 5.648 0.648 ;
     RECT  5.077 2.304 5.648 2.328 ;
     RECT  5.173 5.712 5.648 6.888 ;
     RECT  5.269 7.968 5.648 7.992 ;
     RECT  5.413 9.12 5.648 9.72 ;
     RECT  5.509 11.952 5.648 13.128 ;
     RECT  5.648 0.288 5.701 129.072 ;
     RECT  5.701 0.192 5.752 129.072 ;
     RECT  5.752 0.192 5.944 128.802 ;
     RECT  5.944 7.44 6.041 7.992 ;
     RECT  5.944 13.68 6.083 15.432 ;
     RECT  5.944 12.528 6.149 12.552 ;
     RECT  6.083 13.68 6.149 14.232 ;
     RECT  6.083 15.408 6.179 15.432 ;
     RECT  6.149 14.208 6.227 14.232 ;
     RECT  5.944 0.192 6.293 1.464 ;
     RECT  5.944 3.408 6.329 3.432 ;
     RECT  6.041 7.44 6.851 7.464 ;
     RECT  5.944 21.648 6.995 21.672 ;
     RECT  6.293 0.288 7.369 1.464 ;
     RECT  7.333 14.832 7.409 14.856 ;
     RECT  7.381 65.568 7.445 65.592 ;
     RECT  5.944 11.424 7.525 11.448 ;
     RECT  7.237 5.712 7.697 5.736 ;
     RECT  7.525 11.424 7.769 11.496 ;
     RECT  7.769 11.424 7.841 11.448 ;
     RECT  7.717 6.864 7.861 6.888 ;
     RECT  7.369 0.288 7.909 1.704 ;
     RECT  7.909 0.288 8.053 2.424 ;
     RECT  7.477 22.896 8.093 22.92 ;
     RECT  7.429 9.12 8.309 9.144 ;
     RECT  8.341 57.552 8.387 57.576 ;
     RECT  8.053 0.288 8.677 2.856 ;
     RECT  8.677 0.288 8.773 3.432 ;
     RECT  7.861 6.864 9.137 7.464 ;
     RECT  7.573 25.488 9.313 25.512 ;
     RECT  9.301 58.128 9.353 58.152 ;
     RECT  9.313 74.112 9.395 74.136 ;
     RECT  8.773 0.288 9.397 3.48 ;
     RECT  9.137 7.44 9.569 7.464 ;
     RECT  9.397 0.288 9.713 3.528 ;
     RECT  9.713 3.456 9.785 3.528 ;
     RECT  9.685 6.432 9.821 6.456 ;
     RECT  9.745 18.816 9.827 18.84 ;
     RECT  9.733 12 9.829 12.024 ;
     RECT  9.785 3.504 9.857 3.528 ;
     RECT  9.313 25.488 9.971 25.896 ;
     RECT  9.829 12 9.973 12.072 ;
     RECT  9.109 13.104 9.973 13.128 ;
     RECT  9.713 0.288 10.001 2.424 ;
     RECT  10.429 8.496 10.549 8.52 ;
     RECT  10.693 5.712 10.837 5.736 ;
     RECT  10.837 5.712 10.933 6.744 ;
     RECT  10.001 0.288 11.005 2.376 ;
     RECT  10.933 5.712 11.005 6.84 ;
     RECT  11.005 0.192 11.048 2.376 ;
     RECT  11.005 5.712 11.048 6.888 ;
     RECT  10.549 8.208 11.048 8.52 ;
     RECT  9.973 12 11.048 13.128 ;
     RECT  10.597 14.4 11.048 14.424 ;
     RECT  9.971 25.488 11.048 25.512 ;
     RECT  8.809 30.576 11.048 30.6 ;
     RECT  8.485 46.512 11.048 46.536 ;
     RECT  10.885 51.888 11.048 51.912 ;
     RECT  8.341 60.624 11.048 60.648 ;
     RECT  10.429 69.552 11.048 69.576 ;
     RECT  10.393 72.144 11.048 72.168 ;
     RECT  10.609 78.096 11.048 78.12 ;
     RECT  10.933 80.256 11.048 80.28 ;
     RECT  9.925 98.064 11.048 98.088 ;
     RECT  10.213 129.456 11.048 129.48 ;
     RECT  11.048 0.192 11.171 129.48 ;
     RECT  11.171 0.24 11.225 129.48 ;
     RECT  11.225 0.288 11.344 129.48 ;
     RECT  11.344 11.424 11.837 11.448 ;
     RECT  11.344 60.528 11.873 60.648 ;
     RECT  11.344 17.664 12.053 17.688 ;
     RECT  11.344 26.736 12.131 26.76 ;
     RECT  11.344 14.4 12.161 14.856 ;
     RECT  11.344 0.288 12.197 3.432 ;
     RECT  11.344 30.576 12.373 30.6 ;
     RECT  12.421 44.352 12.485 44.376 ;
     RECT  11.344 16.368 12.517 16.584 ;
     RECT  12.517 16.368 12.563 17.16 ;
     RECT  12.373 30.576 12.589 30.792 ;
     RECT  11.344 7.968 12.593 8.232 ;
     RECT  11.344 115.632 12.803 115.656 ;
     RECT  12.805 39.312 12.851 39.336 ;
     RECT  12.661 15.984 12.917 16.008 ;
     RECT  12.757 108.288 12.949 108.312 ;
     RECT  12.661 54.72 12.953 54.744 ;
     RECT  12.913 104.256 12.995 104.28 ;
     RECT  12.949 107.808 12.995 108.312 ;
     RECT  12.877 50.736 13.025 50.76 ;
     RECT  12.563 17.04 13.045 17.16 ;
     RECT  12.901 9.696 13.061 9.72 ;
     RECT  12.949 44.928 13.061 44.952 ;
     RECT  12.805 20.208 13.093 20.232 ;
     RECT  13.093 19.392 13.169 20.232 ;
     RECT  13.093 66.624 13.241 66.648 ;
     RECT  13.045 17.04 13.277 17.256 ;
     RECT  12.589 30.576 13.379 31.56 ;
     RECT  12.197 2.88 13.381 3.432 ;
     RECT  12.197 0.288 13.457 1.416 ;
     RECT  13.309 66.672 13.457 66.696 ;
     RECT  13.381 2.592 13.573 3.432 ;
     RECT  11.344 6.288 13.637 6.312 ;
     RECT  12.161 14.4 13.765 14.424 ;
     RECT  13.573 2.304 13.781 3.432 ;
     RECT  13.169 19.392 13.781 19.416 ;
     RECT  13.457 0.288 13.853 1.224 ;
     RECT  11.344 98.064 13.889 98.088 ;
     RECT  13.189 10.272 13.997 10.296 ;
     RECT  13.777 82.656 13.997 82.68 ;
     RECT  11.344 87.792 14.029 87.816 ;
     RECT  13.277 17.04 14.033 17.112 ;
     RECT  13.333 113.424 14.033 113.448 ;
     RECT  13.093 58.704 14.141 58.728 ;
     RECT  11.873 60.528 14.149 60.552 ;
     RECT  14.149 60.48 14.213 61.176 ;
     RECT  13.781 2.304 14.321 2.952 ;
     RECT  12.949 11.424 14.389 11.448 ;
     RECT  12.805 110.736 14.425 110.76 ;
     RECT  14.281 102.576 14.429 102.6 ;
     RECT  14.389 11.424 14.437 12.024 ;
     RECT  14.353 106.608 14.465 106.632 ;
     RECT  13.633 34.512 14.483 34.536 ;
     RECT  14.425 110.592 14.483 110.76 ;
     RECT  14.437 11.424 14.485 12.12 ;
     RECT  14.483 110.736 14.821 110.76 ;
     RECT  14.029 87.792 14.861 88.104 ;
     RECT  14.821 110.736 14.861 110.856 ;
     RECT  14.677 3.984 14.917 4.008 ;
     RECT  13.853 0.288 15.061 1.176 ;
     RECT  14.321 2.304 15.061 2.376 ;
     RECT  14.965 38.736 15.077 38.76 ;
     RECT  15.061 0.288 15.113 2.376 ;
     RECT  14.893 26.784 15.113 26.808 ;
     RECT  14.893 34.8 15.113 34.824 ;
     RECT  14.485 11.424 15.157 12.216 ;
     RECT  12.593 8.208 15.205 8.232 ;
     RECT  15.205 7.44 15.253 8.232 ;
     RECT  15.109 70.656 15.257 70.68 ;
     RECT  15.253 7.44 15.301 8.376 ;
     RECT  15.013 5.472 15.361 5.496 ;
     RECT  15.301 7.44 15.401 8.568 ;
     RECT  15.157 11.376 15.437 12.216 ;
     RECT  15.401 8.352 15.443 8.568 ;
     RECT  15.397 113.424 15.443 113.448 ;
     RECT  15.109 15.408 15.445 15.432 ;
     RECT  15.113 0.288 15.613 2.328 ;
     RECT  12.481 95.088 15.613 95.112 ;
     RECT  11.344 89.952 15.649 89.976 ;
     RECT  12.841 91.296 15.649 91.32 ;
     RECT  14.917 3.408 15.685 4.008 ;
     RECT  15.361 5.472 15.721 6.024 ;
     RECT  13.765 13.872 15.793 14.424 ;
     RECT  15.445 15.408 15.793 15.576 ;
     RECT  11.344 72.144 15.829 72.168 ;
     RECT  15.613 51.36 15.865 51.384 ;
     RECT  14.033 17.04 15.937 17.064 ;
     RECT  13.379 30.576 16.117 30.6 ;
     RECT  15.829 72.144 16.261 72.264 ;
     RECT  15.613 0.144 16.448 2.328 ;
     RECT  15.685 3.408 16.448 4.056 ;
     RECT  15.721 5.472 16.448 7.368 ;
     RECT  15.443 8.544 16.448 8.568 ;
     RECT  15.721 9.648 16.448 9.672 ;
     RECT  15.437 11.376 16.448 12.024 ;
     RECT  15.793 13.872 16.448 15.576 ;
     RECT  15.937 17.04 16.448 17.112 ;
     RECT  16.117 30.576 16.448 30.696 ;
     RECT  16.117 35.328 16.448 35.352 ;
     RECT  11.344 46.512 16.448 46.536 ;
     RECT  15.637 47.904 16.448 47.928 ;
     RECT  15.865 51.36 16.448 51.816 ;
     RECT  16.069 57.024 16.448 57.048 ;
     RECT  14.213 60.528 16.448 60.552 ;
     RECT  16.261 72.144 16.448 72.408 ;
     RECT  14.861 87.888 16.448 88.104 ;
     RECT  15.649 89.952 16.448 91.32 ;
     RECT  15.613 95.088 16.448 95.4 ;
     RECT  12.995 107.808 16.448 107.832 ;
     RECT  14.861 110.832 16.448 110.856 ;
     RECT  11.344 118.608 16.448 118.632 ;
     RECT  12.757 121.536 16.448 121.56 ;
     RECT  11.344 129.456 16.448 129.48 ;
     RECT  16.448 0.144 16.744 129.48 ;
     RECT  16.744 72.24 16.883 73.224 ;
     RECT  16.744 47.904 17.345 48.12 ;
     RECT  16.744 10.848 17.489 12.552 ;
     RECT  16.744 8.544 17.597 8.568 ;
     RECT  16.744 30.672 17.773 30.696 ;
     RECT  16.744 16.992 17.777 17.88 ;
     RECT  16.744 5.472 17.795 7.368 ;
     RECT  16.744 86.064 17.795 86.088 ;
     RECT  16.744 3.408 17.797 3.672 ;
     RECT  16.744 0.144 17.845 1.704 ;
     RECT  17.797 2.88 17.845 3.672 ;
     RECT  17.797 45.6 17.893 45.624 ;
     RECT  17.893 45.6 17.939 45.72 ;
     RECT  16.744 51.36 17.939 51.384 ;
     RECT  17.845 46.704 17.957 46.728 ;
     RECT  17.489 10.848 17.993 11.688 ;
     RECT  16.744 15.36 18.035 15.384 ;
     RECT  17.989 76.368 18.035 76.392 ;
     RECT  17.881 38.736 18.101 38.76 ;
     RECT  17.773 30.192 18.133 30.696 ;
     RECT  18.025 114.576 18.137 114.6 ;
     RECT  17.795 5.472 18.169 6.984 ;
     RECT  18.133 30 18.179 30.696 ;
     RECT  18.373 14.832 18.425 14.856 ;
     RECT  18.205 8.688 18.613 9.528 ;
     RECT  18.613 8.688 18.677 10.296 ;
     RECT  18.677 8.688 18.709 9.528 ;
     RECT  17.845 0.144 18.757 3.672 ;
     RECT  17.777 17.856 18.805 17.88 ;
     RECT  18.805 17.088 18.817 17.88 ;
     RECT  16.744 60.528 18.817 60.552 ;
     RECT  17.993 11.424 18.821 11.688 ;
     RECT  18.385 127.152 18.821 127.176 ;
     RECT  18.025 56.448 18.857 56.472 ;
     RECT  18.817 60.528 18.857 60.648 ;
     RECT  18.637 115.056 18.857 115.08 ;
     RECT  18.757 0.144 18.893 4.008 ;
     RECT  18.893 0.144 18.961 1.704 ;
     RECT  18.893 2.88 18.965 4.008 ;
     RECT  18.817 17.088 18.965 17.976 ;
     RECT  19.105 58.128 19.187 58.152 ;
     RECT  18.169 5.376 19.217 6.984 ;
     RECT  19.217 5.376 19.253 6.888 ;
     RECT  16.744 89.952 19.333 89.976 ;
     RECT  18.961 0.096 19.379 1.704 ;
     RECT  19.333 51.888 19.397 51.912 ;
     RECT  19.333 89.376 19.397 89.976 ;
     RECT  18.821 11.664 19.429 11.688 ;
     RECT  19.429 11.664 19.475 12.552 ;
     RECT  18.965 3.408 19.577 4.008 ;
     RECT  18.709 19.152 19.619 19.176 ;
     RECT  19.573 100.32 19.619 100.344 ;
     RECT  19.253 5.376 19.649 6.312 ;
     RECT  19.577 3.984 19.861 4.008 ;
     RECT  16.744 128.88 19.861 129.48 ;
     RECT  16.744 91.296 19.933 91.32 ;
     RECT  19.681 127.536 19.933 127.56 ;
     RECT  16.744 110.832 19.937 110.856 ;
     RECT  19.861 3.984 19.955 4.584 ;
     RECT  16.883 73.2 19.957 73.224 ;
     RECT  19.957 73.2 20.003 73.368 ;
     RECT  18.179 30.048 20.005 30.072 ;
     RECT  19.933 91.2 20.051 91.32 ;
     RECT  20.003 73.248 20.099 73.368 ;
     RECT  20.041 26.736 20.113 26.76 ;
     RECT  18.601 85.392 20.149 85.416 ;
     RECT  20.149 84.96 20.195 85.512 ;
     RECT  16.744 87.888 20.195 88.104 ;
     RECT  18.673 82.416 20.197 82.44 ;
     RECT  16.744 79.152 20.243 79.176 ;
     RECT  20.195 84.96 20.243 85.416 ;
     RECT  20.041 34.752 20.261 34.776 ;
     RECT  19.969 70.608 20.261 70.632 ;
     RECT  18.709 8.544 20.369 9.528 ;
     RECT  19.573 14.256 20.369 14.28 ;
     RECT  20.113 26.736 20.369 26.856 ;
     RECT  19.379 0.096 20.401 1.608 ;
     RECT  20.293 86.64 20.405 86.664 ;
     RECT  20.401 0.096 20.485 2.28 ;
     RECT  16.744 107.808 20.545 107.832 ;
     RECT  19.955 4.56 20.549 4.584 ;
     RECT  20.485 52.896 20.549 53.352 ;
     RECT  19.649 5.904 20.581 6.312 ;
     RECT  20.545 107.76 20.617 107.832 ;
     RECT  19.933 127.536 20.621 127.656 ;
     RECT  20.617 107.76 20.627 108.216 ;
     RECT  19.475 11.664 20.629 11.688 ;
     RECT  20.627 107.808 20.657 108.216 ;
     RECT  20.485 0.096 20.693 2.328 ;
     RECT  20.369 26.736 20.765 26.76 ;
     RECT  20.051 91.296 20.773 91.32 ;
     RECT  20.581 92.304 20.773 92.328 ;
     RECT  20.243 85.392 20.819 85.416 ;
     RECT  20.773 91.296 20.819 92.328 ;
     RECT  20.005 29.76 20.833 30.072 ;
     RECT  20.195 88.08 21.013 88.104 ;
     RECT  17.345 48.096 21.061 48.12 ;
     RECT  20.629 11.424 21.157 11.688 ;
     RECT  21.061 47.136 21.157 48.12 ;
     RECT  20.581 5.904 21.541 6.36 ;
     RECT  21.637 15.408 21.661 15.432 ;
     RECT  20.693 0.096 21.685 2.28 ;
     RECT  21.685 0.096 21.848 3.144 ;
     RECT  21.109 4.704 21.848 4.728 ;
     RECT  21.541 5.904 21.848 6.888 ;
     RECT  20.369 9.504 21.848 9.528 ;
     RECT  21.157 11.424 21.848 12.024 ;
     RECT  21.661 15.312 21.848 15.432 ;
     RECT  18.965 17.952 21.848 17.976 ;
     RECT  21.409 26.784 21.848 26.808 ;
     RECT  20.833 29.76 21.848 30.744 ;
     RECT  16.744 42.72 21.848 42.744 ;
     RECT  17.939 45.696 21.848 45.72 ;
     RECT  21.157 46.704 21.848 48.12 ;
     RECT  18.857 60.624 21.848 60.648 ;
     RECT  20.099 73.248 21.848 73.272 ;
     RECT  18.421 77.28 21.848 77.304 ;
     RECT  21.193 79.824 21.848 79.848 ;
     RECT  20.197 82.416 21.848 83.064 ;
     RECT  21.013 88.08 21.848 88.392 ;
     RECT  19.397 89.952 21.848 89.976 ;
     RECT  20.819 91.296 21.848 92.232 ;
     RECT  21.481 94.032 21.848 94.056 ;
     RECT  16.744 95.088 21.848 95.4 ;
     RECT  21.121 97.296 21.848 97.32 ;
     RECT  21.733 103.008 21.848 103.032 ;
     RECT  20.657 108.192 21.848 108.216 ;
     RECT  20.545 110.592 21.848 110.616 ;
     RECT  19.429 112.416 21.848 112.44 ;
     RECT  16.744 118.608 21.848 118.632 ;
     RECT  16.744 121.536 21.848 121.56 ;
     RECT  21.337 123.792 21.848 123.816 ;
     RECT  20.621 127.632 21.848 127.656 ;
     RECT  19.861 128.64 21.848 129.48 ;
     RECT  21.848 0.096 22.144 129.48 ;
     RECT  22.144 97.296 22.205 97.32 ;
     RECT  22.144 102.912 22.277 103.032 ;
     RECT  22.144 118.608 22.673 118.632 ;
     RECT  22.144 8.544 22.745 8.568 ;
     RECT  22.144 45.696 22.745 47.16 ;
     RECT  22.144 11.424 22.781 11.448 ;
     RECT  22.144 60.624 22.853 60.648 ;
     RECT  22.144 89.952 22.853 90.072 ;
     RECT  22.144 91.296 22.853 92.232 ;
     RECT  22.144 121.536 22.853 121.656 ;
     RECT  22.144 128.64 22.925 129.48 ;
     RECT  22.144 78.912 22.961 80.04 ;
     RECT  22.144 50.736 22.997 50.904 ;
     RECT  22.144 82.416 22.997 83.064 ;
     RECT  22.144 127.344 22.997 127.656 ;
     RECT  22.144 73.248 23.171 74.136 ;
     RECT  22.144 4.8 23.173 4.824 ;
     RECT  22.144 6 23.173 6.312 ;
     RECT  22.144 94.032 23.173 94.056 ;
     RECT  22.144 42.672 23.177 42.744 ;
     RECT  22.144 17.952 23.213 17.976 ;
     RECT  22.997 50.736 23.213 50.76 ;
     RECT  22.144 14.208 23.219 14.856 ;
     RECT  23.173 93.504 23.219 94.056 ;
     RECT  22.144 0.096 23.321 3.144 ;
     RECT  23.219 14.832 23.321 14.856 ;
     RECT  23.219 94.032 23.497 94.056 ;
     RECT  22.144 95.088 23.497 95.4 ;
     RECT  22.144 123.696 23.605 124.008 ;
     RECT  23.177 42.72 23.651 42.744 ;
     RECT  23.269 12 23.717 12.024 ;
     RECT  22.745 45.696 23.789 46.536 ;
     RECT  22.144 70.704 23.789 70.728 ;
     RECT  23.171 73.248 24.077 73.272 ;
     RECT  22.997 127.632 24.109 127.656 ;
     RECT  22.925 128.64 24.109 129.432 ;
     RECT  22.144 58.704 24.113 58.728 ;
     RECT  23.641 66.672 24.113 66.696 ;
     RECT  24.109 127.632 24.181 129.432 ;
     RECT  23.789 45.699 24.227 46.536 ;
     RECT  23.821 74.448 24.257 74.472 ;
     RECT  23.497 94.032 24.257 95.4 ;
     RECT  23.941 8.544 24.325 8.568 ;
     RECT  23.321 0.144 24.373 3.144 ;
     RECT  23.173 4.8 24.373 6.312 ;
     RECT  24.373 0.144 24.401 6.312 ;
     RECT  22.144 29.76 24.469 29.784 ;
     RECT  24.401 0.144 24.473 6.024 ;
     RECT  24.181 127.344 24.721 129.432 ;
     RECT  24.469 29.76 24.803 29.976 ;
     RECT  24.661 14.832 24.901 14.856 ;
     RECT  22.277 102.912 24.901 102.936 ;
     RECT  24.565 12.528 24.949 12.552 ;
     RECT  24.325 8.544 25.049 8.616 ;
     RECT  24.901 14.832 25.049 15 ;
     RECT  25.049 14.976 25.085 15 ;
     RECT  22.144 7.44 25.121 7.464 ;
     RECT  24.901 102.912 25.121 103.176 ;
     RECT  24.757 13.68 25.193 13.704 ;
     RECT  24.181 11.424 25.409 11.496 ;
     RECT  24.949 12.528 25.573 12.6 ;
     RECT  25.573 12 25.661 12.6 ;
     RECT  23.989 10.32 25.813 10.344 ;
     RECT  24.473 0.144 25.909 3.144 ;
     RECT  22.144 23.28 25.955 23.304 ;
     RECT  25.981 59.856 26.051 59.88 ;
     RECT  25.909 0.096 26.089 3.144 ;
     RECT  25.837 126 26.089 126.024 ;
     RECT  25.981 42.768 26.129 42.792 ;
     RECT  25.981 50.688 26.129 50.712 ;
     RECT  26.101 17.376 26.197 17.4 ;
     RECT  26.089 125.952 26.197 126.024 ;
     RECT  24.721 127.344 26.197 129.48 ;
     RECT  25.661 12.48 26.245 12.6 ;
     RECT  26.197 17.376 26.273 17.688 ;
     RECT  26.089 0.048 26.341 3.144 ;
     RECT  24.473 4.224 26.341 6.024 ;
     RECT  25.813 10.32 26.389 10.632 ;
     RECT  26.245 12.48 26.437 13.128 ;
     RECT  24.257 94.032 26.485 95.112 ;
     RECT  22.853 91.392 26.725 92.232 ;
     RECT  26.273 17.376 26.773 17.4 ;
     RECT  26.197 125.952 26.773 129.48 ;
     RECT  22.853 121.632 26.881 121.656 ;
     RECT  26.293 15.408 27.013 15.432 ;
     RECT  26.341 0.048 27.248 6.024 ;
     RECT  25.237 7.68 27.248 8.232 ;
     RECT  26.389 10.32 27.248 11.448 ;
     RECT  26.437 12.48 27.248 13.704 ;
     RECT  27.013 14.784 27.248 15.432 ;
     RECT  26.773 16.896 27.248 17.4 ;
     RECT  23.221 19.824 27.248 19.848 ;
     RECT  24.803 29.952 27.248 29.976 ;
     RECT  24.757 31.92 27.248 31.944 ;
     RECT  24.227 45.699 27.248 45.717 ;
     RECT  26.917 50.736 27.248 50.76 ;
     RECT  24.901 75.12 27.248 75.144 ;
     RECT  22.144 77.28 27.248 77.304 ;
     RECT  22.961 78.912 27.248 79.752 ;
     RECT  22.997 82.416 27.248 82.44 ;
     RECT  22.144 88.08 27.248 88.104 ;
     RECT  22.853 90.048 27.248 90.072 ;
     RECT  26.725 91.152 27.248 92.232 ;
     RECT  26.485 93.456 27.248 95.112 ;
     RECT  25.909 98.928 27.248 98.952 ;
     RECT  25.121 103.008 27.248 103.176 ;
     RECT  26.437 107.904 27.248 107.928 ;
     RECT  22.144 110.736 27.248 110.76 ;
     RECT  26.881 121.632 27.248 122.568 ;
     RECT  23.605 123.696 27.248 124.296 ;
     RECT  26.773 125.952 27.248 129.528 ;
     RECT  27.248 0.048 27.544 129.528 ;
     RECT  27.544 126.432 27.605 129.528 ;
     RECT  27.544 121.632 27.683 122.712 ;
     RECT  27.544 90.048 27.731 90.072 ;
     RECT  27.544 91.392 27.779 91.944 ;
     RECT  27.544 4.224 27.827 6.024 ;
     RECT  27.544 110.544 27.857 110.76 ;
     RECT  27.544 9.312 27.929 9.336 ;
     RECT  27.544 114.528 27.929 114.552 ;
     RECT  27.544 0.048 28.001 3.144 ;
     RECT  27.544 58.704 28.181 58.728 ;
     RECT  27.544 66.672 28.181 66.696 ;
     RECT  27.544 13.68 28.541 13.704 ;
     RECT  27.544 71.28 28.577 71.304 ;
     RECT  27.544 103.008 28.577 103.032 ;
     RECT  27.544 26.208 28.643 26.232 ;
     RECT  28.573 104.304 28.643 104.328 ;
     RECT  27.544 19.824 28.685 19.848 ;
     RECT  27.544 82.416 28.691 82.44 ;
     RECT  28.645 50.736 28.757 50.76 ;
     RECT  27.605 126.432 28.825 129.432 ;
     RECT  27.544 88.08 28.835 88.104 ;
     RECT  28.825 114.576 29.009 114.6 ;
     RECT  27.827 6 29.075 6.024 ;
     RECT  29.005 57.6 29.075 57.624 ;
     RECT  28.681 61.584 29.075 61.608 ;
     RECT  27.544 45.699 29.149 45.717 ;
     RECT  27.544 98.928 29.149 98.952 ;
     RECT  27.857 110.736 29.149 110.76 ;
     RECT  28.001 0.096 29.153 3.144 ;
     RECT  29.149 45.6 29.189 45.72 ;
     RECT  29.153 0.096 29.221 3.096 ;
     RECT  27.544 43.296 29.257 43.32 ;
     RECT  27.683 122.544 29.261 122.712 ;
     RECT  27.544 17.376 29.317 17.4 ;
     RECT  29.149 98.64 29.333 98.952 ;
     RECT  29.149 110.544 29.333 110.76 ;
     RECT  27.544 10.608 29.363 12.552 ;
     RECT  28.825 126.24 29.365 129.432 ;
     RECT  27.827 4.224 29.369 4.248 ;
     RECT  29.257 42.768 29.441 43.32 ;
     RECT  27.544 78.912 29.507 79.752 ;
     RECT  29.437 82.608 29.621 82.632 ;
     RECT  27.544 123.696 29.689 124.056 ;
     RECT  29.689 123.696 29.747 124.872 ;
     RECT  29.747 123.696 29.891 124.056 ;
     RECT  29.891 123.696 29.893 124.008 ;
     RECT  29.869 33.6 29.939 33.624 ;
     RECT  29.363 10.608 29.981 11.16 ;
     RECT  28.645 66.72 30.053 66.744 ;
     RECT  29.363 12.48 30.197 12.552 ;
     RECT  29.189 45.603 30.229 45.621 ;
     RECT  29.365 126.24 30.265 129.48 ;
     RECT  29.441 43.296 30.275 43.32 ;
     RECT  29.333 110.736 30.337 110.76 ;
     RECT  29.617 71.856 30.373 71.88 ;
     RECT  30.337 110.544 30.449 110.76 ;
     RECT  29.221 0.048 30.521 3.096 ;
     RECT  30.517 29.616 30.563 29.64 ;
     RECT  27.779 91.92 30.625 91.944 ;
     RECT  30.229 45.603 30.661 45.96 ;
     RECT  29.507 78.912 30.661 78.936 ;
     RECT  30.197 12.48 30.707 12.504 ;
     RECT  30.625 91.2 30.707 91.944 ;
     RECT  30.445 14.016 30.737 14.04 ;
     RECT  29.545 99.408 30.769 99.432 ;
     RECT  27.544 15.408 30.809 15.432 ;
     RECT  30.589 121.968 30.841 121.992 ;
     RECT  29.893 123.168 30.841 124.008 ;
     RECT  27.544 75.12 30.949 75.144 ;
     RECT  30.841 121.968 30.953 124.008 ;
     RECT  30.953 121.968 30.995 121.992 ;
     RECT  30.913 118.608 31.025 118.632 ;
     RECT  30.265 125.424 31.139 129.48 ;
     RECT  31.021 81.456 31.165 81.48 ;
     RECT  27.544 7.68 31.169 8.232 ;
     RECT  31.169 8.208 31.385 8.232 ;
     RECT  30.953 123.168 31.417 124.008 ;
     RECT  29.981 11.136 31.493 11.16 ;
     RECT  30.661 78.912 31.525 78.984 ;
     RECT  31.525 78.912 31.571 79.224 ;
     RECT  31.345 67.584 31.597 67.608 ;
     RECT  30.707 91.92 31.597 91.944 ;
     RECT  31.165 93.024 31.597 93.048 ;
     RECT  31.597 67.584 31.667 67.752 ;
     RECT  31.597 91.92 31.667 93.048 ;
     RECT  27.544 94.032 31.813 94.296 ;
     RECT  30.769 98.688 31.993 99.528 ;
     RECT  31.417 123.168 32.605 124.296 ;
     RECT  30.521 0.048 32.648 2.28 ;
     RECT  29.317 17.376 32.648 17.64 ;
     RECT  32.533 32.64 32.648 32.904 ;
     RECT  30.661 43.824 32.648 43.848 ;
     RECT  30.661 45.408 32.648 45.96 ;
     RECT  29.029 59.184 32.648 59.208 ;
     RECT  28.825 63.216 32.648 63.24 ;
     RECT  31.667 67.584 32.648 67.608 ;
     RECT  30.373 71.856 32.648 72.168 ;
     RECT  30.949 74.64 32.648 75.144 ;
     RECT  27.544 77.28 32.648 77.304 ;
     RECT  31.571 78.912 32.648 78.984 ;
     RECT  31.165 81.456 32.648 82.44 ;
     RECT  32.425 89.472 32.648 89.496 ;
     RECT  31.667 93.024 32.648 93.048 ;
     RECT  31.813 94.032 32.648 94.584 ;
     RECT  31.993 98.592 32.648 99.528 ;
     RECT  30.085 105.072 32.648 105.096 ;
     RECT  32.101 106.608 32.648 106.632 ;
     RECT  30.449 110.736 32.648 110.76 ;
     RECT  32.137 115.968 32.648 115.992 ;
     RECT  32.605 123.168 32.648 124.344 ;
     RECT  31.139 126.24 32.648 129.48 ;
     RECT  32.648 0.048 32.944 129.48 ;
     RECT  32.944 127.68 32.969 129.48 ;
     RECT  32.944 17.376 33.059 17.64 ;
     RECT  32.944 30.288 33.059 30.84 ;
     RECT  32.944 32.352 33.059 32.76 ;
     RECT  33.059 17.376 33.113 17.4 ;
     RECT  32.944 125.424 33.491 126.6 ;
     RECT  32.944 77.28 33.587 78.984 ;
     RECT  32.944 73.488 33.731 73.512 ;
     RECT  32.944 69.168 33.869 69.192 ;
     RECT  33.491 125.424 33.923 125.448 ;
     RECT  32.944 118.752 33.977 118.776 ;
     RECT  32.944 74.64 34.019 74.664 ;
     RECT  32.944 58.704 34.193 59.208 ;
     RECT  32.969 127.68 34.297 129.384 ;
     RECT  32.944 123.168 34.309 124.344 ;
     RECT  34.309 123.072 34.451 124.344 ;
     RECT  34.451 123.072 34.553 124.152 ;
     RECT  32.944 99.408 34.585 99.432 ;
     RECT  32.944 87.552 34.693 87.816 ;
     RECT  32.944 63.216 34.765 63.24 ;
     RECT  32.944 92.112 34.769 93.048 ;
     RECT  34.693 86.736 34.801 87.816 ;
     RECT  34.765 63.072 34.805 63.24 ;
     RECT  34.693 107.712 34.841 107.736 ;
     RECT  32.944 71.328 34.931 72.168 ;
     RECT  34.585 98.592 34.945 99.432 ;
     RECT  34.909 35.856 34.979 35.88 ;
     RECT  33.491 126.576 35.029 126.6 ;
     RECT  34.837 60.768 35.057 60.792 ;
     RECT  35.017 55.248 35.075 55.272 ;
     RECT  33.059 30.288 35.341 30.312 ;
     RECT  35.341 30.192 35.411 30.312 ;
     RECT  32.944 94.032 35.411 94.296 ;
     RECT  34.153 75.648 35.459 75.672 ;
     RECT  33.587 78.048 35.507 78.984 ;
     RECT  34.931 71.76 35.555 72.168 ;
     RECT  34.945 98.352 35.593 99.432 ;
     RECT  32.944 45.552 35.603 45.96 ;
     RECT  35.593 98.016 35.651 99.432 ;
     RECT  32.944 0.048 36.245 2.28 ;
     RECT  35.557 54.72 36.353 54.744 ;
     RECT  35.029 126 36.421 126.6 ;
     RECT  34.553 123.168 36.493 124.152 ;
     RECT  36.061 81.216 36.515 81.24 ;
     RECT  36.421 126 36.529 126.696 ;
     RECT  35.629 77.568 36.563 77.592 ;
     RECT  36.529 105.552 36.565 105.576 ;
     RECT  36.245 0.144 36.569 2.28 ;
     RECT  36.517 102.48 36.569 102.504 ;
     RECT  32.944 23.28 36.611 23.304 ;
     RECT  36.565 105.456 36.611 105.576 ;
     RECT  36.529 125.424 36.637 126.696 ;
     RECT  34.297 127.68 36.637 129.48 ;
     RECT  34.801 86.736 36.659 87.912 ;
     RECT  34.585 121.44 36.661 121.464 ;
     RECT  35.917 34.752 36.707 34.776 ;
     RECT  35.411 30.288 36.709 30.312 ;
     RECT  35.881 36.288 36.709 36.312 ;
     RECT  34.769 92.112 36.709 92.952 ;
     RECT  36.709 30 36.755 30.312 ;
     RECT  36.709 91.776 36.755 92.952 ;
     RECT  36.661 120.864 36.755 121.464 ;
     RECT  36.611 105.456 36.757 105.48 ;
     RECT  32.944 115.968 36.757 115.992 ;
     RECT  36.755 120.864 36.785 120.888 ;
     RECT  36.757 115.968 36.803 116.28 ;
     RECT  36.637 125.424 36.803 129.48 ;
     RECT  36.569 0.144 36.821 2.04 ;
     RECT  36.673 42.768 36.821 42.792 ;
     RECT  36.169 88.896 36.851 88.92 ;
     RECT  35.555 71.952 36.889 72.168 ;
     RECT  36.637 50.736 36.893 50.76 ;
     RECT  36.755 30 36.947 30.024 ;
     RECT  36.709 35.904 36.947 36.312 ;
     RECT  36.889 43.344 36.947 43.368 ;
     RECT  36.889 120.48 36.961 120.504 ;
     RECT  32.944 82.416 36.997 82.44 ;
     RECT  36.853 74.592 37.037 74.616 ;
     RECT  36.755 91.776 37.043 91.8 ;
     RECT  36.803 116.256 37.043 116.28 ;
     RECT  36.961 120.432 37.043 120.504 ;
     RECT  36.493 123.168 37.141 124.344 ;
     RECT  35.507 78.912 37.285 78.984 ;
     RECT  34.933 118.128 37.321 118.152 ;
     RECT  37.285 77.952 37.573 78.984 ;
     RECT  37.105 80.352 37.573 80.376 ;
     RECT  37.669 90.96 37.717 90.984 ;
     RECT  37.177 54.096 37.861 54.12 ;
     RECT  34.193 59.184 37.861 59.208 ;
     RECT  36.755 92.928 37.861 92.952 ;
     RECT  37.861 54.096 37.909 55.272 ;
     RECT  37.141 114.528 37.933 114.552 ;
     RECT  36.821 0.672 38.048 2.04 ;
     RECT  36.901 27.888 38.048 27.912 ;
     RECT  36.947 36.24 38.048 36.312 ;
     RECT  37.909 44.688 38.048 44.712 ;
     RECT  35.603 45.936 38.048 45.96 ;
     RECT  37.321 51.84 38.048 51.864 ;
     RECT  37.909 54.048 38.048 55.272 ;
     RECT  37.861 59.184 38.048 60.024 ;
     RECT  34.805 63.072 38.048 63.096 ;
     RECT  32.944 67.584 38.048 68.136 ;
     RECT  36.889 71.232 38.048 72.168 ;
     RECT  35.629 73.392 38.048 73.416 ;
     RECT  37.573 77.952 38.048 80.376 ;
     RECT  36.997 81.84 38.048 82.44 ;
     RECT  36.659 86.736 38.048 86.76 ;
     RECT  36.659 87.888 38.048 87.912 ;
     RECT  37.717 90.624 38.048 90.984 ;
     RECT  37.861 92.256 38.048 92.952 ;
     RECT  35.411 94.272 38.048 94.296 ;
     RECT  35.651 98.352 38.048 99.432 ;
     RECT  36.757 105.36 38.048 105.48 ;
     RECT  37.933 114.528 38.048 114.648 ;
     RECT  37.321 118.128 38.048 118.584 ;
     RECT  37.043 120.48 38.048 120.504 ;
     RECT  37.141 122.592 38.048 124.872 ;
     RECT  36.803 125.952 38.048 129.48 ;
     RECT  38.048 0.528 38.152 129.48 ;
     RECT  38.152 0.576 38.297 129.48 ;
     RECT  38.297 0.576 38.344 129.336 ;
     RECT  38.344 127.68 38.387 129.336 ;
     RECT  38.344 44.592 38.441 44.712 ;
     RECT  38.344 118.032 38.441 118.152 ;
     RECT  38.344 123.168 38.483 124.296 ;
     RECT  38.344 126.144 38.531 126.168 ;
     RECT  38.344 63.072 38.675 63.096 ;
     RECT  38.344 81.312 38.801 82.44 ;
     RECT  38.344 78.96 38.819 79.8 ;
     RECT  38.483 123.168 38.837 124.056 ;
     RECT  38.387 127.68 38.837 129.192 ;
     RECT  38.344 98.352 39.011 98.616 ;
     RECT  38.344 27.888 39.089 27.912 ;
     RECT  38.344 74.016 39.197 74.712 ;
     RECT  38.344 71.952 39.203 72.168 ;
     RECT  39.011 98.352 39.299 98.376 ;
     RECT  38.837 123.168 39.445 123.24 ;
     RECT  38.801 81.312 39.481 82.152 ;
     RECT  39.445 122.544 39.629 123.24 ;
     RECT  38.344 105.36 39.661 105.48 ;
     RECT  38.837 127.68 39.685 129.144 ;
     RECT  39.661 105.312 39.701 105.48 ;
     RECT  38.344 66.048 39.731 66.072 ;
     RECT  39.625 102.576 39.737 102.6 ;
     RECT  39.685 127.2 39.805 129.144 ;
     RECT  39.805 127.2 39.829 129.288 ;
     RECT  38.344 77.808 39.877 77.976 ;
     RECT  38.344 86.736 39.877 86.76 ;
     RECT  39.829 39.312 39.917 39.336 ;
     RECT  38.344 94.272 39.971 94.296 ;
     RECT  39.877 76.896 39.973 77.976 ;
     RECT  38.819 78.96 39.973 78.984 ;
     RECT  39.829 127.104 39.985 129.288 ;
     RECT  39.973 76.896 40.019 78.984 ;
     RECT  39.481 80.352 40.019 82.152 ;
     RECT  39.877 86.496 40.019 86.76 ;
     RECT  40.019 77.808 40.067 78.984 ;
     RECT  40.067 78.048 40.115 78.984 ;
     RECT  40.115 78.048 40.163 78.696 ;
     RECT  40.019 86.592 40.163 86.76 ;
     RECT  39.985 126.528 40.403 129.288 ;
     RECT  40.453 28.32 40.499 28.344 ;
     RECT  39.629 123.168 40.741 123.24 ;
     RECT  40.669 124.608 40.781 124.632 ;
     RECT  40.741 122.544 40.925 123.24 ;
     RECT  39.701 105.312 41.209 105.336 ;
     RECT  40.163 78.048 41.219 78.072 ;
     RECT  41.101 58.704 41.249 58.728 ;
     RECT  41.137 124.848 41.249 124.872 ;
     RECT  38.344 95.904 41.269 95.928 ;
     RECT  38.344 67.584 41.281 68.136 ;
     RECT  41.209 105.312 41.315 105.864 ;
     RECT  38.344 0.576 41.321 2.232 ;
     RECT  40.453 104.304 41.321 104.328 ;
     RECT  40.403 127.104 41.353 129.288 ;
     RECT  38.344 87.888 41.363 87.912 ;
     RECT  40.925 122.544 41.389 123.192 ;
     RECT  38.441 118.032 41.413 118.056 ;
     RECT  38.344 120.48 41.459 120.504 ;
     RECT  41.389 122.304 41.459 123.192 ;
     RECT  40.019 81.312 41.651 82.152 ;
     RECT  39.373 71.232 41.699 71.256 ;
     RECT  41.281 67.584 41.747 68.376 ;
     RECT  39.877 102.912 41.857 102.936 ;
     RECT  41.353 127.104 41.861 129.336 ;
     RECT  41.857 98.64 41.969 98.664 ;
     RECT  41.857 102.576 41.969 102.936 ;
     RECT  41.969 102.912 42.145 102.936 ;
     RECT  38.344 60 42.179 60.024 ;
     RECT  38.441 44.592 42.293 44.616 ;
     RECT  42.181 80.928 42.293 80.952 ;
     RECT  41.269 95.904 42.325 96.216 ;
     RECT  40.163 86.736 42.371 86.76 ;
     RECT  39.733 85.392 42.419 85.416 ;
     RECT  41.459 122.544 42.473 123.192 ;
     RECT  42.181 124.896 42.577 124.92 ;
     RECT  42.325 95.904 42.613 97.176 ;
     RECT  41.651 82.128 42.757 82.152 ;
     RECT  42.473 122.64 42.757 123.192 ;
     RECT  42.577 124.272 42.757 124.92 ;
     RECT  42.253 126 42.757 126.024 ;
     RECT  41.861 127.344 43.081 129.336 ;
     RECT  43.081 127.248 43.225 129.336 ;
     RECT  42.757 124.272 43.285 126.024 ;
     RECT  43.225 127.248 43.285 129.384 ;
     RECT  42.145 102.912 43.297 103.608 ;
     RECT  39.197 74.016 43.333 74.04 ;
     RECT  43.369 66.336 43.405 66.36 ;
     RECT  41.321 0.576 43.448 1.896 ;
     RECT  38.344 36.24 43.448 36.264 ;
     RECT  38.344 43.248 43.448 43.272 ;
     RECT  42.133 61.152 43.448 61.176 ;
     RECT  43.405 66.336 43.448 66.552 ;
     RECT  41.747 67.584 43.448 68.136 ;
     RECT  43.333 73.92 43.448 74.52 ;
     RECT  42.757 82.128 43.448 82.248 ;
     RECT  43.333 86.016 43.448 86.04 ;
     RECT  42.721 90.576 43.448 90.6 ;
     RECT  42.613 93.456 43.448 93.48 ;
     RECT  42.613 95.904 43.448 97.464 ;
     RECT  43.297 102.816 43.448 103.608 ;
     RECT  43.189 114 43.448 114.024 ;
     RECT  41.413 118.032 43.448 119.016 ;
     RECT  42.757 122.64 43.448 123.288 ;
     RECT  43.285 124.272 43.448 129.384 ;
     RECT  43.448 0.528 43.552 129.384 ;
     RECT  43.552 0.798 43.744 129.384 ;
     RECT  43.744 0.912 43.805 0.984 ;
     RECT  43.744 61.152 43.859 61.464 ;
     RECT  43.744 66.336 43.859 68.136 ;
     RECT  43.744 70.368 43.859 70.632 ;
     RECT  43.744 103.008 43.859 103.608 ;
     RECT  43.744 62.544 43.877 62.568 ;
     RECT  43.859 70.608 43.877 70.632 ;
     RECT  43.744 125.328 43.877 129.384 ;
     RECT  43.859 66.528 43.907 68.136 ;
     RECT  43.859 103.584 43.907 103.608 ;
     RECT  43.877 127.104 43.907 129.384 ;
     RECT  43.744 93.936 43.955 93.96 ;
     RECT  43.744 95.136 44.021 96.216 ;
     RECT  43.744 118.128 44.021 119.016 ;
     RECT  44.021 95.136 44.099 95.928 ;
     RECT  43.744 91.728 44.195 91.752 ;
     RECT  43.744 122.544 44.237 123.288 ;
     RECT  43.877 125.328 44.243 126.072 ;
     RECT  43.744 114 44.435 114.024 ;
     RECT  43.907 127.104 44.531 129.336 ;
     RECT  44.243 126 44.915 126.072 ;
     RECT  44.881 101.424 44.963 101.448 ;
     RECT  44.953 124.272 45.061 124.296 ;
     RECT  45.061 86.016 45.107 86.04 ;
     RECT  44.099 95.904 45.169 95.928 ;
     RECT  45.205 33.024 45.251 33.048 ;
     RECT  43.744 121.44 45.251 121.464 ;
     RECT  43.744 43.248 45.313 43.272 ;
     RECT  44.531 127.152 45.395 129.336 ;
     RECT  45.169 95.568 45.421 95.928 ;
     RECT  43.859 61.152 45.641 61.176 ;
     RECT  45.421 95.568 45.827 96.648 ;
     RECT  44.237 123.264 45.853 123.288 ;
     RECT  45.061 124.272 45.853 124.872 ;
     RECT  43.805 0.912 45.857 0.936 ;
     RECT  45.853 123.264 45.857 124.872 ;
     RECT  44.915 126.048 45.875 126.072 ;
     RECT  45.877 94.752 45.929 94.776 ;
     RECT  45.827 95.904 45.971 96.648 ;
     RECT  45.877 125.52 46.019 125.544 ;
     RECT  45.997 93.12 46.067 93.144 ;
     RECT  43.744 82.224 46.109 82.248 ;
     RECT  45.857 123.264 46.289 124.392 ;
     RECT  43.907 67.584 46.451 68.136 ;
     RECT  44.021 118.992 46.609 119.016 ;
     RECT  46.465 126.528 46.609 126.552 ;
     RECT  45.395 127.632 46.609 129.336 ;
     RECT  46.289 123.696 46.643 124.392 ;
     RECT  46.609 118.992 46.649 119.112 ;
     RECT  46.141 97.728 46.979 97.752 ;
     RECT  45.313 43.248 47.027 43.32 ;
     RECT  46.643 124.368 47.029 124.392 ;
     RECT  47.029 124.368 47.117 124.824 ;
     RECT  46.609 126.528 47.267 129.336 ;
     RECT  47.401 86.64 47.513 86.664 ;
     RECT  47.027 43.248 47.603 43.272 ;
     RECT  47.149 125.424 47.651 125.448 ;
     RECT  47.267 127.104 48.013 129.336 ;
     RECT  48.013 127.104 48.157 129.384 ;
     RECT  47.557 123.12 48.421 123.144 ;
     RECT  48.157 127.104 48.469 129.48 ;
     RECT  48.421 123.072 48.589 123.144 ;
     RECT  47.117 124.368 48.589 124.392 ;
     RECT  48.589 123.072 48.769 124.392 ;
     RECT  46.451 67.584 48.848 67.608 ;
     RECT  47.581 90.048 48.848 90.072 ;
     RECT  47.869 91.44 48.848 91.464 ;
     RECT  45.971 95.904 48.848 95.928 ;
     RECT  46.649 119.088 48.848 119.112 ;
     RECT  47.653 120.288 48.848 120.312 ;
     RECT  48.769 123.072 48.848 124.632 ;
     RECT  48.469 126.528 48.848 129.48 ;
     RECT  48.848 0.528 48.952 129.48 ;
     RECT  48.952 0.798 49.097 129.48 ;
     RECT  49.097 0.798 49.144 129.384 ;
     RECT  49.144 126.576 49.349 129.384 ;
     RECT  49.349 126.576 49.565 129.288 ;
     RECT  49.144 96.864 49.571 96.888 ;
     RECT  49.144 94.032 49.667 94.056 ;
     RECT  49.144 95.616 49.715 95.64 ;
     RECT  49.144 122.496 49.781 122.52 ;
     RECT  49.144 90.048 49.811 90.072 ;
     RECT  49.565 126.576 49.907 129.192 ;
     RECT  49.907 126.576 50.003 126.6 ;
     RECT  49.144 91.44 50.051 91.464 ;
     RECT  49.907 127.824 50.339 129.192 ;
     RECT  50.339 127.824 50.393 129.144 ;
     RECT  50.393 129.024 50.465 129.144 ;
     RECT  50.465 129.024 50.609 129.048 ;
     RECT  50.393 127.824 50.753 127.848 ;
     RECT  52.357 127.92 52.697 127.944 ;
     RECT  49.144 67.584 54.248 67.608 ;
     RECT  49.144 119.088 54.248 119.112 ;
     RECT  53.557 121.584 54.248 121.608 ;
     RECT  54.248 0.528 54.352 129.072 ;
     RECT  54.352 0.798 54.544 128.802 ;
     RECT  54.544 67.584 59.648 67.608 ;
     RECT  59.648 0.528 59.752 129.072 ;
     RECT  59.752 0.798 59.944 128.802 ;
     RECT  59.944 67.584 65.048 67.608 ;
     RECT  65.048 0.528 65.152 129.072 ;
     RECT  65.152 0.798 65.344 128.802 ;
     RECT  65.344 67.584 70.448 67.608 ;
     RECT  70.448 0.528 70.552 129.072 ;
     RECT  70.552 0.798 70.744 128.802 ;
     RECT  70.744 67.584 75.848 67.608 ;
     RECT  75.848 0.528 75.952 129.072 ;
     RECT  75.952 0.798 76.144 128.802 ;
     RECT  76.144 67.584 80.003 67.608 ;
     RECT  81.205 128.88 81.248 128.904 ;
     RECT  81.248 0.528 81.352 129.072 ;
     RECT  81.352 0.798 81.544 128.904 ;
     RECT  81.544 128.88 81.923 128.904 ;
     RECT  86.648 0.528 86.752 129.072 ;
     RECT  86.752 0.798 86.944 128.802 ;
     RECT  92.048 0.528 92.152 129.072 ;
     RECT  92.152 0.798 92.344 128.802 ;
     RECT  97.448 0.528 97.552 129.072 ;
     RECT  97.552 0.798 97.744 128.802 ;
     RECT  102.848 0.528 102.952 129.072 ;
     RECT  102.952 0.798 103.144 128.802 ;
    LAYER M5 ;
     RECT  29.808 0.085 29.832 0.144 ;
     RECT  4.8 0.144 29.832 0.181 ;
     RECT  36.48 0.117 36.504 0.181 ;
     RECT  36.432 0.181 36.504 0.245 ;
     RECT  33.12 0.181 33.24 0.309 ;
     RECT  36.336 0.245 36.504 0.323 ;
     RECT  4.8 0.181 30.696 0.517 ;
     RECT  33.12 0.309 33.672 0.517 ;
     RECT  32.64 0.517 33.672 0.611 ;
     RECT  35.328 0.053 35.352 0.611 ;
     RECT  4.8 0.517 31.08 0.613 ;
     RECT  4.8 0.613 31.608 0.629 ;
     RECT  32.64 0.611 33.144 0.629 ;
     RECT  0.24 0.517 0.36 0.787 ;
     RECT  38.04 0.517 38.16 0.787 ;
     RECT  43.44 0.517 43.56 0.787 ;
     RECT  48.84 0.517 48.96 0.787 ;
     RECT  54.24 0.517 54.36 0.787 ;
     RECT  59.64 0.517 59.76 0.787 ;
     RECT  65.04 0.517 65.16 0.787 ;
     RECT  70.44 0.517 70.56 0.787 ;
     RECT  75.84 0.517 75.96 0.787 ;
     RECT  81.24 0.517 81.36 0.787 ;
     RECT  86.64 0.517 86.76 0.787 ;
     RECT  92.04 0.517 92.16 0.787 ;
     RECT  97.44 0.517 97.56 0.787 ;
     RECT  102.84 0.517 102.96 0.787 ;
     RECT  36.48 0.323 36.504 0.803 ;
     RECT  4.8 0.629 33.144 1.451 ;
     RECT  4.8 1.451 31.224 1.571 ;
     RECT  31.2 1.571 31.224 1.667 ;
     RECT  4.8 1.571 29.88 1.763 ;
     RECT  4.8 1.763 28.968 1.859 ;
     RECT  32.64 1.451 33.144 2.155 ;
     RECT  4.8 1.859 28.536 5.989 ;
     RECT  4.8 5.989 29.064 7.475 ;
     RECT  9.12 7.475 29.064 8.003 ;
     RECT  9.12 8.003 11.64 11.459 ;
     RECT  12.672 8.003 29.064 11.459 ;
     RECT  24.576 11.459 29.064 11.941 ;
     RECT  23.136 11.459 23.304 12.035 ;
     RECT  24.576 11.941 29.352 12.035 ;
     RECT  12.672 11.459 20.04 12.227 ;
     RECT  15.12 12.227 20.04 12.563 ;
     RECT  24.576 12.035 24.984 12.563 ;
     RECT  24.672 12.563 24.984 12.611 ;
     RECT  4.8 7.475 7.608 13.139 ;
     RECT  9.12 11.459 11.496 13.139 ;
     RECT  12.672 12.227 13.8 13.907 ;
     RECT  24.672 12.611 24.936 14.867 ;
     RECT  24.912 14.867 24.936 15.011 ;
     RECT  5.64 13.139 7.608 15.443 ;
     RECT  15.12 12.563 16.752 15.443 ;
     RECT  26.016 12.035 29.352 15.443 ;
     RECT  12.672 13.907 13.128 16.357 ;
     RECT  15.408 15.443 16.752 16.981 ;
     RECT  17.76 12.563 20.04 16.981 ;
     RECT  12.528 16.357 13.128 17.075 ;
     RECT  15.408 16.981 20.04 17.123 ;
     RECT  32.64 2.155 32.952 17.605 ;
     RECT  29.04 15.443 29.352 17.651 ;
     RECT  9.312 13.139 11.496 17.699 ;
     RECT  15.408 17.123 18.168 17.891 ;
     RECT  9.312 17.699 11.352 18.851 ;
     RECT  12.816 17.075 13.128 19.427 ;
     RECT  23.136 12.035 23.256 19.859 ;
     RECT  12.816 19.427 12.84 20.243 ;
     RECT  6.96 15.443 7.608 21.683 ;
     RECT  26.016 15.443 27.552 23.269 ;
     RECT  7.392 21.683 7.608 25.523 ;
     RECT  9.312 18.851 9.384 25.861 ;
     RECT  10.464 18.851 11.352 25.861 ;
     RECT  29.04 17.651 29.064 26.197 ;
     RECT  9.312 25.861 11.352 26.725 ;
     RECT  36.576 23.269 36.6 27.877 ;
     RECT  30.672 12.469 30.696 29.605 ;
     RECT  36.576 27.877 36.936 30.035 ;
     RECT  17.76 17.891 18.168 30.707 ;
     RECT  32.64 17.605 33.048 30.851 ;
     RECT  24.768 29.749 24.792 31.955 ;
     RECT  32.64 30.851 32.952 32.341 ;
     RECT  32.64 32.341 33.048 32.629 ;
     RECT  32.544 32.629 33.048 32.771 ;
     RECT  32.544 32.771 32.952 32.915 ;
     RECT  28.608 26.197 29.064 33.589 ;
     RECT  30.528 29.605 30.696 33.589 ;
     RECT  15.408 17.891 16.752 34.501 ;
     RECT  35.376 30.181 35.4 35.845 ;
     RECT  36.576 30.035 36.744 35.893 ;
     RECT  36.576 35.893 36.936 36.277 ;
     RECT  38.04 0.787 38.352 36.277 ;
     RECT  9.312 26.725 12.12 39.301 ;
     RECT  13.344 31.525 13.368 39.301 ;
     RECT  40.464 28.309 40.488 39.301 ;
     RECT  23.136 19.859 23.208 42.709 ;
     RECT  47.568 43.237 47.592 43.285 ;
     RECT  32.64 32.915 32.952 43.813 ;
     RECT  34.944 35.845 35.4 45.541 ;
     RECT  28.608 33.589 30.696 45.589 ;
     RECT  31.824 43.813 32.952 45.589 ;
     RECT  23.136 42.709 23.64 46.501 ;
     RECT  21.024 11.459 22.152 50.773 ;
     RECT  23.136 46.501 24.216 50.773 ;
     RECT  21.024 50.773 24.216 50.915 ;
     RECT  19.152 17.123 20.04 52.885 ;
     RECT  21.024 50.915 22.152 52.885 ;
     RECT  19.152 52.885 22.152 53.363 ;
     RECT  34.944 45.541 35.592 54.755 ;
     RECT  7.392 25.523 7.416 57.541 ;
     RECT  9.312 39.301 13.368 57.541 ;
     RECT  28.608 45.589 32.952 57.635 ;
     RECT  7.392 57.541 13.368 58.163 ;
     RECT  19.152 53.363 20.04 58.163 ;
     RECT  28.608 57.635 28.632 59.173 ;
     RECT  29.904 57.635 32.952 59.173 ;
     RECT  9.36 58.163 13.368 60.469 ;
     RECT  14.448 34.501 16.752 60.469 ;
     RECT  7.392 58.163 8.376 60.659 ;
     RECT  9.36 60.469 16.752 61.187 ;
     RECT  42.144 59.989 42.168 61.187 ;
     RECT  43.44 0.787 43.752 61.429 ;
     RECT  28.608 59.173 32.952 61.619 ;
     RECT  43.44 61.429 43.848 62.579 ;
     RECT  36.576 36.277 38.352 63.061 ;
     RECT  7.392 60.659 7.416 65.603 ;
     RECT  39.84 39.301 40.488 66.037 ;
     RECT  43.44 62.579 43.752 66.325 ;
     RECT  43.44 66.325 43.848 66.517 ;
     RECT  43.44 66.517 43.896 66.659 ;
     RECT  43.44 66.659 43.848 67.139 ;
     RECT  36.576 63.061 38.664 67.765 ;
     RECT  39.696 66.037 40.488 67.765 ;
     RECT  46.992 43.285 47.592 68.101 ;
     RECT  43.44 67.139 43.752 70.357 ;
     RECT  43.44 70.357 43.848 70.643 ;
     RECT  41.712 68.341 41.736 71.221 ;
     RECT  34.944 54.755 35.064 71.317 ;
     RECT  34.896 71.317 35.064 71.749 ;
     RECT  14.448 61.187 16.752 72.229 ;
     RECT  17.76 30.707 18.024 72.229 ;
     RECT  14.448 72.229 18.024 72.419 ;
     RECT  16.44 72.419 18.024 73.235 ;
     RECT  19.44 58.163 20.04 73.237 ;
     RECT  21.024 53.363 22.152 73.237 ;
     RECT  19.44 73.237 22.152 73.379 ;
     RECT  29.904 61.619 32.952 73.477 ;
     RECT  43.44 70.643 43.752 73.909 ;
     RECT  9.36 61.187 13.368 74.147 ;
     RECT  23.136 50.915 24.216 74.147 ;
     RECT  43.344 73.909 43.752 74.531 ;
     RECT  29.904 73.477 33.72 74.629 ;
     RECT  34.896 71.749 35.544 74.629 ;
     RECT  17.76 73.235 18.024 76.403 ;
     RECT  36.576 67.765 40.488 77.557 ;
     RECT  36.528 77.557 40.488 78.037 ;
     RECT  41.664 71.221 41.736 78.037 ;
     RECT  9.936 74.147 13.368 78.131 ;
     RECT  19.44 73.379 20.04 79.141 ;
     RECT  21.024 73.379 22.152 79.141 ;
     RECT  28.608 61.619 28.632 79.717 ;
     RECT  29.904 74.629 35.544 79.717 ;
     RECT  10.944 78.131 13.368 80.291 ;
     RECT  36.528 78.037 41.736 80.917 ;
     RECT  28.608 79.717 35.544 81.205 ;
     RECT  36.528 80.917 42.216 81.205 ;
     RECT  28.608 81.205 42.216 85.381 ;
     RECT  28.608 85.381 42.408 86.005 ;
     RECT  43.44 74.531 43.752 86.005 ;
     RECT  45.216 33.013 45.24 86.005 ;
     RECT  17.76 76.403 17.784 86.099 ;
     RECT  19.44 79.141 22.152 87.877 ;
     RECT  19.344 87.877 22.152 88.403 ;
     RECT  25.92 23.269 27.552 90.037 ;
     RECT  28.608 86.005 43.752 90.037 ;
     RECT  48.84 0.787 49.152 90.037 ;
     RECT  19.344 88.403 20.808 91.235 ;
     RECT  25.92 90.037 43.752 91.235 ;
     RECT  48.84 90.037 49.8 91.429 ;
     RECT  31.536 91.235 43.752 91.717 ;
     RECT  45.072 86.005 45.24 91.717 ;
     RECT  20.784 91.235 20.808 92.293 ;
     RECT  20.592 92.293 20.808 92.339 ;
     RECT  31.536 91.717 45.24 93.109 ;
     RECT  46.416 68.101 47.592 93.109 ;
     RECT  23.184 74.147 24.216 93.539 ;
     RECT  19.344 91.235 19.608 95.411 ;
     RECT  48.84 91.429 50.04 95.893 ;
     RECT  9.936 78.131 9.96 98.099 ;
     RECT  25.92 91.235 30.552 98.963 ;
     RECT  19.44 95.411 19.608 100.355 ;
     RECT  21.84 88.403 22.152 102.997 ;
     RECT  31.536 93.109 47.592 104.339 ;
     RECT  20.592 92.339 20.616 107.795 ;
     RECT  26.448 98.963 30.552 107.939 ;
     RECT  21.744 102.997 22.152 108.227 ;
     RECT  14.448 72.419 15.432 110.627 ;
     RECT  19.44 100.355 19.464 112.451 ;
     RECT  11.04 80.291 13.368 113.459 ;
     RECT  15.408 110.627 15.432 113.459 ;
     RECT  11.04 113.459 12.792 118.643 ;
     RECT  54.24 0.787 54.552 119.077 ;
     RECT  41.184 104.339 47.592 120.277 ;
     RECT  48.72 95.893 50.04 120.277 ;
     RECT  12.768 118.643 12.792 121.571 ;
     RECT  53.568 119.077 54.552 121.619 ;
     RECT  26.496 107.939 30.552 121.957 ;
     RECT  31.536 104.339 40.104 121.957 ;
     RECT  41.184 120.277 50.04 123.155 ;
     RECT  23.616 93.539 24.216 124.307 ;
     RECT  41.184 123.155 47.016 124.789 ;
     RECT  41.184 124.789 47.064 125.413 ;
     RECT  48.432 123.155 50.04 125.413 ;
     RECT  26.496 121.957 40.104 125.941 ;
     RECT  26.352 125.941 40.104 126.517 ;
     RECT  41.184 125.413 50.04 126.517 ;
     RECT  26.352 126.517 50.04 126.565 ;
     RECT  24.192 124.307 24.216 127.379 ;
     RECT  26.208 126.565 50.04 127.669 ;
     RECT  0.24 0.787 0.552 128.813 ;
     RECT  5.64 15.443 5.952 128.813 ;
     RECT  11.04 118.643 11.352 128.813 ;
     RECT  16.44 73.235 16.752 128.813 ;
     RECT  54.24 121.619 54.552 128.813 ;
     RECT  59.64 0.787 59.952 128.813 ;
     RECT  65.04 0.787 65.352 128.813 ;
     RECT  70.44 0.787 70.752 128.813 ;
     RECT  75.84 0.787 76.152 128.813 ;
     RECT  86.64 0.787 86.952 128.813 ;
     RECT  92.04 0.787 92.352 128.813 ;
     RECT  97.44 0.787 97.752 128.813 ;
     RECT  102.84 0.787 103.152 128.813 ;
     RECT  25.776 127.669 50.04 128.821 ;
     RECT  81.24 0.787 81.552 128.869 ;
     RECT  25.68 128.821 50.184 128.917 ;
     RECT  25.68 128.917 50.232 129.013 ;
     RECT  0.24 128.813 0.36 129.083 ;
     RECT  5.64 128.813 5.76 129.083 ;
     RECT  11.04 128.813 11.16 129.083 ;
     RECT  16.44 128.813 16.56 129.083 ;
     RECT  21.84 108.227 22.152 129.083 ;
     RECT  54.24 128.813 54.36 129.083 ;
     RECT  59.64 128.813 59.76 129.083 ;
     RECT  65.04 128.813 65.16 129.083 ;
     RECT  70.44 128.813 70.56 129.083 ;
     RECT  75.84 128.813 75.96 129.083 ;
     RECT  81.24 128.869 81.912 129.083 ;
     RECT  86.64 128.813 86.76 129.083 ;
     RECT  92.04 128.813 92.16 129.083 ;
     RECT  97.44 128.813 97.56 129.083 ;
     RECT  102.84 128.813 102.96 129.083 ;
     RECT  25.68 129.013 50.28 129.157 ;
     RECT  25.632 129.157 50.328 129.323 ;
     RECT  22.8 129.205 22.824 129.395 ;
     RECT  25.68 129.323 50.328 129.424 ;
     RECT  52.368 127.909 52.392 129.424 ;
     RECT  79.968 67.573 79.992 129.424 ;
     RECT  81.888 129.083 81.912 129.424 ;
    LAYER M6 ;
     RECT  0 0.996 5.461 1.86 ;
     RECT  5.461 0.384 6.037 1.86 ;
     RECT  6.037 0.256 6.123 1.86 ;
     RECT  6.123 0.512 6.995 1.86 ;
     RECT  6.995 0.996 9.349 1.86 ;
     RECT  9.349 0.384 9.717 1.86 ;
     RECT  9.717 0.256 9.827 1.86 ;
     RECT  9.827 0.384 11.219 1.86 ;
     RECT  11.219 0.64 11.363 1.86 ;
     RECT  11.363 0.996 15.397 1.86 ;
     RECT  15.397 0.256 16.883 1.86 ;
     RECT  16.883 0.512 17.219 1.86 ;
     RECT  17.219 0.996 20.437 1.86 ;
     RECT  20.437 0.512 20.869 1.86 ;
     RECT  20.869 0.384 21.877 1.86 ;
     RECT  21.877 0.256 21.931 1.86 ;
     RECT  21.931 0.384 22.059 1.86 ;
     RECT  22.059 0.512 22.307 1.86 ;
     RECT  22.307 0.576 25.189 1.86 ;
     RECT  25.189 0.448 25.237 1.86 ;
     RECT  25.237 0.256 25.269 1.86 ;
     RECT  25.621 129.28 25.669 129.312 ;
     RECT  25.669 128.832 26.099 129.312 ;
     RECT  26.099 129.28 26.147 129.312 ;
     RECT  25.269 0.064 26.933 1.86 ;
     RECT  26.933 0.064 27.109 2.016 ;
     RECT  27.109 0.064 27.243 2.912 ;
     RECT  32.533 128.768 32.565 128.8 ;
     RECT  32.565 128.768 32.619 129.248 ;
     RECT  32.619 129.216 32.723 129.248 ;
     RECT  27.243 0.064 33.155 2.144 ;
     RECT  33.155 0.064 35.363 1.86 ;
     RECT  35.363 0.128 36.515 1.86 ;
     RECT  36.517 128.768 36.533 128.8 ;
     RECT  36.533 128.64 36.851 128.8 ;
     RECT  37.861 128.896 37.877 128.928 ;
     RECT  37.877 128.896 37.931 129.248 ;
     RECT  37.931 129.216 38.147 129.248 ;
     RECT  43.333 128.896 43.429 128.928 ;
     RECT  43.429 128.896 43.811 129.248 ;
     RECT  43.811 129.088 43.883 129.248 ;
     RECT  43.883 129.088 43.907 129.12 ;
     RECT  49.237 129.152 49.379 129.184 ;
     RECT  36.515 0.996 108 1.86 ;
     RECT  0 6.396 108 7.26 ;
     RECT  0 11.796 108 12.66 ;
     RECT  0 17.196 108 18.06 ;
     RECT  0 22.596 108 23.46 ;
     RECT  0 27.996 108 28.86 ;
     RECT  0 33.396 108 34.26 ;
     RECT  0 38.796 108 39.66 ;
     RECT  0 44.196 108 45.06 ;
     RECT  0 49.596 108 50.46 ;
     RECT  0 54.996 108 55.86 ;
     RECT  0 60.396 108 61.26 ;
     RECT  0 65.796 108 66.66 ;
     RECT  0 71.196 108 72.06 ;
     RECT  0 76.596 108 77.46 ;
     RECT  0 81.996 108 82.86 ;
     RECT  0 87.396 108 88.26 ;
     RECT  0 92.796 108 93.66 ;
     RECT  0 98.196 108 99.06 ;
     RECT  0 103.596 108 104.46 ;
     RECT  0 108.996 108 109.86 ;
     RECT  0 114.396 108 115.26 ;
     RECT  0 119.796 108 120.66 ;
     RECT  0 125.196 108 126.06 ;
    LAYER M7 ;
     RECT  28.608 0.053 29.728 0.117 ;
     RECT  27.392 0.117 29.728 0.181 ;
     RECT  25.28 0.053 25.312 0.299 ;
     RECT  27.2 0.181 29.728 0.309 ;
     RECT  27.136 0.309 29.728 0.363 ;
     RECT  9.728 0.245 9.76 0.373 ;
     RECT  21.888 0.245 21.92 0.373 ;
     RECT  15.424 0.245 16.864 0.427 ;
     RECT  9.728 0.373 11.168 0.491 ;
     RECT  27.136 0.363 29.152 0.491 ;
     RECT  27.136 0.491 28.64 0.501 ;
     RECT  6.08 0.245 6.112 0.531 ;
     RECT  10.944 0.491 11.168 0.531 ;
     RECT  16.384 0.427 16.864 0.531 ;
     RECT  21.888 0.373 22.048 0.531 ;
     RECT  26.944 0.501 28.64 0.555 ;
     RECT  6.08 0.531 6.544 0.619 ;
     RECT  16.384 0.531 17.344 0.683 ;
     RECT  25.344 0.437 25.376 0.747 ;
     RECT  21.888 0.531 22.744 0.757 ;
     RECT  10.944 0.531 11.944 0.811 ;
     RECT  16.832 0.683 17.344 0.811 ;
     RECT  11.136 0.811 11.944 1.451 ;
     RECT  21.888 0.757 23.392 1.451 ;
     RECT  26.944 0.555 28.144 2.027 ;
     RECT  27.2 2.027 28.144 2.923 ;
     RECT  33.256 0.531 33.544 128.757 ;
     RECT  36.544 128.629 36.576 128.811 ;
     RECT  38.656 0.531 38.944 128.885 ;
     RECT  0.856 0.531 1.144 129.069 ;
     RECT  6.256 0.619 6.544 129.069 ;
     RECT  11.656 1.451 11.944 129.069 ;
     RECT  17.056 0.811 17.344 129.069 ;
     RECT  22.456 1.451 22.744 129.069 ;
     RECT  27.856 2.923 28.144 129.069 ;
     RECT  32.576 128.757 33.544 129.069 ;
     RECT  37.888 128.885 38.944 129.069 ;
     RECT  44.056 0.531 44.344 129.069 ;
     RECT  49.456 0.531 49.744 129.069 ;
     RECT  54.856 0.531 55.144 129.069 ;
     RECT  60.256 0.531 60.544 129.069 ;
     RECT  65.656 0.531 65.944 129.069 ;
     RECT  71.056 0.531 71.344 129.069 ;
     RECT  76.456 0.531 76.744 129.069 ;
     RECT  81.856 0.531 82.144 129.069 ;
     RECT  87.256 0.531 87.544 129.069 ;
     RECT  92.656 0.531 92.944 129.069 ;
     RECT  98.056 0.531 98.344 129.069 ;
     RECT  103.456 0.531 103.744 129.069 ;
     RECT  32.576 129.069 32.608 129.259 ;
     RECT  37.888 129.069 37.92 129.259 ;
     RECT  43.84 129.077 43.872 129.259 ;
  END
END dsfd_svcio_x
END LIBRARY
